VERSION 5.7 ;
  NOWIREEXTENSIONATPIN ON ;
  DIVIDERCHAR "/" ;
  BUSBITCHARS "[]" ;
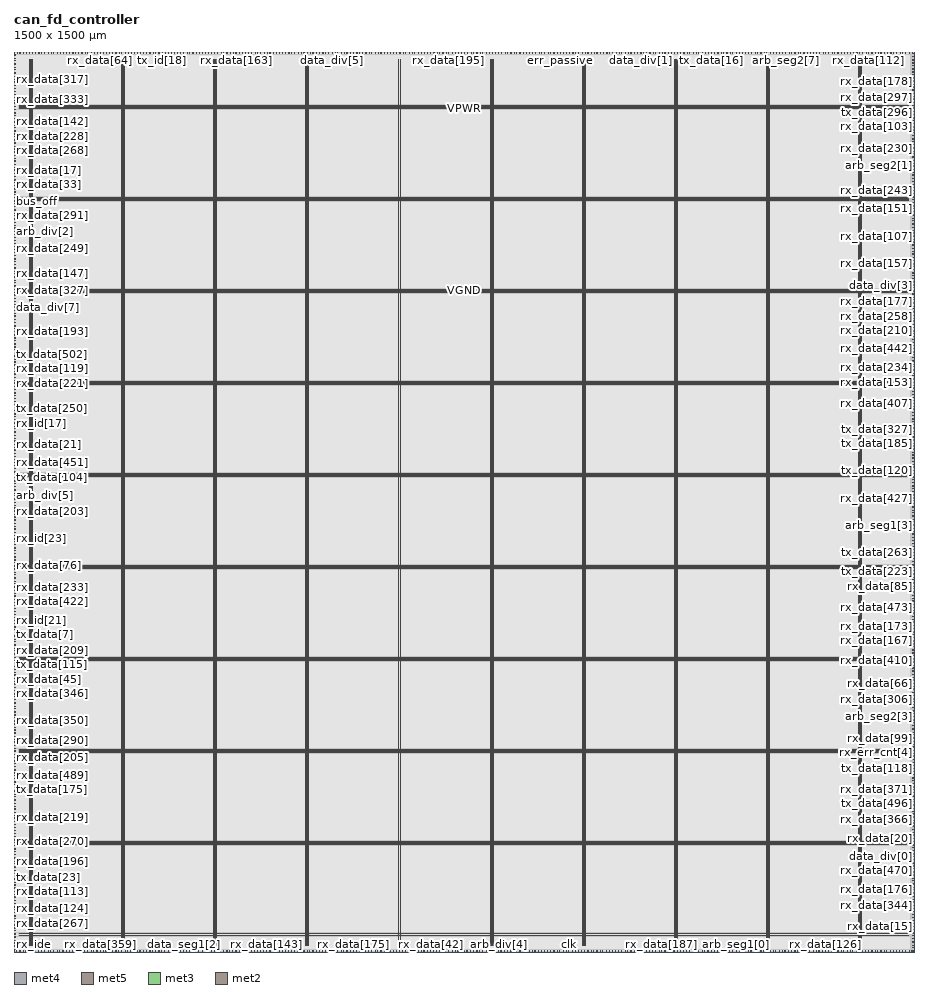
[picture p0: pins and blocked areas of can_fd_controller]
MACRO can_fd_controller
  CLASS BLOCK ;
  FOREIGN can_fd_controller ;
  ORIGIN 0.000 0.000 ;
  SIZE 1500.000 BY 1500.000 ;
  PIN VGND
    DIRECTION INOUT ;
    USE GROUND ;
    PORT
      LAYER met4 ;
        RECT 28.940 10.640 30.540 1488.080 ;
    END
    PORT
      LAYER met4 ;
        RECT 182.540 10.640 184.140 1488.080 ;
    END
    PORT
      LAYER met4 ;
        RECT 336.140 10.640 337.740 1488.080 ;
    END
    PORT
      LAYER met4 ;
        RECT 489.740 10.640 491.340 1488.080 ;
    END
    PORT
      LAYER met4 ;
        RECT 643.340 10.640 644.940 1488.080 ;
    END
    PORT
      LAYER met4 ;
        RECT 796.940 10.640 798.540 1488.080 ;
    END
    PORT
      LAYER met4 ;
        RECT 950.540 10.640 952.140 1488.080 ;
    END
    PORT
      LAYER met4 ;
        RECT 1104.140 10.640 1105.740 1488.080 ;
    END
    PORT
      LAYER met4 ;
        RECT 1257.740 10.640 1259.340 1488.080 ;
    END
    PORT
      LAYER met4 ;
        RECT 1411.340 10.640 1412.940 1488.080 ;
    END
    PORT
      LAYER met5 ;
        RECT 9.880 30.030 1490.180 31.630 ;
    END
    PORT
      LAYER met5 ;
        RECT 9.880 183.210 1490.180 184.810 ;
    END
    PORT
      LAYER met5 ;
        RECT 9.880 336.390 1490.180 337.990 ;
    END
    PORT
      LAYER met5 ;
        RECT 9.880 489.570 1490.180 491.170 ;
    END
    PORT
      LAYER met5 ;
        RECT 9.880 642.750 1490.180 644.350 ;
    END
    PORT
      LAYER met5 ;
        RECT 9.880 795.930 1490.180 797.530 ;
    END
    PORT
      LAYER met5 ;
        RECT 9.880 949.110 1490.180 950.710 ;
    END
    PORT
      LAYER met5 ;
        RECT 9.880 1102.290 1490.180 1103.890 ;
    END
    PORT
      LAYER met5 ;
        RECT 9.880 1255.470 1490.180 1257.070 ;
    END
    PORT
      LAYER met5 ;
        RECT 9.880 1408.650 1490.180 1410.250 ;
    END
  END VGND
  PIN VPWR
    DIRECTION INOUT ;
    USE POWER ;
    PORT
      LAYER met4 ;
        RECT 25.640 10.640 27.240 1488.080 ;
    END
    PORT
      LAYER met4 ;
        RECT 179.240 10.640 180.840 1488.080 ;
    END
    PORT
      LAYER met4 ;
        RECT 332.840 10.640 334.440 1488.080 ;
    END
    PORT
      LAYER met4 ;
        RECT 486.440 10.640 488.040 1488.080 ;
    END
    PORT
      LAYER met4 ;
        RECT 640.040 10.640 641.640 1488.080 ;
    END
    PORT
      LAYER met4 ;
        RECT 793.640 10.640 795.240 1488.080 ;
    END
    PORT
      LAYER met4 ;
        RECT 947.240 10.640 948.840 1488.080 ;
    END
    PORT
      LAYER met4 ;
        RECT 1100.840 10.640 1102.440 1488.080 ;
    END
    PORT
      LAYER met4 ;
        RECT 1254.440 10.640 1256.040 1488.080 ;
    END
    PORT
      LAYER met4 ;
        RECT 1408.040 10.640 1409.640 1488.080 ;
    END
    PORT
      LAYER met5 ;
        RECT 9.880 26.730 1490.180 28.330 ;
    END
    PORT
      LAYER met5 ;
        RECT 9.880 179.910 1490.180 181.510 ;
    END
    PORT
      LAYER met5 ;
        RECT 9.880 333.090 1490.180 334.690 ;
    END
    PORT
      LAYER met5 ;
        RECT 9.880 486.270 1490.180 487.870 ;
    END
    PORT
      LAYER met5 ;
        RECT 9.880 639.450 1490.180 641.050 ;
    END
    PORT
      LAYER met5 ;
        RECT 9.880 792.630 1490.180 794.230 ;
    END
    PORT
      LAYER met5 ;
        RECT 9.880 945.810 1490.180 947.410 ;
    END
    PORT
      LAYER met5 ;
        RECT 9.880 1098.990 1490.180 1100.590 ;
    END
    PORT
      LAYER met5 ;
        RECT 9.880 1252.170 1490.180 1253.770 ;
    END
    PORT
      LAYER met5 ;
        RECT 9.880 1405.350 1490.180 1406.950 ;
    END
  END VPWR
  PIN arb_div[0]
    DIRECTION INPUT ;
    USE SIGNAL ;
    ANTENNAGATEAREA 0.196500 ;
    PORT
      LAYER met3 ;
        RECT 1498.000 828.280 1500.000 828.880 ;
    END
  END arb_div[0]
  PIN arb_div[1]
    DIRECTION INPUT ;
    USE SIGNAL ;
    ANTENNAGATEAREA 0.990000 ;
    PORT
      LAYER met3 ;
        RECT 1498.000 1218.600 1500.000 1219.200 ;
    END
  END arb_div[1]
  PIN arb_div[2]
    DIRECTION INPUT ;
    USE SIGNAL ;
    ANTENNAGATEAREA 0.247500 ;
    PORT
      LAYER met3 ;
        RECT 0.000 1200.920 2.000 1201.520 ;
    END
  END arb_div[2]
  PIN arb_div[3]
    DIRECTION INPUT ;
    USE SIGNAL ;
    ANTENNAGATEAREA 0.495000 ;
    PORT
      LAYER met2 ;
        RECT 231.930 1498.000 232.210 1500.000 ;
    END
  END arb_div[3]
  PIN arb_div[4]
    DIRECTION INPUT ;
    USE SIGNAL ;
    ANTENNAGATEAREA 0.990000 ;
    PORT
      LAYER met2 ;
        RECT 807.390 0.000 807.670 2.000 ;
    END
  END arb_div[4]
  PIN arb_div[5]
    DIRECTION INPUT ;
    USE SIGNAL ;
    ANTENNAGATEAREA 0.159000 ;
    PORT
      LAYER met3 ;
        RECT 0.000 760.280 2.000 760.880 ;
    END
  END arb_div[5]
  PIN arb_div[6]
    DIRECTION INPUT ;
    USE SIGNAL ;
    ANTENNAGATEAREA 0.213000 ;
    PORT
      LAYER met3 ;
        RECT 0.000 572.600 2.000 573.200 ;
    END
  END arb_div[6]
  PIN arb_div[7]
    DIRECTION INPUT ;
    USE SIGNAL ;
    ANTENNAGATEAREA 0.742500 ;
    PORT
      LAYER met3 ;
        RECT 1498.000 640.600 1500.000 641.200 ;
    END
  END arb_div[7]
  PIN arb_seg1[0]
    DIRECTION INPUT ;
    USE SIGNAL ;
    ANTENNAGATEAREA 0.990000 ;
    PORT
      LAYER met2 ;
        RECT 1203.450 0.000 1203.730 2.000 ;
    END
  END arb_seg1[0]
  PIN arb_seg1[1]
    DIRECTION INPUT ;
    USE SIGNAL ;
    ANTENNAGATEAREA 0.247500 ;
    PORT
      LAYER met3 ;
        RECT 0.000 349.560 2.000 350.160 ;
    END
  END arb_seg1[1]
  PIN arb_seg1[2]
    DIRECTION INPUT ;
    USE SIGNAL ;
    ANTENNAGATEAREA 0.742500 ;
    PORT
      LAYER met2 ;
        RECT 888.810 0.000 889.090 2.000 ;
    END
  END arb_seg1[2]
  PIN arb_seg1[3]
    DIRECTION INPUT ;
    USE SIGNAL ;
    ANTENNAGATEAREA 0.742500 ;
    PORT
      LAYER met3 ;
        RECT 1498.000 711.320 1500.000 711.920 ;
    END
  END arb_seg1[3]
  PIN arb_seg1[4]
    DIRECTION INPUT ;
    USE SIGNAL ;
    ANTENNAGATEAREA 0.159000 ;
    PORT
      LAYER met3 ;
        RECT 0.000 1221.320 2.000 1221.920 ;
    END
  END arb_seg1[4]
  PIN arb_seg1[5]
    DIRECTION INPUT ;
    USE SIGNAL ;
    ANTENNAGATEAREA 0.213000 ;
    PORT
      LAYER met3 ;
        RECT 0.000 567.160 2.000 567.760 ;
    END
  END arb_seg1[5]
  PIN arb_seg1[6]
    DIRECTION INPUT ;
    USE SIGNAL ;
    ANTENNAGATEAREA 0.990000 ;
    PORT
      LAYER met2 ;
        RECT 822.570 0.000 822.850 2.000 ;
    END
  END arb_seg1[6]
  PIN arb_seg1[7]
    DIRECTION INPUT ;
    USE SIGNAL ;
    ANTENNAGATEAREA 0.990000 ;
    PORT
      LAYER met2 ;
        RECT 1188.270 0.000 1188.550 2.000 ;
    END
  END arb_seg1[7]
  PIN arb_seg2[0]
    DIRECTION INPUT ;
    USE SIGNAL ;
    PORT
      LAYER met2 ;
        RECT 781.170 1498.000 781.450 1500.000 ;
    END
  END arb_seg2[0]
  PIN arb_seg2[1]
    DIRECTION INPUT ;
    USE SIGNAL ;
    PORT
      LAYER met3 ;
        RECT 1498.000 1309.720 1500.000 1310.320 ;
    END
  END arb_seg2[1]
  PIN arb_seg2[2]
    DIRECTION INPUT ;
    USE SIGNAL ;
    PORT
      LAYER met2 ;
        RECT 1228.290 0.000 1228.570 2.000 ;
    END
  END arb_seg2[2]
  PIN arb_seg2[3]
    DIRECTION INPUT ;
    USE SIGNAL ;
    PORT
      LAYER met3 ;
        RECT 1498.000 391.720 1500.000 392.320 ;
    END
  END arb_seg2[3]
  PIN arb_seg2[4]
    DIRECTION INPUT ;
    USE SIGNAL ;
    PORT
      LAYER met3 ;
        RECT 1498.000 1172.360 1500.000 1172.960 ;
    END
  END arb_seg2[4]
  PIN arb_seg2[5]
    DIRECTION INPUT ;
    USE SIGNAL ;
    PORT
      LAYER met2 ;
        RECT 992.310 1498.000 992.590 1500.000 ;
    END
  END arb_seg2[5]
  PIN arb_seg2[6]
    DIRECTION INPUT ;
    USE SIGNAL ;
    PORT
      LAYER met2 ;
        RECT 358.890 0.000 359.170 2.000 ;
    END
  END arb_seg2[6]
  PIN arb_seg2[7]
    DIRECTION INPUT ;
    USE SIGNAL ;
    PORT
      LAYER met2 ;
        RECT 1286.250 1498.000 1286.530 1500.000 ;
    END
  END arb_seg2[7]
  PIN bus_off
    DIRECTION OUTPUT TRISTATE ;
    USE SIGNAL ;
    PORT
      LAYER met3 ;
        RECT 0.000 1251.240 2.000 1251.840 ;
    END
  END bus_off
  PIN can_rx
    DIRECTION INPUT ;
    USE SIGNAL ;
    ANTENNAGATEAREA 0.852000 ;
    PORT
      LAYER met2 ;
        RECT 956.430 0.000 956.710 2.000 ;
    END
  END can_rx
  PIN can_tx
    DIRECTION OUTPUT TRISTATE ;
    USE SIGNAL ;
    ANTENNADIFFAREA 0.795200 ;
    PORT
      LAYER met2 ;
        RECT 1265.550 0.000 1265.830 2.000 ;
    END
  END can_tx
  PIN clk
    DIRECTION INPUT ;
    USE SIGNAL ;
    ANTENNAGATEAREA 0.852000 ;
    PORT
      LAYER met2 ;
        RECT 924.690 0.000 924.970 2.000 ;
    END
  END clk
  PIN data_div[0]
    DIRECTION INPUT ;
    USE SIGNAL ;
    ANTENNAGATEAREA 0.247500 ;
    PORT
      LAYER met3 ;
        RECT 1498.000 159.160 1500.000 159.760 ;
    END
  END data_div[0]
  PIN data_div[1]
    DIRECTION INPUT ;
    USE SIGNAL ;
    ANTENNAGATEAREA 0.990000 ;
    PORT
      LAYER met2 ;
        RECT 1044.750 1498.000 1045.030 1500.000 ;
    END
  END data_div[1]
  PIN data_div[2]
    DIRECTION INPUT ;
    USE SIGNAL ;
    ANTENNAGATEAREA 0.426000 ;
    PORT
      LAYER met3 ;
        RECT 0.000 1398.120 2.000 1398.720 ;
    END
  END data_div[2]
  PIN data_div[3]
    DIRECTION INPUT ;
    USE SIGNAL ;
    ANTENNAGATEAREA 0.990000 ;
    PORT
      LAYER met3 ;
        RECT 1498.000 1111.160 1500.000 1111.760 ;
    END
  END data_div[3]
  PIN data_div[4]
    DIRECTION INPUT ;
    USE SIGNAL ;
    ANTENNAGATEAREA 0.213000 ;
    PORT
      LAYER met3 ;
        RECT 0.000 1007.800 2.000 1008.400 ;
    END
  END data_div[4]
  PIN data_div[5]
    DIRECTION INPUT ;
    USE SIGNAL ;
    ANTENNAGATEAREA 0.742500 ;
    PORT
      LAYER met2 ;
        RECT 530.010 1498.000 530.290 1500.000 ;
    END
  END data_div[5]
  PIN data_div[6]
    DIRECTION INPUT ;
    USE SIGNAL ;
    ANTENNAGATEAREA 0.990000 ;
    PORT
      LAYER met3 ;
        RECT 1498.000 1066.280 1500.000 1066.880 ;
    END
  END data_div[6]
  PIN data_div[7]
    DIRECTION INPUT ;
    USE SIGNAL ;
    ANTENNAGATEAREA 0.247500 ;
    PORT
      LAYER met3 ;
        RECT 0.000 1074.440 2.000 1075.040 ;
    END
  END data_div[7]
  PIN data_seg1[0]
    DIRECTION INPUT ;
    USE SIGNAL ;
    ANTENNAGATEAREA 0.213000 ;
    PORT
      LAYER met3 ;
        RECT 0.000 840.520 2.000 841.120 ;
    END
  END data_seg1[0]
  PIN data_seg1[1]
    DIRECTION INPUT ;
    USE SIGNAL ;
    ANTENNAGATEAREA 0.990000 ;
    PORT
      LAYER met2 ;
        RECT 1393.890 1498.000 1394.170 1500.000 ;
    END
  END data_seg1[1]
  PIN data_seg1[2]
    DIRECTION INPUT ;
    USE SIGNAL ;
    ANTENNAGATEAREA 0.426000 ;
    PORT
      LAYER met2 ;
        RECT 282.990 0.000 283.270 2.000 ;
    END
  END data_seg1[2]
  PIN data_seg1[3]
    DIRECTION INPUT ;
    USE SIGNAL ;
    ANTENNAGATEAREA 0.990000 ;
    PORT
      LAYER met2 ;
        RECT 1373.190 1498.000 1373.470 1500.000 ;
    END
  END data_seg1[3]
  PIN data_seg1[4]
    DIRECTION INPUT ;
    USE SIGNAL ;
    ANTENNAGATEAREA 0.213000 ;
    PORT
      LAYER met2 ;
        RECT 509.310 1498.000 509.590 1500.000 ;
    END
  END data_seg1[4]
  PIN data_seg1[5]
    DIRECTION INPUT ;
    USE SIGNAL ;
    ANTENNAGATEAREA 0.159000 ;
    PORT
      LAYER met3 ;
        RECT 0.000 1119.320 2.000 1119.920 ;
    END
  END data_seg1[5]
  PIN data_seg1[6]
    DIRECTION INPUT ;
    USE SIGNAL ;
    ANTENNAGATEAREA 0.495000 ;
    PORT
      LAYER met2 ;
        RECT 158.790 1498.000 159.070 1500.000 ;
    END
  END data_seg1[6]
  PIN data_seg1[7]
    DIRECTION INPUT ;
    USE SIGNAL ;
    ANTENNAGATEAREA 0.990000 ;
    PORT
      LAYER met3 ;
        RECT 1498.000 341.400 1500.000 342.000 ;
    END
  END data_seg1[7]
  PIN data_seg2[0]
    DIRECTION INPUT ;
    USE SIGNAL ;
    PORT
      LAYER met2 ;
        RECT 71.850 1498.000 72.130 1500.000 ;
    END
  END data_seg2[0]
  PIN data_seg2[1]
    DIRECTION INPUT ;
    USE SIGNAL ;
    PORT
      LAYER met2 ;
        RECT 138.090 0.000 138.370 2.000 ;
    END
  END data_seg2[1]
  PIN data_seg2[2]
    DIRECTION INPUT ;
    USE SIGNAL ;
    PORT
      LAYER met3 ;
        RECT 1498.000 1477.000 1500.000 1477.600 ;
    END
  END data_seg2[2]
  PIN data_seg2[3]
    DIRECTION INPUT ;
    USE SIGNAL ;
    PORT
      LAYER met3 ;
        RECT 0.000 1210.440 2.000 1211.040 ;
    END
  END data_seg2[3]
  PIN data_seg2[4]
    DIRECTION INPUT ;
    USE SIGNAL ;
    PORT
      LAYER met3 ;
        RECT 0.000 1277.080 2.000 1277.680 ;
    END
  END data_seg2[4]
  PIN data_seg2[5]
    DIRECTION INPUT ;
    USE SIGNAL ;
    PORT
      LAYER met3 ;
        RECT 0.000 1485.160 2.000 1485.760 ;
    END
  END data_seg2[5]
  PIN data_seg2[6]
    DIRECTION INPUT ;
    USE SIGNAL ;
    PORT
      LAYER met2 ;
        RECT 607.290 1498.000 607.570 1500.000 ;
    END
  END data_seg2[6]
  PIN data_seg2[7]
    DIRECTION INPUT ;
    USE SIGNAL ;
    PORT
      LAYER met2 ;
        RECT 909.510 0.000 909.790 2.000 ;
    END
  END data_seg2[7]
  PIN err_passive
    DIRECTION OUTPUT TRISTATE ;
    USE SIGNAL ;
    ANTENNADIFFAREA 0.795200 ;
    PORT
      LAYER met2 ;
        RECT 910.890 1498.000 911.170 1500.000 ;
    END
  END err_passive
  PIN err_warning
    DIRECTION OUTPUT TRISTATE ;
    USE SIGNAL ;
    ANTENNADIFFAREA 0.795200 ;
    PORT
      LAYER met3 ;
        RECT 1498.000 27.240 1500.000 27.840 ;
    END
  END err_warning
  PIN rst_n
    DIRECTION INPUT ;
    USE SIGNAL ;
    ANTENNAGATEAREA 0.213000 ;
    PORT
      LAYER met3 ;
        RECT 1498.000 690.920 1500.000 691.520 ;
    END
  END rst_n
  PIN rx_ack
    DIRECTION INPUT ;
    USE SIGNAL ;
    ANTENNAGATEAREA 0.990000 ;
    PORT
      LAYER met2 ;
        RECT 884.670 0.000 884.950 2.000 ;
    END
  END rx_ack
  PIN rx_brs
    DIRECTION OUTPUT TRISTATE ;
    USE SIGNAL ;
    ANTENNADIFFAREA 0.795200 ;
    PORT
      LAYER met2 ;
        RECT 154.650 1498.000 154.930 1500.000 ;
    END
  END rx_brs
  PIN rx_busy
    DIRECTION OUTPUT TRISTATE ;
    USE SIGNAL ;
    ANTENNADIFFAREA 0.795200 ;
    PORT
      LAYER met2 ;
        RECT 524.490 1498.000 524.770 1500.000 ;
    END
  END rx_busy
  PIN rx_data[0]
    DIRECTION OUTPUT TRISTATE ;
    USE SIGNAL ;
    ANTENNADIFFAREA 0.795200 ;
    PORT
      LAYER met2 ;
        RECT 1348.350 1498.000 1348.630 1500.000 ;
    END
  END rx_data[0]
  PIN rx_data[100]
    DIRECTION OUTPUT TRISTATE ;
    USE SIGNAL ;
    ANTENNADIFFAREA 0.795200 ;
    PORT
      LAYER met2 ;
        RECT 817.050 0.000 817.330 2.000 ;
    END
  END rx_data[100]
  PIN rx_data[101]
    DIRECTION OUTPUT TRISTATE ;
    USE SIGNAL ;
    ANTENNADIFFAREA 0.795200 ;
    PORT
      LAYER met2 ;
        RECT 754.950 0.000 755.230 2.000 ;
    END
  END rx_data[101]
  PIN rx_data[102]
    DIRECTION OUTPUT TRISTATE ;
    USE SIGNAL ;
    ANTENNADIFFAREA 0.795200 ;
    PORT
      LAYER met3 ;
        RECT 1498.000 908.520 1500.000 909.120 ;
    END
  END rx_data[102]
  PIN rx_data[103]
    DIRECTION OUTPUT TRISTATE ;
    USE SIGNAL ;
    ANTENNADIFFAREA 0.795200 ;
    PORT
      LAYER met3 ;
        RECT 1498.000 1375.000 1500.000 1375.600 ;
    END
  END rx_data[103]
  PIN rx_data[104]
    DIRECTION OUTPUT TRISTATE ;
    USE SIGNAL ;
    ANTENNADIFFAREA 0.795200 ;
    PORT
      LAYER met2 ;
        RECT 1001.970 0.000 1002.250 2.000 ;
    END
  END rx_data[104]
  PIN rx_data[105]
    DIRECTION OUTPUT TRISTATE ;
    USE SIGNAL ;
    ANTENNADIFFAREA 0.795200 ;
    PORT
      LAYER met3 ;
        RECT 0.000 896.280 2.000 896.880 ;
    END
  END rx_data[105]
  PIN rx_data[106]
    DIRECTION OUTPUT TRISTATE ;
    USE SIGNAL ;
    ANTENNADIFFAREA 0.795200 ;
    PORT
      LAYER met2 ;
        RECT 854.310 1498.000 854.590 1500.000 ;
    END
  END rx_data[106]
  PIN rx_data[107]
    DIRECTION OUTPUT TRISTATE ;
    USE SIGNAL ;
    ANTENNADIFFAREA 0.795200 ;
    PORT
      LAYER met3 ;
        RECT 1498.000 1192.760 1500.000 1193.360 ;
    END
  END rx_data[107]
  PIN rx_data[108]
    DIRECTION OUTPUT TRISTATE ;
    USE SIGNAL ;
    ANTENNADIFFAREA 0.795200 ;
    PORT
      LAYER met3 ;
        RECT 0.000 916.680 2.000 917.280 ;
    END
  END rx_data[108]
  PIN rx_data[109]
    DIRECTION OUTPUT TRISTATE ;
    USE SIGNAL ;
    ANTENNADIFFAREA 0.795200 ;
    PORT
      LAYER met3 ;
        RECT 1498.000 87.080 1500.000 87.680 ;
    END
  END rx_data[109]
  PIN rx_data[10]
    DIRECTION OUTPUT TRISTATE ;
    USE SIGNAL ;
    ANTENNADIFFAREA 0.795200 ;
    PORT
      LAYER met2 ;
        RECT 714.930 0.000 715.210 2.000 ;
    END
  END rx_data[10]
  PIN rx_data[110]
    DIRECTION OUTPUT TRISTATE ;
    USE SIGNAL ;
    ANTENNADIFFAREA 0.795200 ;
    PORT
      LAYER met2 ;
        RECT 1384.230 1498.000 1384.510 1500.000 ;
    END
  END rx_data[110]
  PIN rx_data[111]
    DIRECTION OUTPUT TRISTATE ;
    USE SIGNAL ;
    ANTENNADIFFAREA 0.795200 ;
    PORT
      LAYER met2 ;
        RECT 560.370 1498.000 560.650 1500.000 ;
    END
  END rx_data[111]
  PIN rx_data[112]
    DIRECTION OUTPUT TRISTATE ;
    USE SIGNAL ;
    ANTENNADIFFAREA 0.795200 ;
    PORT
      LAYER met2 ;
        RECT 1424.250 1498.000 1424.530 1500.000 ;
    END
  END rx_data[112]
  PIN rx_data[113]
    DIRECTION OUTPUT TRISTATE ;
    USE SIGNAL ;
    ANTENNADIFFAREA 0.795200 ;
    PORT
      LAYER met3 ;
        RECT 0.000 100.680 2.000 101.280 ;
    END
  END rx_data[113]
  PIN rx_data[114]
    DIRECTION OUTPUT TRISTATE ;
    USE SIGNAL ;
    ANTENNADIFFAREA 0.795200 ;
    PORT
      LAYER met2 ;
        RECT 1024.050 1498.000 1024.330 1500.000 ;
    END
  END rx_data[114]
  PIN rx_data[115]
    DIRECTION OUTPUT TRISTATE ;
    USE SIGNAL ;
    ANTENNADIFFAREA 0.795200 ;
    PORT
      LAYER met3 ;
        RECT 1498.000 457.000 1500.000 457.600 ;
    END
  END rx_data[115]
  PIN rx_data[116]
    DIRECTION OUTPUT TRISTATE ;
    USE SIGNAL ;
    ANTENNADIFFAREA 0.795200 ;
    PORT
      LAYER met2 ;
        RECT 1486.350 1498.000 1486.630 1500.000 ;
    END
  END rx_data[116]
  PIN rx_data[117]
    DIRECTION OUTPUT TRISTATE ;
    USE SIGNAL ;
    ANTENNADIFFAREA 0.795200 ;
    PORT
      LAYER met3 ;
        RECT 1498.000 122.440 1500.000 123.040 ;
    END
  END rx_data[117]
  PIN rx_data[118]
    DIRECTION OUTPUT TRISTATE ;
    USE SIGNAL ;
    ANTENNADIFFAREA 0.795200 ;
    PORT
      LAYER met2 ;
        RECT 209.850 0.000 210.130 2.000 ;
    END
  END rx_data[118]
  PIN rx_data[119]
    DIRECTION OUTPUT TRISTATE ;
    USE SIGNAL ;
    ANTENNADIFFAREA 0.795200 ;
    PORT
      LAYER met3 ;
        RECT 0.000 972.440 2.000 973.040 ;
    END
  END rx_data[119]
  PIN rx_data[11]
    DIRECTION OUTPUT TRISTATE ;
    USE SIGNAL ;
    ANTENNADIFFAREA 0.795200 ;
    PORT
      LAYER met2 ;
        RECT 277.470 0.000 277.750 2.000 ;
    END
  END rx_data[11]
  PIN rx_data[120]
    DIRECTION OUTPUT TRISTATE ;
    USE SIGNAL ;
    ANTENNADIFFAREA 0.795200 ;
    PORT
      LAYER met3 ;
        RECT 0.000 907.160 2.000 907.760 ;
    END
  END rx_data[120]
  PIN rx_data[121]
    DIRECTION OUTPUT TRISTATE ;
    USE SIGNAL ;
    ANTENNADIFFAREA 0.795200 ;
    PORT
      LAYER met3 ;
        RECT 0.000 29.960 2.000 30.560 ;
    END
  END rx_data[121]
  PIN rx_data[122]
    DIRECTION OUTPUT TRISTATE ;
    USE SIGNAL ;
    ANTENNADIFFAREA 0.795200 ;
    PORT
      LAYER met2 ;
        RECT 1461.510 1498.000 1461.790 1500.000 ;
    END
  END rx_data[122]
  PIN rx_data[123]
    DIRECTION OUTPUT TRISTATE ;
    USE SIGNAL ;
    ANTENNADIFFAREA 0.795200 ;
    PORT
      LAYER met2 ;
        RECT 1316.610 0.000 1316.890 2.000 ;
    END
  END rx_data[123]
  PIN rx_data[124]
    DIRECTION OUTPUT TRISTATE ;
    USE SIGNAL ;
    ANTENNADIFFAREA 0.795200 ;
    PORT
      LAYER met3 ;
        RECT 0.000 85.720 2.000 86.320 ;
    END
  END rx_data[124]
  PIN rx_data[125]
    DIRECTION OUTPUT TRISTATE ;
    USE SIGNAL ;
    ANTENNADIFFAREA 0.795200 ;
    PORT
      LAYER met3 ;
        RECT 1498.000 153.720 1500.000 154.320 ;
    END
  END rx_data[125]
  PIN rx_data[126]
    DIRECTION OUTPUT TRISTATE ;
    USE SIGNAL ;
    ANTENNADIFFAREA 0.795200 ;
    PORT
      LAYER met2 ;
        RECT 1352.490 0.000 1352.770 2.000 ;
    END
  END rx_data[126]
  PIN rx_data[127]
    DIRECTION OUTPUT TRISTATE ;
    USE SIGNAL ;
    ANTENNADIFFAREA 0.795200 ;
    PORT
      LAYER met3 ;
        RECT 1498.000 787.480 1500.000 788.080 ;
    END
  END rx_data[127]
  PIN rx_data[128]
    DIRECTION OUTPUT TRISTATE ;
    USE SIGNAL ;
    ANTENNADIFFAREA 0.795200 ;
    PORT
      LAYER met3 ;
        RECT 0.000 557.640 2.000 558.240 ;
    END
  END rx_data[128]
  PIN rx_data[129]
    DIRECTION OUTPUT TRISTATE ;
    USE SIGNAL ;
    ANTENNADIFFAREA 0.795200 ;
    PORT
      LAYER met2 ;
        RECT 1028.190 1498.000 1028.470 1500.000 ;
    END
  END rx_data[129]
  PIN rx_data[12]
    DIRECTION OUTPUT TRISTATE ;
    USE SIGNAL ;
    ANTENNADIFFAREA 0.795200 ;
    PORT
      LAYER met2 ;
        RECT 0.090 1498.000 0.370 1500.000 ;
    END
  END rx_data[12]
  PIN rx_data[130]
    DIRECTION OUTPUT TRISTATE ;
    USE SIGNAL ;
    ANTENNADIFFAREA 0.795200 ;
    PORT
      LAYER met3 ;
        RECT 1498.000 285.640 1500.000 286.240 ;
    END
  END rx_data[130]
  PIN rx_data[131]
    DIRECTION OUTPUT TRISTATE ;
    USE SIGNAL ;
    ANTENNADIFFAREA 0.795200 ;
    PORT
      LAYER met3 ;
        RECT 0.000 652.840 2.000 653.440 ;
    END
  END rx_data[131]
  PIN rx_data[132]
    DIRECTION OUTPUT TRISTATE ;
    USE SIGNAL ;
    ANTENNADIFFAREA 0.795200 ;
    PORT
      LAYER met2 ;
        RECT 796.350 0.000 796.630 2.000 ;
    END
  END rx_data[132]
  PIN rx_data[133]
    DIRECTION OUTPUT TRISTATE ;
    USE SIGNAL ;
    ANTENNADIFFAREA 0.795200 ;
    PORT
      LAYER met2 ;
        RECT 1429.770 0.000 1430.050 2.000 ;
    END
  END rx_data[133]
  PIN rx_data[134]
    DIRECTION OUTPUT TRISTATE ;
    USE SIGNAL ;
    ANTENNADIFFAREA 0.795200 ;
    PORT
      LAYER met3 ;
        RECT 1498.000 1466.120 1500.000 1466.720 ;
    END
  END rx_data[134]
  PIN rx_data[135]
    DIRECTION OUTPUT TRISTATE ;
    USE SIGNAL ;
    ANTENNADIFFAREA 0.795200 ;
    PORT
      LAYER met2 ;
        RECT 698.370 0.000 698.650 2.000 ;
    END
  END rx_data[135]
  PIN rx_data[136]
    DIRECTION OUTPUT TRISTATE ;
    USE SIGNAL ;
    ANTENNADIFFAREA 0.795200 ;
    PORT
      LAYER met2 ;
        RECT 1182.750 1498.000 1183.030 1500.000 ;
    END
  END rx_data[136]
  PIN rx_data[137]
    DIRECTION OUTPUT TRISTATE ;
    USE SIGNAL ;
    ANTENNADIFFAREA 0.795200 ;
    PORT
      LAYER met3 ;
        RECT 0.000 1342.360 2.000 1342.960 ;
    END
  END rx_data[137]
  PIN rx_data[138]
    DIRECTION OUTPUT TRISTATE ;
    USE SIGNAL ;
    ANTENNADIFFAREA 0.795200 ;
    PORT
      LAYER met2 ;
        RECT 1101.330 1498.000 1101.610 1500.000 ;
    END
  END rx_data[138]
  PIN rx_data[139]
    DIRECTION OUTPUT TRISTATE ;
    USE SIGNAL ;
    ANTENNADIFFAREA 0.795200 ;
    PORT
      LAYER met3 ;
        RECT 1498.000 1274.360 1500.000 1274.960 ;
    END
  END rx_data[139]
  PIN rx_data[13]
    DIRECTION OUTPUT TRISTATE ;
    USE SIGNAL ;
    ANTENNADIFFAREA 0.795200 ;
    PORT
      LAYER met2 ;
        RECT 467.910 1498.000 468.190 1500.000 ;
    END
  END rx_data[13]
  PIN rx_data[140]
    DIRECTION OUTPUT TRISTATE ;
    USE SIGNAL ;
    ANTENNADIFFAREA 0.795200 ;
    PORT
      LAYER met2 ;
        RECT 1167.570 1498.000 1167.850 1500.000 ;
    END
  END rx_data[140]
  PIN rx_data[141]
    DIRECTION OUTPUT TRISTATE ;
    USE SIGNAL ;
    ANTENNADIFFAREA 0.795200 ;
    PORT
      LAYER met3 ;
        RECT 0.000 1165.560 2.000 1166.160 ;
    END
  END rx_data[141]
  PIN rx_data[142]
    DIRECTION OUTPUT TRISTATE ;
    USE SIGNAL ;
    ANTENNADIFFAREA 0.795200 ;
    PORT
      LAYER met3 ;
        RECT 0.000 1383.160 2.000 1383.760 ;
    END
  END rx_data[142]
  PIN rx_data[143]
    DIRECTION OUTPUT TRISTATE ;
    USE SIGNAL ;
    ANTENNADIFFAREA 0.795200 ;
    PORT
      LAYER met2 ;
        RECT 420.990 0.000 421.270 2.000 ;
    END
  END rx_data[143]
  PIN rx_data[144]
    DIRECTION OUTPUT TRISTATE ;
    USE SIGNAL ;
    ANTENNADIFFAREA 0.795200 ;
    PORT
      LAYER met3 ;
        RECT 1498.000 274.760 1500.000 275.360 ;
    END
  END rx_data[144]
  PIN rx_data[145]
    DIRECTION OUTPUT TRISTATE ;
    USE SIGNAL ;
    ANTENNADIFFAREA 0.795200 ;
    PORT
      LAYER met3 ;
        RECT 1498.000 1187.320 1500.000 1187.920 ;
    END
  END rx_data[145]
  PIN rx_data[146]
    DIRECTION OUTPUT TRISTATE ;
    USE SIGNAL ;
    ANTENNADIFFAREA 0.795200 ;
    PORT
      LAYER met3 ;
        RECT 0.000 409.400 2.000 410.000 ;
    END
  END rx_data[146]
  PIN rx_data[147]
    DIRECTION OUTPUT TRISTATE ;
    USE SIGNAL ;
    ANTENNADIFFAREA 0.795200 ;
    PORT
      LAYER met3 ;
        RECT 0.000 1130.200 2.000 1130.800 ;
    END
  END rx_data[147]
  PIN rx_data[148]
    DIRECTION OUTPUT TRISTATE ;
    USE SIGNAL ;
    ANTENNADIFFAREA 0.795200 ;
    PORT
      LAYER met2 ;
        RECT 426.510 0.000 426.790 2.000 ;
    END
  END rx_data[148]
  PIN rx_data[149]
    DIRECTION OUTPUT TRISTATE ;
    USE SIGNAL ;
    ANTENNADIFFAREA 0.795200 ;
    PORT
      LAYER met3 ;
        RECT 1498.000 244.840 1500.000 245.440 ;
    END
  END rx_data[149]
  PIN rx_data[14]
    DIRECTION OUTPUT TRISTATE ;
    USE SIGNAL ;
    ANTENNADIFFAREA 0.795200 ;
    PORT
      LAYER met2 ;
        RECT 307.830 0.000 308.110 2.000 ;
    END
  END rx_data[14]
  PIN rx_data[150]
    DIRECTION OUTPUT TRISTATE ;
    USE SIGNAL ;
    ANTENNADIFFAREA 0.795200 ;
    PORT
      LAYER met3 ;
        RECT 1498.000 726.280 1500.000 726.880 ;
    END
  END rx_data[150]
  PIN rx_data[151]
    DIRECTION OUTPUT TRISTATE ;
    USE SIGNAL ;
    ANTENNADIFFAREA 0.795200 ;
    PORT
      LAYER met3 ;
        RECT 1498.000 1239.000 1500.000 1239.600 ;
    END
  END rx_data[151]
  PIN rx_data[152]
    DIRECTION OUTPUT TRISTATE ;
    USE SIGNAL ;
    ANTENNADIFFAREA 0.795200 ;
    PORT
      LAYER met3 ;
        RECT 0.000 405.320 2.000 405.920 ;
    END
  END rx_data[152]
  PIN rx_data[153]
    DIRECTION OUTPUT TRISTATE ;
    USE SIGNAL ;
    ANTENNADIFFAREA 0.795200 ;
    PORT
      LAYER met3 ;
        RECT 1498.000 949.320 1500.000 949.920 ;
    END
  END rx_data[153]
  PIN rx_data[154]
    DIRECTION OUTPUT TRISTATE ;
    USE SIGNAL ;
    ANTENNADIFFAREA 0.795200 ;
    PORT
      LAYER met3 ;
        RECT 0.000 511.400 2.000 512.000 ;
    END
  END rx_data[154]
  PIN rx_data[155]
    DIRECTION OUTPUT TRISTATE ;
    USE SIGNAL ;
    ANTENNADIFFAREA 0.795200 ;
    PORT
      LAYER met2 ;
        RECT 4.230 0.000 4.510 2.000 ;
    END
  END rx_data[155]
  PIN rx_data[156]
    DIRECTION OUTPUT TRISTATE ;
    USE SIGNAL ;
    ANTENNADIFFAREA 0.795200 ;
    PORT
      LAYER met3 ;
        RECT 0.000 505.960 2.000 506.560 ;
    END
  END rx_data[156]
  PIN rx_data[157]
    DIRECTION OUTPUT TRISTATE ;
    USE SIGNAL ;
    ANTENNADIFFAREA 0.795200 ;
    PORT
      LAYER met3 ;
        RECT 1498.000 1146.520 1500.000 1147.120 ;
    END
  END rx_data[157]
  PIN rx_data[158]
    DIRECTION OUTPUT TRISTATE ;
    USE SIGNAL ;
    ANTENNADIFFAREA 0.795200 ;
    PORT
      LAYER met2 ;
        RECT 765.990 0.000 766.270 2.000 ;
    END
  END rx_data[158]
  PIN rx_data[159]
    DIRECTION OUTPUT TRISTATE ;
    USE SIGNAL ;
    ANTENNADIFFAREA 0.795200 ;
    PORT
      LAYER met2 ;
        RECT 19.410 0.000 19.690 2.000 ;
    END
  END rx_data[159]
  PIN rx_data[15]
    DIRECTION OUTPUT TRISTATE ;
    USE SIGNAL ;
    ANTENNADIFFAREA 0.795200 ;
    PORT
      LAYER met3 ;
        RECT 1498.000 42.200 1500.000 42.800 ;
    END
  END rx_data[15]
  PIN rx_data[160]
    DIRECTION OUTPUT TRISTATE ;
    USE SIGNAL ;
    ANTENNADIFFAREA 0.795200 ;
    PORT
      LAYER met3 ;
        RECT 0.000 353.640 2.000 354.240 ;
    END
  END rx_data[160]
  PIN rx_data[161]
    DIRECTION OUTPUT TRISTATE ;
    USE SIGNAL ;
    ANTENNADIFFAREA 0.795200 ;
    PORT
      LAYER met3 ;
        RECT 0.000 44.920 2.000 45.520 ;
    END
  END rx_data[161]
  PIN rx_data[162]
    DIRECTION OUTPUT TRISTATE ;
    USE SIGNAL ;
    ANTENNADIFFAREA 0.795200 ;
    PORT
      LAYER met2 ;
        RECT 950.910 0.000 951.190 2.000 ;
    END
  END rx_data[162]
  PIN rx_data[163]
    DIRECTION OUTPUT TRISTATE ;
    USE SIGNAL ;
    ANTENNADIFFAREA 0.795200 ;
    PORT
      LAYER met2 ;
        RECT 369.930 1498.000 370.210 1500.000 ;
    END
  END rx_data[163]
  PIN rx_data[164]
    DIRECTION OUTPUT TRISTATE ;
    USE SIGNAL ;
    ANTENNADIFFAREA 0.795200 ;
    PORT
      LAYER met3 ;
        RECT 1498.000 512.760 1500.000 513.360 ;
    END
  END rx_data[164]
  PIN rx_data[165]
    DIRECTION OUTPUT TRISTATE ;
    USE SIGNAL ;
    ANTENNADIFFAREA 0.795200 ;
    PORT
      LAYER met3 ;
        RECT 0.000 810.600 2.000 811.200 ;
    END
  END rx_data[165]
  PIN rx_data[166]
    DIRECTION OUTPUT TRISTATE ;
    USE SIGNAL ;
    ANTENNADIFFAREA 0.795200 ;
    PORT
      LAYER met3 ;
        RECT 1498.000 1380.440 1500.000 1381.040 ;
    END
  END rx_data[166]
  PIN rx_data[167]
    DIRECTION OUTPUT TRISTATE ;
    USE SIGNAL ;
    ANTENNADIFFAREA 0.795200 ;
    PORT
      LAYER met3 ;
        RECT 1498.000 518.200 1500.000 518.800 ;
    END
  END rx_data[167]
  PIN rx_data[168]
    DIRECTION OUTPUT TRISTATE ;
    USE SIGNAL ;
    ANTENNADIFFAREA 0.795200 ;
    PORT
      LAYER met3 ;
        RECT 1498.000 254.360 1500.000 254.960 ;
    END
  END rx_data[168]
  PIN rx_data[169]
    DIRECTION OUTPUT TRISTATE ;
    USE SIGNAL ;
    ANTENNADIFFAREA 0.795200 ;
    PORT
      LAYER met2 ;
        RECT 411.330 0.000 411.610 2.000 ;
    END
  END rx_data[169]
  PIN rx_data[16]
    DIRECTION OUTPUT TRISTATE ;
    USE SIGNAL ;
    ANTENNADIFFAREA 0.795200 ;
    PORT
      LAYER met2 ;
        RECT 1295.910 1498.000 1296.190 1500.000 ;
    END
  END rx_data[16]
  PIN rx_data[170]
    DIRECTION OUTPUT TRISTATE ;
    USE SIGNAL ;
    ANTENNADIFFAREA 0.795200 ;
    PORT
      LAYER met2 ;
        RECT 518.970 1498.000 519.250 1500.000 ;
    END
  END rx_data[170]
  PIN rx_data[171]
    DIRECTION OUTPUT TRISTATE ;
    USE SIGNAL ;
    ANTENNADIFFAREA 0.795200 ;
    PORT
      LAYER met3 ;
        RECT 0.000 19.080 2.000 19.680 ;
    END
  END rx_data[171]
  PIN rx_data[172]
    DIRECTION OUTPUT TRISTATE ;
    USE SIGNAL ;
    ANTENNADIFFAREA 0.795200 ;
    PORT
      LAYER met3 ;
        RECT 0.000 927.560 2.000 928.160 ;
    END
  END rx_data[172]
  PIN rx_data[173]
    DIRECTION OUTPUT TRISTATE ;
    USE SIGNAL ;
    ANTENNADIFFAREA 0.795200 ;
    PORT
      LAYER met3 ;
        RECT 1498.000 529.080 1500.000 529.680 ;
    END
  END rx_data[173]
  PIN rx_data[174]
    DIRECTION OUTPUT TRISTATE ;
    USE SIGNAL ;
    ANTENNADIFFAREA 0.795200 ;
    PORT
      LAYER met3 ;
        RECT 0.000 450.200 2.000 450.800 ;
    END
  END rx_data[174]
  PIN rx_data[175]
    DIRECTION OUTPUT TRISTATE ;
    USE SIGNAL ;
    ANTENNADIFFAREA 0.795200 ;
    PORT
      LAYER met2 ;
        RECT 565.890 0.000 566.170 2.000 ;
    END
  END rx_data[175]
  PIN rx_data[176]
    DIRECTION OUTPUT TRISTATE ;
    USE SIGNAL ;
    ANTENNADIFFAREA 0.795200 ;
    PORT
      LAYER met3 ;
        RECT 1498.000 103.400 1500.000 104.000 ;
    END
  END rx_data[176]
  PIN rx_data[177]
    DIRECTION OUTPUT TRISTATE ;
    USE SIGNAL ;
    ANTENNADIFFAREA 0.795200 ;
    PORT
      LAYER met3 ;
        RECT 1498.000 1096.200 1500.000 1096.800 ;
    END
  END rx_data[177]
  PIN rx_data[178]
    DIRECTION OUTPUT TRISTATE ;
    USE SIGNAL ;
    ANTENNADIFFAREA 0.795200 ;
    PORT
      LAYER met3 ;
        RECT 1498.000 1451.160 1500.000 1451.760 ;
    END
  END rx_data[178]
  PIN rx_data[179]
    DIRECTION OUTPUT TRISTATE ;
    USE SIGNAL ;
    ANTENNADIFFAREA 0.795200 ;
    PORT
      LAYER met3 ;
        RECT 0.000 1241.720 2.000 1242.320 ;
    END
  END rx_data[179]
  PIN rx_data[17]
    DIRECTION OUTPUT TRISTATE ;
    USE SIGNAL ;
    ANTENNADIFFAREA 0.795200 ;
    PORT
      LAYER met3 ;
        RECT 0.000 1302.920 2.000 1303.520 ;
    END
  END rx_data[17]
  PIN rx_data[180]
    DIRECTION OUTPUT TRISTATE ;
    USE SIGNAL ;
    ANTENNADIFFAREA 0.795200 ;
    PORT
      LAYER met3 ;
        RECT 0.000 658.280 2.000 658.880 ;
    END
  END rx_data[180]
  PIN rx_data[181]
    DIRECTION OUTPUT TRISTATE ;
    USE SIGNAL ;
    ANTENNADIFFAREA 0.795200 ;
    PORT
      LAYER met2 ;
        RECT 662.490 0.000 662.770 2.000 ;
    END
  END rx_data[181]
  PIN rx_data[182]
    DIRECTION OUTPUT TRISTATE ;
    USE SIGNAL ;
    ANTENNADIFFAREA 0.795200 ;
    PORT
      LAYER met2 ;
        RECT 1192.410 0.000 1192.690 2.000 ;
    END
  END rx_data[182]
  PIN rx_data[183]
    DIRECTION OUTPUT TRISTATE ;
    USE SIGNAL ;
    ANTENNADIFFAREA 0.795200 ;
    PORT
      LAYER met2 ;
        RECT 390.630 1498.000 390.910 1500.000 ;
    END
  END rx_data[183]
  PIN rx_data[184]
    DIRECTION OUTPUT TRISTATE ;
    USE SIGNAL ;
    ANTENNADIFFAREA 0.795200 ;
    PORT
      LAYER met3 ;
        RECT 0.000 1338.280 2.000 1338.880 ;
    END
  END rx_data[184]
  PIN rx_data[185]
    DIRECTION OUTPUT TRISTATE ;
    USE SIGNAL ;
    ANTENNADIFFAREA 0.795200 ;
    PORT
      LAYER met2 ;
        RECT 396.150 1498.000 396.430 1500.000 ;
    END
  END rx_data[185]
  PIN rx_data[186]
    DIRECTION OUTPUT TRISTATE ;
    USE SIGNAL ;
    ANTENNADIFFAREA 0.795200 ;
    PORT
      LAYER met3 ;
        RECT 0.000 546.760 2.000 547.360 ;
    END
  END rx_data[186]
  PIN rx_data[187]
    DIRECTION OUTPUT TRISTATE ;
    USE SIGNAL ;
    ANTENNADIFFAREA 0.795200 ;
    PORT
      LAYER met2 ;
        RECT 1079.250 0.000 1079.530 2.000 ;
    END
  END rx_data[187]
  PIN rx_data[188]
    DIRECTION OUTPUT TRISTATE ;
    USE SIGNAL ;
    ANTENNADIFFAREA 0.795200 ;
    PORT
      LAYER met2 ;
        RECT 432.030 1498.000 432.310 1500.000 ;
    END
  END rx_data[188]
  PIN rx_data[189]
    DIRECTION OUTPUT TRISTATE ;
    USE SIGNAL ;
    ANTENNADIFFAREA 0.795200 ;
    PORT
      LAYER met2 ;
        RECT 118.770 1498.000 119.050 1500.000 ;
    END
  END rx_data[189]
  PIN rx_data[18]
    DIRECTION OUTPUT TRISTATE ;
    USE SIGNAL ;
    ANTENNADIFFAREA 0.795200 ;
    PORT
      LAYER met2 ;
        RECT 1033.710 0.000 1033.990 2.000 ;
    END
  END rx_data[18]
  PIN rx_data[190]
    DIRECTION OUTPUT TRISTATE ;
    USE SIGNAL ;
    ANTENNADIFFAREA 0.795200 ;
    PORT
      LAYER met3 ;
        RECT 1498.000 16.360 1500.000 16.960 ;
    END
  END rx_data[190]
  PIN rx_data[191]
    DIRECTION OUTPUT TRISTATE ;
    USE SIGNAL ;
    ANTENNADIFFAREA 0.795200 ;
    PORT
      LAYER met2 ;
        RECT 1043.370 0.000 1043.650 2.000 ;
    END
  END rx_data[191]
  PIN rx_data[192]
    DIRECTION OUTPUT TRISTATE ;
    USE SIGNAL ;
    ANTENNADIFFAREA 0.795200 ;
    PORT
      LAYER met2 ;
        RECT 1414.590 0.000 1414.870 2.000 ;
    END
  END rx_data[192]
  PIN rx_data[193]
    DIRECTION OUTPUT TRISTATE ;
    USE SIGNAL ;
    ANTENNADIFFAREA 0.795200 ;
    PORT
      LAYER met3 ;
        RECT 0.000 1033.640 2.000 1034.240 ;
    END
  END rx_data[193]
  PIN rx_data[194]
    DIRECTION OUTPUT TRISTATE ;
    USE SIGNAL ;
    ANTENNADIFFAREA 0.795200 ;
    PORT
      LAYER met2 ;
        RECT 1120.650 0.000 1120.930 2.000 ;
    END
  END rx_data[194]
  PIN rx_data[195]
    DIRECTION OUTPUT TRISTATE ;
    USE SIGNAL ;
    ANTENNADIFFAREA 0.795200 ;
    PORT
      LAYER met2 ;
        RECT 724.590 1498.000 724.870 1500.000 ;
    END
  END rx_data[195]
  PIN rx_data[196]
    DIRECTION OUTPUT TRISTATE ;
    USE SIGNAL ;
    ANTENNADIFFAREA 0.795200 ;
    PORT
      LAYER met3 ;
        RECT 0.000 151.000 2.000 151.600 ;
    END
  END rx_data[196]
  PIN rx_data[197]
    DIRECTION OUTPUT TRISTATE ;
    USE SIGNAL ;
    ANTENNADIFFAREA 0.795200 ;
    PORT
      LAYER met2 ;
        RECT 1363.530 1498.000 1363.810 1500.000 ;
    END
  END rx_data[197]
  PIN rx_data[198]
    DIRECTION OUTPUT TRISTATE ;
    USE SIGNAL ;
    ANTENNADIFFAREA 0.795200 ;
    PORT
      LAYER met2 ;
        RECT 1126.170 1498.000 1126.450 1500.000 ;
    END
  END rx_data[198]
  PIN rx_data[199]
    DIRECTION OUTPUT TRISTATE ;
    USE SIGNAL ;
    ANTENNADIFFAREA 0.795200 ;
    PORT
      LAYER met2 ;
        RECT 730.110 1498.000 730.390 1500.000 ;
    END
  END rx_data[199]
  PIN rx_data[19]
    DIRECTION OUTPUT TRISTATE ;
    USE SIGNAL ;
    ANTENNADIFFAREA 0.795200 ;
    PORT
      LAYER met2 ;
        RECT 98.070 1498.000 98.350 1500.000 ;
    END
  END rx_data[19]
  PIN rx_data[1]
    DIRECTION OUTPUT TRISTATE ;
    USE SIGNAL ;
    ANTENNADIFFAREA 0.795200 ;
    PORT
      LAYER met2 ;
        RECT 1244.850 0.000 1245.130 2.000 ;
    END
  END rx_data[1]
  PIN rx_data[200]
    DIRECTION OUTPUT TRISTATE ;
    USE SIGNAL ;
    ANTENNADIFFAREA 0.795200 ;
    PORT
      LAYER met2 ;
        RECT 977.130 0.000 977.410 2.000 ;
    END
  END rx_data[200]
  PIN rx_data[201]
    DIRECTION OUTPUT TRISTATE ;
    USE SIGNAL ;
    ANTENNADIFFAREA 0.795200 ;
    PORT
      LAYER met3 ;
        RECT 0.000 901.720 2.000 902.320 ;
    END
  END rx_data[201]
  PIN rx_data[202]
    DIRECTION OUTPUT TRISTATE ;
    USE SIGNAL ;
    ANTENNADIFFAREA 0.795200 ;
    PORT
      LAYER met2 ;
        RECT 345.090 1498.000 345.370 1500.000 ;
    END
  END rx_data[202]
  PIN rx_data[203]
    DIRECTION OUTPUT TRISTATE ;
    USE SIGNAL ;
    ANTENNADIFFAREA 0.795200 ;
    PORT
      LAYER met3 ;
        RECT 0.000 734.440 2.000 735.040 ;
    END
  END rx_data[203]
  PIN rx_data[204]
    DIRECTION OUTPUT TRISTATE ;
    USE SIGNAL ;
    ANTENNADIFFAREA 0.795200 ;
    PORT
      LAYER met3 ;
        RECT 1498.000 1365.480 1500.000 1366.080 ;
    END
  END rx_data[204]
  PIN rx_data[205]
    DIRECTION OUTPUT TRISTATE ;
    USE SIGNAL ;
    ANTENNADIFFAREA 0.795200 ;
    PORT
      LAYER met3 ;
        RECT 0.000 323.720 2.000 324.320 ;
    END
  END rx_data[205]
  PIN rx_data[206]
    DIRECTION OUTPUT TRISTATE ;
    USE SIGNAL ;
    ANTENNADIFFAREA 0.795200 ;
    PORT
      LAYER met3 ;
        RECT 1498.000 594.360 1500.000 594.960 ;
    END
  END rx_data[206]
  PIN rx_data[207]
    DIRECTION OUTPUT TRISTATE ;
    USE SIGNAL ;
    ANTENNADIFFAREA 0.795200 ;
    PORT
      LAYER met2 ;
        RECT 488.610 1498.000 488.890 1500.000 ;
    END
  END rx_data[207]
  PIN rx_data[208]
    DIRECTION OUTPUT TRISTATE ;
    USE SIGNAL ;
    ANTENNADIFFAREA 0.795200 ;
    PORT
      LAYER met3 ;
        RECT 1498.000 178.200 1500.000 178.800 ;
    END
  END rx_data[208]
  PIN rx_data[209]
    DIRECTION OUTPUT TRISTATE ;
    USE SIGNAL ;
    ANTENNADIFFAREA 0.795200 ;
    PORT
      LAYER met3 ;
        RECT 0.000 501.880 2.000 502.480 ;
    END
  END rx_data[209]
  PIN rx_data[20]
    DIRECTION OUTPUT TRISTATE ;
    USE SIGNAL ;
    ANTENNADIFFAREA 0.795200 ;
    PORT
      LAYER met3 ;
        RECT 1498.000 189.080 1500.000 189.680 ;
    END
  END rx_data[20]
  PIN rx_data[210]
    DIRECTION OUTPUT TRISTATE ;
    USE SIGNAL ;
    ANTENNADIFFAREA 0.795200 ;
    PORT
      LAYER met3 ;
        RECT 1498.000 1035.000 1500.000 1035.600 ;
    END
  END rx_data[210]
  PIN rx_data[211]
    DIRECTION OUTPUT TRISTATE ;
    USE SIGNAL ;
    ANTENNADIFFAREA 0.795200 ;
    PORT
      LAYER met2 ;
        RECT 843.270 1498.000 843.550 1500.000 ;
    END
  END rx_data[211]
  PIN rx_data[212]
    DIRECTION OUTPUT TRISTATE ;
    USE SIGNAL ;
    ANTENNADIFFAREA 0.795200 ;
    PORT
      LAYER met2 ;
        RECT 215.370 0.000 215.650 2.000 ;
    END
  END rx_data[212]
  PIN rx_data[213]
    DIRECTION OUTPUT TRISTATE ;
    USE SIGNAL ;
    ANTENNADIFFAREA 0.795200 ;
    PORT
      LAYER met2 ;
        RECT 550.710 1498.000 550.990 1500.000 ;
    END
  END rx_data[213]
  PIN rx_data[214]
    DIRECTION OUTPUT TRISTATE ;
    USE SIGNAL ;
    ANTENNADIFFAREA 0.795200 ;
    PORT
      LAYER met3 ;
        RECT 0.000 329.160 2.000 329.760 ;
    END
  END rx_data[214]
  PIN rx_data[215]
    DIRECTION OUTPUT TRISTATE ;
    USE SIGNAL ;
    ANTENNADIFFAREA 0.795200 ;
    PORT
      LAYER met2 ;
        RECT 441.690 0.000 441.970 2.000 ;
    END
  END rx_data[215]
  PIN rx_data[216]
    DIRECTION OUTPUT TRISTATE ;
    USE SIGNAL ;
    ANTENNADIFFAREA 0.795200 ;
    PORT
      LAYER met2 ;
        RECT 632.130 1498.000 632.410 1500.000 ;
    END
  END rx_data[216]
  PIN rx_data[217]
    DIRECTION OUTPUT TRISTATE ;
    USE SIGNAL ;
    ANTENNADIFFAREA 0.795200 ;
    PORT
      LAYER met3 ;
        RECT 1498.000 462.440 1500.000 463.040 ;
    END
  END rx_data[217]
  PIN rx_data[218]
    DIRECTION OUTPUT TRISTATE ;
    USE SIGNAL ;
    ANTENNADIFFAREA 0.795200 ;
    PORT
      LAYER met3 ;
        RECT 1498.000 326.440 1500.000 327.040 ;
    END
  END rx_data[218]
  PIN rx_data[219]
    DIRECTION OUTPUT TRISTATE ;
    USE SIGNAL ;
    ANTENNADIFFAREA 0.795200 ;
    PORT
      LAYER met3 ;
        RECT 0.000 223.080 2.000 223.680 ;
    END
  END rx_data[219]
  PIN rx_data[21]
    DIRECTION OUTPUT TRISTATE ;
    USE SIGNAL ;
    ANTENNADIFFAREA 0.795200 ;
    PORT
      LAYER met3 ;
        RECT 0.000 845.960 2.000 846.560 ;
    END
  END rx_data[21]
  PIN rx_data[220]
    DIRECTION OUTPUT TRISTATE ;
    USE SIGNAL ;
    ANTENNADIFFAREA 0.795200 ;
    PORT
      LAYER met3 ;
        RECT 0.000 875.880 2.000 876.480 ;
    END
  END rx_data[220]
  PIN rx_data[221]
    DIRECTION OUTPUT TRISTATE ;
    USE SIGNAL ;
    ANTENNADIFFAREA 0.795200 ;
    PORT
      LAYER met3 ;
        RECT 0.000 947.960 2.000 948.560 ;
    END
  END rx_data[221]
  PIN rx_data[222]
    DIRECTION OUTPUT TRISTATE ;
    USE SIGNAL ;
    ANTENNADIFFAREA 0.795200 ;
    PORT
      LAYER met3 ;
        RECT 1498.000 1020.040 1500.000 1020.640 ;
    END
  END rx_data[222]
  PIN rx_data[223]
    DIRECTION OUTPUT TRISTATE ;
    USE SIGNAL ;
    ANTENNADIFFAREA 0.795200 ;
    PORT
      LAYER met2 ;
        RECT 601.770 1498.000 602.050 1500.000 ;
    END
  END rx_data[223]
  PIN rx_data[224]
    DIRECTION OUTPUT TRISTATE ;
    USE SIGNAL ;
    ANTENNADIFFAREA 0.795200 ;
    PORT
      LAYER met3 ;
        RECT 0.000 1190.040 2.000 1190.640 ;
    END
  END rx_data[224]
  PIN rx_data[225]
    DIRECTION OUTPUT TRISTATE ;
    USE SIGNAL ;
    ANTENNADIFFAREA 0.795200 ;
    PORT
      LAYER met2 ;
        RECT 56.670 0.000 56.950 2.000 ;
    END
  END rx_data[225]
  PIN rx_data[226]
    DIRECTION OUTPUT TRISTATE ;
    USE SIGNAL ;
    ANTENNADIFFAREA 0.795200 ;
    PORT
      LAYER met2 ;
        RECT 1075.110 1498.000 1075.390 1500.000 ;
    END
  END rx_data[226]
  PIN rx_data[227]
    DIRECTION OUTPUT TRISTATE ;
    USE SIGNAL ;
    ANTENNADIFFAREA 0.795200 ;
    PORT
      LAYER met2 ;
        RECT 818.430 1498.000 818.710 1500.000 ;
    END
  END rx_data[227]
  PIN rx_data[228]
    DIRECTION OUTPUT TRISTATE ;
    USE SIGNAL ;
    ANTENNADIFFAREA 0.795200 ;
    PORT
      LAYER met3 ;
        RECT 0.000 1358.680 2.000 1359.280 ;
    END
  END rx_data[228]
  PIN rx_data[229]
    DIRECTION OUTPUT TRISTATE ;
    USE SIGNAL ;
    ANTENNADIFFAREA 0.795200 ;
    PORT
      LAYER met3 ;
        RECT 0.000 714.040 2.000 714.640 ;
    END
  END rx_data[229]
  PIN rx_data[22]
    DIRECTION OUTPUT TRISTATE ;
    USE SIGNAL ;
    ANTENNADIFFAREA 0.795200 ;
    PORT
      LAYER met2 ;
        RECT 977.130 1498.000 977.410 1500.000 ;
    END
  END rx_data[22]
  PIN rx_data[230]
    DIRECTION OUTPUT TRISTATE ;
    USE SIGNAL ;
    ANTENNADIFFAREA 0.795200 ;
    PORT
      LAYER met3 ;
        RECT 1498.000 1339.640 1500.000 1340.240 ;
    END
  END rx_data[230]
  PIN rx_data[231]
    DIRECTION OUTPUT TRISTATE ;
    USE SIGNAL ;
    ANTENNADIFFAREA 0.795200 ;
    PORT
      LAYER met2 ;
        RECT 380.970 1498.000 381.250 1500.000 ;
    END
  END rx_data[231]
  PIN rx_data[232]
    DIRECTION OUTPUT TRISTATE ;
    USE SIGNAL ;
    ANTENNADIFFAREA 0.795200 ;
    PORT
      LAYER met2 ;
        RECT 277.470 1498.000 277.750 1500.000 ;
    END
  END rx_data[232]
  PIN rx_data[233]
    DIRECTION OUTPUT TRISTATE ;
    USE SIGNAL ;
    ANTENNADIFFAREA 0.795200 ;
    PORT
      LAYER met3 ;
        RECT 0.000 607.960 2.000 608.560 ;
    END
  END rx_data[233]
  PIN rx_data[234]
    DIRECTION OUTPUT TRISTATE ;
    USE SIGNAL ;
    ANTENNADIFFAREA 0.795200 ;
    PORT
      LAYER met3 ;
        RECT 1498.000 960.200 1500.000 960.800 ;
    END
  END rx_data[234]
  PIN rx_data[235]
    DIRECTION OUTPUT TRISTATE ;
    USE SIGNAL ;
    ANTENNADIFFAREA 0.795200 ;
    PORT
      LAYER met3 ;
        RECT 1498.000 477.400 1500.000 478.000 ;
    END
  END rx_data[235]
  PIN rx_data[236]
    DIRECTION OUTPUT TRISTATE ;
    USE SIGNAL ;
    ANTENNADIFFAREA 0.795200 ;
    PORT
      LAYER met3 ;
        RECT 0.000 1069.000 2.000 1069.600 ;
    END
  END rx_data[236]
  PIN rx_data[237]
    DIRECTION OUTPUT TRISTATE ;
    USE SIGNAL ;
    ANTENNADIFFAREA 0.795200 ;
    PORT
      LAYER met2 ;
        RECT 488.610 0.000 488.890 2.000 ;
    END
  END rx_data[237]
  PIN rx_data[238]
    DIRECTION OUTPUT TRISTATE ;
    USE SIGNAL ;
    ANTENNADIFFAREA 0.795200 ;
    PORT
      LAYER met2 ;
        RECT 318.870 0.000 319.150 2.000 ;
    END
  END rx_data[238]
  PIN rx_data[239]
    DIRECTION OUTPUT TRISTATE ;
    USE SIGNAL ;
    ANTENNADIFFAREA 0.795200 ;
    PORT
      LAYER met3 ;
        RECT 0.000 74.840 2.000 75.440 ;
    END
  END rx_data[239]
  PIN rx_data[23]
    DIRECTION OUTPUT TRISTATE ;
    USE SIGNAL ;
    ANTENNADIFFAREA 0.795200 ;
    PORT
      LAYER met3 ;
        RECT 1498.000 1090.760 1500.000 1091.360 ;
    END
  END rx_data[23]
  PIN rx_data[240]
    DIRECTION OUTPUT TRISTATE ;
    USE SIGNAL ;
    ANTENNADIFFAREA 0.795200 ;
    PORT
      LAYER met3 ;
        RECT 0.000 95.240 2.000 95.840 ;
    END
  END rx_data[240]
  PIN rx_data[241]
    DIRECTION OUTPUT TRISTATE ;
    USE SIGNAL ;
    ANTENNADIFFAREA 0.795200 ;
    PORT
      LAYER met2 ;
        RECT 179.490 0.000 179.770 2.000 ;
    END
  END rx_data[241]
  PIN rx_data[242]
    DIRECTION OUTPUT TRISTATE ;
    USE SIGNAL ;
    ANTENNADIFFAREA 0.795200 ;
    PORT
      LAYER met3 ;
        RECT 1498.000 315.560 1500.000 316.160 ;
    END
  END rx_data[242]
  PIN rx_data[243]
    DIRECTION OUTPUT TRISTATE ;
    USE SIGNAL ;
    ANTENNADIFFAREA 0.795200 ;
    PORT
      LAYER met3 ;
        RECT 1498.000 1268.920 1500.000 1269.520 ;
    END
  END rx_data[243]
  PIN rx_data[244]
    DIRECTION OUTPUT TRISTATE ;
    USE SIGNAL ;
    ANTENNADIFFAREA 0.795200 ;
    PORT
      LAYER met3 ;
        RECT 1498.000 995.560 1500.000 996.160 ;
    END
  END rx_data[244]
  PIN rx_data[245]
    DIRECTION OUTPUT TRISTATE ;
    USE SIGNAL ;
    ANTENNADIFFAREA 0.795200 ;
    PORT
      LAYER met3 ;
        RECT 0.000 684.120 2.000 684.720 ;
    END
  END rx_data[245]
  PIN rx_data[246]
    DIRECTION OUTPUT TRISTATE ;
    USE SIGNAL ;
    ANTENNADIFFAREA 0.795200 ;
    PORT
      LAYER met2 ;
        RECT 741.150 1498.000 741.430 1500.000 ;
    END
  END rx_data[246]
  PIN rx_data[247]
    DIRECTION OUTPUT TRISTATE ;
    USE SIGNAL ;
    ANTENNADIFFAREA 0.795200 ;
    PORT
      LAYER met2 ;
        RECT 287.130 0.000 287.410 2.000 ;
    END
  END rx_data[247]
  PIN rx_data[248]
    DIRECTION OUTPUT TRISTATE ;
    USE SIGNAL ;
    ANTENNADIFFAREA 0.795200 ;
    PORT
      LAYER met3 ;
        RECT 1498.000 843.240 1500.000 843.840 ;
    END
  END rx_data[248]
  PIN rx_data[249]
    DIRECTION OUTPUT TRISTATE ;
    USE SIGNAL ;
    ANTENNADIFFAREA 0.795200 ;
    PORT
      LAYER met3 ;
        RECT 0.000 1185.960 2.000 1186.560 ;
    END
  END rx_data[249]
  PIN rx_data[24]
    DIRECTION OUTPUT TRISTATE ;
    USE SIGNAL ;
    ANTENNADIFFAREA 0.795200 ;
    PORT
      LAYER met2 ;
        RECT 1146.870 0.000 1147.150 2.000 ;
    END
  END rx_data[24]
  PIN rx_data[250]
    DIRECTION OUTPUT TRISTATE ;
    USE SIGNAL ;
    ANTENNADIFFAREA 0.795200 ;
    PORT
      LAYER met2 ;
        RECT 714.930 1498.000 715.210 1500.000 ;
    END
  END rx_data[250]
  PIN rx_data[251]
    DIRECTION OUTPUT TRISTATE ;
    USE SIGNAL ;
    ANTENNADIFFAREA 0.795200 ;
    PORT
      LAYER met3 ;
        RECT 1498.000 47.640 1500.000 48.240 ;
    END
  END rx_data[251]
  PIN rx_data[252]
    DIRECTION OUTPUT TRISTATE ;
    USE SIGNAL ;
    ANTENNADIFFAREA 0.795200 ;
    PORT
      LAYER met3 ;
        RECT 0.000 1282.520 2.000 1283.120 ;
    END
  END rx_data[252]
  PIN rx_data[253]
    DIRECTION OUTPUT TRISTATE ;
    USE SIGNAL ;
    ANTENNADIFFAREA 0.795200 ;
    PORT
      LAYER met2 ;
        RECT 107.730 1498.000 108.010 1500.000 ;
    END
  END rx_data[253]
  PIN rx_data[254]
    DIRECTION OUTPUT TRISTATE ;
    USE SIGNAL ;
    ANTENNADIFFAREA 0.795200 ;
    PORT
      LAYER met3 ;
        RECT 1498.000 1491.960 1500.000 1492.560 ;
    END
  END rx_data[254]
  PIN rx_data[255]
    DIRECTION OUTPUT TRISTATE ;
    USE SIGNAL ;
    ANTENNADIFFAREA 0.795200 ;
    PORT
      LAYER met3 ;
        RECT 1498.000 782.040 1500.000 782.640 ;
    END
  END rx_data[255]
  PIN rx_data[256]
    DIRECTION OUTPUT TRISTATE ;
    USE SIGNAL ;
    ANTENNADIFFAREA 0.795200 ;
    PORT
      LAYER met3 ;
        RECT 1498.000 1137.000 1500.000 1137.600 ;
    END
  END rx_data[256]
  PIN rx_data[257]
    DIRECTION OUTPUT TRISTATE ;
    USE SIGNAL ;
    ANTENNADIFFAREA 0.795200 ;
    PORT
      LAYER met3 ;
        RECT 1498.000 1177.800 1500.000 1178.400 ;
    END
  END rx_data[257]
  PIN rx_data[258]
    DIRECTION OUTPUT TRISTATE ;
    USE SIGNAL ;
    ANTENNADIFFAREA 0.795200 ;
    PORT
      LAYER met3 ;
        RECT 1498.000 1045.880 1500.000 1046.480 ;
    END
  END rx_data[258]
  PIN rx_data[259]
    DIRECTION OUTPUT TRISTATE ;
    USE SIGNAL ;
    ANTENNADIFFAREA 0.795200 ;
    PORT
      LAYER met3 ;
        RECT 0.000 1236.280 2.000 1236.880 ;
    END
  END rx_data[259]
  PIN rx_data[25]
    DIRECTION OUTPUT TRISTATE ;
    USE SIGNAL ;
    ANTENNADIFFAREA 0.795200 ;
    PORT
      LAYER met3 ;
        RECT 0.000 318.280 2.000 318.880 ;
    END
  END rx_data[25]
  PIN rx_data[260]
    DIRECTION OUTPUT TRISTATE ;
    USE SIGNAL ;
    ANTENNADIFFAREA 0.795200 ;
    PORT
      LAYER met3 ;
        RECT 0.000 1271.640 2.000 1272.240 ;
    END
  END rx_data[260]
  PIN rx_data[261]
    DIRECTION OUTPUT TRISTATE ;
    USE SIGNAL ;
    ANTENNADIFFAREA 0.795200 ;
    PORT
      LAYER met2 ;
        RECT 1403.550 0.000 1403.830 2.000 ;
    END
  END rx_data[261]
  PIN rx_data[262]
    DIRECTION OUTPUT TRISTATE ;
    USE SIGNAL ;
    ANTENNADIFFAREA 0.795200 ;
    PORT
      LAYER met2 ;
        RECT 271.950 0.000 272.230 2.000 ;
    END
  END rx_data[262]
  PIN rx_data[263]
    DIRECTION OUTPUT TRISTATE ;
    USE SIGNAL ;
    ANTENNADIFFAREA 0.795200 ;
    PORT
      LAYER met3 ;
        RECT 1498.000 321.000 1500.000 321.600 ;
    END
  END rx_data[263]
  PIN rx_data[264]
    DIRECTION OUTPUT TRISTATE ;
    USE SIGNAL ;
    ANTENNADIFFAREA 0.795200 ;
    PORT
      LAYER met2 ;
        RECT 77.370 1498.000 77.650 1500.000 ;
    END
  END rx_data[264]
  PIN rx_data[265]
    DIRECTION OUTPUT TRISTATE ;
    USE SIGNAL ;
    ANTENNADIFFAREA 0.795200 ;
    PORT
      LAYER met3 ;
        RECT 0.000 957.480 2.000 958.080 ;
    END
  END rx_data[265]
  PIN rx_data[266]
    DIRECTION OUTPUT TRISTATE ;
    USE SIGNAL ;
    ANTENNADIFFAREA 0.795200 ;
    PORT
      LAYER met3 ;
        RECT 0.000 1489.240 2.000 1489.840 ;
    END
  END rx_data[266]
  PIN rx_data[267]
    DIRECTION OUTPUT TRISTATE ;
    USE SIGNAL ;
    ANTENNADIFFAREA 0.795200 ;
    PORT
      LAYER met3 ;
        RECT 0.000 59.880 2.000 60.480 ;
    END
  END rx_data[267]
  PIN rx_data[268]
    DIRECTION OUTPUT TRISTATE ;
    USE SIGNAL ;
    ANTENNADIFFAREA 0.795200 ;
    PORT
      LAYER met3 ;
        RECT 0.000 1321.960 2.000 1322.560 ;
    END
  END rx_data[268]
  PIN rx_data[269]
    DIRECTION OUTPUT TRISTATE ;
    USE SIGNAL ;
    ANTENNADIFFAREA 0.795200 ;
    PORT
      LAYER met2 ;
        RECT 1450.470 0.000 1450.750 2.000 ;
    END
  END rx_data[269]
  PIN rx_data[26]
    DIRECTION OUTPUT TRISTATE ;
    USE SIGNAL ;
    ANTENNADIFFAREA 0.795200 ;
    PORT
      LAYER met3 ;
        RECT 1498.000 899.000 1500.000 899.600 ;
    END
  END rx_data[26]
  PIN rx_data[270]
    DIRECTION OUTPUT TRISTATE ;
    USE SIGNAL ;
    ANTENNADIFFAREA 0.795200 ;
    PORT
      LAYER met3 ;
        RECT 0.000 171.400 2.000 172.000 ;
    END
  END rx_data[270]
  PIN rx_data[271]
    DIRECTION OUTPUT TRISTATE ;
    USE SIGNAL ;
    ANTENNADIFFAREA 0.795200 ;
    PORT
      LAYER met2 ;
        RECT 503.790 1498.000 504.070 1500.000 ;
    END
  END rx_data[271]
  PIN rx_data[272]
    DIRECTION OUTPUT TRISTATE ;
    USE SIGNAL ;
    ANTENNADIFFAREA 0.795200 ;
    PORT
      LAYER met2 ;
        RECT 1450.470 1498.000 1450.750 1500.000 ;
    END
  END rx_data[272]
  PIN rx_data[273]
    DIRECTION OUTPUT TRISTATE ;
    USE SIGNAL ;
    ANTENNADIFFAREA 0.795200 ;
    PORT
      LAYER met2 ;
        RECT 1290.390 0.000 1290.670 2.000 ;
    END
  END rx_data[273]
  PIN rx_data[274]
    DIRECTION OUTPUT TRISTATE ;
    USE SIGNAL ;
    ANTENNADIFFAREA 0.795200 ;
    PORT
      LAYER met3 ;
        RECT 0.000 308.760 2.000 309.360 ;
    END
  END rx_data[274]
  PIN rx_data[275]
    DIRECTION OUTPUT TRISTATE ;
    USE SIGNAL ;
    ANTENNADIFFAREA 0.795200 ;
    PORT
      LAYER met2 ;
        RECT 843.270 0.000 843.550 2.000 ;
    END
  END rx_data[275]
  PIN rx_data[276]
    DIRECTION OUTPUT TRISTATE ;
    USE SIGNAL ;
    ANTENNADIFFAREA 0.795200 ;
    PORT
      LAYER met2 ;
        RECT 1203.450 1498.000 1203.730 1500.000 ;
    END
  END rx_data[276]
  PIN rx_data[277]
    DIRECTION OUTPUT TRISTATE ;
    USE SIGNAL ;
    ANTENNADIFFAREA 0.795200 ;
    PORT
      LAYER met2 ;
        RECT 1399.410 1498.000 1399.690 1500.000 ;
    END
  END rx_data[277]
  PIN rx_data[278]
    DIRECTION OUTPUT TRISTATE ;
    USE SIGNAL ;
    ANTENNADIFFAREA 0.795200 ;
    PORT
      LAYER met2 ;
        RECT 334.050 1498.000 334.330 1500.000 ;
    END
  END rx_data[278]
  PIN rx_data[279]
    DIRECTION OUTPUT TRISTATE ;
    USE SIGNAL ;
    ANTENNADIFFAREA 0.795200 ;
    PORT
      LAYER met3 ;
        RECT 0.000 227.160 2.000 227.760 ;
    END
  END rx_data[279]
  PIN rx_data[27]
    DIRECTION OUTPUT TRISTATE ;
    USE SIGNAL ;
    ANTENNADIFFAREA 0.795200 ;
    PORT
      LAYER met3 ;
        RECT 1498.000 1183.240 1500.000 1183.840 ;
    END
  END rx_data[27]
  PIN rx_data[280]
    DIRECTION OUTPUT TRISTATE ;
    USE SIGNAL ;
    ANTENNADIFFAREA 0.795200 ;
    PORT
      LAYER met3 ;
        RECT 0.000 739.880 2.000 740.480 ;
    END
  END rx_data[280]
  PIN rx_data[281]
    DIRECTION OUTPUT TRISTATE ;
    USE SIGNAL ;
    ANTENNADIFFAREA 0.795200 ;
    PORT
      LAYER met3 ;
        RECT 1498.000 1298.840 1500.000 1299.440 ;
    END
  END rx_data[281]
  PIN rx_data[282]
    DIRECTION OUTPUT TRISTATE ;
    USE SIGNAL ;
    ANTENNADIFFAREA 0.795200 ;
    PORT
      LAYER met2 ;
        RECT 626.610 0.000 626.890 2.000 ;
    END
  END rx_data[282]
  PIN rx_data[283]
    DIRECTION OUTPUT TRISTATE ;
    USE SIGNAL ;
    ANTENNADIFFAREA 0.795200 ;
    PORT
      LAYER met2 ;
        RECT 545.190 0.000 545.470 2.000 ;
    END
  END rx_data[283]
  PIN rx_data[284]
    DIRECTION OUTPUT TRISTATE ;
    USE SIGNAL ;
    ANTENNADIFFAREA 0.795200 ;
    PORT
      LAYER met2 ;
        RECT 9.750 0.000 10.030 2.000 ;
    END
  END rx_data[284]
  PIN rx_data[285]
    DIRECTION OUTPUT TRISTATE ;
    USE SIGNAL ;
    ANTENNADIFFAREA 0.795200 ;
    PORT
      LAYER met2 ;
        RECT 339.570 0.000 339.850 2.000 ;
    END
  END rx_data[285]
  PIN rx_data[286]
    DIRECTION OUTPUT TRISTATE ;
    USE SIGNAL ;
    ANTENNADIFFAREA 0.795200 ;
    PORT
      LAYER met3 ;
        RECT 0.000 743.960 2.000 744.560 ;
    END
  END rx_data[286]
  PIN rx_data[287]
    DIRECTION OUTPUT TRISTATE ;
    USE SIGNAL ;
    ANTENNADIFFAREA 0.795200 ;
    PORT
      LAYER met2 ;
        RECT 590.730 0.000 591.010 2.000 ;
    END
  END rx_data[287]
  PIN rx_data[288]
    DIRECTION OUTPUT TRISTATE ;
    USE SIGNAL ;
    ANTENNADIFFAREA 0.795200 ;
    PORT
      LAYER met2 ;
        RECT 1291.770 1498.000 1292.050 1500.000 ;
    END
  END rx_data[288]
  PIN rx_data[289]
    DIRECTION OUTPUT TRISTATE ;
    USE SIGNAL ;
    ANTENNADIFFAREA 0.795200 ;
    PORT
      LAYER met2 ;
        RECT 452.730 0.000 453.010 2.000 ;
    END
  END rx_data[289]
  PIN rx_data[28]
    DIRECTION OUTPUT TRISTATE ;
    USE SIGNAL ;
    ANTENNADIFFAREA 0.795200 ;
    PORT
      LAYER met2 ;
        RECT 149.130 1498.000 149.410 1500.000 ;
    END
  END rx_data[28]
  PIN rx_data[290]
    DIRECTION OUTPUT TRISTATE ;
    USE SIGNAL ;
    ANTENNADIFFAREA 0.795200 ;
    PORT
      LAYER met3 ;
        RECT 0.000 338.680 2.000 339.280 ;
    END
  END rx_data[290]
  PIN rx_data[291]
    DIRECTION OUTPUT TRISTATE ;
    USE SIGNAL ;
    ANTENNADIFFAREA 0.795200 ;
    PORT
      LAYER met3 ;
        RECT 0.000 1226.760 2.000 1227.360 ;
    END
  END rx_data[291]
  PIN rx_data[292]
    DIRECTION OUTPUT TRISTATE ;
    USE SIGNAL ;
    ANTENNADIFFAREA 0.795200 ;
    PORT
      LAYER met3 ;
        RECT 1498.000 1486.520 1500.000 1487.120 ;
    END
  END rx_data[292]
  PIN rx_data[293]
    DIRECTION OUTPUT TRISTATE ;
    USE SIGNAL ;
    ANTENNADIFFAREA 0.795200 ;
    PORT
      LAYER met3 ;
        RECT 0.000 1368.200 2.000 1368.800 ;
    END
  END rx_data[293]
  PIN rx_data[294]
    DIRECTION OUTPUT TRISTATE ;
    USE SIGNAL ;
    ANTENNADIFFAREA 0.795200 ;
    PORT
      LAYER met2 ;
        RECT 528.630 0.000 528.910 2.000 ;
    END
  END rx_data[294]
  PIN rx_data[295]
    DIRECTION OUTPUT TRISTATE ;
    USE SIGNAL ;
    ANTENNADIFFAREA 0.795200 ;
    PORT
      LAYER met3 ;
        RECT 1498.000 386.280 1500.000 386.880 ;
    END
  END rx_data[295]
  PIN rx_data[296]
    DIRECTION OUTPUT TRISTATE ;
    USE SIGNAL ;
    ANTENNADIFFAREA 0.795200 ;
    PORT
      LAYER met2 ;
        RECT 709.410 1498.000 709.690 1500.000 ;
    END
  END rx_data[296]
  PIN rx_data[297]
    DIRECTION OUTPUT TRISTATE ;
    USE SIGNAL ;
    ANTENNADIFFAREA 0.795200 ;
    PORT
      LAYER met3 ;
        RECT 1498.000 1436.200 1500.000 1436.800 ;
    END
  END rx_data[297]
  PIN rx_data[298]
    DIRECTION OUTPUT TRISTATE ;
    USE SIGNAL ;
    ANTENNADIFFAREA 0.795200 ;
    PORT
      LAYER met3 ;
        RECT 0.000 1013.240 2.000 1013.840 ;
    END
  END rx_data[298]
  PIN rx_data[299]
    DIRECTION OUTPUT TRISTATE ;
    USE SIGNAL ;
    ANTENNADIFFAREA 0.795200 ;
    PORT
      LAYER met2 ;
        RECT 534.150 0.000 534.430 2.000 ;
    END
  END rx_data[299]
  PIN rx_data[29]
    DIRECTION OUTPUT TRISTATE ;
    USE SIGNAL ;
    ANTENNADIFFAREA 0.795200 ;
    PORT
      LAYER met2 ;
        RECT 503.790 0.000 504.070 2.000 ;
    END
  END rx_data[29]
  PIN rx_data[2]
    DIRECTION OUTPUT TRISTATE ;
    USE SIGNAL ;
    ANTENNADIFFAREA 0.795200 ;
    PORT
      LAYER met3 ;
        RECT 1498.000 873.160 1500.000 873.760 ;
    END
  END rx_data[2]
  PIN rx_data[300]
    DIRECTION OUTPUT TRISTATE ;
    USE SIGNAL ;
    ANTENNADIFFAREA 0.795200 ;
    PORT
      LAYER met2 ;
        RECT 852.930 0.000 853.210 2.000 ;
    END
  END rx_data[300]
  PIN rx_data[301]
    DIRECTION OUTPUT TRISTATE ;
    USE SIGNAL ;
    ANTENNADIFFAREA 0.795200 ;
    PORT
      LAYER met3 ;
        RECT 1498.000 432.520 1500.000 433.120 ;
    END
  END rx_data[301]
  PIN rx_data[302]
    DIRECTION OUTPUT TRISTATE ;
    USE SIGNAL ;
    ANTENNADIFFAREA 0.795200 ;
    PORT
      LAYER met2 ;
        RECT 1322.130 0.000 1322.410 2.000 ;
    END
  END rx_data[302]
  PIN rx_data[303]
    DIRECTION OUTPUT TRISTATE ;
    USE SIGNAL ;
    ANTENNADIFFAREA 0.795200 ;
    PORT
      LAYER met2 ;
        RECT 1382.850 0.000 1383.130 2.000 ;
    END
  END rx_data[303]
  PIN rx_data[304]
    DIRECTION OUTPUT TRISTATE ;
    USE SIGNAL ;
    ANTENNADIFFAREA 0.795200 ;
    PORT
      LAYER met3 ;
        RECT 0.000 537.240 2.000 537.840 ;
    END
  END rx_data[304]
  PIN rx_data[305]
    DIRECTION OUTPUT TRISTATE ;
    USE SIGNAL ;
    ANTENNADIFFAREA 0.795200 ;
    PORT
      LAYER met3 ;
        RECT 0.000 1048.600 2.000 1049.200 ;
    END
  END rx_data[305]
  PIN rx_data[306]
    DIRECTION OUTPUT TRISTATE ;
    USE SIGNAL ;
    ANTENNADIFFAREA 0.795200 ;
    PORT
      LAYER met3 ;
        RECT 1498.000 406.680 1500.000 407.280 ;
    END
  END rx_data[306]
  PIN rx_data[307]
    DIRECTION OUTPUT TRISTATE ;
    USE SIGNAL ;
    ANTENNADIFFAREA 0.795200 ;
    PORT
      LAYER met3 ;
        RECT 0.000 232.600 2.000 233.200 ;
    END
  END rx_data[307]
  PIN rx_data[308]
    DIRECTION OUTPUT TRISTATE ;
    USE SIGNAL ;
    ANTENNADIFFAREA 0.795200 ;
    PORT
      LAYER met2 ;
        RECT 1284.870 0.000 1285.150 2.000 ;
    END
  END rx_data[308]
  PIN rx_data[309]
    DIRECTION OUTPUT TRISTATE ;
    USE SIGNAL ;
    ANTENNADIFFAREA 0.795200 ;
    PORT
      LAYER met3 ;
        RECT 1498.000 797.000 1500.000 797.600 ;
    END
  END rx_data[309]
  PIN rx_data[30]
    DIRECTION OUTPUT TRISTATE ;
    USE SIGNAL ;
    ANTENNADIFFAREA 0.795200 ;
    PORT
      LAYER met3 ;
        RECT 0.000 4.120 2.000 4.720 ;
    END
  END rx_data[30]
  PIN rx_data[310]
    DIRECTION OUTPUT TRISTATE ;
    USE SIGNAL ;
    ANTENNADIFFAREA 0.795200 ;
    PORT
      LAYER met3 ;
        RECT 1498.000 1166.920 1500.000 1167.520 ;
    END
  END rx_data[310]
  PIN rx_data[311]
    DIRECTION OUTPUT TRISTATE ;
    USE SIGNAL ;
    ANTENNADIFFAREA 0.795200 ;
    PORT
      LAYER met2 ;
        RECT 765.990 1498.000 766.270 1500.000 ;
    END
  END rx_data[311]
  PIN rx_data[312]
    DIRECTION OUTPUT TRISTATE ;
    USE SIGNAL ;
    ANTENNADIFFAREA 0.795200 ;
    PORT
      LAYER met3 ;
        RECT 1498.000 1497.400 1500.000 1498.000 ;
    END
  END rx_data[312]
  PIN rx_data[313]
    DIRECTION OUTPUT TRISTATE ;
    USE SIGNAL ;
    ANTENNADIFFAREA 0.795200 ;
    PORT
      LAYER met3 ;
        RECT 0.000 1307.000 2.000 1307.600 ;
    END
  END rx_data[313]
  PIN rx_data[314]
    DIRECTION OUTPUT TRISTATE ;
    USE SIGNAL ;
    ANTENNADIFFAREA 0.795200 ;
    PORT
      LAYER met3 ;
        RECT 1498.000 1142.440 1500.000 1143.040 ;
    END
  END rx_data[314]
  PIN rx_data[315]
    DIRECTION OUTPUT TRISTATE ;
    USE SIGNAL ;
    ANTENNADIFFAREA 0.795200 ;
    PORT
      LAYER met2 ;
        RECT 1342.830 1498.000 1343.110 1500.000 ;
    END
  END rx_data[315]
  PIN rx_data[316]
    DIRECTION OUTPUT TRISTATE ;
    USE SIGNAL ;
    ANTENNADIFFAREA 0.795200 ;
    PORT
      LAYER met3 ;
        RECT 0.000 1262.120 2.000 1262.720 ;
    END
  END rx_data[316]
  PIN rx_data[317]
    DIRECTION OUTPUT TRISTATE ;
    USE SIGNAL ;
    ANTENNADIFFAREA 0.795200 ;
    PORT
      LAYER met3 ;
        RECT 0.000 1453.880 2.000 1454.480 ;
    END
  END rx_data[317]
  PIN rx_data[318]
    DIRECTION OUTPUT TRISTATE ;
    USE SIGNAL ;
    ANTENNADIFFAREA 0.795200 ;
    PORT
      LAYER met2 ;
        RECT 1269.690 0.000 1269.970 2.000 ;
    END
  END rx_data[318]
  PIN rx_data[319]
    DIRECTION OUTPUT TRISTATE ;
    USE SIGNAL ;
    ANTENNADIFFAREA 0.795200 ;
    PORT
      LAYER met3 ;
        RECT 1498.000 735.800 1500.000 736.400 ;
    END
  END rx_data[319]
  PIN rx_data[31]
    DIRECTION OUTPUT TRISTATE ;
    USE SIGNAL ;
    ANTENNADIFFAREA 0.795200 ;
    PORT
      LAYER met3 ;
        RECT 1498.000 1456.600 1500.000 1457.200 ;
    END
  END rx_data[31]
  PIN rx_data[320]
    DIRECTION OUTPUT TRISTATE ;
    USE SIGNAL ;
    ANTENNADIFFAREA 0.795200 ;
    PORT
      LAYER met3 ;
        RECT 0.000 65.320 2.000 65.920 ;
    END
  END rx_data[320]
  PIN rx_data[321]
    DIRECTION OUTPUT TRISTATE ;
    USE SIGNAL ;
    ANTENNADIFFAREA 0.795200 ;
    PORT
      LAYER met2 ;
        RECT 1094.430 0.000 1094.710 2.000 ;
    END
  END rx_data[321]
  PIN rx_data[322]
    DIRECTION OUTPUT TRISTATE ;
    USE SIGNAL ;
    ANTENNADIFFAREA 0.795200 ;
    PORT
      LAYER met2 ;
        RECT 668.010 0.000 668.290 2.000 ;
    END
  END rx_data[322]
  PIN rx_data[323]
    DIRECTION OUTPUT TRISTATE ;
    USE SIGNAL ;
    ANTENNADIFFAREA 0.795200 ;
    PORT
      LAYER met2 ;
        RECT 128.430 0.000 128.710 2.000 ;
    END
  END rx_data[323]
  PIN rx_data[324]
    DIRECTION OUTPUT TRISTATE ;
    USE SIGNAL ;
    ANTENNADIFFAREA 0.795200 ;
    PORT
      LAYER met3 ;
        RECT 0.000 1083.960 2.000 1084.560 ;
    END
  END rx_data[324]
  PIN rx_data[325]
    DIRECTION OUTPUT TRISTATE ;
    USE SIGNAL ;
    ANTENNADIFFAREA 0.795200 ;
    PORT
      LAYER met3 ;
        RECT 0.000 602.520 2.000 603.120 ;
    END
  END rx_data[325]
  PIN rx_data[326]
    DIRECTION OUTPUT TRISTATE ;
    USE SIGNAL ;
    ANTENNADIFFAREA 0.795200 ;
    PORT
      LAYER met2 ;
        RECT 777.030 1498.000 777.310 1500.000 ;
    END
  END rx_data[326]
  PIN rx_data[327]
    DIRECTION OUTPUT TRISTATE ;
    USE SIGNAL ;
    ANTENNADIFFAREA 0.795200 ;
    PORT
      LAYER met3 ;
        RECT 0.000 1089.400 2.000 1090.000 ;
    END
  END rx_data[327]
  PIN rx_data[328]
    DIRECTION OUTPUT TRISTATE ;
    USE SIGNAL ;
    ANTENNADIFFAREA 0.795200 ;
    PORT
      LAYER met2 ;
        RECT 1341.450 0.000 1341.730 2.000 ;
    END
  END rx_data[328]
  PIN rx_data[329]
    DIRECTION OUTPUT TRISTATE ;
    USE SIGNAL ;
    ANTENNADIFFAREA 0.795200 ;
    PORT
      LAYER met2 ;
        RECT 1404.930 1498.000 1405.210 1500.000 ;
    END
  END rx_data[329]
  PIN rx_data[32]
    DIRECTION OUTPUT TRISTATE ;
    USE SIGNAL ;
    ANTENNADIFFAREA 0.795200 ;
    PORT
      LAYER met2 ;
        RECT 1110.990 0.000 1111.270 2.000 ;
    END
  END rx_data[32]
  PIN rx_data[330]
    DIRECTION OUTPUT TRISTATE ;
    USE SIGNAL ;
    ANTENNADIFFAREA 0.795200 ;
    PORT
      LAYER met2 ;
        RECT 5.610 1498.000 5.890 1500.000 ;
    END
  END rx_data[330]
  PIN rx_data[331]
    DIRECTION OUTPUT TRISTATE ;
    USE SIGNAL ;
    ANTENNADIFFAREA 0.795200 ;
    PORT
      LAYER met3 ;
        RECT 0.000 526.360 2.000 526.960 ;
    END
  END rx_data[331]
  PIN rx_data[332]
    DIRECTION OUTPUT TRISTATE ;
    USE SIGNAL ;
    ANTENNADIFFAREA 0.795200 ;
    PORT
      LAYER met3 ;
        RECT 0.000 197.240 2.000 197.840 ;
    END
  END rx_data[332]
  PIN rx_data[333]
    DIRECTION OUTPUT TRISTATE ;
    USE SIGNAL ;
    ANTENNADIFFAREA 0.795200 ;
    PORT
      LAYER met3 ;
        RECT 0.000 1433.480 2.000 1434.080 ;
    END
  END rx_data[333]
  PIN rx_data[334]
    DIRECTION OUTPUT TRISTATE ;
    USE SIGNAL ;
    ANTENNADIFFAREA 0.795200 ;
    PORT
      LAYER met3 ;
        RECT 1498.000 1425.320 1500.000 1425.920 ;
    END
  END rx_data[334]
  PIN rx_data[335]
    DIRECTION OUTPUT TRISTATE ;
    USE SIGNAL ;
    ANTENNADIFFAREA 0.795200 ;
    PORT
      LAYER met2 ;
        RECT 899.850 1498.000 900.130 1500.000 ;
    END
  END rx_data[335]
  PIN rx_data[336]
    DIRECTION OUTPUT TRISTATE ;
    USE SIGNAL ;
    ANTENNADIFFAREA 0.795200 ;
    PORT
      LAYER met2 ;
        RECT 1018.530 1498.000 1018.810 1500.000 ;
    END
  END rx_data[336]
  PIN rx_data[337]
    DIRECTION OUTPUT TRISTATE ;
    USE SIGNAL ;
    ANTENNADIFFAREA 0.795200 ;
    PORT
      LAYER met3 ;
        RECT 1498.000 919.400 1500.000 920.000 ;
    END
  END rx_data[337]
  PIN rx_data[338]
    DIRECTION OUTPUT TRISTATE ;
    USE SIGNAL ;
    ANTENNADIFFAREA 0.795200 ;
    PORT
      LAYER met2 ;
        RECT 730.110 0.000 730.390 2.000 ;
    END
  END rx_data[338]
  PIN rx_data[339]
    DIRECTION OUTPUT TRISTATE ;
    USE SIGNAL ;
    ANTENNADIFFAREA 0.795200 ;
    PORT
      LAYER met3 ;
        RECT 0.000 1444.360 2.000 1444.960 ;
    END
  END rx_data[339]
  PIN rx_data[33]
    DIRECTION OUTPUT TRISTATE ;
    USE SIGNAL ;
    ANTENNADIFFAREA 0.795200 ;
    PORT
      LAYER met3 ;
        RECT 0.000 1266.200 2.000 1266.800 ;
    END
  END rx_data[33]
  PIN rx_data[340]
    DIRECTION OUTPUT TRISTATE ;
    USE SIGNAL ;
    ANTENNADIFFAREA 0.795200 ;
    PORT
      LAYER met2 ;
        RECT 514.830 1498.000 515.110 1500.000 ;
    END
  END rx_data[340]
  PIN rx_data[341]
    DIRECTION OUTPUT TRISTATE ;
    USE SIGNAL ;
    ANTENNADIFFAREA 0.795200 ;
    PORT
      LAYER met2 ;
        RECT 1465.650 1498.000 1465.930 1500.000 ;
    END
  END rx_data[341]
  PIN rx_data[342]
    DIRECTION OUTPUT TRISTATE ;
    USE SIGNAL ;
    ANTENNADIFFAREA 0.795200 ;
    PORT
      LAYER met3 ;
        RECT 1498.000 138.760 1500.000 139.360 ;
    END
  END rx_data[342]
  PIN rx_data[343]
    DIRECTION OUTPUT TRISTATE ;
    USE SIGNAL ;
    ANTENNADIFFAREA 0.795200 ;
    PORT
      LAYER met3 ;
        RECT 1498.000 508.680 1500.000 509.280 ;
    END
  END rx_data[343]
  PIN rx_data[344]
    DIRECTION OUTPUT TRISTATE ;
    USE SIGNAL ;
    ANTENNADIFFAREA 0.795200 ;
    PORT
      LAYER met3 ;
        RECT 1498.000 77.560 1500.000 78.160 ;
    END
  END rx_data[344]
  PIN rx_data[345]
    DIRECTION OUTPUT TRISTATE ;
    USE SIGNAL ;
    ANTENNADIFFAREA 0.795200 ;
    PORT
      LAYER met3 ;
        RECT 1498.000 680.040 1500.000 680.640 ;
    END
  END rx_data[345]
  PIN rx_data[346]
    DIRECTION OUTPUT TRISTATE ;
    USE SIGNAL ;
    ANTENNADIFFAREA 0.795200 ;
    PORT
      LAYER met3 ;
        RECT 0.000 429.800 2.000 430.400 ;
    END
  END rx_data[346]
  PIN rx_data[347]
    DIRECTION OUTPUT TRISTATE ;
    USE SIGNAL ;
    ANTENNADIFFAREA 0.795200 ;
    PORT
      LAYER met3 ;
        RECT 1498.000 832.360 1500.000 832.960 ;
    END
  END rx_data[347]
  PIN rx_data[348]
    DIRECTION OUTPUT TRISTATE ;
    USE SIGNAL ;
    ANTENNADIFFAREA 0.795200 ;
    PORT
      LAYER met2 ;
        RECT 1235.190 1498.000 1235.470 1500.000 ;
    END
  END rx_data[348]
  PIN rx_data[349]
    DIRECTION OUTPUT TRISTATE ;
    USE SIGNAL ;
    ANTENNADIFFAREA 0.795200 ;
    PORT
      LAYER met3 ;
        RECT 0.000 1003.720 2.000 1004.320 ;
    END
  END rx_data[349]
  PIN rx_data[34]
    DIRECTION OUTPUT TRISTATE ;
    USE SIGNAL ;
    ANTENNADIFFAREA 0.795200 ;
    PORT
      LAYER met3 ;
        RECT 1498.000 990.120 1500.000 990.720 ;
    END
  END rx_data[34]
  PIN rx_data[350]
    DIRECTION OUTPUT TRISTATE ;
    USE SIGNAL ;
    ANTENNADIFFAREA 0.795200 ;
    PORT
      LAYER met3 ;
        RECT 0.000 384.920 2.000 385.520 ;
    END
  END rx_data[350]
  PIN rx_data[351]
    DIRECTION OUTPUT TRISTATE ;
    USE SIGNAL ;
    ANTENNADIFFAREA 0.795200 ;
    PORT
      LAYER met2 ;
        RECT 51.150 1498.000 51.430 1500.000 ;
    END
  END rx_data[351]
  PIN rx_data[352]
    DIRECTION OUTPUT TRISTATE ;
    USE SIGNAL ;
    ANTENNADIFFAREA 0.795200 ;
    PORT
      LAYER met2 ;
        RECT 663.870 1498.000 664.150 1500.000 ;
    END
  END rx_data[352]
  PIN rx_data[353]
    DIRECTION OUTPUT TRISTATE ;
    USE SIGNAL ;
    ANTENNADIFFAREA 0.795200 ;
    PORT
      LAYER met2 ;
        RECT 1003.350 1498.000 1003.630 1500.000 ;
    END
  END rx_data[353]
  PIN rx_data[354]
    DIRECTION OUTPUT TRISTATE ;
    USE SIGNAL ;
    ANTENNADIFFAREA 0.795200 ;
    PORT
      LAYER met2 ;
        RECT 324.390 1498.000 324.670 1500.000 ;
    END
  END rx_data[354]
  PIN rx_data[355]
    DIRECTION OUTPUT TRISTATE ;
    USE SIGNAL ;
    ANTENNADIFFAREA 0.795200 ;
    PORT
      LAYER met3 ;
        RECT 1498.000 624.280 1500.000 624.880 ;
    END
  END rx_data[355]
  PIN rx_data[356]
    DIRECTION OUTPUT TRISTATE ;
    USE SIGNAL ;
    ANTENNADIFFAREA 0.795200 ;
    PORT
      LAYER met2 ;
        RECT 513.450 0.000 513.730 2.000 ;
    END
  END rx_data[356]
  PIN rx_data[357]
    DIRECTION OUTPUT TRISTATE ;
    USE SIGNAL ;
    ANTENNADIFFAREA 0.795200 ;
    PORT
      LAYER met3 ;
        RECT 0.000 420.280 2.000 420.880 ;
    END
  END rx_data[357]
  PIN rx_data[358]
    DIRECTION OUTPUT TRISTATE ;
    USE SIGNAL ;
    ANTENNADIFFAREA 0.795200 ;
    PORT
      LAYER met2 ;
        RECT 792.210 0.000 792.490 2.000 ;
    END
  END rx_data[358]
  PIN rx_data[359]
    DIRECTION OUTPUT TRISTATE ;
    USE SIGNAL ;
    ANTENNADIFFAREA 0.795200 ;
    PORT
      LAYER met2 ;
        RECT 143.610 0.000 143.890 2.000 ;
    END
  END rx_data[359]
  PIN rx_data[35]
    DIRECTION OUTPUT TRISTATE ;
    USE SIGNAL ;
    ANTENNADIFFAREA 0.795200 ;
    PORT
      LAYER met2 ;
        RECT 483.090 1498.000 483.370 1500.000 ;
    END
  END rx_data[35]
  PIN rx_data[360]
    DIRECTION OUTPUT TRISTATE ;
    USE SIGNAL ;
    ANTENNADIFFAREA 0.795200 ;
    PORT
      LAYER met3 ;
        RECT 1498.000 928.920 1500.000 929.520 ;
    END
  END rx_data[360]
  PIN rx_data[361]
    DIRECTION OUTPUT TRISTATE ;
    USE SIGNAL ;
    ANTENNADIFFAREA 0.795200 ;
    PORT
      LAYER met2 ;
        RECT 1028.190 0.000 1028.470 2.000 ;
    END
  END rx_data[361]
  PIN rx_data[362]
    DIRECTION OUTPUT TRISTATE ;
    USE SIGNAL ;
    ANTENNADIFFAREA 0.795200 ;
    PORT
      LAYER met2 ;
        RECT 863.970 0.000 864.250 2.000 ;
    END
  END rx_data[362]
  PIN rx_data[363]
    DIRECTION OUTPUT TRISTATE ;
    USE SIGNAL ;
    ANTENNADIFFAREA 0.795200 ;
    PORT
      LAYER met3 ;
        RECT 1498.000 209.480 1500.000 210.080 ;
    END
  END rx_data[363]
  PIN rx_data[364]
    DIRECTION OUTPUT TRISTATE ;
    USE SIGNAL ;
    ANTENNADIFFAREA 0.795200 ;
    PORT
      LAYER met2 ;
        RECT 365.790 1498.000 366.070 1500.000 ;
    END
  END rx_data[364]
  PIN rx_data[365]
    DIRECTION OUTPUT TRISTATE ;
    USE SIGNAL ;
    ANTENNADIFFAREA 0.795200 ;
    PORT
      LAYER met3 ;
        RECT 0.000 369.960 2.000 370.560 ;
    END
  END rx_data[365]
  PIN rx_data[366]
    DIRECTION OUTPUT TRISTATE ;
    USE SIGNAL ;
    ANTENNADIFFAREA 0.795200 ;
    PORT
      LAYER met3 ;
        RECT 1498.000 233.960 1500.000 234.560 ;
    END
  END rx_data[366]
  PIN rx_data[367]
    DIRECTION OUTPUT TRISTATE ;
    USE SIGNAL ;
    ANTENNADIFFAREA 0.795200 ;
    PORT
      LAYER met2 ;
        RECT 1033.710 1498.000 1033.990 1500.000 ;
    END
  END rx_data[367]
  PIN rx_data[368]
    DIRECTION OUTPUT TRISTATE ;
    USE SIGNAL ;
    ANTENNADIFFAREA 0.795200 ;
    PORT
      LAYER met2 ;
        RECT 45.630 1498.000 45.910 1500.000 ;
    END
  END rx_data[368]
  PIN rx_data[369]
    DIRECTION OUTPUT TRISTATE ;
    USE SIGNAL ;
    ANTENNADIFFAREA 0.795200 ;
    PORT
      LAYER met3 ;
        RECT 1498.000 884.040 1500.000 884.640 ;
    END
  END rx_data[369]
  PIN rx_data[36]
    DIRECTION OUTPUT TRISTATE ;
    USE SIGNAL ;
    ANTENNADIFFAREA 0.795200 ;
    PORT
      LAYER met3 ;
        RECT 0.000 9.560 2.000 10.160 ;
    END
  END rx_data[36]
  PIN rx_data[370]
    DIRECTION OUTPUT TRISTATE ;
    USE SIGNAL ;
    ANTENNADIFFAREA 0.795200 ;
    PORT
      LAYER met3 ;
        RECT 1498.000 568.520 1500.000 569.120 ;
    END
  END rx_data[370]
  PIN rx_data[371]
    DIRECTION OUTPUT TRISTATE ;
    USE SIGNAL ;
    ANTENNADIFFAREA 0.795200 ;
    PORT
      LAYER met3 ;
        RECT 1498.000 270.680 1500.000 271.280 ;
    END
  END rx_data[371]
  PIN rx_data[372]
    DIRECTION OUTPUT TRISTATE ;
    USE SIGNAL ;
    ANTENNADIFFAREA 0.795200 ;
    PORT
      LAYER met2 ;
        RECT 735.630 1498.000 735.910 1500.000 ;
    END
  END rx_data[372]
  PIN rx_data[373]
    DIRECTION OUTPUT TRISTATE ;
    USE SIGNAL ;
    ANTENNADIFFAREA 0.795200 ;
    PORT
      LAYER met2 ;
        RECT 96.690 0.000 96.970 2.000 ;
    END
  END rx_data[373]
  PIN rx_data[374]
    DIRECTION OUTPUT TRISTATE ;
    USE SIGNAL ;
    ANTENNADIFFAREA 0.795200 ;
    PORT
      LAYER met3 ;
        RECT 0.000 851.400 2.000 852.000 ;
    END
  END rx_data[374]
  PIN rx_data[375]
    DIRECTION OUTPUT TRISTATE ;
    USE SIGNAL ;
    ANTENNADIFFAREA 0.795200 ;
    PORT
      LAYER met2 ;
        RECT 185.010 0.000 185.290 2.000 ;
    END
  END rx_data[375]
  PIN rx_data[376]
    DIRECTION OUTPUT TRISTATE ;
    USE SIGNAL ;
    ANTENNADIFFAREA 0.795200 ;
    PORT
      LAYER met2 ;
        RECT 1435.290 1498.000 1435.570 1500.000 ;
    END
  END rx_data[376]
  PIN rx_data[377]
    DIRECTION OUTPUT TRISTATE ;
    USE SIGNAL ;
    ANTENNADIFFAREA 0.795200 ;
    PORT
      LAYER met3 ;
        RECT 1498.000 635.160 1500.000 635.760 ;
    END
  END rx_data[377]
  PIN rx_data[378]
    DIRECTION OUTPUT TRISTATE ;
    USE SIGNAL ;
    ANTENNADIFFAREA 0.795200 ;
    PORT
      LAYER met2 ;
        RECT 756.330 1498.000 756.610 1500.000 ;
    END
  END rx_data[378]
  PIN rx_data[379]
    DIRECTION OUTPUT TRISTATE ;
    USE SIGNAL ;
    ANTENNADIFFAREA 0.795200 ;
    PORT
      LAYER met3 ;
        RECT 1498.000 1389.960 1500.000 1390.560 ;
    END
  END rx_data[379]
  PIN rx_data[37]
    DIRECTION OUTPUT TRISTATE ;
    USE SIGNAL ;
    ANTENNADIFFAREA 0.795200 ;
    PORT
      LAYER met3 ;
        RECT 0.000 1115.240 2.000 1115.840 ;
    END
  END rx_data[37]
  PIN rx_data[380]
    DIRECTION OUTPUT TRISTATE ;
    USE SIGNAL ;
    ANTENNADIFFAREA 0.795200 ;
    PORT
      LAYER met3 ;
        RECT 0.000 1362.760 2.000 1363.360 ;
    END
  END rx_data[380]
  PIN rx_data[381]
    DIRECTION OUTPUT TRISTATE ;
    USE SIGNAL ;
    ANTENNADIFFAREA 0.795200 ;
    PORT
      LAYER met2 ;
        RECT 1250.370 1498.000 1250.650 1500.000 ;
    END
  END rx_data[381]
  PIN rx_data[382]
    DIRECTION OUTPUT TRISTATE ;
    USE SIGNAL ;
    ANTENNADIFFAREA 0.795200 ;
    PORT
      LAYER met2 ;
        RECT 1420.110 1498.000 1420.390 1500.000 ;
    END
  END rx_data[382]
  PIN rx_data[383]
    DIRECTION OUTPUT TRISTATE ;
    USE SIGNAL ;
    ANTENNADIFFAREA 0.795200 ;
    PORT
      LAYER met2 ;
        RECT 1188.270 1498.000 1188.550 1500.000 ;
    END
  END rx_data[383]
  PIN rx_data[384]
    DIRECTION OUTPUT TRISTATE ;
    USE SIGNAL ;
    ANTENNADIFFAREA 0.795200 ;
    PORT
      LAYER met2 ;
        RECT 724.590 0.000 724.870 2.000 ;
    END
  END rx_data[384]
  PIN rx_data[385]
    DIRECTION OUTPUT TRISTATE ;
    USE SIGNAL ;
    ANTENNADIFFAREA 0.795200 ;
    PORT
      LAYER met2 ;
        RECT 194.670 0.000 194.950 2.000 ;
    END
  END rx_data[385]
  PIN rx_data[386]
    DIRECTION OUTPUT TRISTATE ;
    USE SIGNAL ;
    ANTENNADIFFAREA 0.795200 ;
    PORT
      LAYER met2 ;
        RECT 456.870 0.000 457.150 2.000 ;
    END
  END rx_data[386]
  PIN rx_data[387]
    DIRECTION OUTPUT TRISTATE ;
    USE SIGNAL ;
    ANTENNADIFFAREA 0.795200 ;
    PORT
      LAYER met3 ;
        RECT 1498.000 1202.280 1500.000 1202.880 ;
    END
  END rx_data[387]
  PIN rx_data[388]
    DIRECTION OUTPUT TRISTATE ;
    USE SIGNAL ;
    ANTENNADIFFAREA 0.795200 ;
    PORT
      LAYER met2 ;
        RECT 452.730 1498.000 453.010 1500.000 ;
    END
  END rx_data[388]
  PIN rx_data[389]
    DIRECTION OUTPUT TRISTATE ;
    USE SIGNAL ;
    ANTENNADIFFAREA 0.795200 ;
    PORT
      LAYER met2 ;
        RECT 596.250 1498.000 596.530 1500.000 ;
    END
  END rx_data[389]
  PIN rx_data[38]
    DIRECTION OUTPUT TRISTATE ;
    USE SIGNAL ;
    ANTENNADIFFAREA 0.795200 ;
    PORT
      LAYER met2 ;
        RECT 869.490 1498.000 869.770 1500.000 ;
    END
  END rx_data[38]
  PIN rx_data[390]
    DIRECTION OUTPUT TRISTATE ;
    USE SIGNAL ;
    ANTENNADIFFAREA 0.795200 ;
    PORT
      LAYER met2 ;
        RECT 416.850 1498.000 417.130 1500.000 ;
    END
  END rx_data[390]
  PIN rx_data[391]
    DIRECTION OUTPUT TRISTATE ;
    USE SIGNAL ;
    ANTENNADIFFAREA 0.795200 ;
    PORT
      LAYER met2 ;
        RECT 833.610 1498.000 833.890 1500.000 ;
    END
  END rx_data[391]
  PIN rx_data[392]
    DIRECTION OUTPUT TRISTATE ;
    USE SIGNAL ;
    ANTENNADIFFAREA 0.795200 ;
    PORT
      LAYER met3 ;
        RECT 1498.000 183.640 1500.000 184.240 ;
    END
  END rx_data[392]
  PIN rx_data[393]
    DIRECTION OUTPUT TRISTATE ;
    USE SIGNAL ;
    ANTENNADIFFAREA 0.795200 ;
    PORT
      LAYER met3 ;
        RECT 0.000 1180.520 2.000 1181.120 ;
    END
  END rx_data[393]
  PIN rx_data[394]
    DIRECTION OUTPUT TRISTATE ;
    USE SIGNAL ;
    ANTENNADIFFAREA 0.795200 ;
    PORT
      LAYER met3 ;
        RECT 0.000 719.480 2.000 720.080 ;
    END
  END rx_data[394]
  PIN rx_data[395]
    DIRECTION OUTPUT TRISTATE ;
    USE SIGNAL ;
    ANTENNADIFFAREA 0.795200 ;
    PORT
      LAYER met3 ;
        RECT 0.000 836.440 2.000 837.040 ;
    END
  END rx_data[395]
  PIN rx_data[396]
    DIRECTION OUTPUT TRISTATE ;
    USE SIGNAL ;
    ANTENNADIFFAREA 0.795200 ;
    PORT
      LAYER met3 ;
        RECT 0.000 764.360 2.000 764.960 ;
    END
  END rx_data[396]
  PIN rx_data[397]
    DIRECTION OUTPUT TRISTATE ;
    USE SIGNAL ;
    ANTENNADIFFAREA 0.795200 ;
    PORT
      LAYER met2 ;
        RECT 1156.530 0.000 1156.810 2.000 ;
    END
  END rx_data[397]
  PIN rx_data[398]
    DIRECTION OUTPUT TRISTATE ;
    USE SIGNAL ;
    ANTENNADIFFAREA 0.795200 ;
    PORT
      LAYER met2 ;
        RECT 20.790 1498.000 21.070 1500.000 ;
    END
  END rx_data[398]
  PIN rx_data[399]
    DIRECTION OUTPUT TRISTATE ;
    USE SIGNAL ;
    ANTENNADIFFAREA 0.795200 ;
    PORT
      LAYER met2 ;
        RECT 684.570 1498.000 684.850 1500.000 ;
    END
  END rx_data[399]
  PIN rx_data[39]
    DIRECTION OUTPUT TRISTATE ;
    USE SIGNAL ;
    ANTENNADIFFAREA 0.795200 ;
    PORT
      LAYER met2 ;
        RECT 745.290 0.000 745.570 2.000 ;
    END
  END rx_data[39]
  PIN rx_data[3]
    DIRECTION OUTPUT TRISTATE ;
    USE SIGNAL ;
    ANTENNADIFFAREA 0.795200 ;
    PORT
      LAYER met2 ;
        RECT 271.950 1498.000 272.230 1500.000 ;
    END
  END rx_data[3]
  PIN rx_data[400]
    DIRECTION OUTPUT TRISTATE ;
    USE SIGNAL ;
    ANTENNADIFFAREA 0.795200 ;
    PORT
      LAYER met2 ;
        RECT 179.490 1498.000 179.770 1500.000 ;
    END
  END rx_data[400]
  PIN rx_data[401]
    DIRECTION OUTPUT TRISTATE ;
    USE SIGNAL ;
    ANTENNADIFFAREA 0.795200 ;
    PORT
      LAYER met3 ;
        RECT 1498.000 888.120 1500.000 888.720 ;
    END
  END rx_data[401]
  PIN rx_data[402]
    DIRECTION OUTPUT TRISTATE ;
    USE SIGNAL ;
    ANTENNADIFFAREA 0.795200 ;
    PORT
      LAYER met2 ;
        RECT 1316.610 1498.000 1316.890 1500.000 ;
    END
  END rx_data[402]
  PIN rx_data[403]
    DIRECTION OUTPUT TRISTATE ;
    USE SIGNAL ;
    ANTENNADIFFAREA 0.795200 ;
    PORT
      LAYER met2 ;
        RECT 1171.710 0.000 1171.990 2.000 ;
    END
  END rx_data[403]
  PIN rx_data[404]
    DIRECTION OUTPUT TRISTATE ;
    USE SIGNAL ;
    ANTENNADIFFAREA 0.795200 ;
    PORT
      LAYER met2 ;
        RECT 1301.430 1498.000 1301.710 1500.000 ;
    END
  END rx_data[404]
  PIN rx_data[405]
    DIRECTION OUTPUT TRISTATE ;
    USE SIGNAL ;
    ANTENNADIFFAREA 0.795200 ;
    PORT
      LAYER met2 ;
        RECT 1008.870 1498.000 1009.150 1500.000 ;
    END
  END rx_data[405]
  PIN rx_data[406]
    DIRECTION OUTPUT TRISTATE ;
    USE SIGNAL ;
    ANTENNADIFFAREA 0.795200 ;
    PORT
      LAYER met3 ;
        RECT 1498.000 579.400 1500.000 580.000 ;
    END
  END rx_data[406]
  PIN rx_data[407]
    DIRECTION OUTPUT TRISTATE ;
    USE SIGNAL ;
    ANTENNADIFFAREA 0.795200 ;
    PORT
      LAYER met3 ;
        RECT 1498.000 913.960 1500.000 914.560 ;
    END
  END rx_data[407]
  PIN rx_data[408]
    DIRECTION OUTPUT TRISTATE ;
    USE SIGNAL ;
    ANTENNADIFFAREA 0.795200 ;
    PORT
      LAYER met2 ;
        RECT 364.410 0.000 364.690 2.000 ;
    END
  END rx_data[408]
  PIN rx_data[409]
    DIRECTION OUTPUT TRISTATE ;
    USE SIGNAL ;
    ANTENNADIFFAREA 0.795200 ;
    PORT
      LAYER met3 ;
        RECT 0.000 359.080 2.000 359.680 ;
    END
  END rx_data[409]
  PIN rx_data[40]
    DIRECTION OUTPUT TRISTATE ;
    USE SIGNAL ;
    ANTENNADIFFAREA 0.795200 ;
    PORT
      LAYER met2 ;
        RECT 1095.810 1498.000 1096.090 1500.000 ;
    END
  END rx_data[40]
  PIN rx_data[410]
    DIRECTION OUTPUT TRISTATE ;
    USE SIGNAL ;
    ANTENNADIFFAREA 0.795200 ;
    PORT
      LAYER met3 ;
        RECT 1498.000 497.800 1500.000 498.400 ;
    END
  END rx_data[410]
  PIN rx_data[411]
    DIRECTION OUTPUT TRISTATE ;
    USE SIGNAL ;
    ANTENNADIFFAREA 0.795200 ;
    PORT
      LAYER met3 ;
        RECT 0.000 1286.600 2.000 1287.200 ;
    END
  END rx_data[411]
  PIN rx_data[412]
    DIRECTION OUTPUT TRISTATE ;
    USE SIGNAL ;
    ANTENNADIFFAREA 0.795200 ;
    PORT
      LAYER met2 ;
        RECT 349.230 1498.000 349.510 1500.000 ;
    END
  END rx_data[412]
  PIN rx_data[413]
    DIRECTION OUTPUT TRISTATE ;
    USE SIGNAL ;
    ANTENNADIFFAREA 0.795200 ;
    PORT
      LAYER met3 ;
        RECT 1498.000 36.760 1500.000 37.360 ;
    END
  END rx_data[413]
  PIN rx_data[414]
    DIRECTION OUTPUT TRISTATE ;
    USE SIGNAL ;
    ANTENNADIFFAREA 0.795200 ;
    PORT
      LAYER met2 ;
        RECT 75.990 0.000 76.270 2.000 ;
    END
  END rx_data[414]
  PIN rx_data[415]
    DIRECTION OUTPUT TRISTATE ;
    USE SIGNAL ;
    ANTENNADIFFAREA 0.795200 ;
    PORT
      LAYER met2 ;
        RECT 458.250 1498.000 458.530 1500.000 ;
    END
  END rx_data[415]
  PIN rx_data[416]
    DIRECTION OUTPUT TRISTATE ;
    USE SIGNAL ;
    ANTENNADIFFAREA 0.795200 ;
    PORT
      LAYER met3 ;
        RECT 1498.000 467.880 1500.000 468.480 ;
    END
  END rx_data[416]
  PIN rx_data[417]
    DIRECTION OUTPUT TRISTATE ;
    USE SIGNAL ;
    ANTENNADIFFAREA 0.795200 ;
    PORT
      LAYER met2 ;
        RECT 1326.270 0.000 1326.550 2.000 ;
    END
  END rx_data[417]
  PIN rx_data[418]
    DIRECTION OUTPUT TRISTATE ;
    USE SIGNAL ;
    ANTENNADIFFAREA 0.795200 ;
    PORT
      LAYER met3 ;
        RECT 0.000 987.400 2.000 988.000 ;
    END
  END rx_data[418]
  PIN rx_data[419]
    DIRECTION OUTPUT TRISTATE ;
    USE SIGNAL ;
    ANTENNADIFFAREA 0.795200 ;
    PORT
      LAYER met3 ;
        RECT 1498.000 655.560 1500.000 656.160 ;
    END
  END rx_data[419]
  PIN rx_data[41]
    DIRECTION OUTPUT TRISTATE ;
    USE SIGNAL ;
    ANTENNADIFFAREA 0.795200 ;
    PORT
      LAYER met2 ;
        RECT 1471.170 0.000 1471.450 2.000 ;
    END
  END rx_data[41]
  PIN rx_data[420]
    DIRECTION OUTPUT TRISTATE ;
    USE SIGNAL ;
    ANTENNADIFFAREA 0.795200 ;
    PORT
      LAYER met3 ;
        RECT 0.000 278.840 2.000 279.440 ;
    END
  END rx_data[420]
  PIN rx_data[421]
    DIRECTION OUTPUT TRISTATE ;
    USE SIGNAL ;
    ANTENNADIFFAREA 0.795200 ;
    PORT
      LAYER met2 ;
        RECT 1229.670 1498.000 1229.950 1500.000 ;
    END
  END rx_data[421]
  PIN rx_data[422]
    DIRECTION OUTPUT TRISTATE ;
    USE SIGNAL ;
    ANTENNADIFFAREA 0.795200 ;
    PORT
      LAYER met3 ;
        RECT 0.000 597.080 2.000 597.680 ;
    END
  END rx_data[422]
  PIN rx_data[423]
    DIRECTION OUTPUT TRISTATE ;
    USE SIGNAL ;
    ANTENNADIFFAREA 0.795200 ;
    PORT
      LAYER met3 ;
        RECT 0.000 992.840 2.000 993.440 ;
    END
  END rx_data[423]
  PIN rx_data[424]
    DIRECTION OUTPUT TRISTATE ;
    USE SIGNAL ;
    ANTENNADIFFAREA 0.795200 ;
    PORT
      LAYER met3 ;
        RECT 1498.000 250.280 1500.000 250.880 ;
    END
  END rx_data[424]
  PIN rx_data[425]
    DIRECTION OUTPUT TRISTATE ;
    USE SIGNAL ;
    ANTENNADIFFAREA 0.795200 ;
    PORT
      LAYER met2 ;
        RECT 282.990 1498.000 283.270 1500.000 ;
    END
  END rx_data[425]
  PIN rx_data[426]
    DIRECTION OUTPUT TRISTATE ;
    USE SIGNAL ;
    ANTENNADIFFAREA 0.795200 ;
    PORT
      LAYER met2 ;
        RECT 45.630 0.000 45.910 2.000 ;
    END
  END rx_data[426]
  PIN rx_data[427]
    DIRECTION OUTPUT TRISTATE ;
    USE SIGNAL ;
    ANTENNADIFFAREA 0.795200 ;
    PORT
      LAYER met3 ;
        RECT 1498.000 756.200 1500.000 756.800 ;
    END
  END rx_data[427]
  PIN rx_data[428]
    DIRECTION OUTPUT TRISTATE ;
    USE SIGNAL ;
    ANTENNADIFFAREA 0.795200 ;
    PORT
      LAYER met3 ;
        RECT 1498.000 330.520 1500.000 331.120 ;
    END
  END rx_data[428]
  PIN rx_data[429]
    DIRECTION OUTPUT TRISTATE ;
    USE SIGNAL ;
    ANTENNADIFFAREA 0.795200 ;
    PORT
      LAYER met3 ;
        RECT 1498.000 716.760 1500.000 717.360 ;
    END
  END rx_data[429]
  PIN rx_data[42]
    DIRECTION OUTPUT TRISTATE ;
    USE SIGNAL ;
    ANTENNADIFFAREA 0.795200 ;
    PORT
      LAYER met2 ;
        RECT 694.230 0.000 694.510 2.000 ;
    END
  END rx_data[42]
  PIN rx_data[430]
    DIRECTION OUTPUT TRISTATE ;
    USE SIGNAL ;
    ANTENNADIFFAREA 0.795200 ;
    PORT
      LAYER met3 ;
        RECT 1498.000 776.600 1500.000 777.200 ;
    END
  END rx_data[430]
  PIN rx_data[431]
    DIRECTION OUTPUT TRISTATE ;
    USE SIGNAL ;
    ANTENNADIFFAREA 0.795200 ;
    PORT
      LAYER met3 ;
        RECT 1498.000 731.720 1500.000 732.320 ;
    END
  END rx_data[431]
  PIN rx_data[432]
    DIRECTION OUTPUT TRISTATE ;
    USE SIGNAL ;
    ANTENNADIFFAREA 0.795200 ;
    PORT
      LAYER met2 ;
        RECT 739.770 0.000 740.050 2.000 ;
    END
  END rx_data[432]
  PIN rx_data[433]
    DIRECTION OUTPUT TRISTATE ;
    USE SIGNAL ;
    ANTENNADIFFAREA 0.795200 ;
    PORT
      LAYER met3 ;
        RECT 1498.000 1228.120 1500.000 1228.720 ;
    END
  END rx_data[433]
  PIN rx_data[434]
    DIRECTION OUTPUT TRISTATE ;
    USE SIGNAL ;
    ANTENNADIFFAREA 0.795200 ;
    PORT
      LAYER met2 ;
        RECT 1362.150 0.000 1362.430 2.000 ;
    END
  END rx_data[434]
  PIN rx_data[435]
    DIRECTION OUTPUT TRISTATE ;
    USE SIGNAL ;
    ANTENNADIFFAREA 0.795200 ;
    PORT
      LAYER met2 ;
        RECT 205.710 0.000 205.990 2.000 ;
    END
  END rx_data[435]
  PIN rx_data[436]
    DIRECTION OUTPUT TRISTATE ;
    USE SIGNAL ;
    ANTENNADIFFAREA 0.795200 ;
    PORT
      LAYER met2 ;
        RECT 884.670 1498.000 884.950 1500.000 ;
    END
  END rx_data[436]
  PIN rx_data[437]
    DIRECTION OUTPUT TRISTATE ;
    USE SIGNAL ;
    ANTENNADIFFAREA 0.795200 ;
    PORT
      LAYER met2 ;
        RECT 1208.970 1498.000 1209.250 1500.000 ;
    END
  END rx_data[437]
  PIN rx_data[438]
    DIRECTION OUTPUT TRISTATE ;
    USE SIGNAL ;
    ANTENNADIFFAREA 0.795200 ;
    PORT
      LAYER met2 ;
        RECT 837.750 0.000 838.030 2.000 ;
    END
  END rx_data[438]
  PIN rx_data[439]
    DIRECTION OUTPUT TRISTATE ;
    USE SIGNAL ;
    ANTENNADIFFAREA 0.795200 ;
    PORT
      LAYER met3 ;
        RECT 0.000 587.560 2.000 588.160 ;
    END
  END rx_data[439]
  PIN rx_data[43]
    DIRECTION OUTPUT TRISTATE ;
    USE SIGNAL ;
    ANTENNADIFFAREA 0.795200 ;
    PORT
      LAYER met3 ;
        RECT 1498.000 1258.040 1500.000 1258.640 ;
    END
  END rx_data[43]
  PIN rx_data[440]
    DIRECTION OUTPUT TRISTATE ;
    USE SIGNAL ;
    ANTENNADIFFAREA 0.795200 ;
    PORT
      LAYER met3 ;
        RECT 0.000 775.240 2.000 775.840 ;
    END
  END rx_data[440]
  PIN rx_data[441]
    DIRECTION OUTPUT TRISTATE ;
    USE SIGNAL ;
    ANTENNADIFFAREA 0.795200 ;
    PORT
      LAYER met2 ;
        RECT 611.430 0.000 611.710 2.000 ;
    END
  END rx_data[441]
  PIN rx_data[442]
    DIRECTION OUTPUT TRISTATE ;
    USE SIGNAL ;
    ANTENNADIFFAREA 0.795200 ;
    PORT
      LAYER met3 ;
        RECT 1498.000 1005.080 1500.000 1005.680 ;
    END
  END rx_data[442]
  PIN rx_data[443]
    DIRECTION OUTPUT TRISTATE ;
    USE SIGNAL ;
    ANTENNADIFFAREA 0.795200 ;
    PORT
      LAYER met2 ;
        RECT 462.390 0.000 462.670 2.000 ;
    END
  END rx_data[443]
  PIN rx_data[444]
    DIRECTION OUTPUT TRISTATE ;
    USE SIGNAL ;
    ANTENNADIFFAREA 0.795200 ;
    PORT
      LAYER met3 ;
        RECT 1498.000 544.040 1500.000 544.640 ;
    END
  END rx_data[444]
  PIN rx_data[445]
    DIRECTION OUTPUT TRISTATE ;
    USE SIGNAL ;
    ANTENNADIFFAREA 0.795200 ;
    PORT
      LAYER met2 ;
        RECT 1475.310 0.000 1475.590 2.000 ;
    END
  END rx_data[445]
  PIN rx_data[446]
    DIRECTION OUTPUT TRISTATE ;
    USE SIGNAL ;
    ANTENNADIFFAREA 0.795200 ;
    PORT
      LAYER met2 ;
        RECT 252.630 1498.000 252.910 1500.000 ;
    END
  END rx_data[446]
  PIN rx_data[447]
    DIRECTION OUTPUT TRISTATE ;
    USE SIGNAL ;
    ANTENNADIFFAREA 0.795200 ;
    PORT
      LAYER met3 ;
        RECT 1498.000 365.880 1500.000 366.480 ;
    END
  END rx_data[447]
  PIN rx_data[448]
    DIRECTION OUTPUT TRISTATE ;
    USE SIGNAL ;
    ANTENNADIFFAREA 0.795200 ;
    PORT
      LAYER met2 ;
        RECT 339.570 1498.000 339.850 1500.000 ;
    END
  END rx_data[448]
  PIN rx_data[449]
    DIRECTION OUTPUT TRISTATE ;
    USE SIGNAL ;
    ANTENNADIFFAREA 0.795200 ;
    PORT
      LAYER met2 ;
        RECT 1435.290 0.000 1435.570 2.000 ;
    END
  END rx_data[449]
  PIN rx_data[44]
    DIRECTION OUTPUT TRISTATE ;
    USE SIGNAL ;
    ANTENNADIFFAREA 0.795200 ;
    PORT
      LAYER met3 ;
        RECT 1498.000 650.120 1500.000 650.720 ;
    END
  END rx_data[44]
  PIN rx_data[450]
    DIRECTION OUTPUT TRISTATE ;
    USE SIGNAL ;
    ANTENNADIFFAREA 0.795200 ;
    PORT
      LAYER met2 ;
        RECT 699.750 1498.000 700.030 1500.000 ;
    END
  END rx_data[450]
  PIN rx_data[451]
    DIRECTION OUTPUT TRISTATE ;
    USE SIGNAL ;
    ANTENNADIFFAREA 0.795200 ;
    PORT
      LAYER met3 ;
        RECT 0.000 816.040 2.000 816.640 ;
    END
  END rx_data[451]
  PIN rx_data[452]
    DIRECTION OUTPUT TRISTATE ;
    USE SIGNAL ;
    ANTENNADIFFAREA 0.795200 ;
    PORT
      LAYER met3 ;
        RECT 0.000 795.640 2.000 796.240 ;
    END
  END rx_data[452]
  PIN rx_data[453]
    DIRECTION OUTPUT TRISTATE ;
    USE SIGNAL ;
    ANTENNADIFFAREA 0.795200 ;
    PORT
      LAYER met3 ;
        RECT 0.000 1054.040 2.000 1054.640 ;
    END
  END rx_data[453]
  PIN rx_data[454]
    DIRECTION OUTPUT TRISTATE ;
    USE SIGNAL ;
    ANTENNADIFFAREA 0.795200 ;
    PORT
      LAYER met3 ;
        RECT 0.000 1409.000 2.000 1409.600 ;
    END
  END rx_data[454]
  PIN rx_data[455]
    DIRECTION OUTPUT TRISTATE ;
    USE SIGNAL ;
    ANTENNADIFFAREA 0.795200 ;
    PORT
      LAYER met2 ;
        RECT 1496.010 0.000 1496.290 2.000 ;
    END
  END rx_data[455]
  PIN rx_data[456]
    DIRECTION OUTPUT TRISTATE ;
    USE SIGNAL ;
    ANTENNADIFFAREA 0.795200 ;
    PORT
      LAYER met2 ;
        RECT 1337.310 0.000 1337.590 2.000 ;
    END
  END rx_data[456]
  PIN rx_data[457]
    DIRECTION OUTPUT TRISTATE ;
    USE SIGNAL ;
    ANTENNADIFFAREA 0.795200 ;
    PORT
      LAYER met2 ;
        RECT 797.730 1498.000 798.010 1500.000 ;
    END
  END rx_data[457]
  PIN rx_data[458]
    DIRECTION OUTPUT TRISTATE ;
    USE SIGNAL ;
    ANTENNADIFFAREA 0.795200 ;
    PORT
      LAYER met3 ;
        RECT 1498.000 1410.360 1500.000 1410.960 ;
    END
  END rx_data[458]
  PIN rx_data[459]
    DIRECTION OUTPUT TRISTATE ;
    USE SIGNAL ;
    ANTENNADIFFAREA 0.795200 ;
    PORT
      LAYER met2 ;
        RECT 1110.990 1498.000 1111.270 1500.000 ;
    END
  END rx_data[459]
  PIN rx_data[45]
    DIRECTION OUTPUT TRISTATE ;
    USE SIGNAL ;
    ANTENNADIFFAREA 0.795200 ;
    PORT
      LAYER met3 ;
        RECT 0.000 440.680 2.000 441.280 ;
    END
  END rx_data[45]
  PIN rx_data[460]
    DIRECTION OUTPUT TRISTATE ;
    USE SIGNAL ;
    ANTENNADIFFAREA 0.795200 ;
    PORT
      LAYER met3 ;
        RECT 1498.000 705.880 1500.000 706.480 ;
    END
  END rx_data[460]
  PIN rx_data[461]
    DIRECTION OUTPUT TRISTATE ;
    USE SIGNAL ;
    ANTENNADIFFAREA 0.795200 ;
    PORT
      LAYER met3 ;
        RECT 1498.000 1131.560 1500.000 1132.160 ;
    END
  END rx_data[461]
  PIN rx_data[462]
    DIRECTION OUTPUT TRISTATE ;
    USE SIGNAL ;
    ANTENNADIFFAREA 0.795200 ;
    PORT
      LAYER met3 ;
        RECT 0.000 931.640 2.000 932.240 ;
    END
  END rx_data[462]
  PIN rx_data[463]
    DIRECTION OUTPUT TRISTATE ;
    USE SIGNAL ;
    ANTENNADIFFAREA 0.795200 ;
    PORT
      LAYER met3 ;
        RECT 1498.000 549.480 1500.000 550.080 ;
    END
  END rx_data[463]
  PIN rx_data[464]
    DIRECTION OUTPUT TRISTATE ;
    USE SIGNAL ;
    ANTENNADIFFAREA 0.795200 ;
    PORT
      LAYER met2 ;
        RECT 60.810 0.000 61.090 2.000 ;
    END
  END rx_data[464]
  PIN rx_data[465]
    DIRECTION OUTPUT TRISTATE ;
    USE SIGNAL ;
    ANTENNADIFFAREA 0.795200 ;
    PORT
      LAYER met2 ;
        RECT 318.870 1498.000 319.150 1500.000 ;
    END
  END rx_data[465]
  PIN rx_data[466]
    DIRECTION OUTPUT TRISTATE ;
    USE SIGNAL ;
    ANTENNADIFFAREA 0.795200 ;
    PORT
      LAYER met3 ;
        RECT 1498.000 934.360 1500.000 934.960 ;
    END
  END rx_data[466]
  PIN rx_data[467]
    DIRECTION OUTPUT TRISTATE ;
    USE SIGNAL ;
    ANTENNADIFFAREA 0.795200 ;
    PORT
      LAYER met3 ;
        RECT 1498.000 746.680 1500.000 747.280 ;
    END
  END rx_data[467]
  PIN rx_data[468]
    DIRECTION OUTPUT TRISTATE ;
    USE SIGNAL ;
    ANTENNADIFFAREA 0.795200 ;
    PORT
      LAYER met3 ;
        RECT 0.000 1139.720 2.000 1140.320 ;
    END
  END rx_data[468]
  PIN rx_data[469]
    DIRECTION OUTPUT TRISTATE ;
    USE SIGNAL ;
    ANTENNADIFFAREA 0.795200 ;
    PORT
      LAYER met2 ;
        RECT 267.810 1498.000 268.090 1500.000 ;
    END
  END rx_data[469]
  PIN rx_data[46]
    DIRECTION OUTPUT TRISTATE ;
    USE SIGNAL ;
    ANTENNADIFFAREA 0.795200 ;
    PORT
      LAYER met2 ;
        RECT 169.830 1498.000 170.110 1500.000 ;
    END
  END rx_data[46]
  PIN rx_data[470]
    DIRECTION OUTPUT TRISTATE ;
    USE SIGNAL ;
    ANTENNADIFFAREA 0.795200 ;
    PORT
      LAYER met3 ;
        RECT 1498.000 148.280 1500.000 148.880 ;
    END
  END rx_data[470]
  PIN rx_data[471]
    DIRECTION OUTPUT TRISTATE ;
    USE SIGNAL ;
    ANTENNADIFFAREA 0.795200 ;
    PORT
      LAYER met3 ;
        RECT 1498.000 92.520 1500.000 93.120 ;
    END
  END rx_data[471]
  PIN rx_data[472]
    DIRECTION OUTPUT TRISTATE ;
    USE SIGNAL ;
    ANTENNADIFFAREA 0.795200 ;
    PORT
      LAYER met2 ;
        RECT 1305.570 0.000 1305.850 2.000 ;
    END
  END rx_data[472]
  PIN rx_data[473]
    DIRECTION OUTPUT TRISTATE ;
    USE SIGNAL ;
    ANTENNADIFFAREA 0.795200 ;
    PORT
      LAYER met3 ;
        RECT 1498.000 573.960 1500.000 574.560 ;
    END
  END rx_data[473]
  PIN rx_data[474]
    DIRECTION OUTPUT TRISTATE ;
    USE SIGNAL ;
    ANTENNADIFFAREA 0.795200 ;
    PORT
      LAYER met3 ;
        RECT 0.000 35.400 2.000 36.000 ;
    END
  END rx_data[474]
  PIN rx_data[475]
    DIRECTION OUTPUT TRISTATE ;
    USE SIGNAL ;
    ANTENNADIFFAREA 0.795200 ;
    PORT
      LAYER met2 ;
        RECT 1224.150 0.000 1224.430 2.000 ;
    END
  END rx_data[475]
  PIN rx_data[476]
    DIRECTION OUTPUT TRISTATE ;
    USE SIGNAL ;
    ANTENNADIFFAREA 0.795200 ;
    PORT
      LAYER met3 ;
        RECT 0.000 262.520 2.000 263.120 ;
    END
  END rx_data[476]
  PIN rx_data[477]
    DIRECTION OUTPUT TRISTATE ;
    USE SIGNAL ;
    ANTENNADIFFAREA 0.795200 ;
    PORT
      LAYER met3 ;
        RECT 1498.000 975.160 1500.000 975.760 ;
    END
  END rx_data[477]
  PIN rx_data[478]
    DIRECTION OUTPUT TRISTATE ;
    USE SIGNAL ;
    ANTENNADIFFAREA 0.795200 ;
    PORT
      LAYER met3 ;
        RECT 1498.000 1107.080 1500.000 1107.680 ;
    END
  END rx_data[478]
  PIN rx_data[479]
    DIRECTION OUTPUT TRISTATE ;
    USE SIGNAL ;
    ANTENNADIFFAREA 0.795200 ;
    PORT
      LAYER met2 ;
        RECT 1080.630 1498.000 1080.910 1500.000 ;
    END
  END rx_data[479]
  PIN rx_data[47]
    DIRECTION OUTPUT TRISTATE ;
    USE SIGNAL ;
    ANTENNADIFFAREA 0.795200 ;
    PORT
      LAYER met2 ;
        RECT 87.030 1498.000 87.310 1500.000 ;
    END
  END rx_data[47]
  PIN rx_data[480]
    DIRECTION OUTPUT TRISTATE ;
    USE SIGNAL ;
    ANTENNADIFFAREA 0.795200 ;
    PORT
      LAYER met2 ;
        RECT 565.890 1498.000 566.170 1500.000 ;
    END
  END rx_data[480]
  PIN rx_data[481]
    DIRECTION OUTPUT TRISTATE ;
    USE SIGNAL ;
    ANTENNADIFFAREA 0.795200 ;
    PORT
      LAYER met2 ;
        RECT 801.870 1498.000 802.150 1500.000 ;
    END
  END rx_data[481]
  PIN rx_data[482]
    DIRECTION OUTPUT TRISTATE ;
    USE SIGNAL ;
    ANTENNADIFFAREA 0.795200 ;
    PORT
      LAYER met3 ;
        RECT 0.000 1353.240 2.000 1353.840 ;
    END
  END rx_data[482]
  PIN rx_data[483]
    DIRECTION OUTPUT TRISTATE ;
    USE SIGNAL ;
    ANTENNADIFFAREA 0.795200 ;
    PORT
      LAYER met3 ;
        RECT 0.000 1292.040 2.000 1292.640 ;
    END
  END rx_data[483]
  PIN rx_data[484]
    DIRECTION OUTPUT TRISTATE ;
    USE SIGNAL ;
    ANTENNADIFFAREA 0.795200 ;
    PORT
      LAYER met3 ;
        RECT 1498.000 31.320 1500.000 31.920 ;
    END
  END rx_data[484]
  PIN rx_data[485]
    DIRECTION OUTPUT TRISTATE ;
    USE SIGNAL ;
    ANTENNADIFFAREA 0.795200 ;
    PORT
      LAYER met3 ;
        RECT 1498.000 1086.680 1500.000 1087.280 ;
    END
  END rx_data[485]
  PIN rx_data[486]
    DIRECTION OUTPUT TRISTATE ;
    USE SIGNAL ;
    ANTENNADIFFAREA 0.795200 ;
    PORT
      LAYER met3 ;
        RECT 0.000 15.000 2.000 15.600 ;
    END
  END rx_data[486]
  PIN rx_data[487]
    DIRECTION OUTPUT TRISTATE ;
    USE SIGNAL ;
    ANTENNADIFFAREA 0.795200 ;
    PORT
      LAYER met2 ;
        RECT 303.690 1498.000 303.970 1500.000 ;
    END
  END rx_data[487]
  PIN rx_data[488]
    DIRECTION OUTPUT TRISTATE ;
    USE SIGNAL ;
    ANTENNADIFFAREA 0.795200 ;
    PORT
      LAYER met2 ;
        RECT 1497.390 1498.000 1497.670 1500.000 ;
    END
  END rx_data[488]
  PIN rx_data[489]
    DIRECTION OUTPUT TRISTATE ;
    USE SIGNAL ;
    ANTENNADIFFAREA 0.795200 ;
    PORT
      LAYER met3 ;
        RECT 0.000 293.800 2.000 294.400 ;
    END
  END rx_data[489]
  PIN rx_data[48]
    DIRECTION OUTPUT TRISTATE ;
    USE SIGNAL ;
    ANTENNADIFFAREA 0.795200 ;
    PORT
      LAYER met2 ;
        RECT 436.170 0.000 436.450 2.000 ;
    END
  END rx_data[48]
  PIN rx_data[490]
    DIRECTION OUTPUT TRISTATE ;
    USE SIGNAL ;
    ANTENNADIFFAREA 0.795200 ;
    PORT
      LAYER met2 ;
        RECT 873.630 0.000 873.910 2.000 ;
    END
  END rx_data[490]
  PIN rx_data[491]
    DIRECTION OUTPUT TRISTATE ;
    USE SIGNAL ;
    ANTENNADIFFAREA 0.795200 ;
    PORT
      LAYER met3 ;
        RECT 1498.000 1283.880 1500.000 1284.480 ;
    END
  END rx_data[491]
  PIN rx_data[492]
    DIRECTION OUTPUT TRISTATE ;
    USE SIGNAL ;
    ANTENNADIFFAREA 0.795200 ;
    PORT
      LAYER met3 ;
        RECT 1498.000 1406.280 1500.000 1406.880 ;
    END
  END rx_data[492]
  PIN rx_data[493]
    DIRECTION OUTPUT TRISTATE ;
    USE SIGNAL ;
    ANTENNADIFFAREA 0.795200 ;
    PORT
      LAYER met2 ;
        RECT 30.450 1498.000 30.730 1500.000 ;
    END
  END rx_data[493]
  PIN rx_data[494]
    DIRECTION OUTPUT TRISTATE ;
    USE SIGNAL ;
    ANTENNADIFFAREA 0.795200 ;
    PORT
      LAYER met3 ;
        RECT 1498.000 437.960 1500.000 438.560 ;
    END
  END rx_data[494]
  PIN rx_data[495]
    DIRECTION OUTPUT TRISTATE ;
    USE SIGNAL ;
    ANTENNADIFFAREA 0.795200 ;
    PORT
      LAYER met2 ;
        RECT 245.730 0.000 246.010 2.000 ;
    END
  END rx_data[495]
  PIN rx_data[496]
    DIRECTION OUTPUT TRISTATE ;
    USE SIGNAL ;
    ANTENNADIFFAREA 0.795200 ;
    PORT
      LAYER met3 ;
        RECT 0.000 182.280 2.000 182.880 ;
    END
  END rx_data[496]
  PIN rx_data[497]
    DIRECTION OUTPUT TRISTATE ;
    USE SIGNAL ;
    ANTENNADIFFAREA 0.795200 ;
    PORT
      LAYER met2 ;
        RECT 1213.110 0.000 1213.390 2.000 ;
    END
  END rx_data[497]
  PIN rx_data[498]
    DIRECTION OUTPUT TRISTATE ;
    USE SIGNAL ;
    ANTENNADIFFAREA 0.795200 ;
    PORT
      LAYER met3 ;
        RECT 0.000 461.080 2.000 461.680 ;
    END
  END rx_data[498]
  PIN rx_data[499]
    DIRECTION OUTPUT TRISTATE ;
    USE SIGNAL ;
    ANTENNADIFFAREA 0.795200 ;
    PORT
      LAYER met3 ;
        RECT 0.000 202.680 2.000 203.280 ;
    END
  END rx_data[499]
  PIN rx_data[49]
    DIRECTION OUTPUT TRISTATE ;
    USE SIGNAL ;
    ANTENNADIFFAREA 0.795200 ;
    PORT
      LAYER met3 ;
        RECT 0.000 637.880 2.000 638.480 ;
    END
  END rx_data[49]
  PIN rx_data[4]
    DIRECTION OUTPUT TRISTATE ;
    USE SIGNAL ;
    ANTENNADIFFAREA 0.795200 ;
    PORT
      LAYER met3 ;
        RECT 0.000 1175.080 2.000 1175.680 ;
    END
  END rx_data[4]
  PIN rx_data[500]
    DIRECTION OUTPUT TRISTATE ;
    USE SIGNAL ;
    ANTENNADIFFAREA 0.795200 ;
    PORT
      LAYER met2 ;
        RECT 200.190 1498.000 200.470 1500.000 ;
    END
  END rx_data[500]
  PIN rx_data[501]
    DIRECTION OUTPUT TRISTATE ;
    USE SIGNAL ;
    ANTENNADIFFAREA 0.795200 ;
    PORT
      LAYER met2 ;
        RECT 102.210 0.000 102.490 2.000 ;
    END
  END rx_data[501]
  PIN rx_data[502]
    DIRECTION OUTPUT TRISTATE ;
    USE SIGNAL ;
    ANTENNADIFFAREA 0.795200 ;
    PORT
      LAYER met3 ;
        RECT 0.000 593.000 2.000 593.600 ;
    END
  END rx_data[502]
  PIN rx_data[503]
    DIRECTION OUTPUT TRISTATE ;
    USE SIGNAL ;
    ANTENNADIFFAREA 0.795200 ;
    PORT
      LAYER met3 ;
        RECT 0.000 106.120 2.000 106.720 ;
    END
  END rx_data[503]
  PIN rx_data[504]
    DIRECTION OUTPUT TRISTATE ;
    USE SIGNAL ;
    ANTENNADIFFAREA 0.795200 ;
    PORT
      LAYER met2 ;
        RECT 1141.350 1498.000 1141.630 1500.000 ;
    END
  END rx_data[504]
  PIN rx_data[505]
    DIRECTION OUTPUT TRISTATE ;
    USE SIGNAL ;
    ANTENNADIFFAREA 0.795200 ;
    PORT
      LAYER met2 ;
        RECT 302.310 0.000 302.590 2.000 ;
    END
  END rx_data[505]
  PIN rx_data[506]
    DIRECTION OUTPUT TRISTATE ;
    USE SIGNAL ;
    ANTENNADIFFAREA 0.795200 ;
    PORT
      LAYER met2 ;
        RECT 894.330 0.000 894.610 2.000 ;
    END
  END rx_data[506]
  PIN rx_data[507]
    DIRECTION OUTPUT TRISTATE ;
    USE SIGNAL ;
    ANTENNADIFFAREA 0.795200 ;
    PORT
      LAYER met2 ;
        RECT 592.110 1498.000 592.390 1500.000 ;
    END
  END rx_data[507]
  PIN rx_data[508]
    DIRECTION OUTPUT TRISTATE ;
    USE SIGNAL ;
    ANTENNADIFFAREA 0.795200 ;
    PORT
      LAYER met2 ;
        RECT 313.350 0.000 313.630 2.000 ;
    END
  END rx_data[508]
  PIN rx_data[509]
    DIRECTION OUTPUT TRISTATE ;
    USE SIGNAL ;
    ANTENNADIFFAREA 0.795200 ;
    PORT
      LAYER met2 ;
        RECT 62.190 1498.000 62.470 1500.000 ;
    END
  END rx_data[509]
  PIN rx_data[50]
    DIRECTION OUTPUT TRISTATE ;
    USE SIGNAL ;
    ANTENNADIFFAREA 0.795200 ;
    PORT
      LAYER met2 ;
        RECT 415.470 0.000 415.750 2.000 ;
    END
  END rx_data[50]
  PIN rx_data[510]
    DIRECTION OUTPUT TRISTATE ;
    USE SIGNAL ;
    ANTENNADIFFAREA 0.795200 ;
    PORT
      LAYER met2 ;
        RECT 236.070 1498.000 236.350 1500.000 ;
    END
  END rx_data[510]
  PIN rx_data[511]
    DIRECTION OUTPUT TRISTATE ;
    USE SIGNAL ;
    ANTENNADIFFAREA 0.795200 ;
    PORT
      LAYER met2 ;
        RECT 1013.010 1498.000 1013.290 1500.000 ;
    END
  END rx_data[511]
  PIN rx_data[51]
    DIRECTION OUTPUT TRISTATE ;
    USE SIGNAL ;
    ANTENNADIFFAREA 0.795200 ;
    PORT
      LAYER met3 ;
        RECT 1498.000 1233.560 1500.000 1234.160 ;
    END
  END rx_data[51]
  PIN rx_data[52]
    DIRECTION OUTPUT TRISTATE ;
    USE SIGNAL ;
    ANTENNADIFFAREA 0.795200 ;
    PORT
      LAYER met3 ;
        RECT 0.000 998.280 2.000 998.880 ;
    END
  END rx_data[52]
  PIN rx_data[53]
    DIRECTION OUTPUT TRISTATE ;
    USE SIGNAL ;
    ANTENNADIFFAREA 0.795200 ;
    PORT
      LAYER met2 ;
        RECT 1115.130 0.000 1115.410 2.000 ;
    END
  END rx_data[53]
  PIN rx_data[54]
    DIRECTION OUTPUT TRISTATE ;
    USE SIGNAL ;
    ANTENNADIFFAREA 0.795200 ;
    PORT
      LAYER met2 ;
        RECT 1131.690 1498.000 1131.970 1500.000 ;
    END
  END rx_data[54]
  PIN rx_data[55]
    DIRECTION OUTPUT TRISTATE ;
    USE SIGNAL ;
    ANTENNADIFFAREA 0.795200 ;
    PORT
      LAYER met3 ;
        RECT 1498.000 133.320 1500.000 133.920 ;
    END
  END rx_data[55]
  PIN rx_data[56]
    DIRECTION OUTPUT TRISTATE ;
    USE SIGNAL ;
    ANTENNADIFFAREA 0.795200 ;
    PORT
      LAYER met3 ;
        RECT 0.000 1418.520 2.000 1419.120 ;
    END
  END rx_data[56]
  PIN rx_data[57]
    DIRECTION OUTPUT TRISTATE ;
    USE SIGNAL ;
    ANTENNADIFFAREA 0.795200 ;
    PORT
      LAYER met2 ;
        RECT 1486.350 0.000 1486.630 2.000 ;
    END
  END rx_data[57]
  PIN rx_data[58]
    DIRECTION OUTPUT TRISTATE ;
    USE SIGNAL ;
    ANTENNADIFFAREA 0.795200 ;
    PORT
      LAYER met3 ;
        RECT 1498.000 265.240 1500.000 265.840 ;
    END
  END rx_data[58]
  PIN rx_data[59]
    DIRECTION OUTPUT TRISTATE ;
    USE SIGNAL ;
    ANTENNADIFFAREA 0.795200 ;
    PORT
      LAYER met3 ;
        RECT 0.000 80.280 2.000 80.880 ;
    END
  END rx_data[59]
  PIN rx_data[5]
    DIRECTION OUTPUT TRISTATE ;
    USE SIGNAL ;
    ANTENNADIFFAREA 0.795200 ;
    PORT
      LAYER met2 ;
        RECT 616.950 1498.000 617.230 1500.000 ;
    END
  END rx_data[5]
  PIN rx_data[60]
    DIRECTION OUTPUT TRISTATE ;
    USE SIGNAL ;
    ANTENNADIFFAREA 0.795200 ;
    PORT
      LAYER met3 ;
        RECT 0.000 1388.600 2.000 1389.200 ;
    END
  END rx_data[60]
  PIN rx_data[61]
    DIRECTION OUTPUT TRISTATE ;
    USE SIGNAL ;
    ANTENNADIFFAREA 0.795200 ;
    PORT
      LAYER met3 ;
        RECT 0.000 390.360 2.000 390.960 ;
    END
  END rx_data[61]
  PIN rx_data[62]
    DIRECTION OUTPUT TRISTATE ;
    USE SIGNAL ;
    ANTENNADIFFAREA 0.795200 ;
    PORT
      LAYER met3 ;
        RECT 0.000 1414.440 2.000 1415.040 ;
    END
  END rx_data[62]
  PIN rx_data[63]
    DIRECTION OUTPUT TRISTATE ;
    USE SIGNAL ;
    ANTENNADIFFAREA 0.795200 ;
    PORT
      LAYER met3 ;
        RECT 1498.000 1030.920 1500.000 1031.520 ;
    END
  END rx_data[63]
  PIN rx_data[64]
    DIRECTION OUTPUT TRISTATE ;
    USE SIGNAL ;
    ANTENNADIFFAREA 0.795200 ;
    PORT
      LAYER met2 ;
        RECT 143.610 1498.000 143.890 1500.000 ;
    END
  END rx_data[64]
  PIN rx_data[65]
    DIRECTION OUTPUT TRISTATE ;
    USE SIGNAL ;
    ANTENNADIFFAREA 0.795200 ;
    PORT
      LAYER met2 ;
        RECT 498.270 0.000 498.550 2.000 ;
    END
  END rx_data[65]
  PIN rx_data[66]
    DIRECTION OUTPUT TRISTATE ;
    USE SIGNAL ;
    ANTENNADIFFAREA 0.795200 ;
    PORT
      LAYER met3 ;
        RECT 1498.000 447.480 1500.000 448.080 ;
    END
  END rx_data[66]
  PIN rx_data[67]
    DIRECTION OUTPUT TRISTATE ;
    USE SIGNAL ;
    ANTENNADIFFAREA 0.795200 ;
    PORT
      LAYER met2 ;
        RECT 175.350 1498.000 175.630 1500.000 ;
    END
  END rx_data[67]
  PIN rx_data[68]
    DIRECTION OUTPUT TRISTATE ;
    USE SIGNAL ;
    ANTENNADIFFAREA 0.795200 ;
    PORT
      LAYER met3 ;
        RECT 1498.000 6.840 1500.000 7.440 ;
    END
  END rx_data[68]
  PIN rx_data[69]
    DIRECTION OUTPUT TRISTATE ;
    USE SIGNAL ;
    ANTENNADIFFAREA 0.795200 ;
    PORT
      LAYER met2 ;
        RECT 256.770 1498.000 257.050 1500.000 ;
    END
  END rx_data[69]
  PIN rx_data[6]
    DIRECTION OUTPUT TRISTATE ;
    USE SIGNAL ;
    ANTENNADIFFAREA 0.795200 ;
    PORT
      LAYER met3 ;
        RECT 0.000 922.120 2.000 922.720 ;
    END
  END rx_data[6]
  PIN rx_data[70]
    DIRECTION OUTPUT TRISTATE ;
    USE SIGNAL ;
    ANTENNADIFFAREA 0.795200 ;
    PORT
      LAYER met2 ;
        RECT 1218.630 0.000 1218.910 2.000 ;
    END
  END rx_data[70]
  PIN rx_data[71]
    DIRECTION OUTPUT TRISTATE ;
    USE SIGNAL ;
    ANTENNADIFFAREA 0.795200 ;
    PORT
      LAYER met2 ;
        RECT 432.030 0.000 432.310 2.000 ;
    END
  END rx_data[71]
  PIN rx_data[72]
    DIRECTION OUTPUT TRISTATE ;
    USE SIGNAL ;
    ANTENNADIFFAREA 0.795200 ;
    PORT
      LAYER met3 ;
        RECT 0.000 1230.840 2.000 1231.440 ;
    END
  END rx_data[72]
  PIN rx_data[73]
    DIRECTION OUTPUT TRISTATE ;
    USE SIGNAL ;
    ANTENNADIFFAREA 0.795200 ;
    PORT
      LAYER met2 ;
        RECT 1429.770 1498.000 1430.050 1500.000 ;
    END
  END rx_data[73]
  PIN rx_data[74]
    DIRECTION OUTPUT TRISTATE ;
    USE SIGNAL ;
    ANTENNADIFFAREA 0.795200 ;
    PORT
      LAYER met2 ;
        RECT 1358.010 1498.000 1358.290 1500.000 ;
    END
  END rx_data[74]
  PIN rx_data[75]
    DIRECTION OUTPUT TRISTATE ;
    USE SIGNAL ;
    ANTENNADIFFAREA 0.795200 ;
    PORT
      LAYER met3 ;
        RECT 1498.000 1345.080 1500.000 1345.680 ;
    END
  END rx_data[75]
  PIN rx_data[76]
    DIRECTION OUTPUT TRISTATE ;
    USE SIGNAL ;
    ANTENNADIFFAREA 0.795200 ;
    PORT
      LAYER met3 ;
        RECT 0.000 643.320 2.000 643.920 ;
    END
  END rx_data[76]
  PIN rx_data[77]
    DIRECTION OUTPUT TRISTATE ;
    USE SIGNAL ;
    ANTENNADIFFAREA 0.795200 ;
    PORT
      LAYER met3 ;
        RECT 1498.000 442.040 1500.000 442.640 ;
    END
  END rx_data[77]
  PIN rx_data[78]
    DIRECTION OUTPUT TRISTATE ;
    USE SIGNAL ;
    ANTENNADIFFAREA 0.795200 ;
    PORT
      LAYER met2 ;
        RECT 1173.090 1498.000 1173.370 1500.000 ;
    END
  END rx_data[78]
  PIN rx_data[79]
    DIRECTION OUTPUT TRISTATE ;
    USE SIGNAL ;
    ANTENNADIFFAREA 0.795200 ;
    PORT
      LAYER met3 ;
        RECT 1498.000 837.800 1500.000 838.400 ;
    END
  END rx_data[79]
  PIN rx_data[7]
    DIRECTION OUTPUT TRISTATE ;
    USE SIGNAL ;
    ANTENNADIFFAREA 0.795200 ;
    PORT
      LAYER met2 ;
        RECT 226.410 0.000 226.690 2.000 ;
    END
  END rx_data[7]
  PIN rx_data[80]
    DIRECTION OUTPUT TRISTATE ;
    USE SIGNAL ;
    ANTENNADIFFAREA 0.795200 ;
    PORT
      LAYER met3 ;
        RECT 1498.000 1198.200 1500.000 1198.800 ;
    END
  END rx_data[80]
  PIN rx_data[81]
    DIRECTION OUTPUT TRISTATE ;
    USE SIGNAL ;
    ANTENNADIFFAREA 0.795200 ;
    PORT
      LAYER met2 ;
        RECT 518.970 0.000 519.250 2.000 ;
    END
  END rx_data[81]
  PIN rx_data[82]
    DIRECTION OUTPUT TRISTATE ;
    USE SIGNAL ;
    ANTENNADIFFAREA 0.795200 ;
    PORT
      LAYER met2 ;
        RECT 354.750 1498.000 355.030 1500.000 ;
    END
  END rx_data[82]
  PIN rx_data[83]
    DIRECTION OUTPUT TRISTATE ;
    USE SIGNAL ;
    ANTENNADIFFAREA 0.795200 ;
    PORT
      LAYER met2 ;
        RECT 812.910 1498.000 813.190 1500.000 ;
    END
  END rx_data[83]
  PIN rx_data[84]
    DIRECTION OUTPUT TRISTATE ;
    USE SIGNAL ;
    ANTENNADIFFAREA 0.795200 ;
    PORT
      LAYER met3 ;
        RECT 0.000 1028.200 2.000 1028.800 ;
    END
  END rx_data[84]
  PIN rx_data[85]
    DIRECTION OUTPUT TRISTATE ;
    USE SIGNAL ;
    ANTENNADIFFAREA 0.795200 ;
    PORT
      LAYER met3 ;
        RECT 1498.000 609.320 1500.000 609.920 ;
    END
  END rx_data[85]
  PIN rx_data[86]
    DIRECTION OUTPUT TRISTATE ;
    USE SIGNAL ;
    ANTENNADIFFAREA 0.795200 ;
    PORT
      LAYER met3 ;
        RECT 0.000 136.040 2.000 136.640 ;
    END
  END rx_data[86]
  PIN rx_data[87]
    DIRECTION OUTPUT TRISTATE ;
    USE SIGNAL ;
    ANTENNADIFFAREA 0.795200 ;
    PORT
      LAYER met2 ;
        RECT 705.270 1498.000 705.550 1500.000 ;
    END
  END rx_data[87]
  PIN rx_data[88]
    DIRECTION OUTPUT TRISTATE ;
    USE SIGNAL ;
    ANTENNADIFFAREA 0.795200 ;
    PORT
      LAYER met2 ;
        RECT 771.510 0.000 771.790 2.000 ;
    END
  END rx_data[88]
  PIN rx_data[89]
    DIRECTION OUTPUT TRISTATE ;
    USE SIGNAL ;
    ANTENNADIFFAREA 0.795200 ;
    PORT
      LAYER met2 ;
        RECT 1141.350 0.000 1141.630 2.000 ;
    END
  END rx_data[89]
  PIN rx_data[8]
    DIRECTION OUTPUT TRISTATE ;
    USE SIGNAL ;
    ANTENNADIFFAREA 0.795200 ;
    PORT
      LAYER met2 ;
        RECT 586.590 1498.000 586.870 1500.000 ;
    END
  END rx_data[8]
  PIN rx_data[90]
    DIRECTION OUTPUT TRISTATE ;
    USE SIGNAL ;
    ANTENNADIFFAREA 0.795200 ;
    PORT
      LAYER met3 ;
        RECT 0.000 520.920 2.000 521.520 ;
    END
  END rx_data[90]
  PIN rx_data[91]
    DIRECTION OUTPUT TRISTATE ;
    USE SIGNAL ;
    ANTENNADIFFAREA 0.795200 ;
    PORT
      LAYER met3 ;
        RECT 0.000 754.840 2.000 755.440 ;
    END
  END rx_data[91]
  PIN rx_data[92]
    DIRECTION OUTPUT TRISTATE ;
    USE SIGNAL ;
    ANTENNADIFFAREA 0.795200 ;
    PORT
      LAYER met2 ;
        RECT 915.030 1498.000 915.310 1500.000 ;
    END
  END rx_data[92]
  PIN rx_data[93]
    DIRECTION OUTPUT TRISTATE ;
    USE SIGNAL ;
    ANTENNADIFFAREA 0.795200 ;
    PORT
      LAYER met2 ;
        RECT 1491.870 0.000 1492.150 2.000 ;
    END
  END rx_data[93]
  PIN rx_data[94]
    DIRECTION OUTPUT TRISTATE ;
    USE SIGNAL ;
    ANTENNADIFFAREA 0.795200 ;
    PORT
      LAYER met2 ;
        RECT 1214.490 1498.000 1214.770 1500.000 ;
    END
  END rx_data[94]
  PIN rx_data[95]
    DIRECTION OUTPUT TRISTATE ;
    USE SIGNAL ;
    ANTENNADIFFAREA 0.795200 ;
    PORT
      LAYER met2 ;
        RECT 328.530 1498.000 328.810 1500.000 ;
    END
  END rx_data[95]
  PIN rx_data[96]
    DIRECTION OUTPUT TRISTATE ;
    USE SIGNAL ;
    ANTENNADIFFAREA 0.795200 ;
    PORT
      LAYER met3 ;
        RECT 0.000 784.760 2.000 785.360 ;
    END
  END rx_data[96]
  PIN rx_data[97]
    DIRECTION OUTPUT TRISTATE ;
    USE SIGNAL ;
    ANTENNADIFFAREA 0.795200 ;
    PORT
      LAYER met3 ;
        RECT 1498.000 605.240 1500.000 605.840 ;
    END
  END rx_data[97]
  PIN rx_data[98]
    DIRECTION OUTPUT TRISTATE ;
    USE SIGNAL ;
    ANTENNADIFFAREA 0.795200 ;
    PORT
      LAYER met2 ;
        RECT 400.290 0.000 400.570 2.000 ;
    END
  END rx_data[98]
  PIN rx_data[99]
    DIRECTION OUTPUT TRISTATE ;
    USE SIGNAL ;
    ANTENNADIFFAREA 0.795200 ;
    PORT
      LAYER met3 ;
        RECT 1498.000 356.360 1500.000 356.960 ;
    END
  END rx_data[99]
  PIN rx_data[9]
    DIRECTION OUTPUT TRISTATE ;
    USE SIGNAL ;
    ANTENNADIFFAREA 0.795200 ;
    PORT
      LAYER met3 ;
        RECT 1498.000 538.600 1500.000 539.200 ;
    END
  END rx_data[9]
  PIN rx_dlc[0]
    DIRECTION OUTPUT TRISTATE ;
    USE SIGNAL ;
    ANTENNADIFFAREA 0.795200 ;
    PORT
      LAYER met3 ;
        RECT 0.000 678.680 2.000 679.280 ;
    END
  END rx_dlc[0]
  PIN rx_dlc[1]
    DIRECTION OUTPUT TRISTATE ;
    USE SIGNAL ;
    ANTENNADIFFAREA 0.795200 ;
    PORT
      LAYER met3 ;
        RECT 0.000 1470.200 2.000 1470.800 ;
    END
  END rx_dlc[1]
  PIN rx_dlc[2]
    DIRECTION OUTPUT TRISTATE ;
    USE SIGNAL ;
    ANTENNADIFFAREA 0.795200 ;
    PORT
      LAYER met3 ;
        RECT 1498.000 62.600 1500.000 63.200 ;
    END
  END rx_dlc[2]
  PIN rx_dlc[3]
    DIRECTION OUTPUT TRISTATE ;
    USE SIGNAL ;
    ANTENNADIFFAREA 0.795200 ;
    PORT
      LAYER met2 ;
        RECT 570.030 0.000 570.310 2.000 ;
    END
  END rx_dlc[3]
  PIN rx_err_cnt[0]
    DIRECTION OUTPUT TRISTATE ;
    USE SIGNAL ;
    ANTENNADIFFAREA 0.795200 ;
    PORT
      LAYER met3 ;
        RECT 0.000 1059.480 2.000 1060.080 ;
    END
  END rx_err_cnt[0]
  PIN rx_err_cnt[1]
    DIRECTION OUTPUT TRISTATE ;
    USE SIGNAL ;
    ANTENNADIFFAREA 0.795200 ;
    PORT
      LAYER met3 ;
        RECT 1498.000 979.240 1500.000 979.840 ;
    END
  END rx_err_cnt[1]
  PIN rx_err_cnt[2]
    DIRECTION OUTPUT TRISTATE ;
    USE SIGNAL ;
    ANTENNADIFFAREA 0.795200 ;
    PORT
      LAYER met2 ;
        RECT 251.250 0.000 251.530 2.000 ;
    END
  END rx_err_cnt[2]
  PIN rx_err_cnt[3]
    DIRECTION OUTPUT TRISTATE ;
    USE SIGNAL ;
    ANTENNADIFFAREA 0.795200 ;
    PORT
      LAYER met3 ;
        RECT 0.000 394.440 2.000 395.040 ;
    END
  END rx_err_cnt[3]
  PIN rx_err_cnt[4]
    DIRECTION OUTPUT TRISTATE ;
    USE SIGNAL ;
    ANTENNADIFFAREA 0.795200 ;
    PORT
      LAYER met3 ;
        RECT 1498.000 345.480 1500.000 346.080 ;
    END
  END rx_err_cnt[4]
  PIN rx_err_cnt[5]
    DIRECTION OUTPUT TRISTATE ;
    USE SIGNAL ;
    ANTENNADIFFAREA 0.795200 ;
    PORT
      LAYER met3 ;
        RECT 1498.000 1354.600 1500.000 1355.200 ;
    END
  END rx_err_cnt[5]
  PIN rx_err_cnt[6]
    DIRECTION OUTPUT TRISTATE ;
    USE SIGNAL ;
    ANTENNADIFFAREA 0.795200 ;
    PORT
      LAYER met2 ;
        RECT 641.790 0.000 642.070 2.000 ;
    END
  END rx_err_cnt[6]
  PIN rx_err_cnt[7]
    DIRECTION OUTPUT TRISTATE ;
    USE SIGNAL ;
    ANTENNADIFFAREA 0.795200 ;
    PORT
      LAYER met3 ;
        RECT 0.000 217.640 2.000 218.240 ;
    END
  END rx_err_cnt[7]
  PIN rx_fdf
    DIRECTION OUTPUT TRISTATE ;
    USE SIGNAL ;
    ANTENNADIFFAREA 0.795200 ;
    PORT
      LAYER met2 ;
        RECT 1218.630 1498.000 1218.910 1500.000 ;
    END
  END rx_fdf
  PIN rx_id[0]
    DIRECTION OUTPUT TRISTATE ;
    USE SIGNAL ;
    ANTENNADIFFAREA 0.795200 ;
    PORT
      LAYER met2 ;
        RECT 745.290 1498.000 745.570 1500.000 ;
    END
  END rx_id[0]
  PIN rx_id[10]
    DIRECTION OUTPUT TRISTATE ;
    USE SIGNAL ;
    ANTENNADIFFAREA 0.795200 ;
    PORT
      LAYER met3 ;
        RECT 0.000 1039.080 2.000 1039.680 ;
    END
  END rx_id[10]
  PIN rx_id[11]
    DIRECTION OUTPUT TRISTATE ;
    USE SIGNAL ;
    ANTENNADIFFAREA 0.795200 ;
    PORT
      LAYER met2 ;
        RECT 1193.790 1498.000 1194.070 1500.000 ;
    END
  END rx_id[11]
  PIN rx_id[12]
    DIRECTION OUTPUT TRISTATE ;
    USE SIGNAL ;
    ANTENNADIFFAREA 0.795200 ;
    PORT
      LAYER met2 ;
        RECT 26.310 1498.000 26.590 1500.000 ;
    END
  END rx_id[12]
  PIN rx_id[13]
    DIRECTION OUTPUT TRISTATE ;
    USE SIGNAL ;
    ANTENNADIFFAREA 0.795200 ;
    PORT
      LAYER met3 ;
        RECT 1498.000 118.360 1500.000 118.960 ;
    END
  END rx_id[13]
  PIN rx_id[14]
    DIRECTION OUTPUT TRISTATE ;
    USE SIGNAL ;
    ANTENNADIFFAREA 0.795200 ;
    PORT
      LAYER met3 ;
        RECT 0.000 871.800 2.000 872.400 ;
    END
  END rx_id[14]
  PIN rx_id[15]
    DIRECTION OUTPUT TRISTATE ;
    USE SIGNAL ;
    ANTENNADIFFAREA 0.795200 ;
    PORT
      LAYER met2 ;
        RECT 915.030 0.000 915.310 2.000 ;
    END
  END rx_id[15]
  PIN rx_id[16]
    DIRECTION OUTPUT TRISTATE ;
    USE SIGNAL ;
    ANTENNADIFFAREA 0.795200 ;
    PORT
      LAYER met3 ;
        RECT 0.000 967.000 2.000 967.600 ;
    END
  END rx_id[16]
  PIN rx_id[17]
    DIRECTION OUTPUT TRISTATE ;
    USE SIGNAL ;
    ANTENNADIFFAREA 0.795200 ;
    PORT
      LAYER met3 ;
        RECT 0.000 881.320 2.000 881.920 ;
    END
  END rx_id[17]
  PIN rx_id[18]
    DIRECTION OUTPUT TRISTATE ;
    USE SIGNAL ;
    ANTENNADIFFAREA 0.795200 ;
    PORT
      LAYER met2 ;
        RECT 113.250 0.000 113.530 2.000 ;
    END
  END rx_id[18]
  PIN rx_id[19]
    DIRECTION OUTPUT TRISTATE ;
    USE SIGNAL ;
    ANTENNADIFFAREA 0.795200 ;
    PORT
      LAYER met2 ;
        RECT 401.670 1498.000 401.950 1500.000 ;
    END
  END rx_id[19]
  PIN rx_id[1]
    DIRECTION OUTPUT TRISTATE ;
    USE SIGNAL ;
    ANTENNADIFFAREA 0.795200 ;
    PORT
      LAYER met2 ;
        RECT 92.550 0.000 92.830 2.000 ;
    END
  END rx_id[1]
  PIN rx_id[20]
    DIRECTION OUTPUT TRISTATE ;
    USE SIGNAL ;
    ANTENNADIFFAREA 0.795200 ;
    PORT
      LAYER met2 ;
        RECT 571.410 1498.000 571.690 1500.000 ;
    END
  END rx_id[20]
  PIN rx_id[21]
    DIRECTION OUTPUT TRISTATE ;
    USE SIGNAL ;
    ANTENNADIFFAREA 0.795200 ;
    PORT
      LAYER met3 ;
        RECT 0.000 552.200 2.000 552.800 ;
    END
  END rx_id[21]
  PIN rx_id[22]
    DIRECTION OUTPUT TRISTATE ;
    USE SIGNAL ;
    ANTENNADIFFAREA 0.795200 ;
    PORT
      LAYER met3 ;
        RECT 1498.000 1060.840 1500.000 1061.440 ;
    END
  END rx_id[22]
  PIN rx_id[23]
    DIRECTION OUTPUT TRISTATE ;
    USE SIGNAL ;
    ANTENNADIFFAREA 0.795200 ;
    PORT
      LAYER met3 ;
        RECT 0.000 688.200 2.000 688.800 ;
    END
  END rx_id[23]
  PIN rx_id[24]
    DIRECTION OUTPUT TRISTATE ;
    USE SIGNAL ;
    ANTENNADIFFAREA 0.795200 ;
    PORT
      LAYER met3 ;
        RECT 0.000 491.000 2.000 491.600 ;
    END
  END rx_id[24]
  PIN rx_id[25]
    DIRECTION OUTPUT TRISTATE ;
    USE SIGNAL ;
    ANTENNADIFFAREA 0.795200 ;
    PORT
      LAYER met2 ;
        RECT 956.430 1498.000 956.710 1500.000 ;
    END
  END rx_id[25]
  PIN rx_id[26]
    DIRECTION OUTPUT TRISTATE ;
    USE SIGNAL ;
    ANTENNADIFFAREA 0.795200 ;
    PORT
      LAYER met2 ;
        RECT 477.570 0.000 477.850 2.000 ;
    END
  END rx_id[26]
  PIN rx_id[27]
    DIRECTION OUTPUT TRISTATE ;
    USE SIGNAL ;
    ANTENNADIFFAREA 0.795200 ;
    PORT
      LAYER met3 ;
        RECT 0.000 1297.480 2.000 1298.080 ;
    END
  END rx_id[27]
  PIN rx_id[28]
    DIRECTION OUTPUT TRISTATE ;
    USE SIGNAL ;
    ANTENNADIFFAREA 0.795200 ;
    PORT
      LAYER met2 ;
        RECT 1054.410 1498.000 1054.690 1500.000 ;
    END
  END rx_id[28]
  PIN rx_id[2]
    DIRECTION OUTPUT TRISTATE ;
    USE SIGNAL ;
    ANTENNADIFFAREA 0.795200 ;
    PORT
      LAYER met2 ;
        RECT 107.730 0.000 108.010 2.000 ;
    END
  END rx_id[2]
  PIN rx_id[3]
    DIRECTION OUTPUT TRISTATE ;
    USE SIGNAL ;
    ANTENNADIFFAREA 0.795200 ;
    PORT
      LAYER met3 ;
        RECT 1498.000 584.840 1500.000 585.440 ;
    END
  END rx_id[3]
  PIN rx_id[4]
    DIRECTION OUTPUT TRISTATE ;
    USE SIGNAL ;
    ANTENNADIFFAREA 0.795200 ;
    PORT
      LAYER met2 ;
        RECT 554.850 1498.000 555.130 1500.000 ;
    END
  END rx_id[4]
  PIN rx_id[5]
    DIRECTION OUTPUT TRISTATE ;
    USE SIGNAL ;
    ANTENNADIFFAREA 0.795200 ;
    PORT
      LAYER met3 ;
        RECT 0.000 1449.800 2.000 1450.400 ;
    END
  END rx_id[5]
  PIN rx_id[6]
    DIRECTION OUTPUT TRISTATE ;
    USE SIGNAL ;
    ANTENNADIFFAREA 0.795200 ;
    PORT
      LAYER met2 ;
        RECT 292.650 0.000 292.930 2.000 ;
    END
  END rx_id[6]
  PIN rx_id[7]
    DIRECTION OUTPUT TRISTATE ;
    USE SIGNAL ;
    ANTENNADIFFAREA 0.795200 ;
    PORT
      LAYER met3 ;
        RECT 1498.000 310.120 1500.000 310.720 ;
    END
  END rx_id[7]
  PIN rx_id[8]
    DIRECTION OUTPUT TRISTATE ;
    USE SIGNAL ;
    ANTENNADIFFAREA 0.795200 ;
    PORT
      LAYER met3 ;
        RECT 0.000 886.760 2.000 887.360 ;
    END
  END rx_id[8]
  PIN rx_id[9]
    DIRECTION OUTPUT TRISTATE ;
    USE SIGNAL ;
    ANTENNADIFFAREA 0.795200 ;
    PORT
      LAYER met3 ;
        RECT 0.000 699.080 2.000 699.680 ;
    END
  END rx_id[9]
  PIN rx_ide
    DIRECTION OUTPUT TRISTATE ;
    USE SIGNAL ;
    ANTENNADIFFAREA 0.795200 ;
    PORT
      LAYER met3 ;
        RECT 0.000 24.520 2.000 25.120 ;
    END
  END rx_ide
  PIN rx_rtr
    DIRECTION OUTPUT TRISTATE ;
    USE SIGNAL ;
    PORT
      LAYER met3 ;
        RECT 1498.000 1278.440 1500.000 1279.040 ;
    END
  END rx_rtr
  PIN rx_valid
    DIRECTION OUTPUT TRISTATE ;
    USE SIGNAL ;
    ANTENNADIFFAREA 0.795200 ;
    PORT
      LAYER met2 ;
        RECT 1280.730 1498.000 1281.010 1500.000 ;
    END
  END rx_valid
  PIN tx_brs
    DIRECTION INPUT ;
    USE SIGNAL ;
    ANTENNAGATEAREA 0.247500 ;
    PORT
      LAYER met2 ;
        RECT 158.790 0.000 159.070 2.000 ;
    END
  END tx_brs
  PIN tx_busy
    DIRECTION OUTPUT TRISTATE ;
    USE SIGNAL ;
    ANTENNADIFFAREA 0.795200 ;
    PORT
      LAYER met3 ;
        RECT 0.000 186.360 2.000 186.960 ;
    END
  END tx_busy
  PIN tx_data[0]
    DIRECTION INPUT ;
    USE SIGNAL ;
    ANTENNAGATEAREA 0.213000 ;
    PORT
      LAYER met3 ;
        RECT 0.000 425.720 2.000 426.320 ;
    END
  END tx_data[0]
  PIN tx_data[100]
    DIRECTION INPUT ;
    USE SIGNAL ;
    ANTENNAGATEAREA 0.247500 ;
    PORT
      LAYER met3 ;
        RECT 1498.000 720.840 1500.000 721.440 ;
    END
  END tx_data[100]
  PIN tx_data[101]
    DIRECTION INPUT ;
    USE SIGNAL ;
    ANTENNAGATEAREA 0.990000 ;
    PORT
      LAYER met2 ;
        RECT 220.890 0.000 221.170 2.000 ;
    END
  END tx_data[101]
  PIN tx_data[102]
    DIRECTION INPUT ;
    USE SIGNAL ;
    ANTENNAGATEAREA 0.213000 ;
    PORT
      LAYER met3 ;
        RECT 1498.000 564.440 1500.000 565.040 ;
    END
  END tx_data[102]
  PIN tx_data[103]
    DIRECTION INPUT ;
    USE SIGNAL ;
    ANTENNAGATEAREA 0.495000 ;
    PORT
      LAYER met2 ;
        RECT 616.950 0.000 617.230 2.000 ;
    END
  END tx_data[103]
  PIN tx_data[104]
    DIRECTION INPUT ;
    USE SIGNAL ;
    ANTENNAGATEAREA 0.990000 ;
    PORT
      LAYER met3 ;
        RECT 0.000 790.200 2.000 790.800 ;
    END
  END tx_data[104]
  PIN tx_data[105]
    DIRECTION INPUT ;
    USE SIGNAL ;
    ANTENNAGATEAREA 0.990000 ;
    PORT
      LAYER met3 ;
        RECT 0.000 1195.480 2.000 1196.080 ;
    END
  END tx_data[105]
  PIN tx_data[106]
    DIRECTION INPUT ;
    USE SIGNAL ;
    ANTENNAGATEAREA 0.990000 ;
    PORT
      LAYER met3 ;
        RECT 0.000 531.800 2.000 532.400 ;
    END
  END tx_data[106]
  PIN tx_data[107]
    DIRECTION INPUT ;
    USE SIGNAL ;
    ANTENNAGATEAREA 0.990000 ;
    PORT
      LAYER met2 ;
        RECT 622.470 1498.000 622.750 1500.000 ;
    END
  END tx_data[107]
  PIN tx_data[108]
    DIRECTION INPUT ;
    USE SIGNAL ;
    ANTENNAGATEAREA 0.213000 ;
    PORT
      LAYER met3 ;
        RECT 1498.000 142.840 1500.000 143.440 ;
    END
  END tx_data[108]
  PIN tx_data[109]
    DIRECTION INPUT ;
    USE SIGNAL ;
    ANTENNAGATEAREA 0.990000 ;
    PORT
      LAYER met3 ;
        RECT 0.000 297.880 2.000 298.480 ;
    END
  END tx_data[109]
  PIN tx_data[10]
    DIRECTION INPUT ;
    USE SIGNAL ;
    ANTENNAGATEAREA 0.990000 ;
    PORT
      LAYER met3 ;
        RECT 1498.000 1430.760 1500.000 1431.360 ;
    END
  END tx_data[10]
  PIN tx_data[110]
    DIRECTION INPUT ;
    USE SIGNAL ;
    ANTENNAGATEAREA 0.247500 ;
    PORT
      LAYER met3 ;
        RECT 1498.000 473.320 1500.000 473.920 ;
    END
  END tx_data[110]
  PIN tx_data[111]
    DIRECTION INPUT ;
    USE SIGNAL ;
    ANTENNAGATEAREA 0.852000 ;
    PORT
      LAYER met3 ;
        RECT 1498.000 1294.760 1500.000 1295.360 ;
    END
  END tx_data[111]
  PIN tx_data[112]
    DIRECTION INPUT ;
    USE SIGNAL ;
    ANTENNAGATEAREA 0.247500 ;
    PORT
      LAYER met2 ;
        RECT 828.090 0.000 828.370 2.000 ;
    END
  END tx_data[112]
  PIN tx_data[113]
    DIRECTION INPUT ;
    USE SIGNAL ;
    ANTENNAGATEAREA 0.990000 ;
    PORT
      LAYER met2 ;
        RECT 82.890 1498.000 83.170 1500.000 ;
    END
  END tx_data[113]
  PIN tx_data[114]
    DIRECTION INPUT ;
    USE SIGNAL ;
    ANTENNAGATEAREA 0.990000 ;
    PORT
      LAYER met2 ;
        RECT 478.950 1498.000 479.230 1500.000 ;
    END
  END tx_data[114]
  PIN tx_data[115]
    DIRECTION INPUT ;
    USE SIGNAL ;
    ANTENNAGATEAREA 0.990000 ;
    PORT
      LAYER met3 ;
        RECT 0.000 465.160 2.000 465.760 ;
    END
  END tx_data[115]
  PIN tx_data[116]
    DIRECTION INPUT ;
    USE SIGNAL ;
    ANTENNAGATEAREA 0.990000 ;
    PORT
      LAYER met3 ;
        RECT 0.000 435.240 2.000 435.840 ;
    END
  END tx_data[116]
  PIN tx_data[117]
    DIRECTION INPUT ;
    USE SIGNAL ;
    ANTENNAGATEAREA 0.990000 ;
    PORT
      LAYER met3 ;
        RECT 0.000 1206.360 2.000 1206.960 ;
    END
  END tx_data[117]
  PIN tx_data[118]
    DIRECTION INPUT ;
    USE SIGNAL ;
    ANTENNAGATEAREA 0.247500 ;
    PORT
      LAYER met3 ;
        RECT 1498.000 306.040 1500.000 306.640 ;
    END
  END tx_data[118]
  PIN tx_data[119]
    DIRECTION INPUT ;
    USE SIGNAL ;
    ANTENNAGATEAREA 0.159000 ;
    PORT
      LAYER met2 ;
        RECT 1177.230 0.000 1177.510 2.000 ;
    END
  END tx_data[119]
  PIN tx_data[11]
    DIRECTION INPUT ;
    USE SIGNAL ;
    ANTENNAGATEAREA 0.213000 ;
    PORT
      LAYER met3 ;
        RECT 0.000 212.200 2.000 212.800 ;
    END
  END tx_data[11]
  PIN tx_data[120]
    DIRECTION INPUT ;
    USE SIGNAL ;
    ANTENNAGATEAREA 0.247500 ;
    PORT
      LAYER met3 ;
        RECT 1498.000 802.440 1500.000 803.040 ;
    END
  END tx_data[120]
  PIN tx_data[121]
    DIRECTION INPUT ;
    USE SIGNAL ;
    ANTENNAGATEAREA 0.426000 ;
    PORT
      LAYER met2 ;
        RECT 447.210 0.000 447.490 2.000 ;
    END
  END tx_data[121]
  PIN tx_data[122]
    DIRECTION INPUT ;
    USE SIGNAL ;
    ANTENNAGATEAREA 0.742500 ;
    PORT
      LAYER met3 ;
        RECT 1498.000 791.560 1500.000 792.160 ;
    END
  END tx_data[122]
  PIN tx_data[123]
    DIRECTION INPUT ;
    USE SIGNAL ;
    ANTENNAGATEAREA 0.852000 ;
    PORT
      LAYER met3 ;
        RECT 0.000 1043.160 2.000 1043.760 ;
    END
  END tx_data[123]
  PIN tx_data[124]
    DIRECTION INPUT ;
    USE SIGNAL ;
    ANTENNAGATEAREA 0.742500 ;
    PORT
      LAYER met3 ;
        RECT 1498.000 939.800 1500.000 940.400 ;
    END
  END tx_data[124]
  PIN tx_data[125]
    DIRECTION INPUT ;
    USE SIGNAL ;
    ANTENNAGATEAREA 0.990000 ;
    PORT
      LAYER met2 ;
        RECT 422.370 1498.000 422.650 1500.000 ;
    END
  END tx_data[125]
  PIN tx_data[126]
    DIRECTION INPUT ;
    USE SIGNAL ;
    ANTENNAGATEAREA 0.852000 ;
    PORT
      LAYER met3 ;
        RECT 0.000 663.720 2.000 664.320 ;
    END
  END tx_data[126]
  PIN tx_data[127]
    DIRECTION INPUT ;
    USE SIGNAL ;
    ANTENNAGATEAREA 0.213000 ;
    PORT
      LAYER met2 ;
        RECT 981.270 0.000 981.550 2.000 ;
    END
  END tx_data[127]
  PIN tx_data[128]
    DIRECTION INPUT ;
    USE SIGNAL ;
    ANTENNAGATEAREA 0.159000 ;
    PORT
      LAYER met3 ;
        RECT 1498.000 224.440 1500.000 225.040 ;
    END
  END tx_data[128]
  PIN tx_data[129]
    DIRECTION INPUT ;
    USE SIGNAL ;
    ANTENNAGATEAREA 0.742500 ;
    PORT
      LAYER met3 ;
        RECT 0.000 91.160 2.000 91.760 ;
    END
  END tx_data[129]
  PIN tx_data[12]
    DIRECTION INPUT ;
    USE SIGNAL ;
    ANTENNAGATEAREA 0.247500 ;
    PORT
      LAYER met2 ;
        RECT 467.910 0.000 468.190 2.000 ;
    END
  END tx_data[12]
  PIN tx_data[130]
    DIRECTION INPUT ;
    USE SIGNAL ;
    ANTENNAGATEAREA 0.990000 ;
    PORT
      LAYER met3 ;
        RECT 0.000 952.040 2.000 952.640 ;
    END
  END tx_data[130]
  PIN tx_data[131]
    DIRECTION INPUT ;
    USE SIGNAL ;
    ANTENNAGATEAREA 0.990000 ;
    PORT
      LAYER met2 ;
        RECT 1197.930 1498.000 1198.210 1500.000 ;
    END
  END tx_data[131]
  PIN tx_data[132]
    DIRECTION INPUT ;
    USE SIGNAL ;
    ANTENNAGATEAREA 0.742500 ;
    PORT
      LAYER met3 ;
        RECT 0.000 704.520 2.000 705.120 ;
    END
  END tx_data[132]
  PIN tx_data[133]
    DIRECTION INPUT ;
    USE SIGNAL ;
    ANTENNAGATEAREA 0.852000 ;
    PORT
      LAYER met3 ;
        RECT 1498.000 559.000 1500.000 559.600 ;
    END
  END tx_data[133]
  PIN tx_data[134]
    DIRECTION INPUT ;
    USE SIGNAL ;
    ANTENNAGATEAREA 0.159000 ;
    PORT
      LAYER met2 ;
        RECT 703.890 0.000 704.170 2.000 ;
    END
  END tx_data[134]
  PIN tx_data[135]
    DIRECTION INPUT ;
    USE SIGNAL ;
    ANTENNAGATEAREA 0.213000 ;
    PORT
      LAYER met2 ;
        RECT 323.010 0.000 323.290 2.000 ;
    END
  END tx_data[135]
  PIN tx_data[136]
    DIRECTION INPUT ;
    USE SIGNAL ;
    ANTENNAGATEAREA 0.247500 ;
    PORT
      LAYER met2 ;
        RECT 236.070 0.000 236.350 2.000 ;
    END
  END tx_data[136]
  PIN tx_data[137]
    DIRECTION INPUT ;
    USE SIGNAL ;
    ANTENNAGATEAREA 0.495000 ;
    PORT
      LAYER met3 ;
        RECT 1498.000 421.640 1500.000 422.240 ;
    END
  END tx_data[137]
  PIN tx_data[138]
    DIRECTION INPUT ;
    USE SIGNAL ;
    ANTENNAGATEAREA 0.990000 ;
    PORT
      LAYER met2 ;
        RECT 1367.670 1498.000 1367.950 1500.000 ;
    END
  END tx_data[138]
  PIN tx_data[139]
    DIRECTION INPUT ;
    USE SIGNAL ;
    ANTENNAGATEAREA 0.742500 ;
    PORT
      LAYER met3 ;
        RECT 0.000 476.040 2.000 476.640 ;
    END
  END tx_data[139]
  PIN tx_data[13]
    DIRECTION INPUT ;
    USE SIGNAL ;
    ANTENNAGATEAREA 0.990000 ;
    PORT
      LAYER met3 ;
        RECT 1498.000 1350.520 1500.000 1351.120 ;
    END
  END tx_data[13]
  PIN tx_data[140]
    DIRECTION INPUT ;
    USE SIGNAL ;
    ANTENNAGATEAREA 0.990000 ;
    PORT
      LAYER met2 ;
        RECT 1331.790 1498.000 1332.070 1500.000 ;
    END
  END tx_data[140]
  PIN tx_data[141]
    DIRECTION INPUT ;
    USE SIGNAL ;
    ANTENNAGATEAREA 0.852000 ;
    PORT
      LAYER met3 ;
        RECT 0.000 242.120 2.000 242.720 ;
    END
  END tx_data[141]
  PIN tx_data[142]
    DIRECTION INPUT ;
    USE SIGNAL ;
    ANTENNAGATEAREA 0.247500 ;
    PORT
      LAYER met3 ;
        RECT 1498.000 397.160 1500.000 397.760 ;
    END
  END tx_data[142]
  PIN tx_data[143]
    DIRECTION INPUT ;
    USE SIGNAL ;
    ANTENNAGATEAREA 0.159000 ;
    PORT
      LAYER met2 ;
        RECT 1275.210 0.000 1275.490 2.000 ;
    END
  END tx_data[143]
  PIN tx_data[144]
    DIRECTION INPUT ;
    USE SIGNAL ;
    ANTENNAGATEAREA 0.126000 ;
    PORT
      LAYER met2 ;
        RECT 581.070 0.000 581.350 2.000 ;
    END
  END tx_data[144]
  PIN tx_data[145]
    DIRECTION INPUT ;
    USE SIGNAL ;
    ANTENNAGATEAREA 0.742500 ;
    PORT
      LAYER met3 ;
        RECT 1498.000 163.240 1500.000 163.840 ;
    END
  END tx_data[145]
  PIN tx_data[146]
    DIRECTION INPUT ;
    USE SIGNAL ;
    ANTENNAGATEAREA 0.159000 ;
    PORT
      LAYER met2 ;
        RECT 1090.290 0.000 1090.570 2.000 ;
    END
  END tx_data[146]
  PIN tx_data[147]
    DIRECTION INPUT ;
    USE SIGNAL ;
    ANTENNAGATEAREA 0.247500 ;
    PORT
      LAYER met2 ;
        RECT 920.550 0.000 920.830 2.000 ;
    END
  END tx_data[147]
  PIN tx_data[148]
    DIRECTION INPUT ;
    USE SIGNAL ;
    ANTENNAGATEAREA 0.990000 ;
    PORT
      LAYER met3 ;
        RECT 1498.000 1415.800 1500.000 1416.400 ;
    END
  END tx_data[148]
  PIN tx_data[149]
    DIRECTION INPUT ;
    USE SIGNAL ;
    ANTENNAGATEAREA 0.247500 ;
    PORT
      LAYER met2 ;
        RECT 658.350 0.000 658.630 2.000 ;
    END
  END tx_data[149]
  PIN tx_data[14]
    DIRECTION INPUT ;
    USE SIGNAL ;
    ANTENNAGATEAREA 0.247500 ;
    PORT
      LAYER met2 ;
        RECT 1331.790 0.000 1332.070 2.000 ;
    END
  END tx_data[14]
  PIN tx_data[150]
    DIRECTION INPUT ;
    USE SIGNAL ;
    ANTENNAGATEAREA 0.213000 ;
    PORT
      LAYER met2 ;
        RECT 1058.550 0.000 1058.830 2.000 ;
    END
  END tx_data[150]
  PIN tx_data[151]
    DIRECTION INPUT ;
    USE SIGNAL ;
    ANTENNAGATEAREA 0.213000 ;
    PORT
      LAYER met2 ;
        RECT 1018.530 0.000 1018.810 2.000 ;
    END
  END tx_data[151]
  PIN tx_data[152]
    DIRECTION INPUT ;
    USE SIGNAL ;
    ANTENNAGATEAREA 0.495000 ;
    PORT
      LAYER met2 ;
        RECT 256.770 0.000 257.050 2.000 ;
    END
  END tx_data[152]
  PIN tx_data[153]
    DIRECTION INPUT ;
    USE SIGNAL ;
    ANTENNAGATEAREA 0.990000 ;
    PORT
      LAYER met3 ;
        RECT 1498.000 1445.720 1500.000 1446.320 ;
    END
  END tx_data[153]
  PIN tx_data[154]
    DIRECTION INPUT ;
    USE SIGNAL ;
    ANTENNAGATEAREA 0.990000 ;
    PORT
      LAYER met2 ;
        RECT 1105.470 1498.000 1105.750 1500.000 ;
    END
  END tx_data[154]
  PIN tx_data[155]
    DIRECTION INPUT ;
    USE SIGNAL ;
    ANTENNAGATEAREA 0.990000 ;
    PORT
      LAYER met2 ;
        RECT 1157.910 1498.000 1158.190 1500.000 ;
    END
  END tx_data[155]
  PIN tx_data[156]
    DIRECTION INPUT ;
    USE SIGNAL ;
    ANTENNAGATEAREA 0.742500 ;
    PORT
      LAYER met3 ;
        RECT 1498.000 493.720 1500.000 494.320 ;
    END
  END tx_data[156]
  PIN tx_data[157]
    DIRECTION INPUT ;
    USE SIGNAL ;
    ANTENNAGATEAREA 0.990000 ;
    PORT
      LAYER met2 ;
        RECT 545.190 1498.000 545.470 1500.000 ;
    END
  END tx_data[157]
  PIN tx_data[158]
    DIRECTION INPUT ;
    USE SIGNAL ;
    ANTENNAGATEAREA 0.742500 ;
    PORT
      LAYER met3 ;
        RECT 1498.000 427.080 1500.000 427.680 ;
    END
  END tx_data[158]
  PIN tx_data[159]
    DIRECTION INPUT ;
    USE SIGNAL ;
    ANTENNAGATEAREA 0.495000 ;
    PORT
      LAYER met3 ;
        RECT 0.000 516.840 2.000 517.440 ;
    END
  END tx_data[159]
  PIN tx_data[15]
    DIRECTION INPUT ;
    USE SIGNAL ;
    ANTENNAGATEAREA 0.990000 ;
    PORT
      LAYER met2 ;
        RECT 750.810 1498.000 751.090 1500.000 ;
    END
  END tx_data[15]
  PIN tx_data[160]
    DIRECTION INPUT ;
    USE SIGNAL ;
    ANTENNAGATEAREA 0.990000 ;
    PORT
      LAYER met2 ;
        RECT 1254.510 1498.000 1254.790 1500.000 ;
    END
  END tx_data[160]
  PIN tx_data[161]
    DIRECTION INPUT ;
    USE SIGNAL ;
    ANTENNAGATEAREA 0.742500 ;
    PORT
      LAYER met3 ;
        RECT 0.000 206.760 2.000 207.360 ;
    END
  END tx_data[161]
  PIN tx_data[162]
    DIRECTION INPUT ;
    USE SIGNAL ;
    ANTENNAGATEAREA 0.742500 ;
    PORT
      LAYER met2 ;
        RECT 51.150 0.000 51.430 2.000 ;
    END
  END tx_data[162]
  PIN tx_data[163]
    DIRECTION INPUT ;
    USE SIGNAL ;
    ANTENNAGATEAREA 0.852000 ;
    PORT
      LAYER met3 ;
        RECT 1498.000 1127.480 1500.000 1128.080 ;
    END
  END tx_data[163]
  PIN tx_data[164]
    DIRECTION INPUT ;
    USE SIGNAL ;
    ANTENNAGATEAREA 0.426000 ;
    PORT
      LAYER met2 ;
        RECT 1311.090 0.000 1311.370 2.000 ;
    END
  END tx_data[164]
  PIN tx_data[165]
    DIRECTION INPUT ;
    USE SIGNAL ;
    ANTENNAGATEAREA 0.990000 ;
    PORT
      LAYER met2 ;
        RECT 1388.370 1498.000 1388.650 1500.000 ;
    END
  END tx_data[165]
  PIN tx_data[166]
    DIRECTION INPUT ;
    USE SIGNAL ;
    ANTENNAGATEAREA 0.990000 ;
    PORT
      LAYER met2 ;
        RECT 1271.070 1498.000 1271.350 1500.000 ;
    END
  END tx_data[166]
  PIN tx_data[167]
    DIRECTION INPUT ;
    USE SIGNAL ;
    ANTENNAGATEAREA 0.213000 ;
    PORT
      LAYER met2 ;
        RECT 992.310 0.000 992.590 2.000 ;
    END
  END tx_data[167]
  PIN tx_data[168]
    DIRECTION INPUT ;
    USE SIGNAL ;
    ANTENNAGATEAREA 0.990000 ;
    PORT
      LAYER met2 ;
        RECT 1122.030 1498.000 1122.310 1500.000 ;
    END
  END tx_data[168]
  PIN tx_data[169]
    DIRECTION INPUT ;
    USE SIGNAL ;
    ANTENNAGATEAREA 0.990000 ;
    PORT
      LAYER met2 ;
        RECT 298.170 1498.000 298.450 1500.000 ;
    END
  END tx_data[169]
  PIN tx_data[16]
    DIRECTION INPUT ;
    USE SIGNAL ;
    ANTENNAGATEAREA 0.990000 ;
    PORT
      LAYER met2 ;
        RECT 1162.050 1498.000 1162.330 1500.000 ;
    END
  END tx_data[16]
  PIN tx_data[170]
    DIRECTION INPUT ;
    USE SIGNAL ;
    ANTENNAGATEAREA 0.990000 ;
    PORT
      LAYER met2 ;
        RECT 164.310 1498.000 164.590 1500.000 ;
    END
  END tx_data[170]
  PIN tx_data[171]
    DIRECTION INPUT ;
    USE SIGNAL ;
    ANTENNAGATEAREA 0.213000 ;
    PORT
      LAYER met2 ;
        RECT 632.130 0.000 632.410 2.000 ;
    END
  END tx_data[171]
  PIN tx_data[172]
    DIRECTION INPUT ;
    USE SIGNAL ;
    ANTENNAGATEAREA 0.990000 ;
    PORT
      LAYER met3 ;
        RECT 0.000 1018.680 2.000 1019.280 ;
    END
  END tx_data[172]
  PIN tx_data[173]
    DIRECTION INPUT ;
    USE SIGNAL ;
    ANTENNAGATEAREA 0.742500 ;
    PORT
      LAYER met3 ;
        RECT 1498.000 807.880 1500.000 808.480 ;
    END
  END tx_data[173]
  PIN tx_data[174]
    DIRECTION INPUT ;
    USE SIGNAL ;
    ANTENNAGATEAREA 0.852000 ;
    PORT
      LAYER met3 ;
        RECT 1498.000 1243.080 1500.000 1243.680 ;
    END
  END tx_data[174]
  PIN tx_data[175]
    DIRECTION INPUT ;
    USE SIGNAL ;
    ANTENNAGATEAREA 0.495000 ;
    PORT
      LAYER met3 ;
        RECT 0.000 282.920 2.000 283.520 ;
    END
  END tx_data[175]
  PIN tx_data[176]
    DIRECTION INPUT ;
    USE SIGNAL ;
    ANTENNAGATEAREA 0.990000 ;
    PORT
      LAYER met2 ;
        RECT 133.950 1498.000 134.230 1500.000 ;
    END
  END tx_data[176]
  PIN tx_data[177]
    DIRECTION INPUT ;
    USE SIGNAL ;
    ANTENNAGATEAREA 0.990000 ;
    PORT
      LAYER met3 ;
        RECT 0.000 1104.360 2.000 1104.960 ;
    END
  END tx_data[177]
  PIN tx_data[178]
    DIRECTION INPUT ;
    USE SIGNAL ;
    ANTENNAGATEAREA 0.159000 ;
    PORT
      LAYER met3 ;
        RECT 1498.000 300.600 1500.000 301.200 ;
    END
  END tx_data[178]
  PIN tx_data[179]
    DIRECTION INPUT ;
    USE SIGNAL ;
    ANTENNAGATEAREA 0.495000 ;
    PORT
      LAYER met3 ;
        RECT 1498.000 1101.640 1500.000 1102.240 ;
    END
  END tx_data[179]
  PIN tx_data[17]
    DIRECTION INPUT ;
    USE SIGNAL ;
    ANTENNAGATEAREA 0.159000 ;
    PORT
      LAYER met2 ;
        RECT 832.230 0.000 832.510 2.000 ;
    END
  END tx_data[17]
  PIN tx_data[180]
    DIRECTION INPUT ;
    USE SIGNAL ;
    ANTENNAGATEAREA 0.247500 ;
    PORT
      LAYER met2 ;
        RECT 709.410 0.000 709.690 2.000 ;
    END
  END tx_data[180]
  PIN tx_data[181]
    DIRECTION INPUT ;
    USE SIGNAL ;
    ANTENNAGATEAREA 0.990000 ;
    PORT
      LAYER met3 ;
        RECT 0.000 496.440 2.000 497.040 ;
    END
  END tx_data[181]
  PIN tx_data[182]
    DIRECTION INPUT ;
    USE SIGNAL ;
    ANTENNAGATEAREA 0.213000 ;
    PORT
      LAYER met3 ;
        RECT 1498.000 289.720 1500.000 290.320 ;
    END
  END tx_data[182]
  PIN tx_data[183]
    DIRECTION INPUT ;
    USE SIGNAL ;
    ANTENNAGATEAREA 0.426000 ;
    PORT
      LAYER met3 ;
        RECT 1498.000 923.480 1500.000 924.080 ;
    END
  END tx_data[183]
  PIN tx_data[184]
    DIRECTION INPUT ;
    USE SIGNAL ;
    ANTENNAGATEAREA 0.990000 ;
    PORT
      LAYER met3 ;
        RECT 0.000 613.400 2.000 614.000 ;
    END
  END tx_data[184]
  PIN tx_data[185]
    DIRECTION INPUT ;
    USE SIGNAL ;
    ANTENNAGATEAREA 0.495000 ;
    PORT
      LAYER met3 ;
        RECT 1498.000 847.320 1500.000 847.920 ;
    END
  END tx_data[185]
  PIN tx_data[186]
    DIRECTION INPUT ;
    USE SIGNAL ;
    ANTENNAGATEAREA 0.213000 ;
    PORT
      LAYER met3 ;
        RECT 1498.000 335.960 1500.000 336.560 ;
    END
  END tx_data[186]
  PIN tx_data[187]
    DIRECTION INPUT ;
    USE SIGNAL ;
    ANTENNAGATEAREA 0.159000 ;
    PORT
      LAYER met2 ;
        RECT 1280.730 0.000 1281.010 2.000 ;
    END
  END tx_data[187]
  PIN tx_data[188]
    DIRECTION INPUT ;
    USE SIGNAL ;
    ANTENNAGATEAREA 0.990000 ;
    PORT
      LAYER met2 ;
        RECT 498.270 1498.000 498.550 1500.000 ;
    END
  END tx_data[188]
  PIN tx_data[189]
    DIRECTION INPUT ;
    USE SIGNAL ;
    ANTENNAGATEAREA 0.426000 ;
    PORT
      LAYER met3 ;
        RECT 1498.000 97.960 1500.000 98.560 ;
    END
  END tx_data[189]
  PIN tx_data[18]
    DIRECTION INPUT ;
    USE SIGNAL ;
    ANTENNAGATEAREA 0.742500 ;
    PORT
      LAYER met3 ;
        RECT 1498.000 811.960 1500.000 812.560 ;
    END
  END tx_data[18]
  PIN tx_data[190]
    DIRECTION INPUT ;
    USE SIGNAL ;
    ANTENNAGATEAREA 0.742500 ;
    PORT
      LAYER met2 ;
        RECT 1178.610 1498.000 1178.890 1500.000 ;
    END
  END tx_data[190]
  PIN tx_data[191]
    DIRECTION INPUT ;
    USE SIGNAL ;
    ANTENNAGATEAREA 0.426000 ;
    PORT
      LAYER met2 ;
        RECT 1224.150 1498.000 1224.430 1500.000 ;
    END
  END tx_data[191]
  PIN tx_data[192]
    DIRECTION INPUT ;
    USE SIGNAL ;
    ANTENNAGATEAREA 0.159000 ;
    PORT
      LAYER met3 ;
        RECT 1498.000 295.160 1500.000 295.760 ;
    END
  END tx_data[192]
  PIN tx_data[193]
    DIRECTION INPUT ;
    USE SIGNAL ;
    ANTENNAGATEAREA 0.213000 ;
    PORT
      LAYER met2 ;
        RECT 1454.610 0.000 1454.890 2.000 ;
    END
  END tx_data[193]
  PIN tx_data[194]
    DIRECTION INPUT ;
    USE SIGNAL ;
    ANTENNAGATEAREA 0.852000 ;
    PORT
      LAYER met3 ;
        RECT 0.000 161.880 2.000 162.480 ;
    END
  END tx_data[194]
  PIN tx_data[195]
    DIRECTION INPUT ;
    USE SIGNAL ;
    ANTENNAGATEAREA 0.990000 ;
    PORT
      LAYER met2 ;
        RECT 905.370 1498.000 905.650 1500.000 ;
    END
  END tx_data[195]
  PIN tx_data[196]
    DIRECTION INPUT ;
    USE SIGNAL ;
    ANTENNAGATEAREA 0.990000 ;
    PORT
      LAYER met2 ;
        RECT 196.050 1498.000 196.330 1500.000 ;
    END
  END tx_data[196]
  PIN tx_data[197]
    DIRECTION INPUT ;
    USE SIGNAL ;
    ANTENNAGATEAREA 0.990000 ;
    PORT
      LAYER met2 ;
        RECT 694.230 1498.000 694.510 1500.000 ;
    END
  END tx_data[197]
  PIN tx_data[198]
    DIRECTION INPUT ;
    USE SIGNAL ;
    ANTENNAGATEAREA 0.247500 ;
    PORT
      LAYER met3 ;
        RECT 0.000 55.800 2.000 56.400 ;
    END
  END tx_data[198]
  PIN tx_data[199]
    DIRECTION INPUT ;
    USE SIGNAL ;
    ANTENNAGATEAREA 0.990000 ;
    PORT
      LAYER met2 ;
        RECT 426.510 1498.000 426.790 1500.000 ;
    END
  END tx_data[199]
  PIN tx_data[19]
    DIRECTION INPUT ;
    USE SIGNAL ;
    ANTENNAGATEAREA 0.742500 ;
    PORT
      LAYER met3 ;
        RECT 1498.000 867.720 1500.000 868.320 ;
    END
  END tx_data[19]
  PIN tx_data[1]
    DIRECTION INPUT ;
    USE SIGNAL ;
    ANTENNAGATEAREA 0.990000 ;
    PORT
      LAYER met2 ;
        RECT 1378.710 0.000 1378.990 2.000 ;
    END
  END tx_data[1]
  PIN tx_data[200]
    DIRECTION INPUT ;
    USE SIGNAL ;
    ANTENNAGATEAREA 0.247500 ;
    PORT
      LAYER met3 ;
        RECT 1498.000 401.240 1500.000 401.840 ;
    END
  END tx_data[200]
  PIN tx_data[201]
    DIRECTION INPUT ;
    USE SIGNAL ;
    ANTENNAGATEAREA 0.426000 ;
    PORT
      LAYER met2 ;
        RECT 349.230 0.000 349.510 2.000 ;
    END
  END tx_data[201]
  PIN tx_data[202]
    DIRECTION INPUT ;
    USE SIGNAL ;
    ANTENNAGATEAREA 0.426000 ;
    PORT
      LAYER met3 ;
        RECT 1498.000 533.160 1500.000 533.760 ;
    END
  END tx_data[202]
  PIN tx_data[203]
    DIRECTION INPUT ;
    USE SIGNAL ;
    ANTENNAGATEAREA 0.495000 ;
    PORT
      LAYER met3 ;
        RECT 1498.000 629.720 1500.000 630.320 ;
    END
  END tx_data[203]
  PIN tx_data[204]
    DIRECTION INPUT ;
    USE SIGNAL ;
    ANTENNAGATEAREA 0.426000 ;
    PORT
      LAYER met2 ;
        RECT 1162.050 0.000 1162.330 2.000 ;
    END
  END tx_data[204]
  PIN tx_data[205]
    DIRECTION INPUT ;
    USE SIGNAL ;
    ANTENNAGATEAREA 0.426000 ;
    PORT
      LAYER met3 ;
        RECT 1498.000 969.720 1500.000 970.320 ;
    END
  END tx_data[205]
  PIN tx_data[206]
    DIRECTION INPUT ;
    USE SIGNAL ;
    ANTENNAGATEAREA 0.495000 ;
    PORT
      LAYER met3 ;
        RECT 1498.000 1207.720 1500.000 1208.320 ;
    END
  END tx_data[206]
  PIN tx_data[207]
    DIRECTION INPUT ;
    USE SIGNAL ;
    ANTENNAGATEAREA 0.742500 ;
    PORT
      LAYER met2 ;
        RECT 1306.950 1498.000 1307.230 1500.000 ;
    END
  END tx_data[207]
  PIN tx_data[208]
    DIRECTION INPUT ;
    USE SIGNAL ;
    ANTENNAGATEAREA 0.852000 ;
    PORT
      LAYER met2 ;
        RECT 494.130 1498.000 494.410 1500.000 ;
    END
  END tx_data[208]
  PIN tx_data[209]
    DIRECTION INPUT ;
    USE SIGNAL ;
    ANTENNAGATEAREA 0.247500 ;
    PORT
      LAYER met3 ;
        RECT 1498.000 954.760 1500.000 955.360 ;
    END
  END tx_data[209]
  PIN tx_data[20]
    DIRECTION INPUT ;
    USE SIGNAL ;
    ANTENNAGATEAREA 0.247500 ;
    PORT
      LAYER met2 ;
        RECT 1393.890 0.000 1394.170 2.000 ;
    END
  END tx_data[20]
  PIN tx_data[210]
    DIRECTION INPUT ;
    USE SIGNAL ;
    ANTENNAGATEAREA 0.495000 ;
    PORT
      LAYER met3 ;
        RECT 1498.000 1324.680 1500.000 1325.280 ;
    END
  END tx_data[210]
  PIN tx_data[211]
    DIRECTION INPUT ;
    USE SIGNAL ;
    ANTENNAGATEAREA 0.852000 ;
    PORT
      LAYER met2 ;
        RECT 679.050 0.000 679.330 2.000 ;
    END
  END tx_data[211]
  PIN tx_data[212]
    DIRECTION INPUT ;
    USE SIGNAL ;
    ANTENNAGATEAREA 0.742500 ;
    PORT
      LAYER met2 ;
        RECT 1239.330 0.000 1239.610 2.000 ;
    END
  END tx_data[212]
  PIN tx_data[213]
    DIRECTION INPUT ;
    USE SIGNAL ;
    ANTENNAGATEAREA 0.247500 ;
    PORT
      LAYER met3 ;
        RECT 1498.000 382.200 1500.000 382.800 ;
    END
  END tx_data[213]
  PIN tx_data[214]
    DIRECTION INPUT ;
    USE SIGNAL ;
    ANTENNAGATEAREA 0.852000 ;
    PORT
      LAYER met2 ;
        RECT 905.370 0.000 905.650 2.000 ;
    END
  END tx_data[214]
  PIN tx_data[215]
    DIRECTION INPUT ;
    USE SIGNAL ;
    ANTENNAGATEAREA 0.990000 ;
    PORT
      LAYER met2 ;
        RECT 241.590 1498.000 241.870 1500.000 ;
    END
  END tx_data[215]
  PIN tx_data[216]
    DIRECTION INPUT ;
    USE SIGNAL ;
    ANTENNAGATEAREA 0.990000 ;
    PORT
      LAYER met2 ;
        RECT 385.110 1498.000 385.390 1500.000 ;
    END
  END tx_data[216]
  PIN tx_data[217]
    DIRECTION INPUT ;
    USE SIGNAL ;
    ANTENNAGATEAREA 0.990000 ;
    PORT
      LAYER met3 ;
        RECT 0.000 1459.320 2.000 1459.920 ;
    END
  END tx_data[217]
  PIN tx_data[218]
    DIRECTION INPUT ;
    USE SIGNAL ;
    ANTENNAGATEAREA 0.852000 ;
    PORT
      LAYER met2 ;
        RECT 858.450 0.000 858.730 2.000 ;
    END
  END tx_data[218]
  PIN tx_data[219]
    DIRECTION INPUT ;
    USE SIGNAL ;
    ANTENNAGATEAREA 0.742500 ;
    PORT
      LAYER met2 ;
        RECT 688.710 1498.000 688.990 1500.000 ;
    END
  END tx_data[219]
  PIN tx_data[21]
    DIRECTION INPUT ;
    USE SIGNAL ;
    ANTENNAGATEAREA 0.990000 ;
    PORT
      LAYER met3 ;
        RECT 0.000 1317.880 2.000 1318.480 ;
    END
  END tx_data[21]
  PIN tx_data[220]
    DIRECTION INPUT ;
    USE SIGNAL ;
    ANTENNAGATEAREA 0.742500 ;
    PORT
      LAYER met3 ;
        RECT 0.000 470.600 2.000 471.200 ;
    END
  END tx_data[220]
  PIN tx_data[221]
    DIRECTION INPUT ;
    USE SIGNAL ;
    ANTENNAGATEAREA 0.426000 ;
    PORT
      LAYER met3 ;
        RECT 1498.000 1157.400 1500.000 1158.000 ;
    END
  END tx_data[221]
  PIN tx_data[222]
    DIRECTION INPUT ;
    USE SIGNAL ;
    ANTENNAGATEAREA 0.247500 ;
    PORT
      LAYER met3 ;
        RECT 1498.000 376.760 1500.000 377.360 ;
    END
  END tx_data[222]
  PIN tx_data[223]
    DIRECTION INPUT ;
    USE SIGNAL ;
    ANTENNAGATEAREA 0.213000 ;
    PORT
      LAYER met3 ;
        RECT 1498.000 620.200 1500.000 620.800 ;
    END
  END tx_data[223]
  PIN tx_data[224]
    DIRECTION INPUT ;
    USE SIGNAL ;
    ANTENNAGATEAREA 0.852000 ;
    PORT
      LAYER met2 ;
        RECT 1182.750 0.000 1183.030 2.000 ;
    END
  END tx_data[224]
  PIN tx_data[225]
    DIRECTION INPUT ;
    USE SIGNAL ;
    ANTENNAGATEAREA 0.852000 ;
    PORT
      LAYER met2 ;
        RECT 622.470 0.000 622.750 2.000 ;
    END
  END tx_data[225]
  PIN tx_data[226]
    DIRECTION INPUT ;
    USE SIGNAL ;
    ANTENNAGATEAREA 0.426000 ;
    PORT
      LAYER met2 ;
        RECT 1105.470 0.000 1105.750 2.000 ;
    END
  END tx_data[226]
  PIN tx_data[227]
    DIRECTION INPUT ;
    USE SIGNAL ;
    ANTENNAGATEAREA 0.742500 ;
    PORT
      LAYER met2 ;
        RECT 15.270 0.000 15.550 2.000 ;
    END
  END tx_data[227]
  PIN tx_data[228]
    DIRECTION INPUT ;
    USE SIGNAL ;
    ANTENNAGATEAREA 0.990000 ;
    PORT
      LAYER met2 ;
        RECT 720.450 1498.000 720.730 1500.000 ;
    END
  END tx_data[228]
  PIN tx_data[229]
    DIRECTION INPUT ;
    USE SIGNAL ;
    ANTENNAGATEAREA 0.426000 ;
    PORT
      LAYER met3 ;
        RECT 1498.000 1075.800 1500.000 1076.400 ;
    END
  END tx_data[229]
  PIN tx_data[22]
    DIRECTION INPUT ;
    USE SIGNAL ;
    ANTENNAGATEAREA 0.990000 ;
    PORT
      LAYER met2 ;
        RECT 837.750 1498.000 838.030 1500.000 ;
    END
  END tx_data[22]
  PIN tx_data[230]
    DIRECTION INPUT ;
    USE SIGNAL ;
    ANTENNAGATEAREA 0.742500 ;
    PORT
      LAYER met3 ;
        RECT 0.000 693.640 2.000 694.240 ;
    END
  END tx_data[230]
  PIN tx_data[231]
    DIRECTION INPUT ;
    USE SIGNAL ;
    ANTENNAGATEAREA 0.426000 ;
    PORT
      LAYER met2 ;
        RECT 1460.130 0.000 1460.410 2.000 ;
    END
  END tx_data[231]
  PIN tx_data[232]
    DIRECTION INPUT ;
    USE SIGNAL ;
    ANTENNAGATEAREA 0.852000 ;
    PORT
      LAYER met2 ;
        RECT 35.970 0.000 36.250 2.000 ;
    END
  END tx_data[232]
  PIN tx_data[233]
    DIRECTION INPUT ;
    USE SIGNAL ;
    ANTENNAGATEAREA 0.990000 ;
    PORT
      LAYER met2 ;
        RECT 405.810 1498.000 406.090 1500.000 ;
    END
  END tx_data[233]
  PIN tx_data[234]
    DIRECTION INPUT ;
    USE SIGNAL ;
    ANTENNAGATEAREA 0.426000 ;
    PORT
      LAYER met3 ;
        RECT 1498.000 878.600 1500.000 879.200 ;
    END
  END tx_data[234]
  PIN tx_data[235]
    DIRECTION INPUT ;
    USE SIGNAL ;
    ANTENNAGATEAREA 0.742500 ;
    PORT
      LAYER met3 ;
        RECT 0.000 977.880 2.000 978.480 ;
    END
  END tx_data[235]
  PIN tx_data[236]
    DIRECTION INPUT ;
    USE SIGNAL ;
    ANTENNAGATEAREA 0.742500 ;
    PORT
      LAYER met2 ;
        RECT 971.610 1498.000 971.890 1500.000 ;
    END
  END tx_data[236]
  PIN tx_data[237]
    DIRECTION INPUT ;
    USE SIGNAL ;
    ANTENNAGATEAREA 0.742500 ;
    PORT
      LAYER met2 ;
        RECT 1414.590 1498.000 1414.870 1500.000 ;
    END
  END tx_data[237]
  PIN tx_data[238]
    DIRECTION INPUT ;
    USE SIGNAL ;
    ANTENNAGATEAREA 0.742500 ;
    PORT
      LAYER met2 ;
        RECT 637.650 0.000 637.930 2.000 ;
    END
  END tx_data[238]
  PIN tx_data[239]
    DIRECTION INPUT ;
    USE SIGNAL ;
    ANTENNAGATEAREA 0.990000 ;
    PORT
      LAYER met2 ;
        RECT 807.390 1498.000 807.670 1500.000 ;
    END
  END tx_data[239]
  PIN tx_data[23]
    DIRECTION INPUT ;
    USE SIGNAL ;
    ANTENNAGATEAREA 0.495000 ;
    PORT
      LAYER met3 ;
        RECT 0.000 111.560 2.000 112.160 ;
    END
  END tx_data[23]
  PIN tx_data[240]
    DIRECTION INPUT ;
    USE SIGNAL ;
    ANTENNAGATEAREA 0.742500 ;
    PORT
      LAYER met2 ;
        RECT 1137.210 1498.000 1137.490 1500.000 ;
    END
  END tx_data[240]
  PIN tx_data[241]
    DIRECTION INPUT ;
    USE SIGNAL ;
    ANTENNAGATEAREA 0.426000 ;
    PORT
      LAYER met3 ;
        RECT 1498.000 1040.440 1500.000 1041.040 ;
    END
  END tx_data[241]
  PIN tx_data[242]
    DIRECTION INPUT ;
    USE SIGNAL ;
    ANTENNAGATEAREA 0.852000 ;
    PORT
      LAYER met2 ;
        RECT 982.650 1498.000 982.930 1500.000 ;
    END
  END tx_data[242]
  PIN tx_data[243]
    DIRECTION INPUT ;
    USE SIGNAL ;
    ANTENNAGATEAREA 0.742500 ;
    PORT
      LAYER met3 ;
        RECT 0.000 576.680 2.000 577.280 ;
    END
  END tx_data[243]
  PIN tx_data[244]
    DIRECTION INPUT ;
    USE SIGNAL ;
    ANTENNAGATEAREA 0.990000 ;
    PORT
      LAYER met2 ;
        RECT 66.330 1498.000 66.610 1500.000 ;
    END
  END tx_data[244]
  PIN tx_data[245]
    DIRECTION INPUT ;
    USE SIGNAL ;
    ANTENNAGATEAREA 0.742500 ;
    PORT
      LAYER met2 ;
        RECT 967.470 1498.000 967.750 1500.000 ;
    END
  END tx_data[245]
  PIN tx_data[246]
    DIRECTION INPUT ;
    USE SIGNAL ;
    ANTENNAGATEAREA 0.990000 ;
    PORT
      LAYER met3 ;
        RECT 0.000 414.840 2.000 415.440 ;
    END
  END tx_data[246]
  PIN tx_data[247]
    DIRECTION INPUT ;
    USE SIGNAL ;
    ANTENNAGATEAREA 0.742500 ;
    PORT
      LAYER met2 ;
        RECT 920.550 1498.000 920.830 1500.000 ;
    END
  END tx_data[247]
  PIN tx_data[248]
    DIRECTION INPUT ;
    USE SIGNAL ;
    ANTENNAGATEAREA 0.990000 ;
    PORT
      LAYER met3 ;
        RECT 0.000 1124.760 2.000 1125.360 ;
    END
  END tx_data[248]
  PIN tx_data[249]
    DIRECTION INPUT ;
    USE SIGNAL ;
    ANTENNAGATEAREA 0.990000 ;
    PORT
      LAYER met2 ;
        RECT 292.650 1498.000 292.930 1500.000 ;
    END
  END tx_data[249]
  PIN tx_data[24]
    DIRECTION INPUT ;
    USE SIGNAL ;
    ANTENNAGATEAREA 0.990000 ;
    PORT
      LAYER met3 ;
        RECT 1498.000 1304.280 1500.000 1304.880 ;
    END
  END tx_data[24]
  PIN tx_data[250]
    DIRECTION INPUT ;
    USE SIGNAL ;
    ANTENNAGATEAREA 0.990000 ;
    PORT
      LAYER met3 ;
        RECT 0.000 892.200 2.000 892.800 ;
    END
  END tx_data[250]
  PIN tx_data[251]
    DIRECTION INPUT ;
    USE SIGNAL ;
    ANTENNAGATEAREA 0.990000 ;
    PORT
      LAYER met3 ;
        RECT 0.000 126.520 2.000 127.120 ;
    END
  END tx_data[251]
  PIN tx_data[252]
    DIRECTION INPUT ;
    USE SIGNAL ;
    ANTENNAGATEAREA 0.247500 ;
    PORT
      LAYER met2 ;
        RECT 1367.670 0.000 1367.950 2.000 ;
    END
  END tx_data[252]
  PIN tx_data[253]
    DIRECTION INPUT ;
    USE SIGNAL ;
    ANTENNAGATEAREA 0.247500 ;
    PORT
      LAYER met2 ;
        RECT 760.470 0.000 760.750 2.000 ;
    END
  END tx_data[253]
  PIN tx_data[254]
    DIRECTION INPUT ;
    USE SIGNAL ;
    ANTENNAGATEAREA 0.742500 ;
    PORT
      LAYER met3 ;
        RECT 1498.000 1051.320 1500.000 1051.920 ;
    END
  END tx_data[254]
  PIN tx_data[255]
    DIRECTION INPUT ;
    USE SIGNAL ;
    ANTENNAGATEAREA 0.990000 ;
    PORT
      LAYER met3 ;
        RECT 0.000 561.720 2.000 562.320 ;
    END
  END tx_data[255]
  PIN tx_data[256]
    DIRECTION INPUT ;
    USE SIGNAL ;
    ANTENNAGATEAREA 0.852000 ;
    PORT
      LAYER met2 ;
        RECT 858.450 1498.000 858.730 1500.000 ;
    END
  END tx_data[256]
  PIN tx_data[257]
    DIRECTION INPUT ;
    USE SIGNAL ;
    ANTENNAGATEAREA 0.852000 ;
    PORT
      LAYER met3 ;
        RECT 0.000 1494.680 2.000 1495.280 ;
    END
  END tx_data[257]
  PIN tx_data[258]
    DIRECTION INPUT ;
    USE SIGNAL ;
    ANTENNAGATEAREA 0.990000 ;
    PORT
      LAYER met2 ;
        RECT 863.970 1498.000 864.250 1500.000 ;
    END
  END tx_data[258]
  PIN tx_data[259]
    DIRECTION INPUT ;
    USE SIGNAL ;
    ANTENNAGATEAREA 0.742500 ;
    PORT
      LAYER met3 ;
        RECT 0.000 1150.600 2.000 1151.200 ;
    END
  END tx_data[259]
  PIN tx_data[25]
    DIRECTION INPUT ;
    USE SIGNAL ;
    ANTENNAGATEAREA 0.247500 ;
    PORT
      LAYER met2 ;
        RECT 379.590 0.000 379.870 2.000 ;
    END
  END tx_data[25]
  PIN tx_data[260]
    DIRECTION INPUT ;
    USE SIGNAL ;
    ANTENNAGATEAREA 0.990000 ;
    PORT
      LAYER met2 ;
        RECT 441.690 1498.000 441.970 1500.000 ;
    END
  END tx_data[260]
  PIN tx_data[261]
    DIRECTION INPUT ;
    USE SIGNAL ;
    ANTENNAGATEAREA 0.426000 ;
    PORT
      LAYER met2 ;
        RECT 986.790 0.000 987.070 2.000 ;
    END
  END tx_data[261]
  PIN tx_data[262]
    DIRECTION INPUT ;
    USE SIGNAL ;
    ANTENNAGATEAREA 0.990000 ;
    PORT
      LAYER met2 ;
        RECT 375.450 1498.000 375.730 1500.000 ;
    END
  END tx_data[262]
  PIN tx_data[263]
    DIRECTION INPUT ;
    USE SIGNAL ;
    ANTENNAGATEAREA 0.742500 ;
    PORT
      LAYER met3 ;
        RECT 1498.000 665.080 1500.000 665.680 ;
    END
  END tx_data[263]
  PIN tx_data[264]
    DIRECTION INPUT ;
    USE SIGNAL ;
    ANTENNAGATEAREA 0.742500 ;
    PORT
      LAYER met3 ;
        RECT 0.000 238.040 2.000 238.640 ;
    END
  END tx_data[264]
  PIN tx_data[265]
    DIRECTION INPUT ;
    USE SIGNAL ;
    ANTENNAGATEAREA 0.495000 ;
    PORT
      LAYER met3 ;
        RECT 1498.000 772.520 1500.000 773.120 ;
    END
  END tx_data[265]
  PIN tx_data[266]
    DIRECTION INPUT ;
    USE SIGNAL ;
    ANTENNAGATEAREA 0.495000 ;
    PORT
      LAYER met3 ;
        RECT 0.000 617.480 2.000 618.080 ;
    END
  END tx_data[266]
  PIN tx_data[267]
    DIRECTION INPUT ;
    USE SIGNAL ;
    ANTENNAGATEAREA 0.852000 ;
    PORT
      LAYER met2 ;
        RECT 1146.870 1498.000 1147.150 1500.000 ;
    END
  END tx_data[267]
  PIN tx_data[268]
    DIRECTION INPUT ;
    USE SIGNAL ;
    ANTENNAGATEAREA 0.426000 ;
    PORT
      LAYER met2 ;
        RECT 719.070 0.000 719.350 2.000 ;
    END
  END tx_data[268]
  PIN tx_data[269]
    DIRECTION INPUT ;
    USE SIGNAL ;
    ANTENNAGATEAREA 0.852000 ;
    PORT
      LAYER met3 ;
        RECT 1498.000 1213.160 1500.000 1213.760 ;
    END
  END tx_data[269]
  PIN tx_data[26]
    DIRECTION INPUT ;
    USE SIGNAL ;
    ANTENNAGATEAREA 0.213000 ;
    PORT
      LAYER met2 ;
        RECT 945.390 0.000 945.670 2.000 ;
    END
  END tx_data[26]
  PIN tx_data[270]
    DIRECTION INPUT ;
    USE SIGNAL ;
    ANTENNAGATEAREA 0.495000 ;
    PORT
      LAYER met3 ;
        RECT 0.000 146.920 2.000 147.520 ;
    END
  END tx_data[270]
  PIN tx_data[271]
    DIRECTION INPUT ;
    USE SIGNAL ;
    ANTENNAGATEAREA 0.426000 ;
    PORT
      LAYER met3 ;
        RECT 0.000 481.480 2.000 482.080 ;
    END
  END tx_data[271]
  PIN tx_data[272]
    DIRECTION INPUT ;
    USE SIGNAL ;
    ANTENNAGATEAREA 0.990000 ;
    PORT
      LAYER met2 ;
        RECT 875.010 1498.000 875.290 1500.000 ;
    END
  END tx_data[272]
  PIN tx_data[273]
    DIRECTION INPUT ;
    USE SIGNAL ;
    ANTENNAGATEAREA 0.247500 ;
    PORT
      LAYER met3 ;
        RECT 0.000 708.600 2.000 709.200 ;
    END
  END tx_data[273]
  PIN tx_data[274]
    DIRECTION INPUT ;
    USE SIGNAL ;
    ANTENNAGATEAREA 0.742500 ;
    PORT
      LAYER met2 ;
        RECT 668.010 1498.000 668.290 1500.000 ;
    END
  END tx_data[274]
  PIN tx_data[275]
    DIRECTION INPUT ;
    USE SIGNAL ;
    ANTENNAGATEAREA 0.742500 ;
    PORT
      LAYER met2 ;
        RECT 868.110 0.000 868.390 2.000 ;
    END
  END tx_data[275]
  PIN tx_data[276]
    DIRECTION INPUT ;
    USE SIGNAL ;
    ANTENNAGATEAREA 0.159000 ;
    PORT
      LAYER met2 ;
        RECT 472.050 0.000 472.330 2.000 ;
    END
  END tx_data[276]
  PIN tx_data[277]
    DIRECTION INPUT ;
    USE SIGNAL ;
    ANTENNAGATEAREA 0.247500 ;
    PORT
      LAYER met3 ;
        RECT 0.000 176.840 2.000 177.440 ;
    END
  END tx_data[277]
  PIN tx_data[278]
    DIRECTION INPUT ;
    USE SIGNAL ;
    ANTENNAGATEAREA 0.852000 ;
    PORT
      LAYER met2 ;
        RECT 1424.250 0.000 1424.530 2.000 ;
    END
  END tx_data[278]
  PIN tx_data[279]
    DIRECTION INPUT ;
    USE SIGNAL ;
    ANTENNAGATEAREA 0.990000 ;
    PORT
      LAYER met3 ;
        RECT 1498.000 1313.800 1500.000 1314.400 ;
    END
  END tx_data[279]
  PIN tx_data[27]
    DIRECTION INPUT ;
    USE SIGNAL ;
    ANTENNAGATEAREA 0.213000 ;
    PORT
      LAYER met2 ;
        RECT 575.550 0.000 575.830 2.000 ;
    END
  END tx_data[27]
  PIN tx_data[280]
    DIRECTION INPUT ;
    USE SIGNAL ;
    ANTENNAGATEAREA 0.990000 ;
    PORT
      LAYER met2 ;
        RECT 997.830 1498.000 998.110 1500.000 ;
    END
  END tx_data[280]
  PIN tx_data[281]
    DIRECTION INPUT ;
    USE SIGNAL ;
    ANTENNAGATEAREA 0.852000 ;
    PORT
      LAYER met2 ;
        RECT 575.550 1498.000 575.830 1500.000 ;
    END
  END tx_data[281]
  PIN tx_data[282]
    DIRECTION INPUT ;
    USE SIGNAL ;
    ANTENNAGATEAREA 0.742500 ;
    PORT
      LAYER met3 ;
        RECT 1498.000 670.520 1500.000 671.120 ;
    END
  END tx_data[282]
  PIN tx_data[283]
    DIRECTION INPUT ;
    USE SIGNAL ;
    ANTENNAGATEAREA 0.852000 ;
    PORT
      LAYER met2 ;
        RECT 102.210 1498.000 102.490 1500.000 ;
    END
  END tx_data[283]
  PIN tx_data[284]
    DIRECTION INPUT ;
    USE SIGNAL ;
    ANTENNAGATEAREA 0.742500 ;
    PORT
      LAYER met3 ;
        RECT 0.000 1403.560 2.000 1404.160 ;
    END
  END tx_data[284]
  PIN tx_data[285]
    DIRECTION INPUT ;
    USE SIGNAL ;
    ANTENNAGATEAREA 0.990000 ;
    PORT
      LAYER met3 ;
        RECT 1498.000 1400.840 1500.000 1401.440 ;
    END
  END tx_data[285]
  PIN tx_data[286]
    DIRECTION INPUT ;
    USE SIGNAL ;
    ANTENNAGATEAREA 0.742500 ;
    PORT
      LAYER met2 ;
        RECT 539.670 1498.000 539.950 1500.000 ;
    END
  END tx_data[286]
  PIN tx_data[287]
    DIRECTION INPUT ;
    USE SIGNAL ;
    ANTENNAGATEAREA 0.213000 ;
    PORT
      LAYER met2 ;
        RECT 735.630 0.000 735.910 2.000 ;
    END
  END tx_data[287]
  PIN tx_data[288]
    DIRECTION INPUT ;
    USE SIGNAL ;
    ANTENNAGATEAREA 0.426000 ;
    PORT
      LAYER met2 ;
        RECT 405.810 0.000 406.090 2.000 ;
    END
  END tx_data[288]
  PIN tx_data[289]
    DIRECTION INPUT ;
    USE SIGNAL ;
    ANTENNAGATEAREA 0.426000 ;
    PORT
      LAYER met3 ;
        RECT 0.000 70.760 2.000 71.360 ;
    END
  END tx_data[289]
  PIN tx_data[28]
    DIRECTION INPUT ;
    USE SIGNAL ;
    ANTENNAGATEAREA 0.426000 ;
    PORT
      LAYER met3 ;
        RECT 0.000 344.120 2.000 344.720 ;
    END
  END tx_data[28]
  PIN tx_data[290]
    DIRECTION INPUT ;
    USE SIGNAL ;
    ANTENNAGATEAREA 0.852000 ;
    PORT
      LAYER met2 ;
        RECT 961.950 0.000 962.230 2.000 ;
    END
  END tx_data[290]
  PIN tx_data[291]
    DIRECTION INPUT ;
    USE SIGNAL ;
    ANTENNAGATEAREA 0.990000 ;
    PORT
      LAYER met2 ;
        RECT 1069.590 1498.000 1069.870 1500.000 ;
    END
  END tx_data[291]
  PIN tx_data[292]
    DIRECTION INPUT ;
    USE SIGNAL ;
    ANTENNAGATEAREA 0.990000 ;
    PORT
      LAYER met2 ;
        RECT 56.670 1498.000 56.950 1500.000 ;
    END
  END tx_data[292]
  PIN tx_data[293]
    DIRECTION INPUT ;
    USE SIGNAL ;
    ANTENNAGATEAREA 0.990000 ;
    PORT
      LAYER met2 ;
        RECT 1480.830 1498.000 1481.110 1500.000 ;
    END
  END tx_data[293]
  PIN tx_data[294]
    DIRECTION INPUT ;
    USE SIGNAL ;
    ANTENNAGATEAREA 0.247500 ;
    PORT
      LAYER met2 ;
        RECT 66.330 0.000 66.610 2.000 ;
    END
  END tx_data[294]
  PIN tx_data[295]
    DIRECTION INPUT ;
    USE SIGNAL ;
    ANTENNAGATEAREA 0.247500 ;
    PORT
      LAYER met2 ;
        RECT 941.250 0.000 941.530 2.000 ;
    END
  END tx_data[295]
  PIN tx_data[296]
    DIRECTION INPUT ;
    USE SIGNAL ;
    ANTENNAGATEAREA 0.990000 ;
    PORT
      LAYER met3 ;
        RECT 1498.000 1385.880 1500.000 1386.480 ;
    END
  END tx_data[296]
  PIN tx_data[297]
    DIRECTION INPUT ;
    USE SIGNAL ;
    ANTENNAGATEAREA 0.742500 ;
    PORT
      LAYER met2 ;
        RECT 1398.030 0.000 1398.310 2.000 ;
    END
  END tx_data[297]
  PIN tx_data[298]
    DIRECTION INPUT ;
    USE SIGNAL ;
    ANTENNAGATEAREA 0.852000 ;
    PORT
      LAYER met3 ;
        RECT 1498.000 1025.480 1500.000 1026.080 ;
    END
  END tx_data[298]
  PIN tx_data[299]
    DIRECTION INPUT ;
    USE SIGNAL ;
    ANTENNAGATEAREA 0.990000 ;
    PORT
      LAYER met2 ;
        RECT 822.570 1498.000 822.850 1500.000 ;
    END
  END tx_data[299]
  PIN tx_data[29]
    DIRECTION INPUT ;
    USE SIGNAL ;
    ANTENNAGATEAREA 0.247500 ;
    PORT
      LAYER met2 ;
        RECT 173.970 0.000 174.250 2.000 ;
    END
  END tx_data[29]
  PIN tx_data[2]
    DIRECTION INPUT ;
    USE SIGNAL ;
    ANTENNAGATEAREA 0.990000 ;
    PORT
      LAYER met3 ;
        RECT 1498.000 1481.080 1500.000 1481.680 ;
    END
  END tx_data[2]
  PIN tx_data[300]
    DIRECTION INPUT ;
    USE SIGNAL ;
    ANTENNAGATEAREA 0.852000 ;
    PORT
      LAYER met2 ;
        RECT 801.870 0.000 802.150 2.000 ;
    END
  END tx_data[300]
  PIN tx_data[301]
    DIRECTION INPUT ;
    USE SIGNAL ;
    ANTENNAGATEAREA 0.742500 ;
    PORT
      LAYER met3 ;
        RECT 1498.000 685.480 1500.000 686.080 ;
    END
  END tx_data[301]
  PIN tx_data[302]
    DIRECTION INPUT ;
    USE SIGNAL ;
    ANTENNAGATEAREA 0.990000 ;
    PORT
      LAYER met2 ;
        RECT 1388.370 0.000 1388.650 2.000 ;
    END
  END tx_data[302]
  PIN tx_data[303]
    DIRECTION INPUT ;
    USE SIGNAL ;
    ANTENNAGATEAREA 0.742500 ;
    PORT
      LAYER met2 ;
        RECT 652.830 0.000 653.110 2.000 ;
    END
  END tx_data[303]
  PIN tx_data[304]
    DIRECTION INPUT ;
    USE SIGNAL ;
    ANTENNAGATEAREA 0.852000 ;
    PORT
      LAYER met2 ;
        RECT 894.330 1498.000 894.610 1500.000 ;
    END
  END tx_data[304]
  PIN tx_data[305]
    DIRECTION INPUT ;
    USE SIGNAL ;
    ANTENNAGATEAREA 0.990000 ;
    PORT
      LAYER met2 ;
        RECT 1048.890 1498.000 1049.170 1500.000 ;
    END
  END tx_data[305]
  PIN tx_data[306]
    DIRECTION INPUT ;
    USE SIGNAL ;
    ANTENNAGATEAREA 0.495000 ;
    PORT
      LAYER met2 ;
        RECT 390.630 0.000 390.910 2.000 ;
    END
  END tx_data[306]
  PIN tx_data[307]
    DIRECTION INPUT ;
    USE SIGNAL ;
    ANTENNAGATEAREA 0.990000 ;
    PORT
      LAYER met2 ;
        RECT 961.950 1498.000 962.230 1500.000 ;
    END
  END tx_data[307]
  PIN tx_data[308]
    DIRECTION INPUT ;
    USE SIGNAL ;
    ANTENNAGATEAREA 0.247500 ;
    PORT
      LAYER met3 ;
        RECT 0.000 648.760 2.000 649.360 ;
    END
  END tx_data[308]
  PIN tx_data[309]
    DIRECTION INPUT ;
    USE SIGNAL ;
    ANTENNAGATEAREA 0.742500 ;
    PORT
      LAYER met3 ;
        RECT 1498.000 239.400 1500.000 240.000 ;
    END
  END tx_data[309]
  PIN tx_data[30]
    DIRECTION INPUT ;
    USE SIGNAL ;
    ANTENNAGATEAREA 0.990000 ;
    PORT
      LAYER met2 ;
        RECT 139.470 1498.000 139.750 1500.000 ;
    END
  END tx_data[30]
  PIN tx_data[310]
    DIRECTION INPUT ;
    USE SIGNAL ;
    ANTENNAGATEAREA 0.852000 ;
    PORT
      LAYER met2 ;
        RECT 215.370 1498.000 215.650 1500.000 ;
    END
  END tx_data[310]
  PIN tx_data[311]
    DIRECTION INPUT ;
    USE SIGNAL ;
    ANTENNAGATEAREA 0.852000 ;
    PORT
      LAYER met3 ;
        RECT 1498.000 1253.960 1500.000 1254.560 ;
    END
  END tx_data[311]
  PIN tx_data[312]
    DIRECTION INPUT ;
    USE SIGNAL ;
    ANTENNAGATEAREA 0.426000 ;
    PORT
      LAYER met3 ;
        RECT 1498.000 553.560 1500.000 554.160 ;
    END
  END tx_data[312]
  PIN tx_data[313]
    DIRECTION INPUT ;
    USE SIGNAL ;
    ANTENNAGATEAREA 0.742500 ;
    PORT
      LAYER met3 ;
        RECT 1498.000 112.920 1500.000 113.520 ;
    END
  END tx_data[313]
  PIN tx_data[314]
    DIRECTION INPUT ;
    USE SIGNAL ;
    ANTENNAGATEAREA 0.742500 ;
    PORT
      LAYER met2 ;
        RECT 988.170 1498.000 988.450 1500.000 ;
    END
  END tx_data[314]
  PIN tx_data[315]
    DIRECTION INPUT ;
    USE SIGNAL ;
    ANTENNAGATEAREA 0.852000 ;
    PORT
      LAYER met2 ;
        RECT 1311.090 1498.000 1311.370 1500.000 ;
    END
  END tx_data[315]
  PIN tx_data[316]
    DIRECTION INPUT ;
    USE SIGNAL ;
    ANTENNAGATEAREA 0.213000 ;
    PORT
      LAYER met3 ;
        RECT 0.000 582.120 2.000 582.720 ;
    END
  END tx_data[316]
  PIN tx_data[317]
    DIRECTION INPUT ;
    USE SIGNAL ;
    ANTENNAGATEAREA 0.247500 ;
    PORT
      LAYER met3 ;
        RECT 0.000 749.400 2.000 750.000 ;
    END
  END tx_data[317]
  PIN tx_data[318]
    DIRECTION INPUT ;
    USE SIGNAL ;
    ANTENNAGATEAREA 0.990000 ;
    PORT
      LAYER met3 ;
        RECT 1498.000 127.880 1500.000 128.480 ;
    END
  END tx_data[318]
  PIN tx_data[319]
    DIRECTION INPUT ;
    USE SIGNAL ;
    ANTENNAGATEAREA 0.990000 ;
    PORT
      LAYER met2 ;
        RECT 1152.390 1498.000 1152.670 1500.000 ;
    END
  END tx_data[319]
  PIN tx_data[31]
    DIRECTION INPUT ;
    USE SIGNAL ;
    ANTENNAGATEAREA 0.159000 ;
    PORT
      LAYER met2 ;
        RECT 354.750 0.000 355.030 2.000 ;
    END
  END tx_data[31]
  PIN tx_data[320]
    DIRECTION INPUT ;
    USE SIGNAL ;
    ANTENNAGATEAREA 0.990000 ;
    PORT
      LAYER met3 ;
        RECT 1498.000 1462.040 1500.000 1462.640 ;
    END
  END tx_data[320]
  PIN tx_data[321]
    DIRECTION INPUT ;
    USE SIGNAL ;
    ANTENNAGATEAREA 0.990000 ;
    PORT
      LAYER met3 ;
        RECT 1498.000 1116.600 1500.000 1117.200 ;
    END
  END tx_data[321]
  PIN tx_data[322]
    DIRECTION INPUT ;
    USE SIGNAL ;
    ANTENNAGATEAREA 0.495000 ;
    PORT
      LAYER met3 ;
        RECT 0.000 1022.760 2.000 1023.360 ;
    END
  END tx_data[322]
  PIN tx_data[323]
    DIRECTION INPUT ;
    USE SIGNAL ;
    ANTENNAGATEAREA 0.852000 ;
    PORT
      LAYER met3 ;
        RECT 1498.000 943.880 1500.000 944.480 ;
    END
  END tx_data[323]
  PIN tx_data[324]
    DIRECTION INPUT ;
    USE SIGNAL ;
    ANTENNAGATEAREA 0.990000 ;
    PORT
      LAYER met2 ;
        RECT 128.430 1498.000 128.710 1500.000 ;
    END
  END tx_data[324]
  PIN tx_data[325]
    DIRECTION INPUT ;
    USE SIGNAL ;
    ANTENNAGATEAREA 0.990000 ;
    PORT
      LAYER met3 ;
        RECT 1498.000 488.280 1500.000 488.880 ;
    END
  END tx_data[325]
  PIN tx_data[326]
    DIRECTION INPUT ;
    USE SIGNAL ;
    ANTENNAGATEAREA 0.247500 ;
    PORT
      LAYER met3 ;
        RECT 0.000 446.120 2.000 446.720 ;
    END
  END tx_data[326]
  PIN tx_data[327]
    DIRECTION INPUT ;
    USE SIGNAL ;
    ANTENNAGATEAREA 0.990000 ;
    PORT
      LAYER met3 ;
        RECT 1498.000 858.200 1500.000 858.800 ;
    END
  END tx_data[327]
  PIN tx_data[328]
    DIRECTION INPUT ;
    USE SIGNAL ;
    ANTENNAGATEAREA 0.247500 ;
    PORT
      LAYER met2 ;
        RECT 647.310 0.000 647.590 2.000 ;
    END
  END tx_data[328]
  PIN tx_data[329]
    DIRECTION INPUT ;
    USE SIGNAL ;
    ANTENNAGATEAREA 0.495000 ;
    PORT
      LAYER met3 ;
        RECT 0.000 1145.160 2.000 1145.760 ;
    END
  END tx_data[329]
  PIN tx_data[32]
    DIRECTION INPUT ;
    USE SIGNAL ;
    ANTENNAGATEAREA 0.247500 ;
    PORT
      LAYER met3 ;
        RECT 0.000 156.440 2.000 157.040 ;
    END
  END tx_data[32]
  PIN tx_data[330]
    DIRECTION INPUT ;
    USE SIGNAL ;
    ANTENNAGATEAREA 0.990000 ;
    PORT
      LAYER met3 ;
        RECT 1498.000 1330.120 1500.000 1330.720 ;
    END
  END tx_data[330]
  PIN tx_data[331]
    DIRECTION INPUT ;
    USE SIGNAL ;
    ANTENNAGATEAREA 0.990000 ;
    PORT
      LAYER met2 ;
        RECT 437.550 1498.000 437.830 1500.000 ;
    END
  END tx_data[331]
  PIN tx_data[332]
    DIRECTION INPUT ;
    USE SIGNAL ;
    ANTENNAGATEAREA 0.742500 ;
    PORT
      LAYER met3 ;
        RECT 0.000 729.000 2.000 729.600 ;
    END
  END tx_data[332]
  PIN tx_data[333]
    DIRECTION INPUT ;
    USE SIGNAL ;
    ANTENNAGATEAREA 0.495000 ;
    PORT
      LAYER met2 ;
        RECT 1254.510 0.000 1254.790 2.000 ;
    END
  END tx_data[333]
  PIN tx_data[334]
    DIRECTION INPUT ;
    USE SIGNAL ;
    ANTENNAGATEAREA 0.426000 ;
    PORT
      LAYER met2 ;
        RECT 149.130 0.000 149.410 2.000 ;
    END
  END tx_data[334]
  PIN tx_data[335]
    DIRECTION INPUT ;
    USE SIGNAL ;
    ANTENNAGATEAREA 0.247500 ;
    PORT
      LAYER met2 ;
        RECT 230.550 0.000 230.830 2.000 ;
    END
  END tx_data[335]
  PIN tx_data[336]
    DIRECTION INPUT ;
    USE SIGNAL ;
    ANTENNAGATEAREA 0.426000 ;
    PORT
      LAYER met3 ;
        RECT 1498.000 350.920 1500.000 351.520 ;
    END
  END tx_data[336]
  PIN tx_data[337]
    DIRECTION INPUT ;
    USE SIGNAL ;
    ANTENNAGATEAREA 0.990000 ;
    PORT
      LAYER met3 ;
        RECT 1498.000 761.640 1500.000 762.240 ;
    END
  END tx_data[337]
  PIN tx_data[338]
    DIRECTION INPUT ;
    USE SIGNAL ;
    ANTENNAGATEAREA 0.742500 ;
    PORT
      LAYER met3 ;
        RECT 0.000 1423.960 2.000 1424.560 ;
    END
  END tx_data[338]
  PIN tx_data[339]
    DIRECTION INPUT ;
    USE SIGNAL ;
    ANTENNAGATEAREA 0.852000 ;
    PORT
      LAYER met3 ;
        RECT 1498.000 1248.520 1500.000 1249.120 ;
    END
  END tx_data[339]
  PIN tx_data[33]
    DIRECTION INPUT ;
    USE SIGNAL ;
    ANTENNAGATEAREA 0.426000 ;
    PORT
      LAYER met2 ;
        RECT 1208.970 0.000 1209.250 2.000 ;
    END
  END tx_data[33]
  PIN tx_data[340]
    DIRECTION INPUT ;
    USE SIGNAL ;
    ANTENNAGATEAREA 0.247500 ;
    PORT
      LAYER met2 ;
        RECT 164.310 0.000 164.590 2.000 ;
    END
  END tx_data[340]
  PIN tx_data[341]
    DIRECTION INPUT ;
    USE SIGNAL ;
    ANTENNAGATEAREA 0.247500 ;
    PORT
      LAYER met3 ;
        RECT 0.000 258.440 2.000 259.040 ;
    END
  END tx_data[341]
  PIN tx_data[342]
    DIRECTION INPUT ;
    USE SIGNAL ;
    ANTENNAGATEAREA 0.852000 ;
    PORT
      LAYER met3 ;
        RECT 0.000 1256.680 2.000 1257.280 ;
    END
  END tx_data[342]
  PIN tx_data[343]
    DIRECTION INPUT ;
    USE SIGNAL ;
    ANTENNAGATEAREA 0.213000 ;
    PORT
      LAYER met2 ;
        RECT 673.530 0.000 673.810 2.000 ;
    END
  END tx_data[343]
  PIN tx_data[344]
    DIRECTION INPUT ;
    USE SIGNAL ;
    ANTENNAGATEAREA 0.742500 ;
    PORT
      LAYER met2 ;
        RECT 1373.190 0.000 1373.470 2.000 ;
    END
  END tx_data[344]
  PIN tx_data[345]
    DIRECTION INPUT ;
    USE SIGNAL ;
    ANTENNAGATEAREA 0.852000 ;
    PORT
      LAYER met3 ;
        RECT 0.000 1394.040 2.000 1394.640 ;
    END
  END tx_data[345]
  PIN tx_data[346]
    DIRECTION INPUT ;
    USE SIGNAL ;
    ANTENNAGATEAREA 0.990000 ;
    PORT
      LAYER met3 ;
        RECT 0.000 1327.400 2.000 1328.000 ;
    END
  END tx_data[346]
  PIN tx_data[347]
    DIRECTION INPUT ;
    USE SIGNAL ;
    ANTENNAGATEAREA 0.990000 ;
    PORT
      LAYER met2 ;
        RECT 1327.650 1498.000 1327.930 1500.000 ;
    END
  END tx_data[347]
  PIN tx_data[348]
    DIRECTION INPUT ;
    USE SIGNAL ;
    ANTENNAGATEAREA 0.742500 ;
    PORT
      LAYER met3 ;
        RECT 0.000 130.600 2.000 131.200 ;
    END
  END tx_data[348]
  PIN tx_data[349]
    DIRECTION INPUT ;
    USE SIGNAL ;
    ANTENNAGATEAREA 0.495000 ;
    PORT
      LAYER met2 ;
        RECT 1131.690 0.000 1131.970 2.000 ;
    END
  END tx_data[349]
  PIN tx_data[34]
    DIRECTION INPUT ;
    USE SIGNAL ;
    ANTENNAGATEAREA 0.742500 ;
    PORT
      LAYER met3 ;
        RECT 0.000 820.120 2.000 820.720 ;
    END
  END tx_data[34]
  PIN tx_data[350]
    DIRECTION INPUT ;
    USE SIGNAL ;
    ANTENNAGATEAREA 0.852000 ;
    PORT
      LAYER met2 ;
        RECT 1167.570 0.000 1167.850 2.000 ;
    END
  END tx_data[350]
  PIN tx_data[351]
    DIRECTION INPUT ;
    USE SIGNAL ;
    ANTENNAGATEAREA 0.495000 ;
    PORT
      LAYER met3 ;
        RECT 0.000 632.440 2.000 633.040 ;
    END
  END tx_data[351]
  PIN tx_data[352]
    DIRECTION INPUT ;
    USE SIGNAL ;
    ANTENNAGATEAREA 0.426000 ;
    PORT
      LAYER met2 ;
        RECT 298.170 0.000 298.450 2.000 ;
    END
  END tx_data[352]
  PIN tx_data[353]
    DIRECTION INPUT ;
    USE SIGNAL ;
    ANTENNAGATEAREA 0.495000 ;
    PORT
      LAYER met3 ;
        RECT 0.000 866.360 2.000 866.960 ;
    END
  END tx_data[353]
  PIN tx_data[354]
    DIRECTION INPUT ;
    USE SIGNAL ;
    ANTENNAGATEAREA 0.495000 ;
    PORT
      LAYER met3 ;
        RECT 1498.000 361.800 1500.000 362.400 ;
    END
  END tx_data[354]
  PIN tx_data[355]
    DIRECTION INPUT ;
    USE SIGNAL ;
    ANTENNAGATEAREA 0.852000 ;
    PORT
      LAYER met2 ;
        RECT 1265.550 1498.000 1265.830 1500.000 ;
    END
  END tx_data[355]
  PIN tx_data[356]
    DIRECTION INPUT ;
    USE SIGNAL ;
    ANTENNAGATEAREA 0.852000 ;
    PORT
      LAYER met3 ;
        RECT 1498.000 1071.720 1500.000 1072.320 ;
    END
  END tx_data[356]
  PIN tx_data[357]
    DIRECTION INPUT ;
    USE SIGNAL ;
    ANTENNAGATEAREA 0.742500 ;
    PORT
      LAYER met3 ;
        RECT 0.000 1312.440 2.000 1313.040 ;
    END
  END tx_data[357]
  PIN tx_data[358]
    DIRECTION INPUT ;
    USE SIGNAL ;
    ANTENNAGATEAREA 0.426000 ;
    PORT
      LAYER met3 ;
        RECT 0.000 455.640 2.000 456.240 ;
    END
  END tx_data[358]
  PIN tx_data[359]
    DIRECTION INPUT ;
    USE SIGNAL ;
    ANTENNAGATEAREA 0.852000 ;
    PORT
      LAYER met3 ;
        RECT 1498.000 1.400 1500.000 2.000 ;
    END
  END tx_data[359]
  PIN tx_data[35]
    DIRECTION INPUT ;
    USE SIGNAL ;
    ANTENNAGATEAREA 0.213000 ;
    PORT
      LAYER met2 ;
        RECT 781.170 0.000 781.450 2.000 ;
    END
  END tx_data[35]
  PIN tx_data[360]
    DIRECTION INPUT ;
    USE SIGNAL ;
    ANTENNAGATEAREA 0.990000 ;
    PORT
      LAYER met2 ;
        RECT 122.910 1498.000 123.190 1500.000 ;
    END
  END tx_data[360]
  PIN tx_data[361]
    DIRECTION INPUT ;
    USE SIGNAL ;
    ANTENNAGATEAREA 0.495000 ;
    PORT
      LAYER met2 ;
        RECT 1135.830 0.000 1136.110 2.000 ;
    END
  END tx_data[361]
  PIN tx_data[362]
    DIRECTION INPUT ;
    USE SIGNAL ;
    ANTENNAGATEAREA 0.426000 ;
    PORT
      LAYER met3 ;
        RECT 1498.000 72.120 1500.000 72.720 ;
    END
  END tx_data[362]
  PIN tx_data[363]
    DIRECTION INPUT ;
    USE SIGNAL ;
    ANTENNAGATEAREA 0.213000 ;
    PORT
      LAYER met2 ;
        RECT 1260.030 0.000 1260.310 2.000 ;
    END
  END tx_data[363]
  PIN tx_data[364]
    DIRECTION INPUT ;
    USE SIGNAL ;
    ANTENNAGATEAREA 0.213000 ;
    PORT
      LAYER met2 ;
        RECT 560.370 0.000 560.650 2.000 ;
    END
  END tx_data[364]
  PIN tx_data[365]
    DIRECTION INPUT ;
    USE SIGNAL ;
    ANTENNAGATEAREA 0.742500 ;
    PORT
      LAYER met3 ;
        RECT 0.000 825.560 2.000 826.160 ;
    END
  END tx_data[365]
  PIN tx_data[366]
    DIRECTION INPUT ;
    USE SIGNAL ;
    ANTENNAGATEAREA 0.247500 ;
    PORT
      LAYER met2 ;
        RECT 1037.850 0.000 1038.130 2.000 ;
    END
  END tx_data[366]
  PIN tx_data[367]
    DIRECTION INPUT ;
    USE SIGNAL ;
    ANTENNAGATEAREA 0.990000 ;
    PORT
      LAYER met3 ;
        RECT 1498.000 767.080 1500.000 767.680 ;
    END
  END tx_data[367]
  PIN tx_data[368]
    DIRECTION INPUT ;
    USE SIGNAL ;
    ANTENNAGATEAREA 0.742500 ;
    PORT
      LAYER met3 ;
        RECT 0.000 911.240 2.000 911.840 ;
    END
  END tx_data[368]
  PIN tx_data[369]
    DIRECTION INPUT ;
    USE SIGNAL ;
    ANTENNAGATEAREA 0.990000 ;
    PORT
      LAYER met3 ;
        RECT 1498.000 999.640 1500.000 1000.240 ;
    END
  END tx_data[369]
  PIN tx_data[36]
    DIRECTION INPUT ;
    USE SIGNAL ;
    ANTENNAGATEAREA 0.742500 ;
    PORT
      LAYER met3 ;
        RECT 1498.000 893.560 1500.000 894.160 ;
    END
  END tx_data[36]
  PIN tx_data[370]
    DIRECTION INPUT ;
    USE SIGNAL ;
    ANTENNAGATEAREA 0.213000 ;
    PORT
      LAYER met2 ;
        RECT 775.650 0.000 775.930 2.000 ;
    END
  END tx_data[370]
  PIN tx_data[371]
    DIRECTION INPUT ;
    USE SIGNAL ;
    ANTENNAGATEAREA 0.495000 ;
    PORT
      LAYER met2 ;
        RECT 30.450 0.000 30.730 2.000 ;
    END
  END tx_data[371]
  PIN tx_data[372]
    DIRECTION INPUT ;
    USE SIGNAL ;
    ANTENNAGATEAREA 0.852000 ;
    PORT
      LAYER met3 ;
        RECT 0.000 1154.680 2.000 1155.280 ;
    END
  END tx_data[372]
  PIN tx_data[373]
    DIRECTION INPUT ;
    USE SIGNAL ;
    ANTENNAGATEAREA 0.990000 ;
    PORT
      LAYER met2 ;
        RECT 447.210 1498.000 447.490 1500.000 ;
    END
  END tx_data[373]
  PIN tx_data[374]
    DIRECTION INPUT ;
    USE SIGNAL ;
    ANTENNAGATEAREA 0.742500 ;
    PORT
      LAYER met3 ;
        RECT 1498.000 168.680 1500.000 169.280 ;
    END
  END tx_data[374]
  PIN tx_data[375]
    DIRECTION INPUT ;
    USE SIGNAL ;
    ANTENNAGATEAREA 0.990000 ;
    PORT
      LAYER met2 ;
        RECT 637.650 1498.000 637.930 1500.000 ;
    END
  END tx_data[375]
  PIN tx_data[376]
    DIRECTION INPUT ;
    USE SIGNAL ;
    ANTENNAGATEAREA 0.742500 ;
    PORT
      LAYER met3 ;
        RECT 0.000 141.480 2.000 142.080 ;
    END
  END tx_data[376]
  PIN tx_data[377]
    DIRECTION INPUT ;
    USE SIGNAL ;
    ANTENNAGATEAREA 0.990000 ;
    PORT
      LAYER met3 ;
        RECT 0.000 1078.520 2.000 1079.120 ;
    END
  END tx_data[377]
  PIN tx_data[378]
    DIRECTION INPUT ;
    USE SIGNAL ;
    ANTENNAGATEAREA 0.852000 ;
    PORT
      LAYER met3 ;
        RECT 0.000 1160.120 2.000 1160.720 ;
    END
  END tx_data[378]
  PIN tx_data[379]
    DIRECTION INPUT ;
    USE SIGNAL ;
    ANTENNAGATEAREA 0.742500 ;
    PORT
      LAYER met2 ;
        RECT 1084.770 0.000 1085.050 2.000 ;
    END
  END tx_data[379]
  PIN tx_data[37]
    DIRECTION INPUT ;
    USE SIGNAL ;
    ANTENNAGATEAREA 0.852000 ;
    PORT
      LAYER met3 ;
        RECT 0.000 962.920 2.000 963.520 ;
    END
  END tx_data[37]
  PIN tx_data[380]
    DIRECTION INPUT ;
    USE SIGNAL ;
    ANTENNAGATEAREA 0.495000 ;
    PORT
      LAYER met3 ;
        RECT 0.000 253.000 2.000 253.600 ;
    END
  END tx_data[380]
  PIN tx_data[381]
    DIRECTION INPUT ;
    USE SIGNAL ;
    ANTENNAGATEAREA 0.990000 ;
    PORT
      LAYER met2 ;
        RECT 185.010 1498.000 185.290 1500.000 ;
    END
  END tx_data[381]
  PIN tx_data[382]
    DIRECTION INPUT ;
    USE SIGNAL ;
    ANTENNAGATEAREA 0.495000 ;
    PORT
      LAYER met3 ;
        RECT 1498.000 21.800 1500.000 22.400 ;
    END
  END tx_data[382]
  PIN tx_data[383]
    DIRECTION INPUT ;
    USE SIGNAL ;
    ANTENNAGATEAREA 0.426000 ;
    PORT
      LAYER met3 ;
        RECT 1498.000 204.040 1500.000 204.640 ;
    END
  END tx_data[383]
  PIN tx_data[384]
    DIRECTION INPUT ;
    USE SIGNAL ;
    ANTENNAGATEAREA 0.990000 ;
    PORT
      LAYER met2 ;
        RECT 220.890 1498.000 221.170 1500.000 ;
    END
  END tx_data[384]
  PIN tx_data[385]
    DIRECTION INPUT ;
    USE SIGNAL ;
    ANTENNAGATEAREA 0.247500 ;
    PORT
      LAYER met2 ;
        RECT 585.210 0.000 585.490 2.000 ;
    END
  END tx_data[385]
  PIN tx_data[386]
    DIRECTION INPUT ;
    USE SIGNAL ;
    ANTENNAGATEAREA 0.990000 ;
    PORT
      LAYER met2 ;
        RECT 643.170 1498.000 643.450 1500.000 ;
    END
  END tx_data[386]
  PIN tx_data[387]
    DIRECTION INPUT ;
    USE SIGNAL ;
    ANTENNAGATEAREA 0.495000 ;
    PORT
      LAYER met3 ;
        RECT 1498.000 57.160 1500.000 57.760 ;
    END
  END tx_data[387]
  PIN tx_data[388]
    DIRECTION INPUT ;
    USE SIGNAL ;
    ANTENNAGATEAREA 0.990000 ;
    PORT
      LAYER met3 ;
        RECT 1498.000 1081.240 1500.000 1081.840 ;
    END
  END tx_data[388]
  PIN tx_data[389]
    DIRECTION INPUT ;
    USE SIGNAL ;
    ANTENNAGATEAREA 0.990000 ;
    PORT
      LAYER met2 ;
        RECT 262.290 1498.000 262.570 1500.000 ;
    END
  END tx_data[389]
  PIN tx_data[38]
    DIRECTION INPUT ;
    USE SIGNAL ;
    ANTENNAGATEAREA 0.852000 ;
    PORT
      LAYER met3 ;
        RECT 0.000 1134.280 2.000 1134.880 ;
    END
  END tx_data[38]
  PIN tx_data[390]
    DIRECTION INPUT ;
    USE SIGNAL ;
    ANTENNAGATEAREA 0.990000 ;
    PORT
      LAYER met3 ;
        RECT 1498.000 503.240 1500.000 503.840 ;
    END
  END tx_data[390]
  PIN tx_data[391]
    DIRECTION INPUT ;
    USE SIGNAL ;
    ANTENNAGATEAREA 0.426000 ;
    PORT
      LAYER met2 ;
        RECT 899.850 0.000 900.130 2.000 ;
    END
  END tx_data[391]
  PIN tx_data[392]
    DIRECTION INPUT ;
    USE SIGNAL ;
    ANTENNAGATEAREA 0.247500 ;
    PORT
      LAYER met3 ;
        RECT 0.000 724.920 2.000 725.520 ;
    END
  END tx_data[392]
  PIN tx_data[393]
    DIRECTION INPUT ;
    USE SIGNAL ;
    ANTENNAGATEAREA 0.213000 ;
    PORT
      LAYER met3 ;
        RECT 0.000 314.200 2.000 314.800 ;
    END
  END tx_data[393]
  PIN tx_data[394]
    DIRECTION INPUT ;
    USE SIGNAL ;
    ANTENNAGATEAREA 0.990000 ;
    PORT
      LAYER met3 ;
        RECT 1498.000 700.440 1500.000 701.040 ;
    END
  END tx_data[394]
  PIN tx_data[395]
    DIRECTION INPUT ;
    USE SIGNAL ;
    ANTENNAGATEAREA 0.852000 ;
    PORT
      LAYER met2 ;
        RECT 288.510 1498.000 288.790 1500.000 ;
    END
  END tx_data[395]
  PIN tx_data[396]
    DIRECTION INPUT ;
    USE SIGNAL ;
    ANTENNAGATEAREA 0.213000 ;
    PORT
      LAYER met2 ;
        RECT 509.310 0.000 509.590 2.000 ;
    END
  END tx_data[396]
  PIN tx_data[397]
    DIRECTION INPUT ;
    USE SIGNAL ;
    ANTENNAGATEAREA 0.990000 ;
    PORT
      LAYER met2 ;
        RECT 1440.810 1498.000 1441.090 1500.000 ;
    END
  END tx_data[397]
  PIN tx_data[398]
    DIRECTION INPUT ;
    USE SIGNAL ;
    ANTENNAGATEAREA 0.247500 ;
    PORT
      LAYER met2 ;
        RECT 1439.430 0.000 1439.710 2.000 ;
    END
  END tx_data[398]
  PIN tx_data[399]
    DIRECTION INPUT ;
    USE SIGNAL ;
    ANTENNAGATEAREA 0.990000 ;
    PORT
      LAYER met2 ;
        RECT 581.070 1498.000 581.350 1500.000 ;
    END
  END tx_data[399]
  PIN tx_data[39]
    DIRECTION INPUT ;
    USE SIGNAL ;
    ANTENNAGATEAREA 0.990000 ;
    PORT
      LAYER met2 ;
        RECT 1471.170 1498.000 1471.450 1500.000 ;
    END
  END tx_data[39]
  PIN tx_data[3]
    DIRECTION INPUT ;
    USE SIGNAL ;
    ANTENNAGATEAREA 0.852000 ;
    PORT
      LAYER met3 ;
        RECT 0.000 1474.280 2.000 1474.880 ;
    END
  END tx_data[3]
  PIN tx_data[400]
    DIRECTION INPUT ;
    USE SIGNAL ;
    ANTENNAGATEAREA 0.852000 ;
    PORT
      LAYER met2 ;
        RECT 211.230 1498.000 211.510 1500.000 ;
    END
  END tx_data[400]
  PIN tx_data[401]
    DIRECTION INPUT ;
    USE SIGNAL ;
    ANTENNAGATEAREA 0.742500 ;
    PORT
      LAYER met2 ;
        RECT 786.690 0.000 786.970 2.000 ;
    END
  END tx_data[401]
  PIN tx_data[402]
    DIRECTION INPUT ;
    USE SIGNAL ;
    ANTENNAGATEAREA 0.990000 ;
    PORT
      LAYER met3 ;
        RECT 0.000 799.720 2.000 800.320 ;
    END
  END tx_data[402]
  PIN tx_data[403]
    DIRECTION INPUT ;
    USE SIGNAL ;
    ANTENNAGATEAREA 0.742500 ;
    PORT
      LAYER met2 ;
        RECT 1418.730 0.000 1419.010 2.000 ;
    END
  END tx_data[403]
  PIN tx_data[404]
    DIRECTION INPUT ;
    USE SIGNAL ;
    ANTENNAGATEAREA 0.742500 ;
    PORT
      LAYER met3 ;
        RECT 1498.000 1421.240 1500.000 1421.840 ;
    END
  END tx_data[404]
  PIN tx_data[405]
    DIRECTION INPUT ;
    USE SIGNAL ;
    ANTENNAGATEAREA 0.742500 ;
    PORT
      LAYER met2 ;
        RECT 375.450 0.000 375.730 2.000 ;
    END
  END tx_data[405]
  PIN tx_data[406]
    DIRECTION INPUT ;
    USE SIGNAL ;
    ANTENNAGATEAREA 0.990000 ;
    PORT
      LAYER met3 ;
        RECT 0.000 1377.720 2.000 1378.320 ;
    END
  END tx_data[406]
  PIN tx_data[407]
    DIRECTION INPUT ;
    USE SIGNAL ;
    ANTENNAGATEAREA 0.990000 ;
    PORT
      LAYER met2 ;
        RECT 1126.170 0.000 1126.450 2.000 ;
    END
  END tx_data[407]
  PIN tx_data[408]
    DIRECTION INPUT ;
    USE SIGNAL ;
    ANTENNAGATEAREA 0.742500 ;
    PORT
      LAYER met2 ;
        RECT 997.830 0.000 998.110 2.000 ;
    END
  END tx_data[408]
  PIN tx_data[409]
    DIRECTION INPUT ;
    USE SIGNAL ;
    ANTENNAGATEAREA 0.742500 ;
    PORT
      LAYER met2 ;
        RECT 786.690 1498.000 786.970 1500.000 ;
    END
  END tx_data[409]
  PIN tx_data[40]
    DIRECTION INPUT ;
    USE SIGNAL ;
    ANTENNAGATEAREA 0.247500 ;
    PORT
      LAYER met3 ;
        RECT 0.000 50.360 2.000 50.960 ;
    END
  END tx_data[40]
  PIN tx_data[410]
    DIRECTION INPUT ;
    USE SIGNAL ;
    ANTENNAGATEAREA 0.247500 ;
    PORT
      LAYER met3 ;
        RECT 1498.000 523.640 1500.000 524.240 ;
    END
  END tx_data[410]
  PIN tx_data[411]
    DIRECTION INPUT ;
    USE SIGNAL ;
    ANTENNAGATEAREA 0.742500 ;
    PORT
      LAYER met3 ;
        RECT 1498.000 1471.560 1500.000 1472.160 ;
    END
  END tx_data[411]
  PIN tx_data[412]
    DIRECTION INPUT ;
    USE SIGNAL ;
    ANTENNAGATEAREA 0.247500 ;
    PORT
      LAYER met2 ;
        RECT 1233.810 0.000 1234.090 2.000 ;
    END
  END tx_data[412]
  PIN tx_data[413]
    DIRECTION INPUT ;
    USE SIGNAL ;
    ANTENNAGATEAREA 0.159000 ;
    PORT
      LAYER met2 ;
        RECT 688.710 0.000 688.990 2.000 ;
    END
  END tx_data[413]
  PIN tx_data[414]
    DIRECTION INPUT ;
    USE SIGNAL ;
    ANTENNAGATEAREA 0.990000 ;
    PORT
      LAYER met2 ;
        RECT 9.750 1498.000 10.030 1500.000 ;
    END
  END tx_data[414]
  PIN tx_data[415]
    DIRECTION INPUT ;
    USE SIGNAL ;
    ANTENNAGATEAREA 0.742500 ;
    PORT
      LAYER met2 ;
        RECT 1059.930 1498.000 1060.210 1500.000 ;
    END
  END tx_data[415]
  PIN tx_data[416]
    DIRECTION INPUT ;
    USE SIGNAL ;
    ANTENNAGATEAREA 0.742500 ;
    PORT
      LAYER met3 ;
        RECT 1498.000 1015.960 1500.000 1016.560 ;
    END
  END tx_data[416]
  PIN tx_data[417]
    DIRECTION INPUT ;
    USE SIGNAL ;
    ANTENNAGATEAREA 0.852000 ;
    PORT
      LAYER met3 ;
        RECT 1498.000 1289.320 1500.000 1289.920 ;
    END
  END tx_data[417]
  PIN tx_data[418]
    DIRECTION INPUT ;
    USE SIGNAL ;
    ANTENNAGATEAREA 0.495000 ;
    PORT
      LAYER met3 ;
        RECT 1498.000 66.680 1500.000 67.280 ;
    END
  END tx_data[418]
  PIN tx_data[419]
    DIRECTION INPUT ;
    USE SIGNAL ;
    ANTENNAGATEAREA 0.495000 ;
    PORT
      LAYER met3 ;
        RECT 1498.000 863.640 1500.000 864.240 ;
    END
  END tx_data[419]
  PIN tx_data[41]
    DIRECTION INPUT ;
    USE SIGNAL ;
    ANTENNAGATEAREA 0.742500 ;
    PORT
      LAYER met3 ;
        RECT 0.000 780.680 2.000 781.280 ;
    END
  END tx_data[41]
  PIN tx_data[420]
    DIRECTION INPUT ;
    USE SIGNAL ;
    ANTENNAGATEAREA 0.990000 ;
    PORT
      LAYER met2 ;
        RECT 35.970 1498.000 36.250 1500.000 ;
    END
  END tx_data[420]
  PIN tx_data[421]
    DIRECTION INPUT ;
    USE SIGNAL ;
    ANTENNAGATEAREA 0.426000 ;
    PORT
      LAYER met2 ;
        RECT 153.270 0.000 153.550 2.000 ;
    END
  END tx_data[421]
  PIN tx_data[422]
    DIRECTION INPUT ;
    USE SIGNAL ;
    ANTENNAGATEAREA 0.196500 ;
    PORT
      LAYER met2 ;
        RECT 1007.490 0.000 1007.770 2.000 ;
    END
  END tx_data[422]
  PIN tx_data[423]
    DIRECTION INPUT ;
    USE SIGNAL ;
    ANTENNAGATEAREA 0.159000 ;
    PORT
      LAYER met2 ;
        RECT 539.670 0.000 539.950 2.000 ;
    END
  END tx_data[423]
  PIN tx_data[424]
    DIRECTION INPUT ;
    USE SIGNAL ;
    ANTENNAGATEAREA 0.495000 ;
    PORT
      LAYER met3 ;
        RECT 0.000 273.400 2.000 274.000 ;
    END
  END tx_data[424]
  PIN tx_data[425]
    DIRECTION INPUT ;
    USE SIGNAL ;
    ANTENNAGATEAREA 0.247500 ;
    PORT
      LAYER met2 ;
        RECT 122.910 0.000 123.190 2.000 ;
    END
  END tx_data[425]
  PIN tx_data[426]
    DIRECTION INPUT ;
    USE SIGNAL ;
    ANTENNAGATEAREA 0.213000 ;
    PORT
      LAYER met2 ;
        RECT 554.850 0.000 555.130 2.000 ;
    END
  END tx_data[426]
  PIN tx_data[427]
    DIRECTION INPUT ;
    USE SIGNAL ;
    ANTENNAGATEAREA 0.742500 ;
    PORT
      LAYER met3 ;
        RECT 1498.000 644.680 1500.000 645.280 ;
    END
  END tx_data[427]
  PIN tx_data[428]
    DIRECTION INPUT ;
    USE SIGNAL ;
    ANTENNAGATEAREA 0.852000 ;
    PORT
      LAYER met3 ;
        RECT 0.000 39.480 2.000 40.080 ;
    END
  END tx_data[428]
  PIN tx_data[429]
    DIRECTION INPUT ;
    USE SIGNAL ;
    ANTENNAGATEAREA 0.742500 ;
    PORT
      LAYER met3 ;
        RECT 0.000 247.560 2.000 248.160 ;
    END
  END tx_data[429]
  PIN tx_data[42]
    DIRECTION INPUT ;
    USE SIGNAL ;
    ANTENNAGATEAREA 0.213000 ;
    PORT
      LAYER met2 ;
        RECT 200.190 0.000 200.470 2.000 ;
    END
  END tx_data[42]
  PIN tx_data[430]
    DIRECTION INPUT ;
    USE SIGNAL ;
    ANTENNAGATEAREA 0.426000 ;
    PORT
      LAYER met3 ;
        RECT 1498.000 984.680 1500.000 985.280 ;
    END
  END tx_data[430]
  PIN tx_data[431]
    DIRECTION INPUT ;
    USE SIGNAL ;
    ANTENNAGATEAREA 0.742500 ;
    PORT
      LAYER met2 ;
        RECT 1295.910 0.000 1296.190 2.000 ;
    END
  END tx_data[431]
  PIN tx_data[432]
    DIRECTION INPUT ;
    USE SIGNAL ;
    ANTENNAGATEAREA 0.852000 ;
    PORT
      LAYER met2 ;
        RECT 611.430 1498.000 611.710 1500.000 ;
    END
  END tx_data[432]
  PIN tx_data[433]
    DIRECTION INPUT ;
    USE SIGNAL ;
    ANTENNAGATEAREA 0.742500 ;
    PORT
      LAYER met2 ;
        RECT 1197.930 0.000 1198.210 2.000 ;
    END
  END tx_data[433]
  PIN tx_data[434]
    DIRECTION INPUT ;
    USE SIGNAL ;
    ANTENNAGATEAREA 0.495000 ;
    PORT
      LAYER met3 ;
        RECT 1498.000 1334.200 1500.000 1334.800 ;
    END
  END tx_data[434]
  PIN tx_data[435]
    DIRECTION INPUT ;
    USE SIGNAL ;
    ANTENNAGATEAREA 0.742500 ;
    PORT
      LAYER met2 ;
        RECT 848.790 1498.000 849.070 1500.000 ;
    END
  END tx_data[435]
  PIN tx_data[436]
    DIRECTION INPUT ;
    USE SIGNAL ;
    ANTENNAGATEAREA 0.742500 ;
    PORT
      LAYER met2 ;
        RECT 648.690 1498.000 648.970 1500.000 ;
    END
  END tx_data[436]
  PIN tx_data[437]
    DIRECTION INPUT ;
    USE SIGNAL ;
    ANTENNAGATEAREA 0.990000 ;
    PORT
      LAYER met2 ;
        RECT 190.530 1498.000 190.810 1500.000 ;
    END
  END tx_data[437]
  PIN tx_data[438]
    DIRECTION INPUT ;
    USE SIGNAL ;
    ANTENNAGATEAREA 0.742500 ;
    PORT
      LAYER met2 ;
        RECT 879.150 1498.000 879.430 1500.000 ;
    END
  END tx_data[438]
  PIN tx_data[439]
    DIRECTION INPUT ;
    USE SIGNAL ;
    ANTENNAGATEAREA 0.990000 ;
    PORT
      LAYER met3 ;
        RECT 0.000 1063.560 2.000 1064.160 ;
    END
  END tx_data[439]
  PIN tx_data[43]
    DIRECTION INPUT ;
    USE SIGNAL ;
    ANTENNAGATEAREA 0.196500 ;
    PORT
      LAYER met2 ;
        RECT 605.910 0.000 606.190 2.000 ;
    END
  END tx_data[43]
  PIN tx_data[440]
    DIRECTION INPUT ;
    USE SIGNAL ;
    ANTENNAGATEAREA 0.247500 ;
    PORT
      LAYER met3 ;
        RECT 1498.000 452.920 1500.000 453.520 ;
    END
  END tx_data[440]
  PIN tx_data[441]
    DIRECTION INPUT ;
    USE SIGNAL ;
    ANTENNAGATEAREA 0.247500 ;
    PORT
      LAYER met3 ;
        RECT 1498.000 904.440 1500.000 905.040 ;
    END
  END tx_data[441]
  PIN tx_data[442]
    DIRECTION INPUT ;
    USE SIGNAL ;
    ANTENNAGATEAREA 0.742500 ;
    PORT
      LAYER met3 ;
        RECT 1498.000 1360.040 1500.000 1360.640 ;
    END
  END tx_data[442]
  PIN tx_data[443]
    DIRECTION INPUT ;
    USE SIGNAL ;
    ANTENNAGATEAREA 0.990000 ;
    PORT
      LAYER met3 ;
        RECT 0.000 1464.760 2.000 1465.360 ;
    END
  END tx_data[443]
  PIN tx_data[444]
    DIRECTION INPUT ;
    USE SIGNAL ;
    ANTENNAGATEAREA 0.213000 ;
    PORT
      LAYER met2 ;
        RECT 1409.070 0.000 1409.350 2.000 ;
    END
  END tx_data[444]
  PIN tx_data[445]
    DIRECTION INPUT ;
    USE SIGNAL ;
    ANTENNAGATEAREA 0.990000 ;
    PORT
      LAYER met2 ;
        RECT 1239.330 1498.000 1239.610 1500.000 ;
    END
  END tx_data[445]
  PIN tx_data[446]
    DIRECTION INPUT ;
    USE SIGNAL ;
    ANTENNAGATEAREA 0.990000 ;
    PORT
      LAYER met2 ;
        RECT 1476.690 1498.000 1476.970 1500.000 ;
    END
  END tx_data[446]
  PIN tx_data[447]
    DIRECTION INPUT ;
    USE SIGNAL ;
    ANTENNAGATEAREA 0.990000 ;
    PORT
      LAYER met2 ;
        RECT 761.850 1498.000 762.130 1500.000 ;
    END
  END tx_data[447]
  PIN tx_data[448]
    DIRECTION INPUT ;
    USE SIGNAL ;
    ANTENNAGATEAREA 0.990000 ;
    PORT
      LAYER met2 ;
        RECT 1084.770 1498.000 1085.050 1500.000 ;
    END
  END tx_data[448]
  PIN tx_data[449]
    DIRECTION INPUT ;
    USE SIGNAL ;
    ANTENNAGATEAREA 0.213000 ;
    PORT
      LAYER met3 ;
        RECT 1498.000 174.120 1500.000 174.720 ;
    END
  END tx_data[449]
  PIN tx_data[44]
    DIRECTION INPUT ;
    USE SIGNAL ;
    ANTENNAGATEAREA 0.990000 ;
    PORT
      LAYER met2 ;
        RECT 1065.450 1498.000 1065.730 1500.000 ;
    END
  END tx_data[44]
  PIN tx_data[450]
    DIRECTION INPUT ;
    USE SIGNAL ;
    ANTENNAGATEAREA 0.426000 ;
    PORT
      LAYER met3 ;
        RECT 1498.000 107.480 1500.000 108.080 ;
    END
  END tx_data[450]
  PIN tx_data[451]
    DIRECTION INPUT ;
    USE SIGNAL ;
    ANTENNAGATEAREA 0.247500 ;
    PORT
      LAYER met3 ;
        RECT 1498.000 412.120 1500.000 412.720 ;
    END
  END tx_data[451]
  PIN tx_data[452]
    DIRECTION INPUT ;
    USE SIGNAL ;
    ANTENNAGATEAREA 0.247500 ;
    PORT
      LAYER met2 ;
        RECT 328.530 0.000 328.810 2.000 ;
    END
  END tx_data[452]
  PIN tx_data[453]
    DIRECTION INPUT ;
    USE SIGNAL ;
    ANTENNAGATEAREA 0.213000 ;
    PORT
      LAYER met2 ;
        RECT 492.750 0.000 493.030 2.000 ;
    END
  END tx_data[453]
  PIN tx_data[454]
    DIRECTION INPUT ;
    USE SIGNAL ;
    ANTENNAGATEAREA 0.247500 ;
    PORT
      LAYER met3 ;
        RECT 1498.000 214.920 1500.000 215.520 ;
    END
  END tx_data[454]
  PIN tx_data[455]
    DIRECTION INPUT ;
    USE SIGNAL ;
    ANTENNAGATEAREA 0.742500 ;
    PORT
      LAYER met3 ;
        RECT 1498.000 822.840 1500.000 823.440 ;
    END
  END tx_data[455]
  PIN tx_data[456]
    DIRECTION INPUT ;
    USE SIGNAL ;
    ANTENNAGATEAREA 0.852000 ;
    PORT
      LAYER met2 ;
        RECT 1275.210 1498.000 1275.490 1500.000 ;
    END
  END tx_data[456]
  PIN tx_data[457]
    DIRECTION INPUT ;
    USE SIGNAL ;
    ANTENNAGATEAREA 0.990000 ;
    PORT
      LAYER met2 ;
        RECT 92.550 1498.000 92.830 1500.000 ;
    END
  END tx_data[457]
  PIN tx_data[458]
    DIRECTION INPUT ;
    USE SIGNAL ;
    ANTENNAGATEAREA 0.990000 ;
    PORT
      LAYER met2 ;
        RECT 15.270 1498.000 15.550 1500.000 ;
    END
  END tx_data[458]
  PIN tx_data[459]
    DIRECTION INPUT ;
    USE SIGNAL ;
    ANTENNAGATEAREA 0.852000 ;
    PORT
      LAYER met3 ;
        RECT 0.000 1247.160 2.000 1247.760 ;
    END
  END tx_data[459]
  PIN tx_data[45]
    DIRECTION INPUT ;
    USE SIGNAL ;
    ANTENNAGATEAREA 0.213000 ;
    PORT
      LAYER met2 ;
        RECT 601.770 0.000 602.050 2.000 ;
    END
  END tx_data[45]
  PIN tx_data[460]
    DIRECTION INPUT ;
    USE SIGNAL ;
    ANTENNAGATEAREA 0.426000 ;
    PORT
      LAYER met3 ;
        RECT 0.000 115.640 2.000 116.240 ;
    END
  END tx_data[460]
  PIN tx_data[461]
    DIRECTION INPUT ;
    USE SIGNAL ;
    ANTENNAGATEAREA 0.990000 ;
    PORT
      LAYER met3 ;
        RECT 1498.000 371.320 1500.000 371.920 ;
    END
  END tx_data[461]
  PIN tx_data[462]
    DIRECTION INPUT ;
    USE SIGNAL ;
    ANTENNAGATEAREA 0.742500 ;
    PORT
      LAYER met3 ;
        RECT 0.000 1171.000 2.000 1171.600 ;
    END
  END tx_data[462]
  PIN tx_data[463]
    DIRECTION INPUT ;
    USE SIGNAL ;
    ANTENNAGATEAREA 0.213000 ;
    PORT
      LAYER met2 ;
        RECT 385.110 0.000 385.390 2.000 ;
    END
  END tx_data[463]
  PIN tx_data[464]
    DIRECTION INPUT ;
    USE SIGNAL ;
    ANTENNAGATEAREA 0.742500 ;
    PORT
      LAYER met2 ;
        RECT 1337.310 1498.000 1337.590 1500.000 ;
    END
  END tx_data[464]
  PIN tx_data[465]
    DIRECTION INPUT ;
    USE SIGNAL ;
    ANTENNAGATEAREA 0.990000 ;
    PORT
      LAYER met2 ;
        RECT 462.390 1498.000 462.670 1500.000 ;
    END
  END tx_data[465]
  PIN tx_data[466]
    DIRECTION INPUT ;
    USE SIGNAL ;
    ANTENNAGATEAREA 0.852000 ;
    PORT
      LAYER met2 ;
        RECT 360.270 1498.000 360.550 1500.000 ;
    END
  END tx_data[466]
  PIN tx_data[467]
    DIRECTION INPUT ;
    USE SIGNAL ;
    ANTENNAGATEAREA 0.990000 ;
    PORT
      LAYER met2 ;
        RECT 679.050 1498.000 679.330 1500.000 ;
    END
  END tx_data[467]
  PIN tx_data[468]
    DIRECTION INPUT ;
    USE SIGNAL ;
    ANTENNAGATEAREA 0.990000 ;
    PORT
      LAYER met2 ;
        RECT 771.510 1498.000 771.790 1500.000 ;
    END
  END tx_data[468]
  PIN tx_data[469]
    DIRECTION INPUT ;
    USE SIGNAL ;
    ANTENNAGATEAREA 0.990000 ;
    PORT
      LAYER met2 ;
        RECT 792.210 1498.000 792.490 1500.000 ;
    END
  END tx_data[469]
  PIN tx_data[46]
    DIRECTION INPUT ;
    USE SIGNAL ;
    ANTENNAGATEAREA 0.247500 ;
    PORT
      LAYER met2 ;
        RECT 1048.890 0.000 1049.170 2.000 ;
    END
  END tx_data[46]
  PIN tx_data[470]
    DIRECTION INPUT ;
    USE SIGNAL ;
    ANTENNAGATEAREA 0.990000 ;
    PORT
      LAYER met2 ;
        RECT 205.710 1498.000 205.990 1500.000 ;
    END
  END tx_data[470]
  PIN tx_data[471]
    DIRECTION INPUT ;
    USE SIGNAL ;
    ANTENNAGATEAREA 0.247500 ;
    PORT
      LAYER met3 ;
        RECT 0.000 334.600 2.000 335.200 ;
    END
  END tx_data[471]
  PIN tx_data[472]
    DIRECTION INPUT ;
    USE SIGNAL ;
    ANTENNAGATEAREA 0.426000 ;
    PORT
      LAYER met2 ;
        RECT 24.930 0.000 25.210 2.000 ;
    END
  END tx_data[472]
  PIN tx_data[473]
    DIRECTION INPUT ;
    USE SIGNAL ;
    ANTENNAGATEAREA 0.247500 ;
    PORT
      LAYER met3 ;
        RECT 1498.000 51.720 1500.000 52.320 ;
    END
  END tx_data[473]
  PIN tx_data[474]
    DIRECTION INPUT ;
    USE SIGNAL ;
    ANTENNAGATEAREA 0.213000 ;
    PORT
      LAYER met2 ;
        RECT 1054.410 0.000 1054.690 2.000 ;
    END
  END tx_data[474]
  PIN tx_data[475]
    DIRECTION INPUT ;
    USE SIGNAL ;
    ANTENNAGATEAREA 0.159000 ;
    PORT
      LAYER met3 ;
        RECT 1498.000 588.920 1500.000 589.520 ;
    END
  END tx_data[475]
  PIN tx_data[476]
    DIRECTION INPUT ;
    USE SIGNAL ;
    ANTENNAGATEAREA 0.990000 ;
    PORT
      LAYER met2 ;
        RECT 411.330 1498.000 411.610 1500.000 ;
    END
  END tx_data[476]
  PIN tx_data[477]
    DIRECTION INPUT ;
    USE SIGNAL ;
    ANTENNAGATEAREA 0.426000 ;
    PORT
      LAYER met3 ;
        RECT 1498.000 741.240 1500.000 741.840 ;
    END
  END tx_data[477]
  PIN tx_data[478]
    DIRECTION INPUT ;
    USE SIGNAL ;
    ANTENNAGATEAREA 0.426000 ;
    PORT
      LAYER met3 ;
        RECT 0.000 769.800 2.000 770.400 ;
    END
  END tx_data[478]
  PIN tx_data[479]
    DIRECTION INPUT ;
    USE SIGNAL ;
    ANTENNAGATEAREA 0.852000 ;
    PORT
      LAYER met2 ;
        RECT 81.510 0.000 81.790 2.000 ;
    END
  END tx_data[479]
  PIN tx_data[47]
    DIRECTION INPUT ;
    USE SIGNAL ;
    ANTENNAGATEAREA 0.159000 ;
    PORT
      LAYER met2 ;
        RECT 396.150 0.000 396.430 2.000 ;
    END
  END tx_data[47]
  PIN tx_data[480]
    DIRECTION INPUT ;
    USE SIGNAL ;
    ANTENNAGATEAREA 0.742500 ;
    PORT
      LAYER met2 ;
        RECT 879.150 0.000 879.430 2.000 ;
    END
  END tx_data[480]
  PIN tx_data[481]
    DIRECTION INPUT ;
    USE SIGNAL ;
    ANTENNAGATEAREA 0.990000 ;
    PORT
      LAYER met2 ;
        RECT 226.410 1498.000 226.690 1500.000 ;
    END
  END tx_data[481]
  PIN tx_data[482]
    DIRECTION INPUT ;
    USE SIGNAL ;
    ANTENNAGATEAREA 0.426000 ;
    PORT
      LAYER met3 ;
        RECT 1498.000 83.000 1500.000 83.600 ;
    END
  END tx_data[482]
  PIN tx_data[483]
    DIRECTION INPUT ;
    USE SIGNAL ;
    ANTENNAGATEAREA 0.742500 ;
    PORT
      LAYER met2 ;
        RECT 750.810 0.000 751.090 2.000 ;
    END
  END tx_data[483]
  PIN tx_data[484]
    DIRECTION INPUT ;
    USE SIGNAL ;
    ANTENNAGATEAREA 0.742500 ;
    PORT
      LAYER met2 ;
        RECT 1480.830 0.000 1481.110 2.000 ;
    END
  END tx_data[484]
  PIN tx_data[485]
    DIRECTION INPUT ;
    USE SIGNAL ;
    ANTENNAGATEAREA 0.742500 ;
    PORT
      LAYER met3 ;
        RECT 0.000 628.360 2.000 628.960 ;
    END
  END tx_data[485]
  PIN tx_data[486]
    DIRECTION INPUT ;
    USE SIGNAL ;
    ANTENNAGATEAREA 0.742500 ;
    PORT
      LAYER met2 ;
        RECT 1260.030 1498.000 1260.310 1500.000 ;
    END
  END tx_data[486]
  PIN tx_data[487]
    DIRECTION INPUT ;
    USE SIGNAL ;
    ANTENNAGATEAREA 0.742500 ;
    PORT
      LAYER met3 ;
        RECT 1498.000 10.920 1500.000 11.520 ;
    END
  END tx_data[487]
  PIN tx_data[488]
    DIRECTION INPUT ;
    USE SIGNAL ;
    ANTENNAGATEAREA 0.742500 ;
    PORT
      LAYER met3 ;
        RECT 0.000 831.000 2.000 831.600 ;
    END
  END tx_data[488]
  PIN tx_data[489]
    DIRECTION INPUT ;
    USE SIGNAL ;
    ANTENNAGATEAREA 0.495000 ;
    PORT
      LAYER met3 ;
        RECT 1498.000 417.560 1500.000 418.160 ;
    END
  END tx_data[489]
  PIN tx_data[48]
    DIRECTION INPUT ;
    USE SIGNAL ;
    ANTENNAGATEAREA 0.852000 ;
    PORT
      LAYER met2 ;
        RECT 1352.490 1498.000 1352.770 1500.000 ;
    END
  END tx_data[48]
  PIN tx_data[490]
    DIRECTION INPUT ;
    USE SIGNAL ;
    ANTENNAGATEAREA 0.990000 ;
    PORT
      LAYER met2 ;
        RECT 41.490 1498.000 41.770 1500.000 ;
    END
  END tx_data[490]
  PIN tx_data[491]
    DIRECTION INPUT ;
    USE SIGNAL ;
    ANTENNAGATEAREA 0.852000 ;
    PORT
      LAYER met3 ;
        RECT 1498.000 1395.400 1500.000 1396.000 ;
    END
  END tx_data[491]
  PIN tx_data[492]
    DIRECTION INPUT ;
    USE SIGNAL ;
    ANTENNAGATEAREA 0.495000 ;
    PORT
      LAYER met2 ;
        RECT 1465.650 0.000 1465.930 2.000 ;
    END
  END tx_data[492]
  PIN tx_data[493]
    DIRECTION INPUT ;
    USE SIGNAL ;
    ANTENNAGATEAREA 0.852000 ;
    PORT
      LAYER met2 ;
        RECT 473.430 1498.000 473.710 1500.000 ;
    END
  END tx_data[493]
  PIN tx_data[494]
    DIRECTION INPUT ;
    USE SIGNAL ;
    ANTENNAGATEAREA 0.213000 ;
    PORT
      LAYER met3 ;
        RECT 1498.000 599.800 1500.000 600.400 ;
    END
  END tx_data[494]
  PIN tx_data[495]
    DIRECTION INPUT ;
    USE SIGNAL ;
    ANTENNAGATEAREA 0.990000 ;
    PORT
      LAYER met3 ;
        RECT 0.000 1438.920 2.000 1439.520 ;
    END
  END tx_data[495]
  PIN tx_data[496]
    DIRECTION INPUT ;
    USE SIGNAL ;
    ANTENNAGATEAREA 0.247500 ;
    PORT
      LAYER met3 ;
        RECT 1498.000 259.800 1500.000 260.400 ;
    END
  END tx_data[496]
  PIN tx_data[497]
    DIRECTION INPUT ;
    USE SIGNAL ;
    ANTENNAGATEAREA 0.990000 ;
    PORT
      LAYER met3 ;
        RECT 0.000 805.160 2.000 805.760 ;
    END
  END tx_data[497]
  PIN tx_data[498]
    DIRECTION INPUT ;
    USE SIGNAL ;
    ANTENNAGATEAREA 0.852000 ;
    PORT
      LAYER met2 ;
        RECT 241.590 0.000 241.870 2.000 ;
    END
  END tx_data[498]
  PIN tx_data[499]
    DIRECTION INPUT ;
    USE SIGNAL ;
    ANTENNAGATEAREA 0.852000 ;
    PORT
      LAYER met3 ;
        RECT 1498.000 1319.240 1500.000 1319.840 ;
    END
  END tx_data[499]
  PIN tx_data[49]
    DIRECTION INPUT ;
    USE SIGNAL ;
    ANTENNAGATEAREA 0.159000 ;
    PORT
      LAYER met2 ;
        RECT 1064.070 0.000 1064.350 2.000 ;
    END
  END tx_data[49]
  PIN tx_data[4]
    DIRECTION INPUT ;
    USE SIGNAL ;
    ANTENNAGATEAREA 0.990000 ;
    PORT
      LAYER met2 ;
        RECT 1409.070 1498.000 1409.350 1500.000 ;
    END
  END tx_data[4]
  PIN tx_data[500]
    DIRECTION INPUT ;
    USE SIGNAL ;
    ANTENNAGATEAREA 0.990000 ;
    PORT
      LAYER met2 ;
        RECT 483.090 0.000 483.370 2.000 ;
    END
  END tx_data[500]
  PIN tx_data[501]
    DIRECTION INPUT ;
    USE SIGNAL ;
    ANTENNAGATEAREA 0.852000 ;
    PORT
      LAYER met3 ;
        RECT 0.000 167.320 2.000 167.920 ;
    END
  END tx_data[501]
  PIN tx_data[502]
    DIRECTION INPUT ;
    USE SIGNAL ;
    ANTENNAGATEAREA 0.990000 ;
    PORT
      LAYER met3 ;
        RECT 0.000 983.320 2.000 983.920 ;
    END
  END tx_data[502]
  PIN tx_data[503]
    DIRECTION INPUT ;
    USE SIGNAL ;
    ANTENNAGATEAREA 0.990000 ;
    PORT
      LAYER met2 ;
        RECT 535.530 1498.000 535.810 1500.000 ;
    END
  END tx_data[503]
  PIN tx_data[504]
    DIRECTION INPUT ;
    USE SIGNAL ;
    ANTENNAGATEAREA 0.742500 ;
    PORT
      LAYER met2 ;
        RECT 1244.850 1498.000 1245.130 1500.000 ;
    END
  END tx_data[504]
  PIN tx_data[505]
    DIRECTION INPUT ;
    USE SIGNAL ;
    ANTENNAGATEAREA 0.990000 ;
    PORT
      LAYER met3 ;
        RECT 0.000 942.520 2.000 943.120 ;
    END
  END tx_data[505]
  PIN tx_data[506]
    DIRECTION INPUT ;
    USE SIGNAL ;
    ANTENNAGATEAREA 0.990000 ;
    PORT
      LAYER met3 ;
        RECT 0.000 1109.800 2.000 1110.400 ;
    END
  END tx_data[506]
  PIN tx_data[507]
    DIRECTION INPUT ;
    USE SIGNAL ;
    ANTENNAGATEAREA 0.247500 ;
    PORT
      LAYER met3 ;
        RECT 1498.000 661.000 1500.000 661.600 ;
    END
  END tx_data[507]
  PIN tx_data[508]
    DIRECTION INPUT ;
    USE SIGNAL ;
    ANTENNAGATEAREA 0.426000 ;
    PORT
      LAYER met3 ;
        RECT 0.000 855.480 2.000 856.080 ;
    END
  END tx_data[508]
  PIN tx_data[509]
    DIRECTION INPUT ;
    USE SIGNAL ;
    ANTENNAGATEAREA 0.159000 ;
    PORT
      LAYER met3 ;
        RECT 0.000 399.880 2.000 400.480 ;
    END
  END tx_data[509]
  PIN tx_data[50]
    DIRECTION INPUT ;
    USE SIGNAL ;
    ANTENNAGATEAREA 0.742500 ;
    PORT
      LAYER met3 ;
        RECT 0.000 121.080 2.000 121.680 ;
    END
  END tx_data[50]
  PIN tx_data[510]
    DIRECTION INPUT ;
    USE SIGNAL ;
    ANTENNAGATEAREA 0.852000 ;
    PORT
      LAYER met3 ;
        RECT 0.000 1373.640 2.000 1374.240 ;
    END
  END tx_data[510]
  PIN tx_data[511]
    DIRECTION INPUT ;
    USE SIGNAL ;
    ANTENNAGATEAREA 0.247500 ;
    PORT
      LAYER met3 ;
        RECT 0.000 673.240 2.000 673.840 ;
    END
  END tx_data[511]
  PIN tx_data[51]
    DIRECTION INPUT ;
    USE SIGNAL ;
    ANTENNAGATEAREA 0.742500 ;
    PORT
      LAYER met2 ;
        RECT 169.830 0.000 170.110 2.000 ;
    END
  END tx_data[51]
  PIN tx_data[52]
    DIRECTION INPUT ;
    USE SIGNAL ;
    ANTENNAGATEAREA 0.159000 ;
    PORT
      LAYER met2 ;
        RECT 1022.670 0.000 1022.950 2.000 ;
    END
  END tx_data[52]
  PIN tx_data[53]
    DIRECTION INPUT ;
    USE SIGNAL ;
    ANTENNAGATEAREA 0.742500 ;
    PORT
      LAYER met2 ;
        RECT 1378.710 1498.000 1378.990 1500.000 ;
    END
  END tx_data[53]
  PIN tx_data[54]
    DIRECTION INPUT ;
    USE SIGNAL ;
    ANTENNAGATEAREA 0.742500 ;
    PORT
      LAYER met2 ;
        RECT 1491.870 1498.000 1492.150 1500.000 ;
    END
  END tx_data[54]
  PIN tx_data[55]
    DIRECTION INPUT ;
    USE SIGNAL ;
    ANTENNAGATEAREA 0.990000 ;
    PORT
      LAYER met3 ;
        RECT 0.000 267.960 2.000 268.560 ;
    END
  END tx_data[55]
  PIN tx_data[56]
    DIRECTION INPUT ;
    USE SIGNAL ;
    ANTENNAGATEAREA 0.742500 ;
    PORT
      LAYER met3 ;
        RECT 1498.000 1369.560 1500.000 1370.160 ;
    END
  END tx_data[56]
  PIN tx_data[57]
    DIRECTION INPUT ;
    USE SIGNAL ;
    ANTENNAGATEAREA 0.426000 ;
    PORT
      LAYER met3 ;
        RECT 1498.000 852.760 1500.000 853.360 ;
    END
  END tx_data[57]
  PIN tx_data[58]
    DIRECTION INPUT ;
    USE SIGNAL ;
    ANTENNAGATEAREA 0.247500 ;
    PORT
      LAYER met3 ;
        RECT 1498.000 229.880 1500.000 230.480 ;
    END
  END tx_data[58]
  PIN tx_data[59]
    DIRECTION INPUT ;
    USE SIGNAL ;
    ANTENNAGATEAREA 0.990000 ;
    PORT
      LAYER met2 ;
        RECT 313.350 1498.000 313.630 1500.000 ;
    END
  END tx_data[59]
  PIN tx_data[5]
    DIRECTION INPUT ;
    USE SIGNAL ;
    ANTENNAGATEAREA 0.990000 ;
    PORT
      LAYER met2 ;
        RECT 828.090 1498.000 828.370 1500.000 ;
    END
  END tx_data[5]
  PIN tx_data[60]
    DIRECTION INPUT ;
    USE SIGNAL ;
    ANTENNAGATEAREA 0.213000 ;
    PORT
      LAYER met2 ;
        RECT 1013.010 0.000 1013.290 2.000 ;
    END
  END tx_data[60]
  PIN tx_data[61]
    DIRECTION INPUT ;
    USE SIGNAL ;
    ANTENNAGATEAREA 0.213000 ;
    PORT
      LAYER met2 ;
        RECT 1444.950 0.000 1445.230 2.000 ;
    END
  END tx_data[61]
  PIN tx_data[62]
    DIRECTION INPUT ;
    USE SIGNAL ;
    ANTENNAGATEAREA 0.852000 ;
    PORT
      LAYER met3 ;
        RECT 0.000 364.520 2.000 365.120 ;
    END
  END tx_data[62]
  PIN tx_data[63]
    DIRECTION INPUT ;
    USE SIGNAL ;
    ANTENNAGATEAREA 0.990000 ;
    PORT
      LAYER met3 ;
        RECT 0.000 937.080 2.000 937.680 ;
    END
  END tx_data[63]
  PIN tx_data[64]
    DIRECTION INPUT ;
    USE SIGNAL ;
    ANTENNAGATEAREA 0.196500 ;
    PORT
      LAYER met2 ;
        RECT 966.090 0.000 966.370 2.000 ;
    END
  END tx_data[64]
  PIN tx_data[65]
    DIRECTION INPUT ;
    USE SIGNAL ;
    ANTENNAGATEAREA 0.426000 ;
    PORT
      LAYER met2 ;
        RECT 189.150 0.000 189.430 2.000 ;
    END
  END tx_data[65]
  PIN tx_data[66]
    DIRECTION INPUT ;
    USE SIGNAL ;
    ANTENNAGATEAREA 0.990000 ;
    PORT
      LAYER met3 ;
        RECT 0.000 1347.800 2.000 1348.400 ;
    END
  END tx_data[66]
  PIN tx_data[67]
    DIRECTION INPUT ;
    USE SIGNAL ;
    ANTENNAGATEAREA 0.990000 ;
    PORT
      LAYER met3 ;
        RECT 1498.000 1263.480 1500.000 1264.080 ;
    END
  END tx_data[67]
  PIN tx_data[68]
    DIRECTION INPUT ;
    USE SIGNAL ;
    ANTENNAGATEAREA 0.990000 ;
    PORT
      LAYER met2 ;
        RECT 1090.290 1498.000 1090.570 1500.000 ;
    END
  END tx_data[68]
  PIN tx_data[69]
    DIRECTION INPUT ;
    USE SIGNAL ;
    ANTENNAGATEAREA 0.213000 ;
    PORT
      LAYER met2 ;
        RECT 683.190 0.000 683.470 2.000 ;
    END
  END tx_data[69]
  PIN tx_data[6]
    DIRECTION INPUT ;
    USE SIGNAL ;
    ANTENNAGATEAREA 0.990000 ;
    PORT
      LAYER met2 ;
        RECT 673.530 1498.000 673.810 1500.000 ;
    END
  END tx_data[6]
  PIN tx_data[70]
    DIRECTION INPUT ;
    USE SIGNAL ;
    ANTENNAGATEAREA 0.990000 ;
    PORT
      LAYER met3 ;
        RECT 1498.000 964.280 1500.000 964.880 ;
    END
  END tx_data[70]
  PIN tx_data[71]
    DIRECTION INPUT ;
    USE SIGNAL ;
    ANTENNAGATEAREA 0.247500 ;
    PORT
      LAYER met2 ;
        RECT 1358.010 0.000 1358.290 2.000 ;
    END
  END tx_data[71]
  PIN tx_data[72]
    DIRECTION INPUT ;
    USE SIGNAL ;
    ANTENNAGATEAREA 0.990000 ;
    PORT
      LAYER met2 ;
        RECT 658.350 1498.000 658.630 1500.000 ;
    END
  END tx_data[72]
  PIN tx_data[73]
    DIRECTION INPUT ;
    USE SIGNAL ;
    ANTENNAGATEAREA 0.247500 ;
    PORT
      LAYER met2 ;
        RECT 1301.430 0.000 1301.710 2.000 ;
    END
  END tx_data[73]
  PIN tx_data[74]
    DIRECTION INPUT ;
    USE SIGNAL ;
    ANTENNAGATEAREA 0.159000 ;
    PORT
      LAYER met2 ;
        RECT 549.330 0.000 549.610 2.000 ;
    END
  END tx_data[74]
  PIN tx_data[75]
    DIRECTION INPUT ;
    USE SIGNAL ;
    ANTENNAGATEAREA 0.247500 ;
    PORT
      LAYER met2 ;
        RECT 87.030 0.000 87.310 2.000 ;
    END
  END tx_data[75]
  PIN tx_data[76]
    DIRECTION INPUT ;
    USE SIGNAL ;
    ANTENNAGATEAREA 0.247500 ;
    PORT
      LAYER met3 ;
        RECT 1498.000 219.000 1500.000 219.600 ;
    END
  END tx_data[76]
  PIN tx_data[77]
    DIRECTION INPUT ;
    USE SIGNAL ;
    ANTENNAGATEAREA 0.495000 ;
    PORT
      LAYER met3 ;
        RECT 1498.000 675.960 1500.000 676.560 ;
    END
  END tx_data[77]
  PIN tx_data[78]
    DIRECTION INPUT ;
    USE SIGNAL ;
    ANTENNAGATEAREA 0.990000 ;
    PORT
      LAYER met3 ;
        RECT 0.000 1429.400 2.000 1430.000 ;
    END
  END tx_data[78]
  PIN tx_data[79]
    DIRECTION INPUT ;
    USE SIGNAL ;
    ANTENNAGATEAREA 0.990000 ;
    PORT
      LAYER met2 ;
        RECT 1322.130 1498.000 1322.410 1500.000 ;
    END
  END tx_data[79]
  PIN tx_data[7]
    DIRECTION INPUT ;
    USE SIGNAL ;
    ANTENNAGATEAREA 0.247500 ;
    PORT
      LAYER met3 ;
        RECT 0.000 541.320 2.000 541.920 ;
    END
  END tx_data[7]
  PIN tx_data[80]
    DIRECTION INPUT ;
    USE SIGNAL ;
    ANTENNAGATEAREA 0.990000 ;
    PORT
      LAYER met3 ;
        RECT 0.000 669.160 2.000 669.760 ;
    END
  END tx_data[80]
  PIN tx_data[81]
    DIRECTION INPUT ;
    USE SIGNAL ;
    ANTENNAGATEAREA 0.990000 ;
    PORT
      LAYER met3 ;
        RECT 0.000 622.920 2.000 623.520 ;
    END
  END tx_data[81]
  PIN tx_data[82]
    DIRECTION INPUT ;
    USE SIGNAL ;
    ANTENNAGATEAREA 0.852000 ;
    PORT
      LAYER met2 ;
        RECT 71.850 0.000 72.130 2.000 ;
    END
  END tx_data[82]
  PIN tx_data[83]
    DIRECTION INPUT ;
    USE SIGNAL ;
    ANTENNAGATEAREA 0.742500 ;
    PORT
      LAYER met2 ;
        RECT 369.930 0.000 370.210 2.000 ;
    END
  END tx_data[83]
  PIN tx_data[84]
    DIRECTION INPUT ;
    USE SIGNAL ;
    ANTENNAGATEAREA 0.495000 ;
    PORT
      LAYER met3 ;
        RECT 1498.000 1055.400 1500.000 1056.000 ;
    END
  END tx_data[84]
  PIN tx_data[85]
    DIRECTION INPUT ;
    USE SIGNAL ;
    ANTENNAGATEAREA 0.247500 ;
    PORT
      LAYER met2 ;
        RECT 971.610 0.000 971.890 2.000 ;
    END
  END tx_data[85]
  PIN tx_data[86]
    DIRECTION INPUT ;
    USE SIGNAL ;
    ANTENNAGATEAREA 0.990000 ;
    PORT
      LAYER met2 ;
        RECT 627.990 1498.000 628.270 1500.000 ;
    END
  END tx_data[86]
  PIN tx_data[87]
    DIRECTION INPUT ;
    USE SIGNAL ;
    ANTENNAGATEAREA 0.742500 ;
    PORT
      LAYER met2 ;
        RECT 1039.230 1498.000 1039.510 1500.000 ;
    END
  END tx_data[87]
  PIN tx_data[88]
    DIRECTION INPUT ;
    USE SIGNAL ;
    ANTENNAGATEAREA 0.990000 ;
    PORT
      LAYER met3 ;
        RECT 0.000 1094.840 2.000 1095.440 ;
    END
  END tx_data[88]
  PIN tx_data[89]
    DIRECTION INPUT ;
    USE SIGNAL ;
    ANTENNAGATEAREA 0.742500 ;
    PORT
      LAYER met2 ;
        RECT 262.290 0.000 262.570 2.000 ;
    END
  END tx_data[89]
  PIN tx_data[8]
    DIRECTION INPUT ;
    USE SIGNAL ;
    ANTENNAGATEAREA 0.990000 ;
    PORT
      LAYER met3 ;
        RECT 1498.000 1162.840 1500.000 1163.440 ;
    END
  END tx_data[8]
  PIN tx_data[90]
    DIRECTION INPUT ;
    USE SIGNAL ;
    ANTENNAGATEAREA 0.742500 ;
    PORT
      LAYER met2 ;
        RECT 1116.510 1498.000 1116.790 1500.000 ;
    END
  END tx_data[90]
  PIN tx_data[91]
    DIRECTION INPUT ;
    USE SIGNAL ;
    ANTENNAGATEAREA 0.990000 ;
    PORT
      LAYER met3 ;
        RECT 0.000 374.040 2.000 374.640 ;
    END
  END tx_data[91]
  PIN tx_data[92]
    DIRECTION INPUT ;
    USE SIGNAL ;
    ANTENNAGATEAREA 0.742500 ;
    PORT
      LAYER met3 ;
        RECT 1498.000 1441.640 1500.000 1442.240 ;
    END
  END tx_data[92]
  PIN tx_data[93]
    DIRECTION INPUT ;
    USE SIGNAL ;
    ANTENNAGATEAREA 0.247500 ;
    PORT
      LAYER met3 ;
        RECT 1498.000 696.360 1500.000 696.960 ;
    END
  END tx_data[93]
  PIN tx_data[94]
    DIRECTION INPUT ;
    USE SIGNAL ;
    ANTENNAGATEAREA 0.213000 ;
    PORT
      LAYER met2 ;
        RECT 1151.010 0.000 1151.290 2.000 ;
    END
  END tx_data[94]
  PIN tx_data[95]
    DIRECTION INPUT ;
    USE SIGNAL ;
    ANTENNAGATEAREA 0.990000 ;
    PORT
      LAYER met2 ;
        RECT 946.770 1498.000 947.050 1500.000 ;
    END
  END tx_data[95]
  PIN tx_data[96]
    DIRECTION INPUT ;
    USE SIGNAL ;
    ANTENNAGATEAREA 0.990000 ;
    PORT
      LAYER met3 ;
        RECT 0.000 1479.720 2.000 1480.320 ;
    END
  END tx_data[96]
  PIN tx_data[97]
    DIRECTION INPUT ;
    USE SIGNAL ;
    ANTENNAGATEAREA 0.742500 ;
    PORT
      LAYER met2 ;
        RECT 524.490 0.000 524.770 2.000 ;
    END
  END tx_data[97]
  PIN tx_data[98]
    DIRECTION INPUT ;
    USE SIGNAL ;
    ANTENNAGATEAREA 0.426000 ;
    PORT
      LAYER met3 ;
        RECT 1498.000 1122.040 1500.000 1122.640 ;
    END
  END tx_data[98]
  PIN tx_data[99]
    DIRECTION INPUT ;
    USE SIGNAL ;
    ANTENNAGATEAREA 0.213000 ;
    PORT
      LAYER met2 ;
        RECT 1346.970 0.000 1347.250 2.000 ;
    END
  END tx_data[99]
  PIN tx_data[9]
    DIRECTION INPUT ;
    USE SIGNAL ;
    ANTENNAGATEAREA 0.990000 ;
    PORT
      LAYER met3 ;
        RECT 1498.000 614.760 1500.000 615.360 ;
    END
  END tx_data[9]
  PIN tx_dlc[0]
    DIRECTION INPUT ;
    USE SIGNAL ;
    ANTENNAGATEAREA 0.213000 ;
    PORT
      LAYER met3 ;
        RECT 0.000 379.480 2.000 380.080 ;
    END
  END tx_dlc[0]
  PIN tx_dlc[1]
    DIRECTION INPUT ;
    USE SIGNAL ;
    ANTENNAGATEAREA 0.852000 ;
    PORT
      LAYER met3 ;
        RECT 1498.000 194.520 1500.000 195.120 ;
    END
  END tx_dlc[1]
  PIN tx_dlc[2]
    DIRECTION INPUT ;
    USE SIGNAL ;
    ANTENNAGATEAREA 0.213000 ;
    PORT
      LAYER met2 ;
        RECT 266.430 0.000 266.710 2.000 ;
    END
  END tx_dlc[2]
  PIN tx_dlc[3]
    DIRECTION INPUT ;
    USE SIGNAL ;
    ANTENNAGATEAREA 0.426000 ;
    PORT
      LAYER met2 ;
        RECT 811.530 0.000 811.810 2.000 ;
    END
  END tx_dlc[3]
  PIN tx_err_cnt[0]
    DIRECTION OUTPUT TRISTATE ;
    USE SIGNAL ;
    ANTENNADIFFAREA 0.795200 ;
    PORT
      LAYER met3 ;
        RECT 1498.000 817.400 1500.000 818.000 ;
    END
  END tx_err_cnt[0]
  PIN tx_err_cnt[1]
    DIRECTION OUTPUT TRISTATE ;
    USE SIGNAL ;
    ANTENNADIFFAREA 0.795200 ;
    PORT
      LAYER met2 ;
        RECT 952.290 1498.000 952.570 1500.000 ;
    END
  END tx_err_cnt[1]
  PIN tx_err_cnt[2]
    DIRECTION OUTPUT TRISTATE ;
    USE SIGNAL ;
    ANTENNADIFFAREA 0.795200 ;
    PORT
      LAYER met2 ;
        RECT 1455.990 1498.000 1456.270 1500.000 ;
    END
  END tx_err_cnt[2]
  PIN tx_err_cnt[3]
    DIRECTION OUTPUT TRISTATE ;
    USE SIGNAL ;
    ANTENNADIFFAREA 0.795200 ;
    PORT
      LAYER met3 ;
        RECT 1498.000 198.600 1500.000 199.200 ;
    END
  END tx_err_cnt[3]
  PIN tx_err_cnt[4]
    DIRECTION OUTPUT TRISTATE ;
    USE SIGNAL ;
    ANTENNADIFFAREA 0.795200 ;
    PORT
      LAYER met2 ;
        RECT 132.570 0.000 132.850 2.000 ;
    END
  END tx_err_cnt[4]
  PIN tx_err_cnt[5]
    DIRECTION OUTPUT TRISTATE ;
    USE SIGNAL ;
    ANTENNADIFFAREA 0.795200 ;
    PORT
      LAYER met3 ;
        RECT 1498.000 1010.520 1500.000 1011.120 ;
    END
  END tx_err_cnt[5]
  PIN tx_err_cnt[6]
    DIRECTION OUTPUT TRISTATE ;
    USE SIGNAL ;
    ANTENNADIFFAREA 0.795200 ;
    PORT
      LAYER met2 ;
        RECT 40.110 0.000 40.390 2.000 ;
    END
  END tx_err_cnt[6]
  PIN tx_err_cnt[7]
    DIRECTION OUTPUT TRISTATE ;
    USE SIGNAL ;
    ANTENNADIFFAREA 0.795200 ;
    PORT
      LAYER met2 ;
        RECT 1444.950 1498.000 1445.230 1500.000 ;
    END
  END tx_err_cnt[7]
  PIN tx_fdf
    DIRECTION INPUT ;
    USE SIGNAL ;
    ANTENNAGATEAREA 0.990000 ;
    PORT
      LAYER met2 ;
        RECT 931.590 1498.000 931.870 1500.000 ;
    END
  END tx_fdf
  PIN tx_id[0]
    DIRECTION INPUT ;
    USE SIGNAL ;
    ANTENNAGATEAREA 0.990000 ;
    PORT
      LAYER met3 ;
        RECT 1498.000 280.200 1500.000 280.800 ;
    END
  END tx_id[0]
  PIN tx_id[10]
    DIRECTION INPUT ;
    USE SIGNAL ;
    ANTENNAGATEAREA 0.990000 ;
    PORT
      LAYER met2 ;
        RECT 890.190 1498.000 890.470 1500.000 ;
    END
  END tx_id[10]
  PIN tx_id[11]
    DIRECTION INPUT ;
    USE SIGNAL ;
    ANTENNAGATEAREA 0.742500 ;
    PORT
      LAYER met2 ;
        RECT 1075.110 0.000 1075.390 2.000 ;
    END
  END tx_id[11]
  PIN tx_id[12]
    DIRECTION INPUT ;
    USE SIGNAL ;
    ANTENNAGATEAREA 0.213000 ;
    PORT
      LAYER met3 ;
        RECT 0.000 191.800 2.000 192.400 ;
    END
  END tx_id[12]
  PIN tx_id[13]
    DIRECTION INPUT ;
    USE SIGNAL ;
    ANTENNAGATEAREA 0.742500 ;
    PORT
      LAYER met2 ;
        RECT 1069.590 0.000 1069.870 2.000 ;
    END
  END tx_id[13]
  PIN tx_id[14]
    DIRECTION INPUT ;
    USE SIGNAL ;
    ANTENNAGATEAREA 0.247500 ;
    PORT
      LAYER met2 ;
        RECT 0.090 0.000 0.370 2.000 ;
    END
  END tx_id[14]
  PIN tx_id[15]
    DIRECTION INPUT ;
    USE SIGNAL ;
    ANTENNAGATEAREA 0.852000 ;
    PORT
      LAYER met2 ;
        RECT 1248.990 0.000 1249.270 2.000 ;
    END
  END tx_id[15]
  PIN tx_id[16]
    DIRECTION INPUT ;
    USE SIGNAL ;
    ANTENNAGATEAREA 0.159000 ;
    PORT
      LAYER met3 ;
        RECT 0.000 485.560 2.000 486.160 ;
    END
  END tx_id[16]
  PIN tx_id[17]
    DIRECTION INPUT ;
    USE SIGNAL ;
    ANTENNAGATEAREA 0.426000 ;
    PORT
      LAYER met3 ;
        RECT 0.000 1098.920 2.000 1099.520 ;
    END
  END tx_id[17]
  PIN tx_id[18]
    DIRECTION INPUT ;
    USE SIGNAL ;
    ANTENNAGATEAREA 0.742500 ;
    PORT
      LAYER met2 ;
        RECT 247.110 1498.000 247.390 1500.000 ;
    END
  END tx_id[18]
  PIN tx_id[19]
    DIRECTION INPUT ;
    USE SIGNAL ;
    ANTENNAGATEAREA 0.213000 ;
    PORT
      LAYER met3 ;
        RECT 0.000 288.360 2.000 288.960 ;
    END
  END tx_id[19]
  PIN tx_id[1]
    DIRECTION INPUT ;
    USE SIGNAL ;
    ANTENNAGATEAREA 0.213000 ;
    PORT
      LAYER met2 ;
        RECT 334.050 0.000 334.330 2.000 ;
    END
  END tx_id[1]
  PIN tx_id[20]
    DIRECTION INPUT ;
    USE SIGNAL ;
    ANTENNAGATEAREA 0.247500 ;
    PORT
      LAYER met2 ;
        RECT 117.390 0.000 117.670 2.000 ;
    END
  END tx_id[20]
  PIN tx_id[21]
    DIRECTION INPUT ;
    USE SIGNAL ;
    ANTENNAGATEAREA 0.990000 ;
    PORT
      LAYER met2 ;
        RECT 652.830 1498.000 653.110 1500.000 ;
    END
  END tx_id[21]
  PIN tx_id[22]
    DIRECTION INPUT ;
    USE SIGNAL ;
    ANTENNAGATEAREA 0.852000 ;
    PORT
      LAYER met2 ;
        RECT 309.210 1498.000 309.490 1500.000 ;
    END
  END tx_id[22]
  PIN tx_id[23]
    DIRECTION INPUT ;
    USE SIGNAL ;
    ANTENNAGATEAREA 0.742500 ;
    PORT
      LAYER met2 ;
        RECT 848.790 0.000 849.070 2.000 ;
    END
  END tx_id[23]
  PIN tx_id[24]
    DIRECTION INPUT ;
    USE SIGNAL ;
    ANTENNAGATEAREA 0.990000 ;
    PORT
      LAYER met2 ;
        RECT 941.250 1498.000 941.530 1500.000 ;
    END
  END tx_id[24]
  PIN tx_id[25]
    DIRECTION INPUT ;
    USE SIGNAL ;
    ANTENNAGATEAREA 0.990000 ;
    PORT
      LAYER met3 ;
        RECT 1498.000 482.840 1500.000 483.440 ;
    END
  END tx_id[25]
  PIN tx_id[26]
    DIRECTION INPUT ;
    USE SIGNAL ;
    ANTENNAGATEAREA 0.247500 ;
    PORT
      LAYER met3 ;
        RECT 0.000 860.920 2.000 861.520 ;
    END
  END tx_id[26]
  PIN tx_id[27]
    DIRECTION INPUT ;
    USE SIGNAL ;
    ANTENNAGATEAREA 0.990000 ;
    PORT
      LAYER met3 ;
        RECT 1498.000 1222.680 1500.000 1223.280 ;
    END
  END tx_id[27]
  PIN tx_id[28]
    DIRECTION INPUT ;
    USE SIGNAL ;
    ANTENNAGATEAREA 0.247500 ;
    PORT
      LAYER met2 ;
        RECT 343.710 0.000 343.990 2.000 ;
    END
  END tx_id[28]
  PIN tx_id[2]
    DIRECTION INPUT ;
    USE SIGNAL ;
    ANTENNAGATEAREA 0.247500 ;
    PORT
      LAYER met2 ;
        RECT 596.250 0.000 596.530 2.000 ;
    END
  END tx_id[2]
  PIN tx_id[3]
    DIRECTION INPUT ;
    USE SIGNAL ;
    ANTENNAGATEAREA 0.742500 ;
    PORT
      LAYER met2 ;
        RECT 930.210 0.000 930.490 2.000 ;
    END
  END tx_id[3]
  PIN tx_id[4]
    DIRECTION INPUT ;
    USE SIGNAL ;
    ANTENNAGATEAREA 0.990000 ;
    PORT
      LAYER met3 ;
        RECT 1498.000 1151.960 1500.000 1152.560 ;
    END
  END tx_id[4]
  PIN tx_id[5]
    DIRECTION INPUT ;
    USE SIGNAL ;
    ANTENNAGATEAREA 0.742500 ;
    PORT
      LAYER met2 ;
        RECT 935.730 0.000 936.010 2.000 ;
    END
  END tx_id[5]
  PIN tx_id[6]
    DIRECTION INPUT ;
    USE SIGNAL ;
    ANTENNAGATEAREA 0.990000 ;
    PORT
      LAYER met2 ;
        RECT 935.730 1498.000 936.010 1500.000 ;
    END
  END tx_id[6]
  PIN tx_id[7]
    DIRECTION INPUT ;
    USE SIGNAL ;
    ANTENNAGATEAREA 0.990000 ;
    PORT
      LAYER met2 ;
        RECT 926.070 1498.000 926.350 1500.000 ;
    END
  END tx_id[7]
  PIN tx_id[8]
    DIRECTION INPUT ;
    USE SIGNAL ;
    ANTENNAGATEAREA 0.742500 ;
    PORT
      LAYER met3 ;
        RECT 0.000 1332.840 2.000 1333.440 ;
    END
  END tx_id[8]
  PIN tx_id[9]
    DIRECTION INPUT ;
    USE SIGNAL ;
    ANTENNAGATEAREA 0.742500 ;
    PORT
      LAYER met2 ;
        RECT 113.250 1498.000 113.530 1500.000 ;
    END
  END tx_id[9]
  PIN tx_ide
    DIRECTION INPUT ;
    USE SIGNAL ;
    ANTENNAGATEAREA 0.990000 ;
    PORT
      LAYER met2 ;
        RECT 1099.950 0.000 1100.230 2.000 ;
    END
  END tx_ide
  PIN tx_ready
    DIRECTION OUTPUT TRISTATE ;
    USE SIGNAL ;
    PORT
      LAYER met3 ;
        RECT 0.000 303.320 2.000 303.920 ;
    END
  END tx_ready
  PIN tx_rtr
    DIRECTION INPUT ;
    USE SIGNAL ;
    PORT
      LAYER met3 ;
        RECT 0.000 1215.880 2.000 1216.480 ;
    END
  END tx_rtr
  PIN tx_valid
    DIRECTION INPUT ;
    USE SIGNAL ;
    ANTENNAGATEAREA 0.426000 ;
    PORT
      LAYER met3 ;
        RECT 1498.000 752.120 1500.000 752.720 ;
    END
  END tx_valid
  OBS
      LAYER li1 ;
        RECT 10.120 10.795 1489.940 1487.925 ;
      LAYER met1 ;
        RECT 0.070 0.380 1499.990 1496.300 ;
      LAYER met2 ;
        RECT 0.650 1497.720 5.330 1499.245 ;
        RECT 6.170 1497.720 9.470 1499.245 ;
        RECT 10.310 1497.720 14.990 1499.245 ;
        RECT 15.830 1497.720 20.510 1499.245 ;
        RECT 21.350 1497.720 26.030 1499.245 ;
        RECT 26.870 1497.720 30.170 1499.245 ;
        RECT 31.010 1497.720 35.690 1499.245 ;
        RECT 36.530 1497.720 41.210 1499.245 ;
        RECT 42.050 1497.720 45.350 1499.245 ;
        RECT 46.190 1497.720 50.870 1499.245 ;
        RECT 51.710 1497.720 56.390 1499.245 ;
        RECT 57.230 1497.720 61.910 1499.245 ;
        RECT 62.750 1497.720 66.050 1499.245 ;
        RECT 66.890 1497.720 71.570 1499.245 ;
        RECT 72.410 1497.720 77.090 1499.245 ;
        RECT 77.930 1497.720 82.610 1499.245 ;
        RECT 83.450 1497.720 86.750 1499.245 ;
        RECT 87.590 1497.720 92.270 1499.245 ;
        RECT 93.110 1497.720 97.790 1499.245 ;
        RECT 98.630 1497.720 101.930 1499.245 ;
        RECT 102.770 1497.720 107.450 1499.245 ;
        RECT 108.290 1497.720 112.970 1499.245 ;
        RECT 113.810 1497.720 118.490 1499.245 ;
        RECT 119.330 1497.720 122.630 1499.245 ;
        RECT 123.470 1497.720 128.150 1499.245 ;
        RECT 128.990 1497.720 133.670 1499.245 ;
        RECT 134.510 1497.720 139.190 1499.245 ;
        RECT 140.030 1497.720 143.330 1499.245 ;
        RECT 144.170 1497.720 148.850 1499.245 ;
        RECT 149.690 1497.720 154.370 1499.245 ;
        RECT 155.210 1497.720 158.510 1499.245 ;
        RECT 159.350 1497.720 164.030 1499.245 ;
        RECT 164.870 1497.720 169.550 1499.245 ;
        RECT 170.390 1497.720 175.070 1499.245 ;
        RECT 175.910 1497.720 179.210 1499.245 ;
        RECT 180.050 1497.720 184.730 1499.245 ;
        RECT 185.570 1497.720 190.250 1499.245 ;
        RECT 191.090 1497.720 195.770 1499.245 ;
        RECT 196.610 1497.720 199.910 1499.245 ;
        RECT 200.750 1497.720 205.430 1499.245 ;
        RECT 206.270 1497.720 210.950 1499.245 ;
        RECT 211.790 1497.720 215.090 1499.245 ;
        RECT 215.930 1497.720 220.610 1499.245 ;
        RECT 221.450 1497.720 226.130 1499.245 ;
        RECT 226.970 1497.720 231.650 1499.245 ;
        RECT 232.490 1497.720 235.790 1499.245 ;
        RECT 236.630 1497.720 241.310 1499.245 ;
        RECT 242.150 1497.720 246.830 1499.245 ;
        RECT 247.670 1497.720 252.350 1499.245 ;
        RECT 253.190 1497.720 256.490 1499.245 ;
        RECT 257.330 1497.720 262.010 1499.245 ;
        RECT 262.850 1497.720 267.530 1499.245 ;
        RECT 268.370 1497.720 271.670 1499.245 ;
        RECT 272.510 1497.720 277.190 1499.245 ;
        RECT 278.030 1497.720 282.710 1499.245 ;
        RECT 283.550 1497.720 288.230 1499.245 ;
        RECT 289.070 1497.720 292.370 1499.245 ;
        RECT 293.210 1497.720 297.890 1499.245 ;
        RECT 298.730 1497.720 303.410 1499.245 ;
        RECT 304.250 1497.720 308.930 1499.245 ;
        RECT 309.770 1497.720 313.070 1499.245 ;
        RECT 313.910 1497.720 318.590 1499.245 ;
        RECT 319.430 1497.720 324.110 1499.245 ;
        RECT 324.950 1497.720 328.250 1499.245 ;
        RECT 329.090 1497.720 333.770 1499.245 ;
        RECT 334.610 1497.720 339.290 1499.245 ;
        RECT 340.130 1497.720 344.810 1499.245 ;
        RECT 345.650 1497.720 348.950 1499.245 ;
        RECT 349.790 1497.720 354.470 1499.245 ;
        RECT 355.310 1497.720 359.990 1499.245 ;
        RECT 360.830 1497.720 365.510 1499.245 ;
        RECT 366.350 1497.720 369.650 1499.245 ;
        RECT 370.490 1497.720 375.170 1499.245 ;
        RECT 376.010 1497.720 380.690 1499.245 ;
        RECT 381.530 1497.720 384.830 1499.245 ;
        RECT 385.670 1497.720 390.350 1499.245 ;
        RECT 391.190 1497.720 395.870 1499.245 ;
        RECT 396.710 1497.720 401.390 1499.245 ;
        RECT 402.230 1497.720 405.530 1499.245 ;
        RECT 406.370 1497.720 411.050 1499.245 ;
        RECT 411.890 1497.720 416.570 1499.245 ;
        RECT 417.410 1497.720 422.090 1499.245 ;
        RECT 422.930 1497.720 426.230 1499.245 ;
        RECT 427.070 1497.720 431.750 1499.245 ;
        RECT 432.590 1497.720 437.270 1499.245 ;
        RECT 438.110 1497.720 441.410 1499.245 ;
        RECT 442.250 1497.720 446.930 1499.245 ;
        RECT 447.770 1497.720 452.450 1499.245 ;
        RECT 453.290 1497.720 457.970 1499.245 ;
        RECT 458.810 1497.720 462.110 1499.245 ;
        RECT 462.950 1497.720 467.630 1499.245 ;
        RECT 468.470 1497.720 473.150 1499.245 ;
        RECT 473.990 1497.720 478.670 1499.245 ;
        RECT 479.510 1497.720 482.810 1499.245 ;
        RECT 483.650 1497.720 488.330 1499.245 ;
        RECT 489.170 1497.720 493.850 1499.245 ;
        RECT 494.690 1497.720 497.990 1499.245 ;
        RECT 498.830 1497.720 503.510 1499.245 ;
        RECT 504.350 1497.720 509.030 1499.245 ;
        RECT 509.870 1497.720 514.550 1499.245 ;
        RECT 515.390 1497.720 518.690 1499.245 ;
        RECT 519.530 1497.720 524.210 1499.245 ;
        RECT 525.050 1497.720 529.730 1499.245 ;
        RECT 530.570 1497.720 535.250 1499.245 ;
        RECT 536.090 1497.720 539.390 1499.245 ;
        RECT 540.230 1497.720 544.910 1499.245 ;
        RECT 545.750 1497.720 550.430 1499.245 ;
        RECT 551.270 1497.720 554.570 1499.245 ;
        RECT 555.410 1497.720 560.090 1499.245 ;
        RECT 560.930 1497.720 565.610 1499.245 ;
        RECT 566.450 1497.720 571.130 1499.245 ;
        RECT 571.970 1497.720 575.270 1499.245 ;
        RECT 576.110 1497.720 580.790 1499.245 ;
        RECT 581.630 1497.720 586.310 1499.245 ;
        RECT 587.150 1497.720 591.830 1499.245 ;
        RECT 592.670 1497.720 595.970 1499.245 ;
        RECT 596.810 1497.720 601.490 1499.245 ;
        RECT 602.330 1497.720 607.010 1499.245 ;
        RECT 607.850 1497.720 611.150 1499.245 ;
        RECT 611.990 1497.720 616.670 1499.245 ;
        RECT 617.510 1497.720 622.190 1499.245 ;
        RECT 623.030 1497.720 627.710 1499.245 ;
        RECT 628.550 1497.720 631.850 1499.245 ;
        RECT 632.690 1497.720 637.370 1499.245 ;
        RECT 638.210 1497.720 642.890 1499.245 ;
        RECT 643.730 1497.720 648.410 1499.245 ;
        RECT 649.250 1497.720 652.550 1499.245 ;
        RECT 653.390 1497.720 658.070 1499.245 ;
        RECT 658.910 1497.720 663.590 1499.245 ;
        RECT 664.430 1497.720 667.730 1499.245 ;
        RECT 668.570 1497.720 673.250 1499.245 ;
        RECT 674.090 1497.720 678.770 1499.245 ;
        RECT 679.610 1497.720 684.290 1499.245 ;
        RECT 685.130 1497.720 688.430 1499.245 ;
        RECT 689.270 1497.720 693.950 1499.245 ;
        RECT 694.790 1497.720 699.470 1499.245 ;
        RECT 700.310 1497.720 704.990 1499.245 ;
        RECT 705.830 1497.720 709.130 1499.245 ;
        RECT 709.970 1497.720 714.650 1499.245 ;
        RECT 715.490 1497.720 720.170 1499.245 ;
        RECT 721.010 1497.720 724.310 1499.245 ;
        RECT 725.150 1497.720 729.830 1499.245 ;
        RECT 730.670 1497.720 735.350 1499.245 ;
        RECT 736.190 1497.720 740.870 1499.245 ;
        RECT 741.710 1497.720 745.010 1499.245 ;
        RECT 745.850 1497.720 750.530 1499.245 ;
        RECT 751.370 1497.720 756.050 1499.245 ;
        RECT 756.890 1497.720 761.570 1499.245 ;
        RECT 762.410 1497.720 765.710 1499.245 ;
        RECT 766.550 1497.720 771.230 1499.245 ;
        RECT 772.070 1497.720 776.750 1499.245 ;
        RECT 777.590 1497.720 780.890 1499.245 ;
        RECT 781.730 1497.720 786.410 1499.245 ;
        RECT 787.250 1497.720 791.930 1499.245 ;
        RECT 792.770 1497.720 797.450 1499.245 ;
        RECT 798.290 1497.720 801.590 1499.245 ;
        RECT 802.430 1497.720 807.110 1499.245 ;
        RECT 807.950 1497.720 812.630 1499.245 ;
        RECT 813.470 1497.720 818.150 1499.245 ;
        RECT 818.990 1497.720 822.290 1499.245 ;
        RECT 823.130 1497.720 827.810 1499.245 ;
        RECT 828.650 1497.720 833.330 1499.245 ;
        RECT 834.170 1497.720 837.470 1499.245 ;
        RECT 838.310 1497.720 842.990 1499.245 ;
        RECT 843.830 1497.720 848.510 1499.245 ;
        RECT 849.350 1497.720 854.030 1499.245 ;
        RECT 854.870 1497.720 858.170 1499.245 ;
        RECT 859.010 1497.720 863.690 1499.245 ;
        RECT 864.530 1497.720 869.210 1499.245 ;
        RECT 870.050 1497.720 874.730 1499.245 ;
        RECT 875.570 1497.720 878.870 1499.245 ;
        RECT 879.710 1497.720 884.390 1499.245 ;
        RECT 885.230 1497.720 889.910 1499.245 ;
        RECT 890.750 1497.720 894.050 1499.245 ;
        RECT 894.890 1497.720 899.570 1499.245 ;
        RECT 900.410 1497.720 905.090 1499.245 ;
        RECT 905.930 1497.720 910.610 1499.245 ;
        RECT 911.450 1497.720 914.750 1499.245 ;
        RECT 915.590 1497.720 920.270 1499.245 ;
        RECT 921.110 1497.720 925.790 1499.245 ;
        RECT 926.630 1497.720 931.310 1499.245 ;
        RECT 932.150 1497.720 935.450 1499.245 ;
        RECT 936.290 1497.720 940.970 1499.245 ;
        RECT 941.810 1497.720 946.490 1499.245 ;
        RECT 947.330 1497.720 952.010 1499.245 ;
        RECT 952.850 1497.720 956.150 1499.245 ;
        RECT 956.990 1497.720 961.670 1499.245 ;
        RECT 962.510 1497.720 967.190 1499.245 ;
        RECT 968.030 1497.720 971.330 1499.245 ;
        RECT 972.170 1497.720 976.850 1499.245 ;
        RECT 977.690 1497.720 982.370 1499.245 ;
        RECT 983.210 1497.720 987.890 1499.245 ;
        RECT 988.730 1497.720 992.030 1499.245 ;
        RECT 992.870 1497.720 997.550 1499.245 ;
        RECT 998.390 1497.720 1003.070 1499.245 ;
        RECT 1003.910 1497.720 1008.590 1499.245 ;
        RECT 1009.430 1497.720 1012.730 1499.245 ;
        RECT 1013.570 1497.720 1018.250 1499.245 ;
        RECT 1019.090 1497.720 1023.770 1499.245 ;
        RECT 1024.610 1497.720 1027.910 1499.245 ;
        RECT 1028.750 1497.720 1033.430 1499.245 ;
        RECT 1034.270 1497.720 1038.950 1499.245 ;
        RECT 1039.790 1497.720 1044.470 1499.245 ;
        RECT 1045.310 1497.720 1048.610 1499.245 ;
        RECT 1049.450 1497.720 1054.130 1499.245 ;
        RECT 1054.970 1497.720 1059.650 1499.245 ;
        RECT 1060.490 1497.720 1065.170 1499.245 ;
        RECT 1066.010 1497.720 1069.310 1499.245 ;
        RECT 1070.150 1497.720 1074.830 1499.245 ;
        RECT 1075.670 1497.720 1080.350 1499.245 ;
        RECT 1081.190 1497.720 1084.490 1499.245 ;
        RECT 1085.330 1497.720 1090.010 1499.245 ;
        RECT 1090.850 1497.720 1095.530 1499.245 ;
        RECT 1096.370 1497.720 1101.050 1499.245 ;
        RECT 1101.890 1497.720 1105.190 1499.245 ;
        RECT 1106.030 1497.720 1110.710 1499.245 ;
        RECT 1111.550 1497.720 1116.230 1499.245 ;
        RECT 1117.070 1497.720 1121.750 1499.245 ;
        RECT 1122.590 1497.720 1125.890 1499.245 ;
        RECT 1126.730 1497.720 1131.410 1499.245 ;
        RECT 1132.250 1497.720 1136.930 1499.245 ;
        RECT 1137.770 1497.720 1141.070 1499.245 ;
        RECT 1141.910 1497.720 1146.590 1499.245 ;
        RECT 1147.430 1497.720 1152.110 1499.245 ;
        RECT 1152.950 1497.720 1157.630 1499.245 ;
        RECT 1158.470 1497.720 1161.770 1499.245 ;
        RECT 1162.610 1497.720 1167.290 1499.245 ;
        RECT 1168.130 1497.720 1172.810 1499.245 ;
        RECT 1173.650 1497.720 1178.330 1499.245 ;
        RECT 1179.170 1497.720 1182.470 1499.245 ;
        RECT 1183.310 1497.720 1187.990 1499.245 ;
        RECT 1188.830 1497.720 1193.510 1499.245 ;
        RECT 1194.350 1497.720 1197.650 1499.245 ;
        RECT 1198.490 1497.720 1203.170 1499.245 ;
        RECT 1204.010 1497.720 1208.690 1499.245 ;
        RECT 1209.530 1497.720 1214.210 1499.245 ;
        RECT 1215.050 1497.720 1218.350 1499.245 ;
        RECT 1219.190 1497.720 1223.870 1499.245 ;
        RECT 1224.710 1497.720 1229.390 1499.245 ;
        RECT 1230.230 1497.720 1234.910 1499.245 ;
        RECT 1235.750 1497.720 1239.050 1499.245 ;
        RECT 1239.890 1497.720 1244.570 1499.245 ;
        RECT 1245.410 1497.720 1250.090 1499.245 ;
        RECT 1250.930 1497.720 1254.230 1499.245 ;
        RECT 1255.070 1497.720 1259.750 1499.245 ;
        RECT 1260.590 1497.720 1265.270 1499.245 ;
        RECT 1266.110 1497.720 1270.790 1499.245 ;
        RECT 1271.630 1497.720 1274.930 1499.245 ;
        RECT 1275.770 1497.720 1280.450 1499.245 ;
        RECT 1281.290 1497.720 1285.970 1499.245 ;
        RECT 1286.810 1497.720 1291.490 1499.245 ;
        RECT 1292.330 1497.720 1295.630 1499.245 ;
        RECT 1296.470 1497.720 1301.150 1499.245 ;
        RECT 1301.990 1497.720 1306.670 1499.245 ;
        RECT 1307.510 1497.720 1310.810 1499.245 ;
        RECT 1311.650 1497.720 1316.330 1499.245 ;
        RECT 1317.170 1497.720 1321.850 1499.245 ;
        RECT 1322.690 1497.720 1327.370 1499.245 ;
        RECT 1328.210 1497.720 1331.510 1499.245 ;
        RECT 1332.350 1497.720 1337.030 1499.245 ;
        RECT 1337.870 1497.720 1342.550 1499.245 ;
        RECT 1343.390 1497.720 1348.070 1499.245 ;
        RECT 1348.910 1497.720 1352.210 1499.245 ;
        RECT 1353.050 1497.720 1357.730 1499.245 ;
        RECT 1358.570 1497.720 1363.250 1499.245 ;
        RECT 1364.090 1497.720 1367.390 1499.245 ;
        RECT 1368.230 1497.720 1372.910 1499.245 ;
        RECT 1373.750 1497.720 1378.430 1499.245 ;
        RECT 1379.270 1497.720 1383.950 1499.245 ;
        RECT 1384.790 1497.720 1388.090 1499.245 ;
        RECT 1388.930 1497.720 1393.610 1499.245 ;
        RECT 1394.450 1497.720 1399.130 1499.245 ;
        RECT 1399.970 1497.720 1404.650 1499.245 ;
        RECT 1405.490 1497.720 1408.790 1499.245 ;
        RECT 1409.630 1497.720 1414.310 1499.245 ;
        RECT 1415.150 1497.720 1419.830 1499.245 ;
        RECT 1420.670 1497.720 1423.970 1499.245 ;
        RECT 1424.810 1497.720 1429.490 1499.245 ;
        RECT 1430.330 1497.720 1435.010 1499.245 ;
        RECT 1435.850 1497.720 1440.530 1499.245 ;
        RECT 1441.370 1497.720 1444.670 1499.245 ;
        RECT 1445.510 1497.720 1450.190 1499.245 ;
        RECT 1451.030 1497.720 1455.710 1499.245 ;
        RECT 1456.550 1497.720 1461.230 1499.245 ;
        RECT 1462.070 1497.720 1465.370 1499.245 ;
        RECT 1466.210 1497.720 1470.890 1499.245 ;
        RECT 1471.730 1497.720 1476.410 1499.245 ;
        RECT 1477.250 1497.720 1480.550 1499.245 ;
        RECT 1481.390 1497.720 1486.070 1499.245 ;
        RECT 1486.910 1497.720 1491.590 1499.245 ;
        RECT 1492.430 1497.720 1497.110 1499.245 ;
        RECT 1497.950 1497.720 1499.960 1499.245 ;
        RECT 0.100 2.280 1499.960 1497.720 ;
        RECT 0.650 0.155 3.950 2.280 ;
        RECT 4.790 0.155 9.470 2.280 ;
        RECT 10.310 0.155 14.990 2.280 ;
        RECT 15.830 0.155 19.130 2.280 ;
        RECT 19.970 0.155 24.650 2.280 ;
        RECT 25.490 0.155 30.170 2.280 ;
        RECT 31.010 0.155 35.690 2.280 ;
        RECT 36.530 0.155 39.830 2.280 ;
        RECT 40.670 0.155 45.350 2.280 ;
        RECT 46.190 0.155 50.870 2.280 ;
        RECT 51.710 0.155 56.390 2.280 ;
        RECT 57.230 0.155 60.530 2.280 ;
        RECT 61.370 0.155 66.050 2.280 ;
        RECT 66.890 0.155 71.570 2.280 ;
        RECT 72.410 0.155 75.710 2.280 ;
        RECT 76.550 0.155 81.230 2.280 ;
        RECT 82.070 0.155 86.750 2.280 ;
        RECT 87.590 0.155 92.270 2.280 ;
        RECT 93.110 0.155 96.410 2.280 ;
        RECT 97.250 0.155 101.930 2.280 ;
        RECT 102.770 0.155 107.450 2.280 ;
        RECT 108.290 0.155 112.970 2.280 ;
        RECT 113.810 0.155 117.110 2.280 ;
        RECT 117.950 0.155 122.630 2.280 ;
        RECT 123.470 0.155 128.150 2.280 ;
        RECT 128.990 0.155 132.290 2.280 ;
        RECT 133.130 0.155 137.810 2.280 ;
        RECT 138.650 0.155 143.330 2.280 ;
        RECT 144.170 0.155 148.850 2.280 ;
        RECT 149.690 0.155 152.990 2.280 ;
        RECT 153.830 0.155 158.510 2.280 ;
        RECT 159.350 0.155 164.030 2.280 ;
        RECT 164.870 0.155 169.550 2.280 ;
        RECT 170.390 0.155 173.690 2.280 ;
        RECT 174.530 0.155 179.210 2.280 ;
        RECT 180.050 0.155 184.730 2.280 ;
        RECT 185.570 0.155 188.870 2.280 ;
        RECT 189.710 0.155 194.390 2.280 ;
        RECT 195.230 0.155 199.910 2.280 ;
        RECT 200.750 0.155 205.430 2.280 ;
        RECT 206.270 0.155 209.570 2.280 ;
        RECT 210.410 0.155 215.090 2.280 ;
        RECT 215.930 0.155 220.610 2.280 ;
        RECT 221.450 0.155 226.130 2.280 ;
        RECT 226.970 0.155 230.270 2.280 ;
        RECT 231.110 0.155 235.790 2.280 ;
        RECT 236.630 0.155 241.310 2.280 ;
        RECT 242.150 0.155 245.450 2.280 ;
        RECT 246.290 0.155 250.970 2.280 ;
        RECT 251.810 0.155 256.490 2.280 ;
        RECT 257.330 0.155 262.010 2.280 ;
        RECT 262.850 0.155 266.150 2.280 ;
        RECT 266.990 0.155 271.670 2.280 ;
        RECT 272.510 0.155 277.190 2.280 ;
        RECT 278.030 0.155 282.710 2.280 ;
        RECT 283.550 0.155 286.850 2.280 ;
        RECT 287.690 0.155 292.370 2.280 ;
        RECT 293.210 0.155 297.890 2.280 ;
        RECT 298.730 0.155 302.030 2.280 ;
        RECT 302.870 0.155 307.550 2.280 ;
        RECT 308.390 0.155 313.070 2.280 ;
        RECT 313.910 0.155 318.590 2.280 ;
        RECT 319.430 0.155 322.730 2.280 ;
        RECT 323.570 0.155 328.250 2.280 ;
        RECT 329.090 0.155 333.770 2.280 ;
        RECT 334.610 0.155 339.290 2.280 ;
        RECT 340.130 0.155 343.430 2.280 ;
        RECT 344.270 0.155 348.950 2.280 ;
        RECT 349.790 0.155 354.470 2.280 ;
        RECT 355.310 0.155 358.610 2.280 ;
        RECT 359.450 0.155 364.130 2.280 ;
        RECT 364.970 0.155 369.650 2.280 ;
        RECT 370.490 0.155 375.170 2.280 ;
        RECT 376.010 0.155 379.310 2.280 ;
        RECT 380.150 0.155 384.830 2.280 ;
        RECT 385.670 0.155 390.350 2.280 ;
        RECT 391.190 0.155 395.870 2.280 ;
        RECT 396.710 0.155 400.010 2.280 ;
        RECT 400.850 0.155 405.530 2.280 ;
        RECT 406.370 0.155 411.050 2.280 ;
        RECT 411.890 0.155 415.190 2.280 ;
        RECT 416.030 0.155 420.710 2.280 ;
        RECT 421.550 0.155 426.230 2.280 ;
        RECT 427.070 0.155 431.750 2.280 ;
        RECT 432.590 0.155 435.890 2.280 ;
        RECT 436.730 0.155 441.410 2.280 ;
        RECT 442.250 0.155 446.930 2.280 ;
        RECT 447.770 0.155 452.450 2.280 ;
        RECT 453.290 0.155 456.590 2.280 ;
        RECT 457.430 0.155 462.110 2.280 ;
        RECT 462.950 0.155 467.630 2.280 ;
        RECT 468.470 0.155 471.770 2.280 ;
        RECT 472.610 0.155 477.290 2.280 ;
        RECT 478.130 0.155 482.810 2.280 ;
        RECT 483.650 0.155 488.330 2.280 ;
        RECT 489.170 0.155 492.470 2.280 ;
        RECT 493.310 0.155 497.990 2.280 ;
        RECT 498.830 0.155 503.510 2.280 ;
        RECT 504.350 0.155 509.030 2.280 ;
        RECT 509.870 0.155 513.170 2.280 ;
        RECT 514.010 0.155 518.690 2.280 ;
        RECT 519.530 0.155 524.210 2.280 ;
        RECT 525.050 0.155 528.350 2.280 ;
        RECT 529.190 0.155 533.870 2.280 ;
        RECT 534.710 0.155 539.390 2.280 ;
        RECT 540.230 0.155 544.910 2.280 ;
        RECT 545.750 0.155 549.050 2.280 ;
        RECT 549.890 0.155 554.570 2.280 ;
        RECT 555.410 0.155 560.090 2.280 ;
        RECT 560.930 0.155 565.610 2.280 ;
        RECT 566.450 0.155 569.750 2.280 ;
        RECT 570.590 0.155 575.270 2.280 ;
        RECT 576.110 0.155 580.790 2.280 ;
        RECT 581.630 0.155 584.930 2.280 ;
        RECT 585.770 0.155 590.450 2.280 ;
        RECT 591.290 0.155 595.970 2.280 ;
        RECT 596.810 0.155 601.490 2.280 ;
        RECT 602.330 0.155 605.630 2.280 ;
        RECT 606.470 0.155 611.150 2.280 ;
        RECT 611.990 0.155 616.670 2.280 ;
        RECT 617.510 0.155 622.190 2.280 ;
        RECT 623.030 0.155 626.330 2.280 ;
        RECT 627.170 0.155 631.850 2.280 ;
        RECT 632.690 0.155 637.370 2.280 ;
        RECT 638.210 0.155 641.510 2.280 ;
        RECT 642.350 0.155 647.030 2.280 ;
        RECT 647.870 0.155 652.550 2.280 ;
        RECT 653.390 0.155 658.070 2.280 ;
        RECT 658.910 0.155 662.210 2.280 ;
        RECT 663.050 0.155 667.730 2.280 ;
        RECT 668.570 0.155 673.250 2.280 ;
        RECT 674.090 0.155 678.770 2.280 ;
        RECT 679.610 0.155 682.910 2.280 ;
        RECT 683.750 0.155 688.430 2.280 ;
        RECT 689.270 0.155 693.950 2.280 ;
        RECT 694.790 0.155 698.090 2.280 ;
        RECT 698.930 0.155 703.610 2.280 ;
        RECT 704.450 0.155 709.130 2.280 ;
        RECT 709.970 0.155 714.650 2.280 ;
        RECT 715.490 0.155 718.790 2.280 ;
        RECT 719.630 0.155 724.310 2.280 ;
        RECT 725.150 0.155 729.830 2.280 ;
        RECT 730.670 0.155 735.350 2.280 ;
        RECT 736.190 0.155 739.490 2.280 ;
        RECT 740.330 0.155 745.010 2.280 ;
        RECT 745.850 0.155 750.530 2.280 ;
        RECT 751.370 0.155 754.670 2.280 ;
        RECT 755.510 0.155 760.190 2.280 ;
        RECT 761.030 0.155 765.710 2.280 ;
        RECT 766.550 0.155 771.230 2.280 ;
        RECT 772.070 0.155 775.370 2.280 ;
        RECT 776.210 0.155 780.890 2.280 ;
        RECT 781.730 0.155 786.410 2.280 ;
        RECT 787.250 0.155 791.930 2.280 ;
        RECT 792.770 0.155 796.070 2.280 ;
        RECT 796.910 0.155 801.590 2.280 ;
        RECT 802.430 0.155 807.110 2.280 ;
        RECT 807.950 0.155 811.250 2.280 ;
        RECT 812.090 0.155 816.770 2.280 ;
        RECT 817.610 0.155 822.290 2.280 ;
        RECT 823.130 0.155 827.810 2.280 ;
        RECT 828.650 0.155 831.950 2.280 ;
        RECT 832.790 0.155 837.470 2.280 ;
        RECT 838.310 0.155 842.990 2.280 ;
        RECT 843.830 0.155 848.510 2.280 ;
        RECT 849.350 0.155 852.650 2.280 ;
        RECT 853.490 0.155 858.170 2.280 ;
        RECT 859.010 0.155 863.690 2.280 ;
        RECT 864.530 0.155 867.830 2.280 ;
        RECT 868.670 0.155 873.350 2.280 ;
        RECT 874.190 0.155 878.870 2.280 ;
        RECT 879.710 0.155 884.390 2.280 ;
        RECT 885.230 0.155 888.530 2.280 ;
        RECT 889.370 0.155 894.050 2.280 ;
        RECT 894.890 0.155 899.570 2.280 ;
        RECT 900.410 0.155 905.090 2.280 ;
        RECT 905.930 0.155 909.230 2.280 ;
        RECT 910.070 0.155 914.750 2.280 ;
        RECT 915.590 0.155 920.270 2.280 ;
        RECT 921.110 0.155 924.410 2.280 ;
        RECT 925.250 0.155 929.930 2.280 ;
        RECT 930.770 0.155 935.450 2.280 ;
        RECT 936.290 0.155 940.970 2.280 ;
        RECT 941.810 0.155 945.110 2.280 ;
        RECT 945.950 0.155 950.630 2.280 ;
        RECT 951.470 0.155 956.150 2.280 ;
        RECT 956.990 0.155 961.670 2.280 ;
        RECT 962.510 0.155 965.810 2.280 ;
        RECT 966.650 0.155 971.330 2.280 ;
        RECT 972.170 0.155 976.850 2.280 ;
        RECT 977.690 0.155 980.990 2.280 ;
        RECT 981.830 0.155 986.510 2.280 ;
        RECT 987.350 0.155 992.030 2.280 ;
        RECT 992.870 0.155 997.550 2.280 ;
        RECT 998.390 0.155 1001.690 2.280 ;
        RECT 1002.530 0.155 1007.210 2.280 ;
        RECT 1008.050 0.155 1012.730 2.280 ;
        RECT 1013.570 0.155 1018.250 2.280 ;
        RECT 1019.090 0.155 1022.390 2.280 ;
        RECT 1023.230 0.155 1027.910 2.280 ;
        RECT 1028.750 0.155 1033.430 2.280 ;
        RECT 1034.270 0.155 1037.570 2.280 ;
        RECT 1038.410 0.155 1043.090 2.280 ;
        RECT 1043.930 0.155 1048.610 2.280 ;
        RECT 1049.450 0.155 1054.130 2.280 ;
        RECT 1054.970 0.155 1058.270 2.280 ;
        RECT 1059.110 0.155 1063.790 2.280 ;
        RECT 1064.630 0.155 1069.310 2.280 ;
        RECT 1070.150 0.155 1074.830 2.280 ;
        RECT 1075.670 0.155 1078.970 2.280 ;
        RECT 1079.810 0.155 1084.490 2.280 ;
        RECT 1085.330 0.155 1090.010 2.280 ;
        RECT 1090.850 0.155 1094.150 2.280 ;
        RECT 1094.990 0.155 1099.670 2.280 ;
        RECT 1100.510 0.155 1105.190 2.280 ;
        RECT 1106.030 0.155 1110.710 2.280 ;
        RECT 1111.550 0.155 1114.850 2.280 ;
        RECT 1115.690 0.155 1120.370 2.280 ;
        RECT 1121.210 0.155 1125.890 2.280 ;
        RECT 1126.730 0.155 1131.410 2.280 ;
        RECT 1132.250 0.155 1135.550 2.280 ;
        RECT 1136.390 0.155 1141.070 2.280 ;
        RECT 1141.910 0.155 1146.590 2.280 ;
        RECT 1147.430 0.155 1150.730 2.280 ;
        RECT 1151.570 0.155 1156.250 2.280 ;
        RECT 1157.090 0.155 1161.770 2.280 ;
        RECT 1162.610 0.155 1167.290 2.280 ;
        RECT 1168.130 0.155 1171.430 2.280 ;
        RECT 1172.270 0.155 1176.950 2.280 ;
        RECT 1177.790 0.155 1182.470 2.280 ;
        RECT 1183.310 0.155 1187.990 2.280 ;
        RECT 1188.830 0.155 1192.130 2.280 ;
        RECT 1192.970 0.155 1197.650 2.280 ;
        RECT 1198.490 0.155 1203.170 2.280 ;
        RECT 1204.010 0.155 1208.690 2.280 ;
        RECT 1209.530 0.155 1212.830 2.280 ;
        RECT 1213.670 0.155 1218.350 2.280 ;
        RECT 1219.190 0.155 1223.870 2.280 ;
        RECT 1224.710 0.155 1228.010 2.280 ;
        RECT 1228.850 0.155 1233.530 2.280 ;
        RECT 1234.370 0.155 1239.050 2.280 ;
        RECT 1239.890 0.155 1244.570 2.280 ;
        RECT 1245.410 0.155 1248.710 2.280 ;
        RECT 1249.550 0.155 1254.230 2.280 ;
        RECT 1255.070 0.155 1259.750 2.280 ;
        RECT 1260.590 0.155 1265.270 2.280 ;
        RECT 1266.110 0.155 1269.410 2.280 ;
        RECT 1270.250 0.155 1274.930 2.280 ;
        RECT 1275.770 0.155 1280.450 2.280 ;
        RECT 1281.290 0.155 1284.590 2.280 ;
        RECT 1285.430 0.155 1290.110 2.280 ;
        RECT 1290.950 0.155 1295.630 2.280 ;
        RECT 1296.470 0.155 1301.150 2.280 ;
        RECT 1301.990 0.155 1305.290 2.280 ;
        RECT 1306.130 0.155 1310.810 2.280 ;
        RECT 1311.650 0.155 1316.330 2.280 ;
        RECT 1317.170 0.155 1321.850 2.280 ;
        RECT 1322.690 0.155 1325.990 2.280 ;
        RECT 1326.830 0.155 1331.510 2.280 ;
        RECT 1332.350 0.155 1337.030 2.280 ;
        RECT 1337.870 0.155 1341.170 2.280 ;
        RECT 1342.010 0.155 1346.690 2.280 ;
        RECT 1347.530 0.155 1352.210 2.280 ;
        RECT 1353.050 0.155 1357.730 2.280 ;
        RECT 1358.570 0.155 1361.870 2.280 ;
        RECT 1362.710 0.155 1367.390 2.280 ;
        RECT 1368.230 0.155 1372.910 2.280 ;
        RECT 1373.750 0.155 1378.430 2.280 ;
        RECT 1379.270 0.155 1382.570 2.280 ;
        RECT 1383.410 0.155 1388.090 2.280 ;
        RECT 1388.930 0.155 1393.610 2.280 ;
        RECT 1394.450 0.155 1397.750 2.280 ;
        RECT 1398.590 0.155 1403.270 2.280 ;
        RECT 1404.110 0.155 1408.790 2.280 ;
        RECT 1409.630 0.155 1414.310 2.280 ;
        RECT 1415.150 0.155 1418.450 2.280 ;
        RECT 1419.290 0.155 1423.970 2.280 ;
        RECT 1424.810 0.155 1429.490 2.280 ;
        RECT 1430.330 0.155 1435.010 2.280 ;
        RECT 1435.850 0.155 1439.150 2.280 ;
        RECT 1439.990 0.155 1444.670 2.280 ;
        RECT 1445.510 0.155 1450.190 2.280 ;
        RECT 1451.030 0.155 1454.330 2.280 ;
        RECT 1455.170 0.155 1459.850 2.280 ;
        RECT 1460.690 0.155 1465.370 2.280 ;
        RECT 1466.210 0.155 1470.890 2.280 ;
        RECT 1471.730 0.155 1475.030 2.280 ;
        RECT 1475.870 0.155 1480.550 2.280 ;
        RECT 1481.390 0.155 1486.070 2.280 ;
        RECT 1486.910 0.155 1491.590 2.280 ;
        RECT 1492.430 0.155 1495.730 2.280 ;
        RECT 1496.570 0.155 1499.960 2.280 ;
      LAYER met3 ;
        RECT 2.000 1498.400 1499.535 1499.225 ;
        RECT 2.000 1497.000 1497.600 1498.400 ;
        RECT 2.000 1495.680 1499.535 1497.000 ;
        RECT 2.400 1494.280 1499.535 1495.680 ;
        RECT 2.000 1492.960 1499.535 1494.280 ;
        RECT 2.000 1491.560 1497.600 1492.960 ;
        RECT 2.000 1490.240 1499.535 1491.560 ;
        RECT 2.400 1488.840 1499.535 1490.240 ;
        RECT 2.000 1487.520 1499.535 1488.840 ;
        RECT 2.000 1486.160 1497.600 1487.520 ;
        RECT 2.400 1486.120 1497.600 1486.160 ;
        RECT 2.400 1484.760 1499.535 1486.120 ;
        RECT 2.000 1482.080 1499.535 1484.760 ;
        RECT 2.000 1480.720 1497.600 1482.080 ;
        RECT 2.400 1480.680 1497.600 1480.720 ;
        RECT 2.400 1479.320 1499.535 1480.680 ;
        RECT 2.000 1478.000 1499.535 1479.320 ;
        RECT 2.000 1476.600 1497.600 1478.000 ;
        RECT 2.000 1475.280 1499.535 1476.600 ;
        RECT 2.400 1473.880 1499.535 1475.280 ;
        RECT 2.000 1472.560 1499.535 1473.880 ;
        RECT 2.000 1471.200 1497.600 1472.560 ;
        RECT 2.400 1471.160 1497.600 1471.200 ;
        RECT 2.400 1469.800 1499.535 1471.160 ;
        RECT 2.000 1467.120 1499.535 1469.800 ;
        RECT 2.000 1465.760 1497.600 1467.120 ;
        RECT 2.400 1465.720 1497.600 1465.760 ;
        RECT 2.400 1464.360 1499.535 1465.720 ;
        RECT 2.000 1463.040 1499.535 1464.360 ;
        RECT 2.000 1461.640 1497.600 1463.040 ;
        RECT 2.000 1460.320 1499.535 1461.640 ;
        RECT 2.400 1458.920 1499.535 1460.320 ;
        RECT 2.000 1457.600 1499.535 1458.920 ;
        RECT 2.000 1456.200 1497.600 1457.600 ;
        RECT 2.000 1454.880 1499.535 1456.200 ;
        RECT 2.400 1453.480 1499.535 1454.880 ;
        RECT 2.000 1452.160 1499.535 1453.480 ;
        RECT 2.000 1450.800 1497.600 1452.160 ;
        RECT 2.400 1450.760 1497.600 1450.800 ;
        RECT 2.400 1449.400 1499.535 1450.760 ;
        RECT 2.000 1446.720 1499.535 1449.400 ;
        RECT 2.000 1445.360 1497.600 1446.720 ;
        RECT 2.400 1445.320 1497.600 1445.360 ;
        RECT 2.400 1443.960 1499.535 1445.320 ;
        RECT 2.000 1442.640 1499.535 1443.960 ;
        RECT 2.000 1441.240 1497.600 1442.640 ;
        RECT 2.000 1439.920 1499.535 1441.240 ;
        RECT 2.400 1438.520 1499.535 1439.920 ;
        RECT 2.000 1437.200 1499.535 1438.520 ;
        RECT 2.000 1435.800 1497.600 1437.200 ;
        RECT 2.000 1434.480 1499.535 1435.800 ;
        RECT 2.400 1433.080 1499.535 1434.480 ;
        RECT 2.000 1431.760 1499.535 1433.080 ;
        RECT 2.000 1430.400 1497.600 1431.760 ;
        RECT 2.400 1430.360 1497.600 1430.400 ;
        RECT 2.400 1429.000 1499.535 1430.360 ;
        RECT 2.000 1426.320 1499.535 1429.000 ;
        RECT 2.000 1424.960 1497.600 1426.320 ;
        RECT 2.400 1424.920 1497.600 1424.960 ;
        RECT 2.400 1423.560 1499.535 1424.920 ;
        RECT 2.000 1422.240 1499.535 1423.560 ;
        RECT 2.000 1420.840 1497.600 1422.240 ;
        RECT 2.000 1419.520 1499.535 1420.840 ;
        RECT 2.400 1418.120 1499.535 1419.520 ;
        RECT 2.000 1416.800 1499.535 1418.120 ;
        RECT 2.000 1415.440 1497.600 1416.800 ;
        RECT 2.400 1415.400 1497.600 1415.440 ;
        RECT 2.400 1414.040 1499.535 1415.400 ;
        RECT 2.000 1411.360 1499.535 1414.040 ;
        RECT 2.000 1410.000 1497.600 1411.360 ;
        RECT 2.400 1409.960 1497.600 1410.000 ;
        RECT 2.400 1408.600 1499.535 1409.960 ;
        RECT 2.000 1407.280 1499.535 1408.600 ;
        RECT 2.000 1405.880 1497.600 1407.280 ;
        RECT 2.000 1404.560 1499.535 1405.880 ;
        RECT 2.400 1403.160 1499.535 1404.560 ;
        RECT 2.000 1401.840 1499.535 1403.160 ;
        RECT 2.000 1400.440 1497.600 1401.840 ;
        RECT 2.000 1399.120 1499.535 1400.440 ;
        RECT 2.400 1397.720 1499.535 1399.120 ;
        RECT 2.000 1396.400 1499.535 1397.720 ;
        RECT 2.000 1395.040 1497.600 1396.400 ;
        RECT 2.400 1395.000 1497.600 1395.040 ;
        RECT 2.400 1393.640 1499.535 1395.000 ;
        RECT 2.000 1390.960 1499.535 1393.640 ;
        RECT 2.000 1389.600 1497.600 1390.960 ;
        RECT 2.400 1389.560 1497.600 1389.600 ;
        RECT 2.400 1388.200 1499.535 1389.560 ;
        RECT 2.000 1386.880 1499.535 1388.200 ;
        RECT 2.000 1385.480 1497.600 1386.880 ;
        RECT 2.000 1384.160 1499.535 1385.480 ;
        RECT 2.400 1382.760 1499.535 1384.160 ;
        RECT 2.000 1381.440 1499.535 1382.760 ;
        RECT 2.000 1380.040 1497.600 1381.440 ;
        RECT 2.000 1378.720 1499.535 1380.040 ;
        RECT 2.400 1377.320 1499.535 1378.720 ;
        RECT 2.000 1376.000 1499.535 1377.320 ;
        RECT 2.000 1374.640 1497.600 1376.000 ;
        RECT 2.400 1374.600 1497.600 1374.640 ;
        RECT 2.400 1373.240 1499.535 1374.600 ;
        RECT 2.000 1370.560 1499.535 1373.240 ;
        RECT 2.000 1369.200 1497.600 1370.560 ;
        RECT 2.400 1369.160 1497.600 1369.200 ;
        RECT 2.400 1367.800 1499.535 1369.160 ;
        RECT 2.000 1366.480 1499.535 1367.800 ;
        RECT 2.000 1365.080 1497.600 1366.480 ;
        RECT 2.000 1363.760 1499.535 1365.080 ;
        RECT 2.400 1362.360 1499.535 1363.760 ;
        RECT 2.000 1361.040 1499.535 1362.360 ;
        RECT 2.000 1359.680 1497.600 1361.040 ;
        RECT 2.400 1359.640 1497.600 1359.680 ;
        RECT 2.400 1358.280 1499.535 1359.640 ;
        RECT 2.000 1355.600 1499.535 1358.280 ;
        RECT 2.000 1354.240 1497.600 1355.600 ;
        RECT 2.400 1354.200 1497.600 1354.240 ;
        RECT 2.400 1352.840 1499.535 1354.200 ;
        RECT 2.000 1351.520 1499.535 1352.840 ;
        RECT 2.000 1350.120 1497.600 1351.520 ;
        RECT 2.000 1348.800 1499.535 1350.120 ;
        RECT 2.400 1347.400 1499.535 1348.800 ;
        RECT 2.000 1346.080 1499.535 1347.400 ;
        RECT 2.000 1344.680 1497.600 1346.080 ;
        RECT 2.000 1343.360 1499.535 1344.680 ;
        RECT 2.400 1341.960 1499.535 1343.360 ;
        RECT 2.000 1340.640 1499.535 1341.960 ;
        RECT 2.000 1339.280 1497.600 1340.640 ;
        RECT 2.400 1339.240 1497.600 1339.280 ;
        RECT 2.400 1337.880 1499.535 1339.240 ;
        RECT 2.000 1335.200 1499.535 1337.880 ;
        RECT 2.000 1333.840 1497.600 1335.200 ;
        RECT 2.400 1333.800 1497.600 1333.840 ;
        RECT 2.400 1332.440 1499.535 1333.800 ;
        RECT 2.000 1331.120 1499.535 1332.440 ;
        RECT 2.000 1329.720 1497.600 1331.120 ;
        RECT 2.000 1328.400 1499.535 1329.720 ;
        RECT 2.400 1327.000 1499.535 1328.400 ;
        RECT 2.000 1325.680 1499.535 1327.000 ;
        RECT 2.000 1324.280 1497.600 1325.680 ;
        RECT 2.000 1322.960 1499.535 1324.280 ;
        RECT 2.400 1321.560 1499.535 1322.960 ;
        RECT 2.000 1320.240 1499.535 1321.560 ;
        RECT 2.000 1318.880 1497.600 1320.240 ;
        RECT 2.400 1318.840 1497.600 1318.880 ;
        RECT 2.400 1317.480 1499.535 1318.840 ;
        RECT 2.000 1314.800 1499.535 1317.480 ;
        RECT 2.000 1313.440 1497.600 1314.800 ;
        RECT 2.400 1313.400 1497.600 1313.440 ;
        RECT 2.400 1312.040 1499.535 1313.400 ;
        RECT 2.000 1310.720 1499.535 1312.040 ;
        RECT 2.000 1309.320 1497.600 1310.720 ;
        RECT 2.000 1308.000 1499.535 1309.320 ;
        RECT 2.400 1306.600 1499.535 1308.000 ;
        RECT 2.000 1305.280 1499.535 1306.600 ;
        RECT 2.000 1303.920 1497.600 1305.280 ;
        RECT 2.400 1303.880 1497.600 1303.920 ;
        RECT 2.400 1302.520 1499.535 1303.880 ;
        RECT 2.000 1299.840 1499.535 1302.520 ;
        RECT 2.000 1298.480 1497.600 1299.840 ;
        RECT 2.400 1298.440 1497.600 1298.480 ;
        RECT 2.400 1297.080 1499.535 1298.440 ;
        RECT 2.000 1295.760 1499.535 1297.080 ;
        RECT 2.000 1294.360 1497.600 1295.760 ;
        RECT 2.000 1293.040 1499.535 1294.360 ;
        RECT 2.400 1291.640 1499.535 1293.040 ;
        RECT 2.000 1290.320 1499.535 1291.640 ;
        RECT 2.000 1288.920 1497.600 1290.320 ;
        RECT 2.000 1287.600 1499.535 1288.920 ;
        RECT 2.400 1286.200 1499.535 1287.600 ;
        RECT 2.000 1284.880 1499.535 1286.200 ;
        RECT 2.000 1283.520 1497.600 1284.880 ;
        RECT 2.400 1283.480 1497.600 1283.520 ;
        RECT 2.400 1282.120 1499.535 1283.480 ;
        RECT 2.000 1279.440 1499.535 1282.120 ;
        RECT 2.000 1278.080 1497.600 1279.440 ;
        RECT 2.400 1278.040 1497.600 1278.080 ;
        RECT 2.400 1276.680 1499.535 1278.040 ;
        RECT 2.000 1275.360 1499.535 1276.680 ;
        RECT 2.000 1273.960 1497.600 1275.360 ;
        RECT 2.000 1272.640 1499.535 1273.960 ;
        RECT 2.400 1271.240 1499.535 1272.640 ;
        RECT 2.000 1269.920 1499.535 1271.240 ;
        RECT 2.000 1268.520 1497.600 1269.920 ;
        RECT 2.000 1267.200 1499.535 1268.520 ;
        RECT 2.400 1265.800 1499.535 1267.200 ;
        RECT 2.000 1264.480 1499.535 1265.800 ;
        RECT 2.000 1263.120 1497.600 1264.480 ;
        RECT 2.400 1263.080 1497.600 1263.120 ;
        RECT 2.400 1261.720 1499.535 1263.080 ;
        RECT 2.000 1259.040 1499.535 1261.720 ;
        RECT 2.000 1257.680 1497.600 1259.040 ;
        RECT 2.400 1257.640 1497.600 1257.680 ;
        RECT 2.400 1256.280 1499.535 1257.640 ;
        RECT 2.000 1254.960 1499.535 1256.280 ;
        RECT 2.000 1253.560 1497.600 1254.960 ;
        RECT 2.000 1252.240 1499.535 1253.560 ;
        RECT 2.400 1250.840 1499.535 1252.240 ;
        RECT 2.000 1249.520 1499.535 1250.840 ;
        RECT 2.000 1248.160 1497.600 1249.520 ;
        RECT 2.400 1248.120 1497.600 1248.160 ;
        RECT 2.400 1246.760 1499.535 1248.120 ;
        RECT 2.000 1244.080 1499.535 1246.760 ;
        RECT 2.000 1242.720 1497.600 1244.080 ;
        RECT 2.400 1242.680 1497.600 1242.720 ;
        RECT 2.400 1241.320 1499.535 1242.680 ;
        RECT 2.000 1240.000 1499.535 1241.320 ;
        RECT 2.000 1238.600 1497.600 1240.000 ;
        RECT 2.000 1237.280 1499.535 1238.600 ;
        RECT 2.400 1235.880 1499.535 1237.280 ;
        RECT 2.000 1234.560 1499.535 1235.880 ;
        RECT 2.000 1233.160 1497.600 1234.560 ;
        RECT 2.000 1231.840 1499.535 1233.160 ;
        RECT 2.400 1230.440 1499.535 1231.840 ;
        RECT 2.000 1229.120 1499.535 1230.440 ;
        RECT 2.000 1227.760 1497.600 1229.120 ;
        RECT 2.400 1227.720 1497.600 1227.760 ;
        RECT 2.400 1226.360 1499.535 1227.720 ;
        RECT 2.000 1223.680 1499.535 1226.360 ;
        RECT 2.000 1222.320 1497.600 1223.680 ;
        RECT 2.400 1222.280 1497.600 1222.320 ;
        RECT 2.400 1220.920 1499.535 1222.280 ;
        RECT 2.000 1219.600 1499.535 1220.920 ;
        RECT 2.000 1218.200 1497.600 1219.600 ;
        RECT 2.000 1216.880 1499.535 1218.200 ;
        RECT 2.400 1215.480 1499.535 1216.880 ;
        RECT 2.000 1214.160 1499.535 1215.480 ;
        RECT 2.000 1212.760 1497.600 1214.160 ;
        RECT 2.000 1211.440 1499.535 1212.760 ;
        RECT 2.400 1210.040 1499.535 1211.440 ;
        RECT 2.000 1208.720 1499.535 1210.040 ;
        RECT 2.000 1207.360 1497.600 1208.720 ;
        RECT 2.400 1207.320 1497.600 1207.360 ;
        RECT 2.400 1205.960 1499.535 1207.320 ;
        RECT 2.000 1203.280 1499.535 1205.960 ;
        RECT 2.000 1201.920 1497.600 1203.280 ;
        RECT 2.400 1201.880 1497.600 1201.920 ;
        RECT 2.400 1200.520 1499.535 1201.880 ;
        RECT 2.000 1199.200 1499.535 1200.520 ;
        RECT 2.000 1197.800 1497.600 1199.200 ;
        RECT 2.000 1196.480 1499.535 1197.800 ;
        RECT 2.400 1195.080 1499.535 1196.480 ;
        RECT 2.000 1193.760 1499.535 1195.080 ;
        RECT 2.000 1192.360 1497.600 1193.760 ;
        RECT 2.000 1191.040 1499.535 1192.360 ;
        RECT 2.400 1189.640 1499.535 1191.040 ;
        RECT 2.000 1188.320 1499.535 1189.640 ;
        RECT 2.000 1186.960 1497.600 1188.320 ;
        RECT 2.400 1186.920 1497.600 1186.960 ;
        RECT 2.400 1185.560 1499.535 1186.920 ;
        RECT 2.000 1184.240 1499.535 1185.560 ;
        RECT 2.000 1182.840 1497.600 1184.240 ;
        RECT 2.000 1181.520 1499.535 1182.840 ;
        RECT 2.400 1180.120 1499.535 1181.520 ;
        RECT 2.000 1178.800 1499.535 1180.120 ;
        RECT 2.000 1177.400 1497.600 1178.800 ;
        RECT 2.000 1176.080 1499.535 1177.400 ;
        RECT 2.400 1174.680 1499.535 1176.080 ;
        RECT 2.000 1173.360 1499.535 1174.680 ;
        RECT 2.000 1172.000 1497.600 1173.360 ;
        RECT 2.400 1171.960 1497.600 1172.000 ;
        RECT 2.400 1170.600 1499.535 1171.960 ;
        RECT 2.000 1167.920 1499.535 1170.600 ;
        RECT 2.000 1166.560 1497.600 1167.920 ;
        RECT 2.400 1166.520 1497.600 1166.560 ;
        RECT 2.400 1165.160 1499.535 1166.520 ;
        RECT 2.000 1163.840 1499.535 1165.160 ;
        RECT 2.000 1162.440 1497.600 1163.840 ;
        RECT 2.000 1161.120 1499.535 1162.440 ;
        RECT 2.400 1159.720 1499.535 1161.120 ;
        RECT 2.000 1158.400 1499.535 1159.720 ;
        RECT 2.000 1157.000 1497.600 1158.400 ;
        RECT 2.000 1155.680 1499.535 1157.000 ;
        RECT 2.400 1154.280 1499.535 1155.680 ;
        RECT 2.000 1152.960 1499.535 1154.280 ;
        RECT 2.000 1151.600 1497.600 1152.960 ;
        RECT 2.400 1151.560 1497.600 1151.600 ;
        RECT 2.400 1150.200 1499.535 1151.560 ;
        RECT 2.000 1147.520 1499.535 1150.200 ;
        RECT 2.000 1146.160 1497.600 1147.520 ;
        RECT 2.400 1146.120 1497.600 1146.160 ;
        RECT 2.400 1144.760 1499.535 1146.120 ;
        RECT 2.000 1143.440 1499.535 1144.760 ;
        RECT 2.000 1142.040 1497.600 1143.440 ;
        RECT 2.000 1140.720 1499.535 1142.040 ;
        RECT 2.400 1139.320 1499.535 1140.720 ;
        RECT 2.000 1138.000 1499.535 1139.320 ;
        RECT 2.000 1136.600 1497.600 1138.000 ;
        RECT 2.000 1135.280 1499.535 1136.600 ;
        RECT 2.400 1133.880 1499.535 1135.280 ;
        RECT 2.000 1132.560 1499.535 1133.880 ;
        RECT 2.000 1131.200 1497.600 1132.560 ;
        RECT 2.400 1131.160 1497.600 1131.200 ;
        RECT 2.400 1129.800 1499.535 1131.160 ;
        RECT 2.000 1128.480 1499.535 1129.800 ;
        RECT 2.000 1127.080 1497.600 1128.480 ;
        RECT 2.000 1125.760 1499.535 1127.080 ;
        RECT 2.400 1124.360 1499.535 1125.760 ;
        RECT 2.000 1123.040 1499.535 1124.360 ;
        RECT 2.000 1121.640 1497.600 1123.040 ;
        RECT 2.000 1120.320 1499.535 1121.640 ;
        RECT 2.400 1118.920 1499.535 1120.320 ;
        RECT 2.000 1117.600 1499.535 1118.920 ;
        RECT 2.000 1116.240 1497.600 1117.600 ;
        RECT 2.400 1116.200 1497.600 1116.240 ;
        RECT 2.400 1114.840 1499.535 1116.200 ;
        RECT 2.000 1112.160 1499.535 1114.840 ;
        RECT 2.000 1110.800 1497.600 1112.160 ;
        RECT 2.400 1110.760 1497.600 1110.800 ;
        RECT 2.400 1109.400 1499.535 1110.760 ;
        RECT 2.000 1108.080 1499.535 1109.400 ;
        RECT 2.000 1106.680 1497.600 1108.080 ;
        RECT 2.000 1105.360 1499.535 1106.680 ;
        RECT 2.400 1103.960 1499.535 1105.360 ;
        RECT 2.000 1102.640 1499.535 1103.960 ;
        RECT 2.000 1101.240 1497.600 1102.640 ;
        RECT 2.000 1099.920 1499.535 1101.240 ;
        RECT 2.400 1098.520 1499.535 1099.920 ;
        RECT 2.000 1097.200 1499.535 1098.520 ;
        RECT 2.000 1095.840 1497.600 1097.200 ;
        RECT 2.400 1095.800 1497.600 1095.840 ;
        RECT 2.400 1094.440 1499.535 1095.800 ;
        RECT 2.000 1091.760 1499.535 1094.440 ;
        RECT 2.000 1090.400 1497.600 1091.760 ;
        RECT 2.400 1090.360 1497.600 1090.400 ;
        RECT 2.400 1089.000 1499.535 1090.360 ;
        RECT 2.000 1087.680 1499.535 1089.000 ;
        RECT 2.000 1086.280 1497.600 1087.680 ;
        RECT 2.000 1084.960 1499.535 1086.280 ;
        RECT 2.400 1083.560 1499.535 1084.960 ;
        RECT 2.000 1082.240 1499.535 1083.560 ;
        RECT 2.000 1080.840 1497.600 1082.240 ;
        RECT 2.000 1079.520 1499.535 1080.840 ;
        RECT 2.400 1078.120 1499.535 1079.520 ;
        RECT 2.000 1076.800 1499.535 1078.120 ;
        RECT 2.000 1075.440 1497.600 1076.800 ;
        RECT 2.400 1075.400 1497.600 1075.440 ;
        RECT 2.400 1074.040 1499.535 1075.400 ;
        RECT 2.000 1072.720 1499.535 1074.040 ;
        RECT 2.000 1071.320 1497.600 1072.720 ;
        RECT 2.000 1070.000 1499.535 1071.320 ;
        RECT 2.400 1068.600 1499.535 1070.000 ;
        RECT 2.000 1067.280 1499.535 1068.600 ;
        RECT 2.000 1065.880 1497.600 1067.280 ;
        RECT 2.000 1064.560 1499.535 1065.880 ;
        RECT 2.400 1063.160 1499.535 1064.560 ;
        RECT 2.000 1061.840 1499.535 1063.160 ;
        RECT 2.000 1060.480 1497.600 1061.840 ;
        RECT 2.400 1060.440 1497.600 1060.480 ;
        RECT 2.400 1059.080 1499.535 1060.440 ;
        RECT 2.000 1056.400 1499.535 1059.080 ;
        RECT 2.000 1055.040 1497.600 1056.400 ;
        RECT 2.400 1055.000 1497.600 1055.040 ;
        RECT 2.400 1053.640 1499.535 1055.000 ;
        RECT 2.000 1052.320 1499.535 1053.640 ;
        RECT 2.000 1050.920 1497.600 1052.320 ;
        RECT 2.000 1049.600 1499.535 1050.920 ;
        RECT 2.400 1048.200 1499.535 1049.600 ;
        RECT 2.000 1046.880 1499.535 1048.200 ;
        RECT 2.000 1045.480 1497.600 1046.880 ;
        RECT 2.000 1044.160 1499.535 1045.480 ;
        RECT 2.400 1042.760 1499.535 1044.160 ;
        RECT 2.000 1041.440 1499.535 1042.760 ;
        RECT 2.000 1040.080 1497.600 1041.440 ;
        RECT 2.400 1040.040 1497.600 1040.080 ;
        RECT 2.400 1038.680 1499.535 1040.040 ;
        RECT 2.000 1036.000 1499.535 1038.680 ;
        RECT 2.000 1034.640 1497.600 1036.000 ;
        RECT 2.400 1034.600 1497.600 1034.640 ;
        RECT 2.400 1033.240 1499.535 1034.600 ;
        RECT 2.000 1031.920 1499.535 1033.240 ;
        RECT 2.000 1030.520 1497.600 1031.920 ;
        RECT 2.000 1029.200 1499.535 1030.520 ;
        RECT 2.400 1027.800 1499.535 1029.200 ;
        RECT 2.000 1026.480 1499.535 1027.800 ;
        RECT 2.000 1025.080 1497.600 1026.480 ;
        RECT 2.000 1023.760 1499.535 1025.080 ;
        RECT 2.400 1022.360 1499.535 1023.760 ;
        RECT 2.000 1021.040 1499.535 1022.360 ;
        RECT 2.000 1019.680 1497.600 1021.040 ;
        RECT 2.400 1019.640 1497.600 1019.680 ;
        RECT 2.400 1018.280 1499.535 1019.640 ;
        RECT 2.000 1016.960 1499.535 1018.280 ;
        RECT 2.000 1015.560 1497.600 1016.960 ;
        RECT 2.000 1014.240 1499.535 1015.560 ;
        RECT 2.400 1012.840 1499.535 1014.240 ;
        RECT 2.000 1011.520 1499.535 1012.840 ;
        RECT 2.000 1010.120 1497.600 1011.520 ;
        RECT 2.000 1008.800 1499.535 1010.120 ;
        RECT 2.400 1007.400 1499.535 1008.800 ;
        RECT 2.000 1006.080 1499.535 1007.400 ;
        RECT 2.000 1004.720 1497.600 1006.080 ;
        RECT 2.400 1004.680 1497.600 1004.720 ;
        RECT 2.400 1003.320 1499.535 1004.680 ;
        RECT 2.000 1000.640 1499.535 1003.320 ;
        RECT 2.000 999.280 1497.600 1000.640 ;
        RECT 2.400 999.240 1497.600 999.280 ;
        RECT 2.400 997.880 1499.535 999.240 ;
        RECT 2.000 996.560 1499.535 997.880 ;
        RECT 2.000 995.160 1497.600 996.560 ;
        RECT 2.000 993.840 1499.535 995.160 ;
        RECT 2.400 992.440 1499.535 993.840 ;
        RECT 2.000 991.120 1499.535 992.440 ;
        RECT 2.000 989.720 1497.600 991.120 ;
        RECT 2.000 988.400 1499.535 989.720 ;
        RECT 2.400 987.000 1499.535 988.400 ;
        RECT 2.000 985.680 1499.535 987.000 ;
        RECT 2.000 984.320 1497.600 985.680 ;
        RECT 2.400 984.280 1497.600 984.320 ;
        RECT 2.400 982.920 1499.535 984.280 ;
        RECT 2.000 980.240 1499.535 982.920 ;
        RECT 2.000 978.880 1497.600 980.240 ;
        RECT 2.400 978.840 1497.600 978.880 ;
        RECT 2.400 977.480 1499.535 978.840 ;
        RECT 2.000 976.160 1499.535 977.480 ;
        RECT 2.000 974.760 1497.600 976.160 ;
        RECT 2.000 973.440 1499.535 974.760 ;
        RECT 2.400 972.040 1499.535 973.440 ;
        RECT 2.000 970.720 1499.535 972.040 ;
        RECT 2.000 969.320 1497.600 970.720 ;
        RECT 2.000 968.000 1499.535 969.320 ;
        RECT 2.400 966.600 1499.535 968.000 ;
        RECT 2.000 965.280 1499.535 966.600 ;
        RECT 2.000 963.920 1497.600 965.280 ;
        RECT 2.400 963.880 1497.600 963.920 ;
        RECT 2.400 962.520 1499.535 963.880 ;
        RECT 2.000 961.200 1499.535 962.520 ;
        RECT 2.000 959.800 1497.600 961.200 ;
        RECT 2.000 958.480 1499.535 959.800 ;
        RECT 2.400 957.080 1499.535 958.480 ;
        RECT 2.000 955.760 1499.535 957.080 ;
        RECT 2.000 954.360 1497.600 955.760 ;
        RECT 2.000 953.040 1499.535 954.360 ;
        RECT 2.400 951.640 1499.535 953.040 ;
        RECT 2.000 950.320 1499.535 951.640 ;
        RECT 2.000 948.960 1497.600 950.320 ;
        RECT 2.400 948.920 1497.600 948.960 ;
        RECT 2.400 947.560 1499.535 948.920 ;
        RECT 2.000 944.880 1499.535 947.560 ;
        RECT 2.000 943.520 1497.600 944.880 ;
        RECT 2.400 943.480 1497.600 943.520 ;
        RECT 2.400 942.120 1499.535 943.480 ;
        RECT 2.000 940.800 1499.535 942.120 ;
        RECT 2.000 939.400 1497.600 940.800 ;
        RECT 2.000 938.080 1499.535 939.400 ;
        RECT 2.400 936.680 1499.535 938.080 ;
        RECT 2.000 935.360 1499.535 936.680 ;
        RECT 2.000 933.960 1497.600 935.360 ;
        RECT 2.000 932.640 1499.535 933.960 ;
        RECT 2.400 931.240 1499.535 932.640 ;
        RECT 2.000 929.920 1499.535 931.240 ;
        RECT 2.000 928.560 1497.600 929.920 ;
        RECT 2.400 928.520 1497.600 928.560 ;
        RECT 2.400 927.160 1499.535 928.520 ;
        RECT 2.000 924.480 1499.535 927.160 ;
        RECT 2.000 923.120 1497.600 924.480 ;
        RECT 2.400 923.080 1497.600 923.120 ;
        RECT 2.400 921.720 1499.535 923.080 ;
        RECT 2.000 920.400 1499.535 921.720 ;
        RECT 2.000 919.000 1497.600 920.400 ;
        RECT 2.000 917.680 1499.535 919.000 ;
        RECT 2.400 916.280 1499.535 917.680 ;
        RECT 2.000 914.960 1499.535 916.280 ;
        RECT 2.000 913.560 1497.600 914.960 ;
        RECT 2.000 912.240 1499.535 913.560 ;
        RECT 2.400 910.840 1499.535 912.240 ;
        RECT 2.000 909.520 1499.535 910.840 ;
        RECT 2.000 908.160 1497.600 909.520 ;
        RECT 2.400 908.120 1497.600 908.160 ;
        RECT 2.400 906.760 1499.535 908.120 ;
        RECT 2.000 905.440 1499.535 906.760 ;
        RECT 2.000 904.040 1497.600 905.440 ;
        RECT 2.000 902.720 1499.535 904.040 ;
        RECT 2.400 901.320 1499.535 902.720 ;
        RECT 2.000 900.000 1499.535 901.320 ;
        RECT 2.000 898.600 1497.600 900.000 ;
        RECT 2.000 897.280 1499.535 898.600 ;
        RECT 2.400 895.880 1499.535 897.280 ;
        RECT 2.000 894.560 1499.535 895.880 ;
        RECT 2.000 893.200 1497.600 894.560 ;
        RECT 2.400 893.160 1497.600 893.200 ;
        RECT 2.400 891.800 1499.535 893.160 ;
        RECT 2.000 889.120 1499.535 891.800 ;
        RECT 2.000 887.760 1497.600 889.120 ;
        RECT 2.400 887.720 1497.600 887.760 ;
        RECT 2.400 886.360 1499.535 887.720 ;
        RECT 2.000 885.040 1499.535 886.360 ;
        RECT 2.000 883.640 1497.600 885.040 ;
        RECT 2.000 882.320 1499.535 883.640 ;
        RECT 2.400 880.920 1499.535 882.320 ;
        RECT 2.000 879.600 1499.535 880.920 ;
        RECT 2.000 878.200 1497.600 879.600 ;
        RECT 2.000 876.880 1499.535 878.200 ;
        RECT 2.400 875.480 1499.535 876.880 ;
        RECT 2.000 874.160 1499.535 875.480 ;
        RECT 2.000 872.800 1497.600 874.160 ;
        RECT 2.400 872.760 1497.600 872.800 ;
        RECT 2.400 871.400 1499.535 872.760 ;
        RECT 2.000 868.720 1499.535 871.400 ;
        RECT 2.000 867.360 1497.600 868.720 ;
        RECT 2.400 867.320 1497.600 867.360 ;
        RECT 2.400 865.960 1499.535 867.320 ;
        RECT 2.000 864.640 1499.535 865.960 ;
        RECT 2.000 863.240 1497.600 864.640 ;
        RECT 2.000 861.920 1499.535 863.240 ;
        RECT 2.400 860.520 1499.535 861.920 ;
        RECT 2.000 859.200 1499.535 860.520 ;
        RECT 2.000 857.800 1497.600 859.200 ;
        RECT 2.000 856.480 1499.535 857.800 ;
        RECT 2.400 855.080 1499.535 856.480 ;
        RECT 2.000 853.760 1499.535 855.080 ;
        RECT 2.000 852.400 1497.600 853.760 ;
        RECT 2.400 852.360 1497.600 852.400 ;
        RECT 2.400 851.000 1499.535 852.360 ;
        RECT 2.000 848.320 1499.535 851.000 ;
        RECT 2.000 846.960 1497.600 848.320 ;
        RECT 2.400 846.920 1497.600 846.960 ;
        RECT 2.400 845.560 1499.535 846.920 ;
        RECT 2.000 844.240 1499.535 845.560 ;
        RECT 2.000 842.840 1497.600 844.240 ;
        RECT 2.000 841.520 1499.535 842.840 ;
        RECT 2.400 840.120 1499.535 841.520 ;
        RECT 2.000 838.800 1499.535 840.120 ;
        RECT 2.000 837.440 1497.600 838.800 ;
        RECT 2.400 837.400 1497.600 837.440 ;
        RECT 2.400 836.040 1499.535 837.400 ;
        RECT 2.000 833.360 1499.535 836.040 ;
        RECT 2.000 832.000 1497.600 833.360 ;
        RECT 2.400 831.960 1497.600 832.000 ;
        RECT 2.400 830.600 1499.535 831.960 ;
        RECT 2.000 829.280 1499.535 830.600 ;
        RECT 2.000 827.880 1497.600 829.280 ;
        RECT 2.000 826.560 1499.535 827.880 ;
        RECT 2.400 825.160 1499.535 826.560 ;
        RECT 2.000 823.840 1499.535 825.160 ;
        RECT 2.000 822.440 1497.600 823.840 ;
        RECT 2.000 821.120 1499.535 822.440 ;
        RECT 2.400 819.720 1499.535 821.120 ;
        RECT 2.000 818.400 1499.535 819.720 ;
        RECT 2.000 817.040 1497.600 818.400 ;
        RECT 2.400 817.000 1497.600 817.040 ;
        RECT 2.400 815.640 1499.535 817.000 ;
        RECT 2.000 812.960 1499.535 815.640 ;
        RECT 2.000 811.600 1497.600 812.960 ;
        RECT 2.400 811.560 1497.600 811.600 ;
        RECT 2.400 810.200 1499.535 811.560 ;
        RECT 2.000 808.880 1499.535 810.200 ;
        RECT 2.000 807.480 1497.600 808.880 ;
        RECT 2.000 806.160 1499.535 807.480 ;
        RECT 2.400 804.760 1499.535 806.160 ;
        RECT 2.000 803.440 1499.535 804.760 ;
        RECT 2.000 802.040 1497.600 803.440 ;
        RECT 2.000 800.720 1499.535 802.040 ;
        RECT 2.400 799.320 1499.535 800.720 ;
        RECT 2.000 798.000 1499.535 799.320 ;
        RECT 2.000 796.640 1497.600 798.000 ;
        RECT 2.400 796.600 1497.600 796.640 ;
        RECT 2.400 795.240 1499.535 796.600 ;
        RECT 2.000 792.560 1499.535 795.240 ;
        RECT 2.000 791.200 1497.600 792.560 ;
        RECT 2.400 791.160 1497.600 791.200 ;
        RECT 2.400 789.800 1499.535 791.160 ;
        RECT 2.000 788.480 1499.535 789.800 ;
        RECT 2.000 787.080 1497.600 788.480 ;
        RECT 2.000 785.760 1499.535 787.080 ;
        RECT 2.400 784.360 1499.535 785.760 ;
        RECT 2.000 783.040 1499.535 784.360 ;
        RECT 2.000 781.680 1497.600 783.040 ;
        RECT 2.400 781.640 1497.600 781.680 ;
        RECT 2.400 780.280 1499.535 781.640 ;
        RECT 2.000 777.600 1499.535 780.280 ;
        RECT 2.000 776.240 1497.600 777.600 ;
        RECT 2.400 776.200 1497.600 776.240 ;
        RECT 2.400 774.840 1499.535 776.200 ;
        RECT 2.000 773.520 1499.535 774.840 ;
        RECT 2.000 772.120 1497.600 773.520 ;
        RECT 2.000 770.800 1499.535 772.120 ;
        RECT 2.400 769.400 1499.535 770.800 ;
        RECT 2.000 768.080 1499.535 769.400 ;
        RECT 2.000 766.680 1497.600 768.080 ;
        RECT 2.000 765.360 1499.535 766.680 ;
        RECT 2.400 763.960 1499.535 765.360 ;
        RECT 2.000 762.640 1499.535 763.960 ;
        RECT 2.000 761.280 1497.600 762.640 ;
        RECT 2.400 761.240 1497.600 761.280 ;
        RECT 2.400 759.880 1499.535 761.240 ;
        RECT 2.000 757.200 1499.535 759.880 ;
        RECT 2.000 755.840 1497.600 757.200 ;
        RECT 2.400 755.800 1497.600 755.840 ;
        RECT 2.400 754.440 1499.535 755.800 ;
        RECT 2.000 753.120 1499.535 754.440 ;
        RECT 2.000 751.720 1497.600 753.120 ;
        RECT 2.000 750.400 1499.535 751.720 ;
        RECT 2.400 749.000 1499.535 750.400 ;
        RECT 2.000 747.680 1499.535 749.000 ;
        RECT 2.000 746.280 1497.600 747.680 ;
        RECT 2.000 744.960 1499.535 746.280 ;
        RECT 2.400 743.560 1499.535 744.960 ;
        RECT 2.000 742.240 1499.535 743.560 ;
        RECT 2.000 740.880 1497.600 742.240 ;
        RECT 2.400 740.840 1497.600 740.880 ;
        RECT 2.400 739.480 1499.535 740.840 ;
        RECT 2.000 736.800 1499.535 739.480 ;
        RECT 2.000 735.440 1497.600 736.800 ;
        RECT 2.400 735.400 1497.600 735.440 ;
        RECT 2.400 734.040 1499.535 735.400 ;
        RECT 2.000 732.720 1499.535 734.040 ;
        RECT 2.000 731.320 1497.600 732.720 ;
        RECT 2.000 730.000 1499.535 731.320 ;
        RECT 2.400 728.600 1499.535 730.000 ;
        RECT 2.000 727.280 1499.535 728.600 ;
        RECT 2.000 725.920 1497.600 727.280 ;
        RECT 2.400 725.880 1497.600 725.920 ;
        RECT 2.400 724.520 1499.535 725.880 ;
        RECT 2.000 721.840 1499.535 724.520 ;
        RECT 2.000 720.480 1497.600 721.840 ;
        RECT 2.400 720.440 1497.600 720.480 ;
        RECT 2.400 719.080 1499.535 720.440 ;
        RECT 2.000 717.760 1499.535 719.080 ;
        RECT 2.000 716.360 1497.600 717.760 ;
        RECT 2.000 715.040 1499.535 716.360 ;
        RECT 2.400 713.640 1499.535 715.040 ;
        RECT 2.000 712.320 1499.535 713.640 ;
        RECT 2.000 710.920 1497.600 712.320 ;
        RECT 2.000 709.600 1499.535 710.920 ;
        RECT 2.400 708.200 1499.535 709.600 ;
        RECT 2.000 706.880 1499.535 708.200 ;
        RECT 2.000 705.520 1497.600 706.880 ;
        RECT 2.400 705.480 1497.600 705.520 ;
        RECT 2.400 704.120 1499.535 705.480 ;
        RECT 2.000 701.440 1499.535 704.120 ;
        RECT 2.000 700.080 1497.600 701.440 ;
        RECT 2.400 700.040 1497.600 700.080 ;
        RECT 2.400 698.680 1499.535 700.040 ;
        RECT 2.000 697.360 1499.535 698.680 ;
        RECT 2.000 695.960 1497.600 697.360 ;
        RECT 2.000 694.640 1499.535 695.960 ;
        RECT 2.400 693.240 1499.535 694.640 ;
        RECT 2.000 691.920 1499.535 693.240 ;
        RECT 2.000 690.520 1497.600 691.920 ;
        RECT 2.000 689.200 1499.535 690.520 ;
        RECT 2.400 687.800 1499.535 689.200 ;
        RECT 2.000 686.480 1499.535 687.800 ;
        RECT 2.000 685.120 1497.600 686.480 ;
        RECT 2.400 685.080 1497.600 685.120 ;
        RECT 2.400 683.720 1499.535 685.080 ;
        RECT 2.000 681.040 1499.535 683.720 ;
        RECT 2.000 679.680 1497.600 681.040 ;
        RECT 2.400 679.640 1497.600 679.680 ;
        RECT 2.400 678.280 1499.535 679.640 ;
        RECT 2.000 676.960 1499.535 678.280 ;
        RECT 2.000 675.560 1497.600 676.960 ;
        RECT 2.000 674.240 1499.535 675.560 ;
        RECT 2.400 672.840 1499.535 674.240 ;
        RECT 2.000 671.520 1499.535 672.840 ;
        RECT 2.000 670.160 1497.600 671.520 ;
        RECT 2.400 670.120 1497.600 670.160 ;
        RECT 2.400 668.760 1499.535 670.120 ;
        RECT 2.000 666.080 1499.535 668.760 ;
        RECT 2.000 664.720 1497.600 666.080 ;
        RECT 2.400 664.680 1497.600 664.720 ;
        RECT 2.400 663.320 1499.535 664.680 ;
        RECT 2.000 662.000 1499.535 663.320 ;
        RECT 2.000 660.600 1497.600 662.000 ;
        RECT 2.000 659.280 1499.535 660.600 ;
        RECT 2.400 657.880 1499.535 659.280 ;
        RECT 2.000 656.560 1499.535 657.880 ;
        RECT 2.000 655.160 1497.600 656.560 ;
        RECT 2.000 653.840 1499.535 655.160 ;
        RECT 2.400 652.440 1499.535 653.840 ;
        RECT 2.000 651.120 1499.535 652.440 ;
        RECT 2.000 649.760 1497.600 651.120 ;
        RECT 2.400 649.720 1497.600 649.760 ;
        RECT 2.400 648.360 1499.535 649.720 ;
        RECT 2.000 645.680 1499.535 648.360 ;
        RECT 2.000 644.320 1497.600 645.680 ;
        RECT 2.400 644.280 1497.600 644.320 ;
        RECT 2.400 642.920 1499.535 644.280 ;
        RECT 2.000 641.600 1499.535 642.920 ;
        RECT 2.000 640.200 1497.600 641.600 ;
        RECT 2.000 638.880 1499.535 640.200 ;
        RECT 2.400 637.480 1499.535 638.880 ;
        RECT 2.000 636.160 1499.535 637.480 ;
        RECT 2.000 634.760 1497.600 636.160 ;
        RECT 2.000 633.440 1499.535 634.760 ;
        RECT 2.400 632.040 1499.535 633.440 ;
        RECT 2.000 630.720 1499.535 632.040 ;
        RECT 2.000 629.360 1497.600 630.720 ;
        RECT 2.400 629.320 1497.600 629.360 ;
        RECT 2.400 627.960 1499.535 629.320 ;
        RECT 2.000 625.280 1499.535 627.960 ;
        RECT 2.000 623.920 1497.600 625.280 ;
        RECT 2.400 623.880 1497.600 623.920 ;
        RECT 2.400 622.520 1499.535 623.880 ;
        RECT 2.000 621.200 1499.535 622.520 ;
        RECT 2.000 619.800 1497.600 621.200 ;
        RECT 2.000 618.480 1499.535 619.800 ;
        RECT 2.400 617.080 1499.535 618.480 ;
        RECT 2.000 615.760 1499.535 617.080 ;
        RECT 2.000 614.400 1497.600 615.760 ;
        RECT 2.400 614.360 1497.600 614.400 ;
        RECT 2.400 613.000 1499.535 614.360 ;
        RECT 2.000 610.320 1499.535 613.000 ;
        RECT 2.000 608.960 1497.600 610.320 ;
        RECT 2.400 608.920 1497.600 608.960 ;
        RECT 2.400 607.560 1499.535 608.920 ;
        RECT 2.000 606.240 1499.535 607.560 ;
        RECT 2.000 604.840 1497.600 606.240 ;
        RECT 2.000 603.520 1499.535 604.840 ;
        RECT 2.400 602.120 1499.535 603.520 ;
        RECT 2.000 600.800 1499.535 602.120 ;
        RECT 2.000 599.400 1497.600 600.800 ;
        RECT 2.000 598.080 1499.535 599.400 ;
        RECT 2.400 596.680 1499.535 598.080 ;
        RECT 2.000 595.360 1499.535 596.680 ;
        RECT 2.000 594.000 1497.600 595.360 ;
        RECT 2.400 593.960 1497.600 594.000 ;
        RECT 2.400 592.600 1499.535 593.960 ;
        RECT 2.000 589.920 1499.535 592.600 ;
        RECT 2.000 588.560 1497.600 589.920 ;
        RECT 2.400 588.520 1497.600 588.560 ;
        RECT 2.400 587.160 1499.535 588.520 ;
        RECT 2.000 585.840 1499.535 587.160 ;
        RECT 2.000 584.440 1497.600 585.840 ;
        RECT 2.000 583.120 1499.535 584.440 ;
        RECT 2.400 581.720 1499.535 583.120 ;
        RECT 2.000 580.400 1499.535 581.720 ;
        RECT 2.000 579.000 1497.600 580.400 ;
        RECT 2.000 577.680 1499.535 579.000 ;
        RECT 2.400 576.280 1499.535 577.680 ;
        RECT 2.000 574.960 1499.535 576.280 ;
        RECT 2.000 573.600 1497.600 574.960 ;
        RECT 2.400 573.560 1497.600 573.600 ;
        RECT 2.400 572.200 1499.535 573.560 ;
        RECT 2.000 569.520 1499.535 572.200 ;
        RECT 2.000 568.160 1497.600 569.520 ;
        RECT 2.400 568.120 1497.600 568.160 ;
        RECT 2.400 566.760 1499.535 568.120 ;
        RECT 2.000 565.440 1499.535 566.760 ;
        RECT 2.000 564.040 1497.600 565.440 ;
        RECT 2.000 562.720 1499.535 564.040 ;
        RECT 2.400 561.320 1499.535 562.720 ;
        RECT 2.000 560.000 1499.535 561.320 ;
        RECT 2.000 558.640 1497.600 560.000 ;
        RECT 2.400 558.600 1497.600 558.640 ;
        RECT 2.400 557.240 1499.535 558.600 ;
        RECT 2.000 554.560 1499.535 557.240 ;
        RECT 2.000 553.200 1497.600 554.560 ;
        RECT 2.400 553.160 1497.600 553.200 ;
        RECT 2.400 551.800 1499.535 553.160 ;
        RECT 2.000 550.480 1499.535 551.800 ;
        RECT 2.000 549.080 1497.600 550.480 ;
        RECT 2.000 547.760 1499.535 549.080 ;
        RECT 2.400 546.360 1499.535 547.760 ;
        RECT 2.000 545.040 1499.535 546.360 ;
        RECT 2.000 543.640 1497.600 545.040 ;
        RECT 2.000 542.320 1499.535 543.640 ;
        RECT 2.400 540.920 1499.535 542.320 ;
        RECT 2.000 539.600 1499.535 540.920 ;
        RECT 2.000 538.240 1497.600 539.600 ;
        RECT 2.400 538.200 1497.600 538.240 ;
        RECT 2.400 536.840 1499.535 538.200 ;
        RECT 2.000 534.160 1499.535 536.840 ;
        RECT 2.000 532.800 1497.600 534.160 ;
        RECT 2.400 532.760 1497.600 532.800 ;
        RECT 2.400 531.400 1499.535 532.760 ;
        RECT 2.000 530.080 1499.535 531.400 ;
        RECT 2.000 528.680 1497.600 530.080 ;
        RECT 2.000 527.360 1499.535 528.680 ;
        RECT 2.400 525.960 1499.535 527.360 ;
        RECT 2.000 524.640 1499.535 525.960 ;
        RECT 2.000 523.240 1497.600 524.640 ;
        RECT 2.000 521.920 1499.535 523.240 ;
        RECT 2.400 520.520 1499.535 521.920 ;
        RECT 2.000 519.200 1499.535 520.520 ;
        RECT 2.000 517.840 1497.600 519.200 ;
        RECT 2.400 517.800 1497.600 517.840 ;
        RECT 2.400 516.440 1499.535 517.800 ;
        RECT 2.000 513.760 1499.535 516.440 ;
        RECT 2.000 512.400 1497.600 513.760 ;
        RECT 2.400 512.360 1497.600 512.400 ;
        RECT 2.400 511.000 1499.535 512.360 ;
        RECT 2.000 509.680 1499.535 511.000 ;
        RECT 2.000 508.280 1497.600 509.680 ;
        RECT 2.000 506.960 1499.535 508.280 ;
        RECT 2.400 505.560 1499.535 506.960 ;
        RECT 2.000 504.240 1499.535 505.560 ;
        RECT 2.000 502.880 1497.600 504.240 ;
        RECT 2.400 502.840 1497.600 502.880 ;
        RECT 2.400 501.480 1499.535 502.840 ;
        RECT 2.000 498.800 1499.535 501.480 ;
        RECT 2.000 497.440 1497.600 498.800 ;
        RECT 2.400 497.400 1497.600 497.440 ;
        RECT 2.400 496.040 1499.535 497.400 ;
        RECT 2.000 494.720 1499.535 496.040 ;
        RECT 2.000 493.320 1497.600 494.720 ;
        RECT 2.000 492.000 1499.535 493.320 ;
        RECT 2.400 490.600 1499.535 492.000 ;
        RECT 2.000 489.280 1499.535 490.600 ;
        RECT 2.000 487.880 1497.600 489.280 ;
        RECT 2.000 486.560 1499.535 487.880 ;
        RECT 2.400 485.160 1499.535 486.560 ;
        RECT 2.000 483.840 1499.535 485.160 ;
        RECT 2.000 482.480 1497.600 483.840 ;
        RECT 2.400 482.440 1497.600 482.480 ;
        RECT 2.400 481.080 1499.535 482.440 ;
        RECT 2.000 478.400 1499.535 481.080 ;
        RECT 2.000 477.040 1497.600 478.400 ;
        RECT 2.400 477.000 1497.600 477.040 ;
        RECT 2.400 475.640 1499.535 477.000 ;
        RECT 2.000 474.320 1499.535 475.640 ;
        RECT 2.000 472.920 1497.600 474.320 ;
        RECT 2.000 471.600 1499.535 472.920 ;
        RECT 2.400 470.200 1499.535 471.600 ;
        RECT 2.000 468.880 1499.535 470.200 ;
        RECT 2.000 467.480 1497.600 468.880 ;
        RECT 2.000 466.160 1499.535 467.480 ;
        RECT 2.400 464.760 1499.535 466.160 ;
        RECT 2.000 463.440 1499.535 464.760 ;
        RECT 2.000 462.080 1497.600 463.440 ;
        RECT 2.400 462.040 1497.600 462.080 ;
        RECT 2.400 460.680 1499.535 462.040 ;
        RECT 2.000 458.000 1499.535 460.680 ;
        RECT 2.000 456.640 1497.600 458.000 ;
        RECT 2.400 456.600 1497.600 456.640 ;
        RECT 2.400 455.240 1499.535 456.600 ;
        RECT 2.000 453.920 1499.535 455.240 ;
        RECT 2.000 452.520 1497.600 453.920 ;
        RECT 2.000 451.200 1499.535 452.520 ;
        RECT 2.400 449.800 1499.535 451.200 ;
        RECT 2.000 448.480 1499.535 449.800 ;
        RECT 2.000 447.120 1497.600 448.480 ;
        RECT 2.400 447.080 1497.600 447.120 ;
        RECT 2.400 445.720 1499.535 447.080 ;
        RECT 2.000 443.040 1499.535 445.720 ;
        RECT 2.000 441.680 1497.600 443.040 ;
        RECT 2.400 441.640 1497.600 441.680 ;
        RECT 2.400 440.280 1499.535 441.640 ;
        RECT 2.000 438.960 1499.535 440.280 ;
        RECT 2.000 437.560 1497.600 438.960 ;
        RECT 2.000 436.240 1499.535 437.560 ;
        RECT 2.400 434.840 1499.535 436.240 ;
        RECT 2.000 433.520 1499.535 434.840 ;
        RECT 2.000 432.120 1497.600 433.520 ;
        RECT 2.000 430.800 1499.535 432.120 ;
        RECT 2.400 429.400 1499.535 430.800 ;
        RECT 2.000 428.080 1499.535 429.400 ;
        RECT 2.000 426.720 1497.600 428.080 ;
        RECT 2.400 426.680 1497.600 426.720 ;
        RECT 2.400 425.320 1499.535 426.680 ;
        RECT 2.000 422.640 1499.535 425.320 ;
        RECT 2.000 421.280 1497.600 422.640 ;
        RECT 2.400 421.240 1497.600 421.280 ;
        RECT 2.400 419.880 1499.535 421.240 ;
        RECT 2.000 418.560 1499.535 419.880 ;
        RECT 2.000 417.160 1497.600 418.560 ;
        RECT 2.000 415.840 1499.535 417.160 ;
        RECT 2.400 414.440 1499.535 415.840 ;
        RECT 2.000 413.120 1499.535 414.440 ;
        RECT 2.000 411.720 1497.600 413.120 ;
        RECT 2.000 410.400 1499.535 411.720 ;
        RECT 2.400 409.000 1499.535 410.400 ;
        RECT 2.000 407.680 1499.535 409.000 ;
        RECT 2.000 406.320 1497.600 407.680 ;
        RECT 2.400 406.280 1497.600 406.320 ;
        RECT 2.400 404.920 1499.535 406.280 ;
        RECT 2.000 402.240 1499.535 404.920 ;
        RECT 2.000 400.880 1497.600 402.240 ;
        RECT 2.400 400.840 1497.600 400.880 ;
        RECT 2.400 399.480 1499.535 400.840 ;
        RECT 2.000 398.160 1499.535 399.480 ;
        RECT 2.000 396.760 1497.600 398.160 ;
        RECT 2.000 395.440 1499.535 396.760 ;
        RECT 2.400 394.040 1499.535 395.440 ;
        RECT 2.000 392.720 1499.535 394.040 ;
        RECT 2.000 391.360 1497.600 392.720 ;
        RECT 2.400 391.320 1497.600 391.360 ;
        RECT 2.400 389.960 1499.535 391.320 ;
        RECT 2.000 387.280 1499.535 389.960 ;
        RECT 2.000 385.920 1497.600 387.280 ;
        RECT 2.400 385.880 1497.600 385.920 ;
        RECT 2.400 384.520 1499.535 385.880 ;
        RECT 2.000 383.200 1499.535 384.520 ;
        RECT 2.000 381.800 1497.600 383.200 ;
        RECT 2.000 380.480 1499.535 381.800 ;
        RECT 2.400 379.080 1499.535 380.480 ;
        RECT 2.000 377.760 1499.535 379.080 ;
        RECT 2.000 376.360 1497.600 377.760 ;
        RECT 2.000 375.040 1499.535 376.360 ;
        RECT 2.400 373.640 1499.535 375.040 ;
        RECT 2.000 372.320 1499.535 373.640 ;
        RECT 2.000 370.960 1497.600 372.320 ;
        RECT 2.400 370.920 1497.600 370.960 ;
        RECT 2.400 369.560 1499.535 370.920 ;
        RECT 2.000 366.880 1499.535 369.560 ;
        RECT 2.000 365.520 1497.600 366.880 ;
        RECT 2.400 365.480 1497.600 365.520 ;
        RECT 2.400 364.120 1499.535 365.480 ;
        RECT 2.000 362.800 1499.535 364.120 ;
        RECT 2.000 361.400 1497.600 362.800 ;
        RECT 2.000 360.080 1499.535 361.400 ;
        RECT 2.400 358.680 1499.535 360.080 ;
        RECT 2.000 357.360 1499.535 358.680 ;
        RECT 2.000 355.960 1497.600 357.360 ;
        RECT 2.000 354.640 1499.535 355.960 ;
        RECT 2.400 353.240 1499.535 354.640 ;
        RECT 2.000 351.920 1499.535 353.240 ;
        RECT 2.000 350.560 1497.600 351.920 ;
        RECT 2.400 350.520 1497.600 350.560 ;
        RECT 2.400 349.160 1499.535 350.520 ;
        RECT 2.000 346.480 1499.535 349.160 ;
        RECT 2.000 345.120 1497.600 346.480 ;
        RECT 2.400 345.080 1497.600 345.120 ;
        RECT 2.400 343.720 1499.535 345.080 ;
        RECT 2.000 342.400 1499.535 343.720 ;
        RECT 2.000 341.000 1497.600 342.400 ;
        RECT 2.000 339.680 1499.535 341.000 ;
        RECT 2.400 338.280 1499.535 339.680 ;
        RECT 2.000 336.960 1499.535 338.280 ;
        RECT 2.000 335.600 1497.600 336.960 ;
        RECT 2.400 335.560 1497.600 335.600 ;
        RECT 2.400 334.200 1499.535 335.560 ;
        RECT 2.000 331.520 1499.535 334.200 ;
        RECT 2.000 330.160 1497.600 331.520 ;
        RECT 2.400 330.120 1497.600 330.160 ;
        RECT 2.400 328.760 1499.535 330.120 ;
        RECT 2.000 327.440 1499.535 328.760 ;
        RECT 2.000 326.040 1497.600 327.440 ;
        RECT 2.000 324.720 1499.535 326.040 ;
        RECT 2.400 323.320 1499.535 324.720 ;
        RECT 2.000 322.000 1499.535 323.320 ;
        RECT 2.000 320.600 1497.600 322.000 ;
        RECT 2.000 319.280 1499.535 320.600 ;
        RECT 2.400 317.880 1499.535 319.280 ;
        RECT 2.000 316.560 1499.535 317.880 ;
        RECT 2.000 315.200 1497.600 316.560 ;
        RECT 2.400 315.160 1497.600 315.200 ;
        RECT 2.400 313.800 1499.535 315.160 ;
        RECT 2.000 311.120 1499.535 313.800 ;
        RECT 2.000 309.760 1497.600 311.120 ;
        RECT 2.400 309.720 1497.600 309.760 ;
        RECT 2.400 308.360 1499.535 309.720 ;
        RECT 2.000 307.040 1499.535 308.360 ;
        RECT 2.000 305.640 1497.600 307.040 ;
        RECT 2.000 304.320 1499.535 305.640 ;
        RECT 2.400 302.920 1499.535 304.320 ;
        RECT 2.000 301.600 1499.535 302.920 ;
        RECT 2.000 300.200 1497.600 301.600 ;
        RECT 2.000 298.880 1499.535 300.200 ;
        RECT 2.400 297.480 1499.535 298.880 ;
        RECT 2.000 296.160 1499.535 297.480 ;
        RECT 2.000 294.800 1497.600 296.160 ;
        RECT 2.400 294.760 1497.600 294.800 ;
        RECT 2.400 293.400 1499.535 294.760 ;
        RECT 2.000 290.720 1499.535 293.400 ;
        RECT 2.000 289.360 1497.600 290.720 ;
        RECT 2.400 289.320 1497.600 289.360 ;
        RECT 2.400 287.960 1499.535 289.320 ;
        RECT 2.000 286.640 1499.535 287.960 ;
        RECT 2.000 285.240 1497.600 286.640 ;
        RECT 2.000 283.920 1499.535 285.240 ;
        RECT 2.400 282.520 1499.535 283.920 ;
        RECT 2.000 281.200 1499.535 282.520 ;
        RECT 2.000 279.840 1497.600 281.200 ;
        RECT 2.400 279.800 1497.600 279.840 ;
        RECT 2.400 278.440 1499.535 279.800 ;
        RECT 2.000 275.760 1499.535 278.440 ;
        RECT 2.000 274.400 1497.600 275.760 ;
        RECT 2.400 274.360 1497.600 274.400 ;
        RECT 2.400 273.000 1499.535 274.360 ;
        RECT 2.000 271.680 1499.535 273.000 ;
        RECT 2.000 270.280 1497.600 271.680 ;
        RECT 2.000 268.960 1499.535 270.280 ;
        RECT 2.400 267.560 1499.535 268.960 ;
        RECT 2.000 266.240 1499.535 267.560 ;
        RECT 2.000 264.840 1497.600 266.240 ;
        RECT 2.000 263.520 1499.535 264.840 ;
        RECT 2.400 262.120 1499.535 263.520 ;
        RECT 2.000 260.800 1499.535 262.120 ;
        RECT 2.000 259.440 1497.600 260.800 ;
        RECT 2.400 259.400 1497.600 259.440 ;
        RECT 2.400 258.040 1499.535 259.400 ;
        RECT 2.000 255.360 1499.535 258.040 ;
        RECT 2.000 254.000 1497.600 255.360 ;
        RECT 2.400 253.960 1497.600 254.000 ;
        RECT 2.400 252.600 1499.535 253.960 ;
        RECT 2.000 251.280 1499.535 252.600 ;
        RECT 2.000 249.880 1497.600 251.280 ;
        RECT 2.000 248.560 1499.535 249.880 ;
        RECT 2.400 247.160 1499.535 248.560 ;
        RECT 2.000 245.840 1499.535 247.160 ;
        RECT 2.000 244.440 1497.600 245.840 ;
        RECT 2.000 243.120 1499.535 244.440 ;
        RECT 2.400 241.720 1499.535 243.120 ;
        RECT 2.000 240.400 1499.535 241.720 ;
        RECT 2.000 239.040 1497.600 240.400 ;
        RECT 2.400 239.000 1497.600 239.040 ;
        RECT 2.400 237.640 1499.535 239.000 ;
        RECT 2.000 234.960 1499.535 237.640 ;
        RECT 2.000 233.600 1497.600 234.960 ;
        RECT 2.400 233.560 1497.600 233.600 ;
        RECT 2.400 232.200 1499.535 233.560 ;
        RECT 2.000 230.880 1499.535 232.200 ;
        RECT 2.000 229.480 1497.600 230.880 ;
        RECT 2.000 228.160 1499.535 229.480 ;
        RECT 2.400 226.760 1499.535 228.160 ;
        RECT 2.000 225.440 1499.535 226.760 ;
        RECT 2.000 224.080 1497.600 225.440 ;
        RECT 2.400 224.040 1497.600 224.080 ;
        RECT 2.400 222.680 1499.535 224.040 ;
        RECT 2.000 220.000 1499.535 222.680 ;
        RECT 2.000 218.640 1497.600 220.000 ;
        RECT 2.400 218.600 1497.600 218.640 ;
        RECT 2.400 217.240 1499.535 218.600 ;
        RECT 2.000 215.920 1499.535 217.240 ;
        RECT 2.000 214.520 1497.600 215.920 ;
        RECT 2.000 213.200 1499.535 214.520 ;
        RECT 2.400 211.800 1499.535 213.200 ;
        RECT 2.000 210.480 1499.535 211.800 ;
        RECT 2.000 209.080 1497.600 210.480 ;
        RECT 2.000 207.760 1499.535 209.080 ;
        RECT 2.400 206.360 1499.535 207.760 ;
        RECT 2.000 205.040 1499.535 206.360 ;
        RECT 2.000 203.680 1497.600 205.040 ;
        RECT 2.400 203.640 1497.600 203.680 ;
        RECT 2.400 202.280 1499.535 203.640 ;
        RECT 2.000 199.600 1499.535 202.280 ;
        RECT 2.000 198.240 1497.600 199.600 ;
        RECT 2.400 198.200 1497.600 198.240 ;
        RECT 2.400 196.840 1499.535 198.200 ;
        RECT 2.000 195.520 1499.535 196.840 ;
        RECT 2.000 194.120 1497.600 195.520 ;
        RECT 2.000 192.800 1499.535 194.120 ;
        RECT 2.400 191.400 1499.535 192.800 ;
        RECT 2.000 190.080 1499.535 191.400 ;
        RECT 2.000 188.680 1497.600 190.080 ;
        RECT 2.000 187.360 1499.535 188.680 ;
        RECT 2.400 185.960 1499.535 187.360 ;
        RECT 2.000 184.640 1499.535 185.960 ;
        RECT 2.000 183.280 1497.600 184.640 ;
        RECT 2.400 183.240 1497.600 183.280 ;
        RECT 2.400 181.880 1499.535 183.240 ;
        RECT 2.000 179.200 1499.535 181.880 ;
        RECT 2.000 177.840 1497.600 179.200 ;
        RECT 2.400 177.800 1497.600 177.840 ;
        RECT 2.400 176.440 1499.535 177.800 ;
        RECT 2.000 175.120 1499.535 176.440 ;
        RECT 2.000 173.720 1497.600 175.120 ;
        RECT 2.000 172.400 1499.535 173.720 ;
        RECT 2.400 171.000 1499.535 172.400 ;
        RECT 2.000 169.680 1499.535 171.000 ;
        RECT 2.000 168.320 1497.600 169.680 ;
        RECT 2.400 168.280 1497.600 168.320 ;
        RECT 2.400 166.920 1499.535 168.280 ;
        RECT 2.000 164.240 1499.535 166.920 ;
        RECT 2.000 162.880 1497.600 164.240 ;
        RECT 2.400 162.840 1497.600 162.880 ;
        RECT 2.400 161.480 1499.535 162.840 ;
        RECT 2.000 160.160 1499.535 161.480 ;
        RECT 2.000 158.760 1497.600 160.160 ;
        RECT 2.000 157.440 1499.535 158.760 ;
        RECT 2.400 156.040 1499.535 157.440 ;
        RECT 2.000 154.720 1499.535 156.040 ;
        RECT 2.000 153.320 1497.600 154.720 ;
        RECT 2.000 152.000 1499.535 153.320 ;
        RECT 2.400 150.600 1499.535 152.000 ;
        RECT 2.000 149.280 1499.535 150.600 ;
        RECT 2.000 147.920 1497.600 149.280 ;
        RECT 2.400 147.880 1497.600 147.920 ;
        RECT 2.400 146.520 1499.535 147.880 ;
        RECT 2.000 143.840 1499.535 146.520 ;
        RECT 2.000 142.480 1497.600 143.840 ;
        RECT 2.400 142.440 1497.600 142.480 ;
        RECT 2.400 141.080 1499.535 142.440 ;
        RECT 2.000 139.760 1499.535 141.080 ;
        RECT 2.000 138.360 1497.600 139.760 ;
        RECT 2.000 137.040 1499.535 138.360 ;
        RECT 2.400 135.640 1499.535 137.040 ;
        RECT 2.000 134.320 1499.535 135.640 ;
        RECT 2.000 132.920 1497.600 134.320 ;
        RECT 2.000 131.600 1499.535 132.920 ;
        RECT 2.400 130.200 1499.535 131.600 ;
        RECT 2.000 128.880 1499.535 130.200 ;
        RECT 2.000 127.520 1497.600 128.880 ;
        RECT 2.400 127.480 1497.600 127.520 ;
        RECT 2.400 126.120 1499.535 127.480 ;
        RECT 2.000 123.440 1499.535 126.120 ;
        RECT 2.000 122.080 1497.600 123.440 ;
        RECT 2.400 122.040 1497.600 122.080 ;
        RECT 2.400 120.680 1499.535 122.040 ;
        RECT 2.000 119.360 1499.535 120.680 ;
        RECT 2.000 117.960 1497.600 119.360 ;
        RECT 2.000 116.640 1499.535 117.960 ;
        RECT 2.400 115.240 1499.535 116.640 ;
        RECT 2.000 113.920 1499.535 115.240 ;
        RECT 2.000 112.560 1497.600 113.920 ;
        RECT 2.400 112.520 1497.600 112.560 ;
        RECT 2.400 111.160 1499.535 112.520 ;
        RECT 2.000 108.480 1499.535 111.160 ;
        RECT 2.000 107.120 1497.600 108.480 ;
        RECT 2.400 107.080 1497.600 107.120 ;
        RECT 2.400 105.720 1499.535 107.080 ;
        RECT 2.000 104.400 1499.535 105.720 ;
        RECT 2.000 103.000 1497.600 104.400 ;
        RECT 2.000 101.680 1499.535 103.000 ;
        RECT 2.400 100.280 1499.535 101.680 ;
        RECT 2.000 98.960 1499.535 100.280 ;
        RECT 2.000 97.560 1497.600 98.960 ;
        RECT 2.000 96.240 1499.535 97.560 ;
        RECT 2.400 94.840 1499.535 96.240 ;
        RECT 2.000 93.520 1499.535 94.840 ;
        RECT 2.000 92.160 1497.600 93.520 ;
        RECT 2.400 92.120 1497.600 92.160 ;
        RECT 2.400 90.760 1499.535 92.120 ;
        RECT 2.000 88.080 1499.535 90.760 ;
        RECT 2.000 86.720 1497.600 88.080 ;
        RECT 2.400 86.680 1497.600 86.720 ;
        RECT 2.400 85.320 1499.535 86.680 ;
        RECT 2.000 84.000 1499.535 85.320 ;
        RECT 2.000 82.600 1497.600 84.000 ;
        RECT 2.000 81.280 1499.535 82.600 ;
        RECT 2.400 79.880 1499.535 81.280 ;
        RECT 2.000 78.560 1499.535 79.880 ;
        RECT 2.000 77.160 1497.600 78.560 ;
        RECT 2.000 75.840 1499.535 77.160 ;
        RECT 2.400 74.440 1499.535 75.840 ;
        RECT 2.000 73.120 1499.535 74.440 ;
        RECT 2.000 71.760 1497.600 73.120 ;
        RECT 2.400 71.720 1497.600 71.760 ;
        RECT 2.400 70.360 1499.535 71.720 ;
        RECT 2.000 67.680 1499.535 70.360 ;
        RECT 2.000 66.320 1497.600 67.680 ;
        RECT 2.400 66.280 1497.600 66.320 ;
        RECT 2.400 64.920 1499.535 66.280 ;
        RECT 2.000 63.600 1499.535 64.920 ;
        RECT 2.000 62.200 1497.600 63.600 ;
        RECT 2.000 60.880 1499.535 62.200 ;
        RECT 2.400 59.480 1499.535 60.880 ;
        RECT 2.000 58.160 1499.535 59.480 ;
        RECT 2.000 56.800 1497.600 58.160 ;
        RECT 2.400 56.760 1497.600 56.800 ;
        RECT 2.400 55.400 1499.535 56.760 ;
        RECT 2.000 52.720 1499.535 55.400 ;
        RECT 2.000 51.360 1497.600 52.720 ;
        RECT 2.400 51.320 1497.600 51.360 ;
        RECT 2.400 49.960 1499.535 51.320 ;
        RECT 2.000 48.640 1499.535 49.960 ;
        RECT 2.000 47.240 1497.600 48.640 ;
        RECT 2.000 45.920 1499.535 47.240 ;
        RECT 2.400 44.520 1499.535 45.920 ;
        RECT 2.000 43.200 1499.535 44.520 ;
        RECT 2.000 41.800 1497.600 43.200 ;
        RECT 2.000 40.480 1499.535 41.800 ;
        RECT 2.400 39.080 1499.535 40.480 ;
        RECT 2.000 37.760 1499.535 39.080 ;
        RECT 2.000 36.400 1497.600 37.760 ;
        RECT 2.400 36.360 1497.600 36.400 ;
        RECT 2.400 35.000 1499.535 36.360 ;
        RECT 2.000 32.320 1499.535 35.000 ;
        RECT 2.000 30.960 1497.600 32.320 ;
        RECT 2.400 30.920 1497.600 30.960 ;
        RECT 2.400 29.560 1499.535 30.920 ;
        RECT 2.000 28.240 1499.535 29.560 ;
        RECT 2.000 26.840 1497.600 28.240 ;
        RECT 2.000 25.520 1499.535 26.840 ;
        RECT 2.400 24.120 1499.535 25.520 ;
        RECT 2.000 22.800 1499.535 24.120 ;
        RECT 2.000 21.400 1497.600 22.800 ;
        RECT 2.000 20.080 1499.535 21.400 ;
        RECT 2.400 18.680 1499.535 20.080 ;
        RECT 2.000 17.360 1499.535 18.680 ;
        RECT 2.000 16.000 1497.600 17.360 ;
        RECT 2.400 15.960 1497.600 16.000 ;
        RECT 2.400 14.600 1499.535 15.960 ;
        RECT 2.000 11.920 1499.535 14.600 ;
        RECT 2.000 10.560 1497.600 11.920 ;
        RECT 2.400 10.520 1497.600 10.560 ;
        RECT 2.400 9.160 1499.535 10.520 ;
        RECT 2.000 7.840 1499.535 9.160 ;
        RECT 2.000 6.440 1497.600 7.840 ;
        RECT 2.000 5.120 1499.535 6.440 ;
        RECT 2.400 3.720 1499.535 5.120 ;
        RECT 2.000 2.400 1499.535 3.720 ;
        RECT 2.000 1.000 1497.600 2.400 ;
        RECT 2.000 0.175 1499.535 1.000 ;
      LAYER met4 ;
        RECT 0.790 1488.480 1493.290 1499.225 ;
        RECT 0.790 10.240 25.240 1488.480 ;
        RECT 27.640 10.240 28.540 1488.480 ;
        RECT 30.940 10.240 178.840 1488.480 ;
        RECT 181.240 10.240 182.140 1488.480 ;
        RECT 184.540 10.240 332.440 1488.480 ;
        RECT 334.840 10.240 335.740 1488.480 ;
        RECT 338.140 10.240 486.040 1488.480 ;
        RECT 488.440 10.240 489.340 1488.480 ;
        RECT 491.740 10.240 639.640 1488.480 ;
        RECT 642.040 10.240 642.940 1488.480 ;
        RECT 645.340 10.240 793.240 1488.480 ;
        RECT 795.640 10.240 796.540 1488.480 ;
        RECT 798.940 10.240 946.840 1488.480 ;
        RECT 949.240 10.240 950.140 1488.480 ;
        RECT 952.540 10.240 1100.440 1488.480 ;
        RECT 1102.840 10.240 1103.740 1488.480 ;
        RECT 1106.140 10.240 1254.040 1488.480 ;
        RECT 1256.440 10.240 1257.340 1488.480 ;
        RECT 1259.740 10.240 1407.640 1488.480 ;
        RECT 1410.040 10.240 1410.940 1488.480 ;
        RECT 1413.340 10.240 1493.290 1488.480 ;
        RECT 0.790 0.855 1493.290 10.240 ;
      LAYER met5 ;
        RECT 0.580 1411.850 1493.500 1495.100 ;
        RECT 0.580 1403.750 8.280 1411.850 ;
        RECT 1491.780 1403.750 1493.500 1411.850 ;
        RECT 0.580 1258.670 1493.500 1403.750 ;
        RECT 0.580 1250.570 8.280 1258.670 ;
        RECT 1491.780 1250.570 1493.500 1258.670 ;
        RECT 0.580 1105.490 1493.500 1250.570 ;
        RECT 0.580 1097.390 8.280 1105.490 ;
        RECT 1491.780 1097.390 1493.500 1105.490 ;
        RECT 0.580 952.310 1493.500 1097.390 ;
        RECT 0.580 944.210 8.280 952.310 ;
        RECT 1491.780 944.210 1493.500 952.310 ;
        RECT 0.580 799.130 1493.500 944.210 ;
        RECT 0.580 791.030 8.280 799.130 ;
        RECT 1491.780 791.030 1493.500 799.130 ;
        RECT 0.580 645.950 1493.500 791.030 ;
        RECT 0.580 637.850 8.280 645.950 ;
        RECT 1491.780 637.850 1493.500 645.950 ;
        RECT 0.580 492.770 1493.500 637.850 ;
        RECT 0.580 484.670 8.280 492.770 ;
        RECT 1491.780 484.670 1493.500 492.770 ;
        RECT 0.580 339.590 1493.500 484.670 ;
        RECT 0.580 331.490 8.280 339.590 ;
        RECT 1491.780 331.490 1493.500 339.590 ;
        RECT 0.580 186.410 1493.500 331.490 ;
        RECT 0.580 178.310 8.280 186.410 ;
        RECT 1491.780 178.310 1493.500 186.410 ;
        RECT 0.580 33.230 1493.500 178.310 ;
        RECT 0.580 25.130 8.280 33.230 ;
        RECT 1491.780 25.130 1493.500 33.230 ;
        RECT 0.580 4.300 1493.500 25.130 ;
  END
END can_fd_controller
END LIBRARY

